
VERSION 5.7 ;
BUSBITCHARS "[]" ;
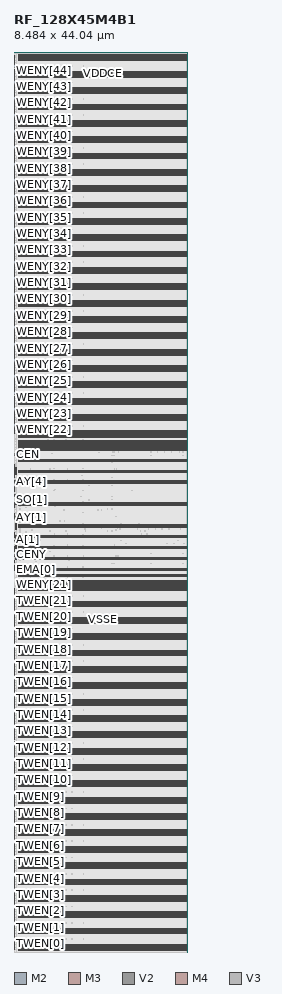
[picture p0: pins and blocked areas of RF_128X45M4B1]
MACRO RF_128X45M4B1
	FOREIGN RF_128X45M4B1 0 0 ;
	SYMMETRY X Y ;
	SIZE 8.484 BY 44.04 ;
	CLASS BLOCK ;
	PIN AY[0]
		USE SIGNAL ;
		DIRECTION OUTPUT ;
		SHAPE ABUTMENT ;
		PORT
			 LAYER M2 ;
			RECT 0.0714 20.819 0.1097 20.8571 ;
			 LAYER M3 ;
			RECT 0.0714 20.819 0.1097 20.9206 ;
			 LAYER V2 ;
			RECT 0.0831 20.8313 0.098 20.844 ;
		END

		ANTENNADIFFAREA 0.00197037 ;
		ANTENNAPARTIALMETALAREA 0.00198 ;
	END AY[0]

	PIN AY[1]
		USE SIGNAL ;
		DIRECTION OUTPUT ;
		SHAPE ABUTMENT ;
		PORT
			 LAYER M2 ;
			RECT 0.0098 21.2762 0.0481 21.3143 ;
			 LAYER M3 ;
			RECT 0.0098 21.2127 0.0481 21.3143 ;
			 LAYER V2 ;
			RECT 0.0215 21.2885 0.0364 21.3012 ;
		END

		ANTENNADIFFAREA 0.00197037 ;
		ANTENNAPARTIALMETALAREA 0.00198 ;
	END AY[1]

	PIN AY[2]
		USE SIGNAL ;
		DIRECTION OUTPUT ;
		SHAPE ABUTMENT ;
		PORT
			 LAYER M2 ;
			RECT 0.0714 21.8857 0.1097 21.9238 ;
			 LAYER M3 ;
			RECT 0.0714 21.8857 0.1097 21.9873 ;
			 LAYER V2 ;
			RECT 0.0831 21.898 0.098 21.9107 ;
		END

		ANTENNADIFFAREA 0.00197037 ;
		ANTENNAPARTIALMETALAREA 0.00198 ;
	END AY[2]

	PIN AY[3]
		USE SIGNAL ;
		DIRECTION OUTPUT ;
		SHAPE ABUTMENT ;
		PORT
			 LAYER M2 ;
			RECT 0.0098 22.3429 0.0481 22.381 ;
			 LAYER M3 ;
			RECT 0.0098 22.2794 0.0481 22.381 ;
			 LAYER V2 ;
			RECT 0.0215 22.3552 0.0364 22.3679 ;
		END

		ANTENNADIFFAREA 0.00197037 ;
		ANTENNAPARTIALMETALAREA 0.00198 ;
	END AY[3]

	PIN AY[4]
		USE SIGNAL ;
		DIRECTION OUTPUT ;
		SHAPE ABUTMENT ;
		PORT
			 LAYER M2 ;
			RECT 0.0714 22.9524 0.1097 22.9905 ;
			 LAYER M3 ;
			RECT 0.0714 22.9524 0.1097 23.054 ;
			 LAYER V2 ;
			RECT 0.0831 22.9647 0.098 22.9774 ;
		END

		ANTENNADIFFAREA 0.00197037 ;
		ANTENNAPARTIALMETALAREA 0.00198 ;
	END AY[4]

	PIN AY[5]
		USE SIGNAL ;
		DIRECTION OUTPUT ;
		SHAPE ABUTMENT ;
		PORT
			 LAYER M2 ;
			RECT 0.0714 23.6127 0.1097 23.6508 ;
			 LAYER M3 ;
			RECT 0.0714 23.6127 0.1097 23.7143 ;
			 LAYER V2 ;
			RECT 0.0831 23.625 0.098 23.6377 ;
		END

		ANTENNADIFFAREA 0.00197037 ;
		ANTENNAPARTIALMETALAREA 0.00198 ;
	END AY[5]

	PIN AY[6]
		USE SIGNAL ;
		DIRECTION OUTPUT ;
		SHAPE ABUTMENT ;
		PORT
			 LAYER M2 ;
			RECT 0.0098 23.4095 0.0481 23.4476 ;
			 LAYER M3 ;
			RECT 0.0098 23.346 0.0481 23.4476 ;
			 LAYER V2 ;
			RECT 0.0215 23.4218 0.0364 23.4345 ;
		END

		ANTENNADIFFAREA 0.00197037 ;
		ANTENNAPARTIALMETALAREA 0.00198 ;
	END AY[6]

	PIN A[0]
		USE SIGNAL ;
		DIRECTION INPUT ;
		SHAPE ABUTMENT ;
		PORT
			 LAYER M2 ;
			RECT 0.0714 20.946 0.1097 20.9841 ;
			 LAYER M3 ;
			RECT 0.0714 20.946 0.1097 21.0476 ;
			 LAYER V2 ;
			RECT 0.0831 20.9583 0.098 20.971 ;
		END

		ANTENNAGATEAREA 0.00028148 ;
		ANTENNADIFFAREA 0.00197037 ;
		ANTENNAPARTIALMETALAREA 0.00198 ;
	END A[0]

	PIN A[1]
		USE SIGNAL ;
		DIRECTION INPUT ;
		SHAPE ABUTMENT ;
		PORT
			 LAYER M2 ;
			RECT 0.0714 20.146 0.1097 20.1841 ;
			 LAYER M3 ;
			RECT 0.0714 20.146 0.1097 20.2476 ;
			 LAYER V2 ;
			RECT 0.0831 20.1583 0.098 20.171 ;
		END

		ANTENNAGATEAREA 0.00028148 ;
		ANTENNADIFFAREA 0.00197037 ;
		ANTENNAPARTIALMETALAREA 0.00198 ;
	END A[1]

	PIN A[2]
		USE SIGNAL ;
		DIRECTION INPUT ;
		SHAPE ABUTMENT ;
		PORT
			 LAYER M2 ;
			RECT 0.0098 21.9492 0.0481 21.9873 ;
			 LAYER M3 ;
			RECT 0.0098 21.8857 0.0481 21.9873 ;
			 LAYER V2 ;
			RECT 0.0215 21.9615 0.0364 21.9742 ;
		END

		ANTENNAGATEAREA 0.00028148 ;
		ANTENNADIFFAREA 0.00197037 ;
		ANTENNAPARTIALMETALAREA 0.00198 ;
	END A[2]

	PIN A[3]
		USE SIGNAL ;
		DIRECTION INPUT ;
		SHAPE ABUTMENT ;
		PORT
			 LAYER M2 ;
			RECT 0.0098 22.7492 0.0481 22.7873 ;
			 LAYER M3 ;
			RECT 0.0098 22.6857 0.0481 22.7873 ;
			 LAYER V2 ;
			RECT 0.0215 22.7615 0.0364 22.7742 ;
		END

		ANTENNAGATEAREA 0.00028148 ;
		ANTENNADIFFAREA 0.00197037 ;
		ANTENNAPARTIALMETALAREA 0.00198 ;
	END A[3]

	PIN A[4]
		USE SIGNAL ;
		DIRECTION INPUT ;
		SHAPE ABUTMENT ;
		PORT
			 LAYER M2 ;
			RECT 0.0098 23.0159 0.0481 23.054 ;
			 LAYER M3 ;
			RECT 0.0098 22.9524 0.0481 23.054 ;
			 LAYER V2 ;
			RECT 0.0215 23.0282 0.0364 23.0409 ;
		END

		ANTENNAGATEAREA 0.00028148 ;
		ANTENNADIFFAREA 0.00197037 ;
		ANTENNAPARTIALMETALAREA 0.00198 ;
	END A[4]

	PIN A[5]
		USE SIGNAL ;
		DIRECTION INPUT ;
		SHAPE ABUTMENT ;
		PORT
			 LAYER M2 ;
			RECT 0.0098 23.5365 0.0481 23.5746 ;
			 LAYER M3 ;
			RECT 0.0098 23.473 0.0481 23.5746 ;
			 LAYER V2 ;
			RECT 0.0215 23.5488 0.0364 23.5615 ;
		END

		ANTENNAGATEAREA 0.00028148 ;
		ANTENNADIFFAREA 0.00197037 ;
		ANTENNAPARTIALMETALAREA 0.00198 ;
	END A[5]

	PIN A[6]
		USE SIGNAL ;
		DIRECTION INPUT ;
		SHAPE ABUTMENT ;
		PORT
			 LAYER M2 ;
			RECT 0.0098 23.6762 0.0481 23.7143 ;
			 LAYER M3 ;
			RECT 0.0098 23.6127 0.0481 23.7143 ;
			 LAYER V2 ;
			RECT 0.0215 23.6885 0.0364 23.7012 ;
		END

		ANTENNAGATEAREA 0.00028148 ;
		ANTENNADIFFAREA 0.00197037 ;
		ANTENNAPARTIALMETALAREA 0.00198 ;
	END A[6]

	PIN CEN
		USE SIGNAL ;
		DIRECTION INPUT ;
		SHAPE ABUTMENT ;
		PORT
			 LAYER M2 ;
			RECT 0.0098 24.3619 0.0481 24.4 ;
			 LAYER M3 ;
			RECT 0.0098 24.2984 0.0481 24.4 ;
			 LAYER V2 ;
			RECT 0.0215 24.3742 0.0364 24.3869 ;
		END

		ANTENNAGATEAREA 0.00028148 ;
		ANTENNADIFFAREA 0.00197037 ;
		ANTENNAPARTIALMETALAREA 0.00198 ;
	END CEN

	PIN CENY
		USE SIGNAL ;
		DIRECTION OUTPUT ;
		SHAPE ABUTMENT ;
		PORT
			 LAYER M2 ;
			RECT 0.0714 19.7524 0.1097 19.7905 ;
			 LAYER M3 ;
			RECT 0.0714 19.7524 0.1097 19.854 ;
			 LAYER V2 ;
			RECT 0.0831 19.7647 0.098 19.7774 ;
		END

		ANTENNADIFFAREA 0.00197037 ;
		ANTENNAPARTIALMETALAREA 0.00198 ;
	END CENY

	PIN CLK
		USE SIGNAL ;
		DIRECTION INPUT ;
		SHAPE ABUTMENT ;
		PORT
			 LAYER M2 ;
			RECT 0.0098 21.4032 0.0481 21.4413 ;
			 LAYER M3 ;
			RECT 0.0098 21.3397 0.0481 21.4413 ;
			 LAYER V2 ;
			RECT 0.0215 21.4155 0.0364 21.4282 ;
		END

		ANTENNAGATEAREA 0.00028148 ;
		ANTENNADIFFAREA 0.00197037 ;
		ANTENNAPARTIALMETALAREA 0.00198 ;
	END CLK

	PIN DFTRAMBYP
		USE SIGNAL ;
		DIRECTION INPUT ;
		SHAPE ABUTMENT ;
		PORT
			 LAYER M2 ;
			RECT 0.0098 19.6127 0.0481 19.7143 ;
			 LAYER M3 ;
			RECT 0.0098 19.6127 0.0481 19.7143 ;
			 LAYER V2 ;
			RECT 0.021 19.6885 0.0359 19.7012 ;
		END

		ANTENNAGATEAREA 0.00028148 ;
		ANTENNADIFFAREA 0.00197037 ;
		ANTENNAPARTIALMETALAREA 0.00198 ;
	END DFTRAMBYP

	PIN D[0]
		USE SIGNAL ;
		DIRECTION INPUT ;
		SHAPE ABUTMENT ;
		PORT
			 LAYER M2 ;
			RECT 0.0098 0.2413 0.0481 0.3429 ;
			 LAYER M3 ;
			RECT 0.0098 0.2413 0.0481 0.3429 ;
			 LAYER V2 ;
			RECT 0.021 0.3171 0.0359 0.3298 ;
		END

		ANTENNAGATEAREA 0.00028148 ;
		ANTENNADIFFAREA 0.00197037 ;
		ANTENNAPARTIALMETALAREA 0.00198 ;
	END D[0]

	PIN D[10]
		USE SIGNAL ;
		DIRECTION INPUT ;
		SHAPE ABUTMENT ;
		PORT
			 LAYER M2 ;
			RECT 0.0098 8.2413 0.0481 8.3429 ;
			 LAYER M3 ;
			RECT 0.0098 8.2413 0.0481 8.3429 ;
			 LAYER V2 ;
			RECT 0.021 8.3171 0.0359 8.3298 ;
		END

		ANTENNAGATEAREA 0.00028148 ;
		ANTENNADIFFAREA 0.00197037 ;
		ANTENNAPARTIALMETALAREA 0.00198 ;
	END D[10]

	PIN D[11]
		USE SIGNAL ;
		DIRECTION INPUT ;
		SHAPE ABUTMENT ;
		PORT
			 LAYER M2 ;
			RECT 0.0098 9.0413 0.0481 9.1429 ;
			 LAYER M3 ;
			RECT 0.0098 9.0413 0.0481 9.1429 ;
			 LAYER V2 ;
			RECT 0.021 9.1171 0.0359 9.1298 ;
		END

		ANTENNAGATEAREA 0.00028148 ;
		ANTENNADIFFAREA 0.00197037 ;
		ANTENNAPARTIALMETALAREA 0.00198 ;
	END D[11]

	PIN D[12]
		USE SIGNAL ;
		DIRECTION INPUT ;
		SHAPE ABUTMENT ;
		PORT
			 LAYER M2 ;
			RECT 0.0098 9.8413 0.0481 9.9429 ;
			 LAYER M3 ;
			RECT 0.0098 9.8413 0.0481 9.9429 ;
			 LAYER V2 ;
			RECT 0.021 9.9171 0.0359 9.9298 ;
		END

		ANTENNAGATEAREA 0.00028148 ;
		ANTENNADIFFAREA 0.00197037 ;
		ANTENNAPARTIALMETALAREA 0.00198 ;
	END D[12]

	PIN D[13]
		USE SIGNAL ;
		DIRECTION INPUT ;
		SHAPE ABUTMENT ;
		PORT
			 LAYER M2 ;
			RECT 0.0098 10.6413 0.0481 10.7429 ;
			 LAYER M3 ;
			RECT 0.0098 10.6413 0.0481 10.7429 ;
			 LAYER V2 ;
			RECT 0.021 10.7171 0.0359 10.7298 ;
		END

		ANTENNAGATEAREA 0.00028148 ;
		ANTENNADIFFAREA 0.00197037 ;
		ANTENNAPARTIALMETALAREA 0.00198 ;
	END D[13]

	PIN D[14]
		USE SIGNAL ;
		DIRECTION INPUT ;
		SHAPE ABUTMENT ;
		PORT
			 LAYER M2 ;
			RECT 0.0098 11.4413 0.0481 11.5429 ;
			 LAYER M3 ;
			RECT 0.0098 11.4413 0.0481 11.5429 ;
			 LAYER V2 ;
			RECT 0.021 11.5171 0.0359 11.5298 ;
		END

		ANTENNAGATEAREA 0.00028148 ;
		ANTENNADIFFAREA 0.00197037 ;
		ANTENNAPARTIALMETALAREA 0.00198 ;
	END D[14]

	PIN D[15]
		USE SIGNAL ;
		DIRECTION INPUT ;
		SHAPE ABUTMENT ;
		PORT
			 LAYER M2 ;
			RECT 0.0098 12.2413 0.0481 12.3429 ;
			 LAYER M3 ;
			RECT 0.0098 12.2413 0.0481 12.3429 ;
			 LAYER V2 ;
			RECT 0.021 12.3171 0.0359 12.3298 ;
		END

		ANTENNAGATEAREA 0.00028148 ;
		ANTENNADIFFAREA 0.00197037 ;
		ANTENNAPARTIALMETALAREA 0.00198 ;
	END D[15]

	PIN D[16]
		USE SIGNAL ;
		DIRECTION INPUT ;
		SHAPE ABUTMENT ;
		PORT
			 LAYER M2 ;
			RECT 0.0098 13.0413 0.0481 13.1429 ;
			 LAYER M3 ;
			RECT 0.0098 13.0413 0.0481 13.1429 ;
			 LAYER V2 ;
			RECT 0.021 13.1171 0.0359 13.1298 ;
		END

		ANTENNAGATEAREA 0.00028148 ;
		ANTENNADIFFAREA 0.00197037 ;
		ANTENNAPARTIALMETALAREA 0.00198 ;
	END D[16]

	PIN D[17]
		USE SIGNAL ;
		DIRECTION INPUT ;
		SHAPE ABUTMENT ;
		PORT
			 LAYER M2 ;
			RECT 0.0098 13.8413 0.0481 13.9429 ;
			 LAYER M3 ;
			RECT 0.0098 13.8413 0.0481 13.9429 ;
			 LAYER V2 ;
			RECT 0.021 13.9171 0.0359 13.9298 ;
		END

		ANTENNAGATEAREA 0.00028148 ;
		ANTENNADIFFAREA 0.00197037 ;
		ANTENNAPARTIALMETALAREA 0.00198 ;
	END D[17]

	PIN D[18]
		USE SIGNAL ;
		DIRECTION INPUT ;
		SHAPE ABUTMENT ;
		PORT
			 LAYER M2 ;
			RECT 0.0098 14.6413 0.0481 14.7429 ;
			 LAYER M3 ;
			RECT 0.0098 14.6413 0.0481 14.7429 ;
			 LAYER V2 ;
			RECT 0.021 14.7171 0.0359 14.7298 ;
		END

		ANTENNAGATEAREA 0.00028148 ;
		ANTENNADIFFAREA 0.00197037 ;
		ANTENNAPARTIALMETALAREA 0.00198 ;
	END D[18]

	PIN D[19]
		USE SIGNAL ;
		DIRECTION INPUT ;
		SHAPE ABUTMENT ;
		PORT
			 LAYER M2 ;
			RECT 0.0098 15.4413 0.0481 15.5429 ;
			 LAYER M3 ;
			RECT 0.0098 15.4413 0.0481 15.5429 ;
			 LAYER V2 ;
			RECT 0.021 15.5171 0.0359 15.5298 ;
		END

		ANTENNAGATEAREA 0.00028148 ;
		ANTENNADIFFAREA 0.00197037 ;
		ANTENNAPARTIALMETALAREA 0.00198 ;
	END D[19]

	PIN D[1]
		USE SIGNAL ;
		DIRECTION INPUT ;
		SHAPE ABUTMENT ;
		PORT
			 LAYER M2 ;
			RECT 0.0098 1.0413 0.0481 1.1429 ;
			 LAYER M3 ;
			RECT 0.0098 1.0413 0.0481 1.1429 ;
			 LAYER V2 ;
			RECT 0.021 1.1171 0.0359 1.1298 ;
		END

		ANTENNAGATEAREA 0.00028148 ;
		ANTENNADIFFAREA 0.00197037 ;
		ANTENNAPARTIALMETALAREA 0.00198 ;
	END D[1]

	PIN D[20]
		USE SIGNAL ;
		DIRECTION INPUT ;
		SHAPE ABUTMENT ;
		PORT
			 LAYER M2 ;
			RECT 0.0098 16.2413 0.0481 16.3429 ;
			 LAYER M3 ;
			RECT 0.0098 16.2413 0.0481 16.3429 ;
			 LAYER V2 ;
			RECT 0.021 16.3171 0.0359 16.3298 ;
		END

		ANTENNAGATEAREA 0.00028148 ;
		ANTENNADIFFAREA 0.00197037 ;
		ANTENNAPARTIALMETALAREA 0.00198 ;
	END D[20]

	PIN D[21]
		USE SIGNAL ;
		DIRECTION INPUT ;
		SHAPE ABUTMENT ;
		PORT
			 LAYER M2 ;
			RECT 0.0098 17.0413 0.0481 17.1429 ;
			 LAYER M3 ;
			RECT 0.0098 17.0413 0.0481 17.1429 ;
			 LAYER V2 ;
			RECT 0.021 17.1171 0.0359 17.1298 ;
		END

		ANTENNAGATEAREA 0.00028148 ;
		ANTENNADIFFAREA 0.00197037 ;
		ANTENNAPARTIALMETALAREA 0.00198 ;
	END D[21]

	PIN D[22]
		USE SIGNAL ;
		DIRECTION INPUT ;
		SHAPE ABUTMENT ;
		PORT
			 LAYER M2 ;
			RECT 0.0098 26.0381 0.0481 26.1397 ;
			 LAYER M3 ;
			RECT 0.0098 26.0381 0.0481 26.1397 ;
			 LAYER V2 ;
			RECT 0.021 26.0512 0.0359 26.0639 ;
		END

		ANTENNAGATEAREA 0.00028148 ;
		ANTENNADIFFAREA 0.00197037 ;
		ANTENNAPARTIALMETALAREA 0.00198 ;
	END D[22]

	PIN D[23]
		USE SIGNAL ;
		DIRECTION INPUT ;
		SHAPE ABUTMENT ;
		PORT
			 LAYER M2 ;
			RECT 0.0098 26.8381 0.0481 26.9397 ;
			 LAYER M3 ;
			RECT 0.0098 26.8381 0.0481 26.9397 ;
			 LAYER V2 ;
			RECT 0.021 26.8512 0.0359 26.8639 ;
		END

		ANTENNAGATEAREA 0.00028148 ;
		ANTENNADIFFAREA 0.00197037 ;
		ANTENNAPARTIALMETALAREA 0.00198 ;
	END D[23]

	PIN D[24]
		USE SIGNAL ;
		DIRECTION INPUT ;
		SHAPE ABUTMENT ;
		PORT
			 LAYER M2 ;
			RECT 0.0098 27.6381 0.0481 27.7397 ;
			 LAYER M3 ;
			RECT 0.0098 27.6381 0.0481 27.7397 ;
			 LAYER V2 ;
			RECT 0.021 27.6512 0.0359 27.6639 ;
		END

		ANTENNAGATEAREA 0.00028148 ;
		ANTENNADIFFAREA 0.00197037 ;
		ANTENNAPARTIALMETALAREA 0.00198 ;
	END D[24]

	PIN D[25]
		USE SIGNAL ;
		DIRECTION INPUT ;
		SHAPE ABUTMENT ;
		PORT
			 LAYER M2 ;
			RECT 0.0098 28.4381 0.0481 28.5397 ;
			 LAYER M3 ;
			RECT 0.0098 28.4381 0.0481 28.5397 ;
			 LAYER V2 ;
			RECT 0.021 28.4512 0.0359 28.4639 ;
		END

		ANTENNAGATEAREA 0.00028148 ;
		ANTENNADIFFAREA 0.00197037 ;
		ANTENNAPARTIALMETALAREA 0.00198 ;
	END D[25]

	PIN D[26]
		USE SIGNAL ;
		DIRECTION INPUT ;
		SHAPE ABUTMENT ;
		PORT
			 LAYER M2 ;
			RECT 0.0098 29.2381 0.0481 29.3397 ;
			 LAYER M3 ;
			RECT 0.0098 29.2381 0.0481 29.3397 ;
			 LAYER V2 ;
			RECT 0.021 29.2512 0.0359 29.2639 ;
		END

		ANTENNAGATEAREA 0.00028148 ;
		ANTENNADIFFAREA 0.00197037 ;
		ANTENNAPARTIALMETALAREA 0.00198 ;
	END D[26]

	PIN D[27]
		USE SIGNAL ;
		DIRECTION INPUT ;
		SHAPE ABUTMENT ;
		PORT
			 LAYER M2 ;
			RECT 0.0098 30.0381 0.0481 30.1397 ;
			 LAYER M3 ;
			RECT 0.0098 30.0381 0.0481 30.1397 ;
			 LAYER V2 ;
			RECT 0.021 30.0512 0.0359 30.0639 ;
		END

		ANTENNAGATEAREA 0.00028148 ;
		ANTENNADIFFAREA 0.00197037 ;
		ANTENNAPARTIALMETALAREA 0.00198 ;
	END D[27]

	PIN D[28]
		USE SIGNAL ;
		DIRECTION INPUT ;
		SHAPE ABUTMENT ;
		PORT
			 LAYER M2 ;
			RECT 0.0098 30.8381 0.0481 30.9397 ;
			 LAYER M3 ;
			RECT 0.0098 30.8381 0.0481 30.9397 ;
			 LAYER V2 ;
			RECT 0.021 30.8512 0.0359 30.8639 ;
		END

		ANTENNAGATEAREA 0.00028148 ;
		ANTENNADIFFAREA 0.00197037 ;
		ANTENNAPARTIALMETALAREA 0.00198 ;
	END D[28]

	PIN D[29]
		USE SIGNAL ;
		DIRECTION INPUT ;
		SHAPE ABUTMENT ;
		PORT
			 LAYER M2 ;
			RECT 0.0098 31.6381 0.0481 31.7397 ;
			 LAYER M3 ;
			RECT 0.0098 31.6381 0.0481 31.7397 ;
			 LAYER V2 ;
			RECT 0.021 31.6512 0.0359 31.6639 ;
		END

		ANTENNAGATEAREA 0.00028148 ;
		ANTENNADIFFAREA 0.00197037 ;
		ANTENNAPARTIALMETALAREA 0.00198 ;
	END D[29]

	PIN D[2]
		USE SIGNAL ;
		DIRECTION INPUT ;
		SHAPE ABUTMENT ;
		PORT
			 LAYER M2 ;
			RECT 0.0098 1.8413 0.0481 1.9429 ;
			 LAYER M3 ;
			RECT 0.0098 1.8413 0.0481 1.9429 ;
			 LAYER V2 ;
			RECT 0.021 1.9171 0.0359 1.9298 ;
		END

		ANTENNAGATEAREA 0.00028148 ;
		ANTENNADIFFAREA 0.00197037 ;
		ANTENNAPARTIALMETALAREA 0.00198 ;
	END D[2]

	PIN D[30]
		USE SIGNAL ;
		DIRECTION INPUT ;
		SHAPE ABUTMENT ;
		PORT
			 LAYER M2 ;
			RECT 0.0098 32.4381 0.0481 32.5397 ;
			 LAYER M3 ;
			RECT 0.0098 32.4381 0.0481 32.5397 ;
			 LAYER V2 ;
			RECT 0.021 32.4512 0.0359 32.4639 ;
		END

		ANTENNAGATEAREA 0.00028148 ;
		ANTENNADIFFAREA 0.00197037 ;
		ANTENNAPARTIALMETALAREA 0.00198 ;
	END D[30]

	PIN D[31]
		USE SIGNAL ;
		DIRECTION INPUT ;
		SHAPE ABUTMENT ;
		PORT
			 LAYER M2 ;
			RECT 0.0098 33.2381 0.0481 33.3397 ;
			 LAYER M3 ;
			RECT 0.0098 33.2381 0.0481 33.3397 ;
			 LAYER V2 ;
			RECT 0.021 33.2512 0.0359 33.2639 ;
		END

		ANTENNAGATEAREA 0.00028148 ;
		ANTENNADIFFAREA 0.00197037 ;
		ANTENNAPARTIALMETALAREA 0.00198 ;
	END D[31]

	PIN D[32]
		USE SIGNAL ;
		DIRECTION INPUT ;
		SHAPE ABUTMENT ;
		PORT
			 LAYER M2 ;
			RECT 0.0098 34.0381 0.0481 34.1397 ;
			 LAYER M3 ;
			RECT 0.0098 34.0381 0.0481 34.1397 ;
			 LAYER V2 ;
			RECT 0.021 34.0512 0.0359 34.0639 ;
		END

		ANTENNAGATEAREA 0.00028148 ;
		ANTENNADIFFAREA 0.00197037 ;
		ANTENNAPARTIALMETALAREA 0.00198 ;
	END D[32]

	PIN D[33]
		USE SIGNAL ;
		DIRECTION INPUT ;
		SHAPE ABUTMENT ;
		PORT
			 LAYER M2 ;
			RECT 0.0098 34.8381 0.0481 34.9397 ;
			 LAYER M3 ;
			RECT 0.0098 34.8381 0.0481 34.9397 ;
			 LAYER V2 ;
			RECT 0.021 34.8512 0.0359 34.8639 ;
		END

		ANTENNAGATEAREA 0.00028148 ;
		ANTENNADIFFAREA 0.00197037 ;
		ANTENNAPARTIALMETALAREA 0.00198 ;
	END D[33]

	PIN D[34]
		USE SIGNAL ;
		DIRECTION INPUT ;
		SHAPE ABUTMENT ;
		PORT
			 LAYER M2 ;
			RECT 0.0098 35.6381 0.0481 35.7397 ;
			 LAYER M3 ;
			RECT 0.0098 35.6381 0.0481 35.7397 ;
			 LAYER V2 ;
			RECT 0.021 35.6512 0.0359 35.6639 ;
		END

		ANTENNAGATEAREA 0.00028148 ;
		ANTENNADIFFAREA 0.00197037 ;
		ANTENNAPARTIALMETALAREA 0.00198 ;
	END D[34]

	PIN D[35]
		USE SIGNAL ;
		DIRECTION INPUT ;
		SHAPE ABUTMENT ;
		PORT
			 LAYER M2 ;
			RECT 0.0098 36.4381 0.0481 36.5397 ;
			 LAYER M3 ;
			RECT 0.0098 36.4381 0.0481 36.5397 ;
			 LAYER V2 ;
			RECT 0.021 36.4512 0.0359 36.4639 ;
		END

		ANTENNAGATEAREA 0.00028148 ;
		ANTENNADIFFAREA 0.00197037 ;
		ANTENNAPARTIALMETALAREA 0.00198 ;
	END D[35]

	PIN D[36]
		USE SIGNAL ;
		DIRECTION INPUT ;
		SHAPE ABUTMENT ;
		PORT
			 LAYER M2 ;
			RECT 0.0098 37.2381 0.0481 37.3397 ;
			 LAYER M3 ;
			RECT 0.0098 37.2381 0.0481 37.3397 ;
			 LAYER V2 ;
			RECT 0.021 37.2512 0.0359 37.2639 ;
		END

		ANTENNAGATEAREA 0.00028148 ;
		ANTENNADIFFAREA 0.00197037 ;
		ANTENNAPARTIALMETALAREA 0.00198 ;
	END D[36]

	PIN D[37]
		USE SIGNAL ;
		DIRECTION INPUT ;
		SHAPE ABUTMENT ;
		PORT
			 LAYER M2 ;
			RECT 0.0098 38.0381 0.0481 38.1397 ;
			 LAYER M3 ;
			RECT 0.0098 38.0381 0.0481 38.1397 ;
			 LAYER V2 ;
			RECT 0.021 38.0512 0.0359 38.0639 ;
		END

		ANTENNAGATEAREA 0.00028148 ;
		ANTENNADIFFAREA 0.00197037 ;
		ANTENNAPARTIALMETALAREA 0.00198 ;
	END D[37]

	PIN D[38]
		USE SIGNAL ;
		DIRECTION INPUT ;
		SHAPE ABUTMENT ;
		PORT
			 LAYER M2 ;
			RECT 0.0098 38.8381 0.0481 38.9397 ;
			 LAYER M3 ;
			RECT 0.0098 38.8381 0.0481 38.9397 ;
			 LAYER V2 ;
			RECT 0.021 38.8512 0.0359 38.8639 ;
		END

		ANTENNAGATEAREA 0.00028148 ;
		ANTENNADIFFAREA 0.00197037 ;
		ANTENNAPARTIALMETALAREA 0.00198 ;
	END D[38]

	PIN D[39]
		USE SIGNAL ;
		DIRECTION INPUT ;
		SHAPE ABUTMENT ;
		PORT
			 LAYER M2 ;
			RECT 0.0098 39.6381 0.0481 39.7397 ;
			 LAYER M3 ;
			RECT 0.0098 39.6381 0.0481 39.7397 ;
			 LAYER V2 ;
			RECT 0.021 39.6512 0.0359 39.6639 ;
		END

		ANTENNAGATEAREA 0.00028148 ;
		ANTENNADIFFAREA 0.00197037 ;
		ANTENNAPARTIALMETALAREA 0.00198 ;
	END D[39]

	PIN D[3]
		USE SIGNAL ;
		DIRECTION INPUT ;
		SHAPE ABUTMENT ;
		PORT
			 LAYER M2 ;
			RECT 0.0098 2.6413 0.0481 2.7429 ;
			 LAYER M3 ;
			RECT 0.0098 2.6413 0.0481 2.7429 ;
			 LAYER V2 ;
			RECT 0.021 2.7171 0.0359 2.7298 ;
		END

		ANTENNAGATEAREA 0.00028148 ;
		ANTENNADIFFAREA 0.00197037 ;
		ANTENNAPARTIALMETALAREA 0.00198 ;
	END D[3]

	PIN D[40]
		USE SIGNAL ;
		DIRECTION INPUT ;
		SHAPE ABUTMENT ;
		PORT
			 LAYER M2 ;
			RECT 0.0098 40.4381 0.0481 40.5397 ;
			 LAYER M3 ;
			RECT 0.0098 40.4381 0.0481 40.5397 ;
			 LAYER V2 ;
			RECT 0.021 40.4512 0.0359 40.4639 ;
		END

		ANTENNAGATEAREA 0.00028148 ;
		ANTENNADIFFAREA 0.00197037 ;
		ANTENNAPARTIALMETALAREA 0.00198 ;
	END D[40]

	PIN D[41]
		USE SIGNAL ;
		DIRECTION INPUT ;
		SHAPE ABUTMENT ;
		PORT
			 LAYER M2 ;
			RECT 0.0098 41.2381 0.0481 41.3397 ;
			 LAYER M3 ;
			RECT 0.0098 41.2381 0.0481 41.3397 ;
			 LAYER V2 ;
			RECT 0.021 41.2512 0.0359 41.2639 ;
		END

		ANTENNAGATEAREA 0.00028148 ;
		ANTENNADIFFAREA 0.00197037 ;
		ANTENNAPARTIALMETALAREA 0.00198 ;
	END D[41]

	PIN D[42]
		USE SIGNAL ;
		DIRECTION INPUT ;
		SHAPE ABUTMENT ;
		PORT
			 LAYER M2 ;
			RECT 0.0098 42.0381 0.0481 42.1397 ;
			 LAYER M3 ;
			RECT 0.0098 42.0381 0.0481 42.1397 ;
			 LAYER V2 ;
			RECT 0.021 42.0512 0.0359 42.0639 ;
		END

		ANTENNAGATEAREA 0.00028148 ;
		ANTENNADIFFAREA 0.00197037 ;
		ANTENNAPARTIALMETALAREA 0.00198 ;
	END D[42]

	PIN D[43]
		USE SIGNAL ;
		DIRECTION INPUT ;
		SHAPE ABUTMENT ;
		PORT
			 LAYER M2 ;
			RECT 0.0098 42.8381 0.0481 42.9397 ;
			 LAYER M3 ;
			RECT 0.0098 42.8381 0.0481 42.9397 ;
			 LAYER V2 ;
			RECT 0.021 42.8512 0.0359 42.8639 ;
		END

		ANTENNAGATEAREA 0.00028148 ;
		ANTENNADIFFAREA 0.00197037 ;
		ANTENNAPARTIALMETALAREA 0.00198 ;
	END D[43]

	PIN D[44]
		USE SIGNAL ;
		DIRECTION INPUT ;
		SHAPE ABUTMENT ;
		PORT
			 LAYER M2 ;
			RECT 0.0098 43.6381 0.0481 43.7397 ;
			 LAYER M3 ;
			RECT 0.0098 43.6381 0.0481 43.7397 ;
			 LAYER V2 ;
			RECT 0.021 43.6512 0.0359 43.6639 ;
		END

		ANTENNAGATEAREA 0.00028148 ;
		ANTENNADIFFAREA 0.00197037 ;
		ANTENNAPARTIALMETALAREA 0.00198 ;
	END D[44]

	PIN D[4]
		USE SIGNAL ;
		DIRECTION INPUT ;
		SHAPE ABUTMENT ;
		PORT
			 LAYER M2 ;
			RECT 0.0098 3.4413 0.0481 3.5429 ;
			 LAYER M3 ;
			RECT 0.0098 3.4413 0.0481 3.5429 ;
			 LAYER V2 ;
			RECT 0.021 3.5171 0.0359 3.5298 ;
		END

		ANTENNAGATEAREA 0.00028148 ;
		ANTENNADIFFAREA 0.00197037 ;
		ANTENNAPARTIALMETALAREA 0.00198 ;
	END D[4]

	PIN D[5]
		USE SIGNAL ;
		DIRECTION INPUT ;
		SHAPE ABUTMENT ;
		PORT
			 LAYER M2 ;
			RECT 0.0098 4.2413 0.0481 4.3429 ;
			 LAYER M3 ;
			RECT 0.0098 4.2413 0.0481 4.3429 ;
			 LAYER V2 ;
			RECT 0.021 4.3171 0.0359 4.3298 ;
		END

		ANTENNAGATEAREA 0.00028148 ;
		ANTENNADIFFAREA 0.00197037 ;
		ANTENNAPARTIALMETALAREA 0.00198 ;
	END D[5]

	PIN D[6]
		USE SIGNAL ;
		DIRECTION INPUT ;
		SHAPE ABUTMENT ;
		PORT
			 LAYER M2 ;
			RECT 0.0098 5.0413 0.0481 5.1429 ;
			 LAYER M3 ;
			RECT 0.0098 5.0413 0.0481 5.1429 ;
			 LAYER V2 ;
			RECT 0.021 5.1171 0.0359 5.1298 ;
		END

		ANTENNAGATEAREA 0.00028148 ;
		ANTENNADIFFAREA 0.00197037 ;
		ANTENNAPARTIALMETALAREA 0.00198 ;
	END D[6]

	PIN D[7]
		USE SIGNAL ;
		DIRECTION INPUT ;
		SHAPE ABUTMENT ;
		PORT
			 LAYER M2 ;
			RECT 0.0098 5.8413 0.0481 5.9429 ;
			 LAYER M3 ;
			RECT 0.0098 5.8413 0.0481 5.9429 ;
			 LAYER V2 ;
			RECT 0.021 5.9171 0.0359 5.9298 ;
		END

		ANTENNAGATEAREA 0.00028148 ;
		ANTENNADIFFAREA 0.00197037 ;
		ANTENNAPARTIALMETALAREA 0.00198 ;
	END D[7]

	PIN D[8]
		USE SIGNAL ;
		DIRECTION INPUT ;
		SHAPE ABUTMENT ;
		PORT
			 LAYER M2 ;
			RECT 0.0098 6.6413 0.0481 6.7429 ;
			 LAYER M3 ;
			RECT 0.0098 6.6413 0.0481 6.7429 ;
			 LAYER V2 ;
			RECT 0.021 6.7171 0.0359 6.7298 ;
		END

		ANTENNAGATEAREA 0.00028148 ;
		ANTENNADIFFAREA 0.00197037 ;
		ANTENNAPARTIALMETALAREA 0.00198 ;
	END D[8]

	PIN D[9]
		USE SIGNAL ;
		DIRECTION INPUT ;
		SHAPE ABUTMENT ;
		PORT
			 LAYER M2 ;
			RECT 0.0098 7.4413 0.0481 7.5429 ;
			 LAYER M3 ;
			RECT 0.0098 7.4413 0.0481 7.5429 ;
			 LAYER V2 ;
			RECT 0.021 7.5171 0.0359 7.5298 ;
		END

		ANTENNAGATEAREA 0.00028148 ;
		ANTENNADIFFAREA 0.00197037 ;
		ANTENNAPARTIALMETALAREA 0.00198 ;
	END D[9]

	PIN EMAS
		USE SIGNAL ;
		DIRECTION INPUT ;
		SHAPE ABUTMENT ;
		PORT
			 LAYER M2 ;
			RECT 0.0714 20.2857 0.1097 20.3238 ;
			 LAYER M3 ;
			RECT 0.0714 20.2857 0.1097 20.3873 ;
			 LAYER V2 ;
			RECT 0.0831 20.298 0.098 20.3107 ;
		END

		ANTENNAGATEAREA 0.00028148 ;
		ANTENNADIFFAREA 0.00197037 ;
		ANTENNAPARTIALMETALAREA 0.00198 ;
	END EMAS

	PIN EMAW[0]
		USE SIGNAL ;
		DIRECTION INPUT ;
		SHAPE ABUTMENT ;
		PORT
			 LAYER M2 ;
			RECT 0.0098 19.0794 0.0481 19.181 ;
			 LAYER M3 ;
			RECT 0.0098 19.0794 0.0481 19.181 ;
			 LAYER V2 ;
			RECT 0.021 19.0925 0.0359 19.1052 ;
		END

		ANTENNAGATEAREA 0.00028148 ;
		ANTENNADIFFAREA 0.00197037 ;
		ANTENNAPARTIALMETALAREA 0.00198 ;
	END EMAW[0]

	PIN EMAW[1]
		USE SIGNAL ;
		DIRECTION INPUT ;
		SHAPE ABUTMENT ;
		PORT
			 LAYER M2 ;
			RECT 0.0714 19.219 0.1097 19.2571 ;
			 LAYER M3 ;
			RECT 0.0714 19.219 0.1097 19.3206 ;
			 LAYER V2 ;
			RECT 0.0831 19.2313 0.098 19.244 ;
		END

		ANTENNAGATEAREA 0.00028148 ;
		ANTENNADIFFAREA 0.00197037 ;
		ANTENNAPARTIALMETALAREA 0.00198 ;
	END EMAW[1]

	PIN EMA[0]
		USE SIGNAL ;
		DIRECTION INPUT ;
		SHAPE ABUTMENT ;
		PORT
			 LAYER M2 ;
			RECT 0.0098 18.6857 0.0481 18.7873 ;
			 LAYER M3 ;
			RECT 0.0098 18.6857 0.0481 18.7873 ;
			 LAYER V2 ;
			RECT 0.021 18.6988 0.0359 18.7115 ;
		END

		ANTENNAGATEAREA 0.00028148 ;
		ANTENNADIFFAREA 0.00197037 ;
		ANTENNAPARTIALMETALAREA 0.00198 ;
	END EMA[0]

	PIN EMA[1]
		USE SIGNAL ;
		DIRECTION INPUT ;
		SHAPE ABUTMENT ;
		PORT
			 LAYER M2 ;
			RECT 0.0098 18.8127 0.0481 18.9143 ;
			 LAYER M3 ;
			RECT 0.0098 18.8127 0.0481 18.9143 ;
			 LAYER V2 ;
			RECT 0.021 18.8885 0.0359 18.9012 ;
		END

		ANTENNAGATEAREA 0.00028148 ;
		ANTENNADIFFAREA 0.00197037 ;
		ANTENNAPARTIALMETALAREA 0.00198 ;
	END EMA[1]

	PIN EMA[2]
		USE SIGNAL ;
		DIRECTION INPUT ;
		SHAPE ABUTMENT ;
		PORT
			 LAYER M2 ;
			RECT 0.0098 20.0825 0.0481 20.1206 ;
			 LAYER M3 ;
			RECT 0.0098 20.019 0.0481 20.1206 ;
			 LAYER V2 ;
			RECT 0.0215 20.0948 0.0364 20.1075 ;
		END

		ANTENNAGATEAREA 0.00028148 ;
		ANTENNADIFFAREA 0.00197037 ;
		ANTENNAPARTIALMETALAREA 0.00198 ;
	END EMA[2]

	PIN GWEN
		USE SIGNAL ;
		DIRECTION INPUT ;
		SHAPE ABUTMENT ;
		PORT
			 LAYER M2 ;
			RECT 0.0098 19.8159 0.0481 19.854 ;
			 LAYER M3 ;
			RECT 0.0098 19.7524 0.0481 19.854 ;
			 LAYER V2 ;
			RECT 0.0215 19.8282 0.0364 19.8409 ;
		END

		ANTENNAGATEAREA 0.00028148 ;
		ANTENNADIFFAREA 0.00197037 ;
		ANTENNAPARTIALMETALAREA 0.00198 ;
	END GWEN

	PIN GWENY
		USE SIGNAL ;
		DIRECTION OUTPUT ;
		SHAPE ABUTMENT ;
		PORT
			 LAYER M2 ;
			RECT 0.0098 20.3492 0.0481 20.3873 ;
			 LAYER M3 ;
			RECT 0.0098 20.2857 0.0481 20.3873 ;
			 LAYER V2 ;
			RECT 0.0215 20.3615 0.0364 20.3742 ;
		END

		ANTENNADIFFAREA 0.00197037 ;
		ANTENNAPARTIALMETALAREA 0.00198 ;
	END GWENY

	PIN Q[0]
		USE SIGNAL ;
		DIRECTION OUTPUT ;
		SHAPE ABUTMENT ;
		PORT
			 LAYER M2 ;
			RECT 0.0098 0.6222 0.0481 0.7238 ;
			 LAYER M3 ;
			RECT 0.0098 0.6222 0.0481 0.7238 ;
			 LAYER V2 ;
			RECT 0.021 0.6353 0.0359 0.648 ;
		END

		ANTENNADIFFAREA 0.00197037 ;
		ANTENNAPARTIALMETALAREA 0.00198 ;
	END Q[0]

	PIN Q[10]
		USE SIGNAL ;
		DIRECTION OUTPUT ;
		SHAPE ABUTMENT ;
		PORT
			 LAYER M2 ;
			RECT 0.0098 8.6222 0.0481 8.7238 ;
			 LAYER M3 ;
			RECT 0.0098 8.6222 0.0481 8.7238 ;
			 LAYER V2 ;
			RECT 0.021 8.6353 0.0359 8.648 ;
		END

		ANTENNADIFFAREA 0.00197037 ;
		ANTENNAPARTIALMETALAREA 0.00198 ;
	END Q[10]

	PIN Q[11]
		USE SIGNAL ;
		DIRECTION OUTPUT ;
		SHAPE ABUTMENT ;
		PORT
			 LAYER M2 ;
			RECT 0.0098 9.4222 0.0481 9.5238 ;
			 LAYER M3 ;
			RECT 0.0098 9.4222 0.0481 9.5238 ;
			 LAYER V2 ;
			RECT 0.021 9.4353 0.0359 9.448 ;
		END

		ANTENNADIFFAREA 0.00197037 ;
		ANTENNAPARTIALMETALAREA 0.00198 ;
	END Q[11]

	PIN Q[12]
		USE SIGNAL ;
		DIRECTION OUTPUT ;
		SHAPE ABUTMENT ;
		PORT
			 LAYER M2 ;
			RECT 0.0098 10.2222 0.0481 10.3238 ;
			 LAYER M3 ;
			RECT 0.0098 10.2222 0.0481 10.3238 ;
			 LAYER V2 ;
			RECT 0.021 10.2353 0.0359 10.248 ;
		END

		ANTENNADIFFAREA 0.00197037 ;
		ANTENNAPARTIALMETALAREA 0.00198 ;
	END Q[12]

	PIN Q[13]
		USE SIGNAL ;
		DIRECTION OUTPUT ;
		SHAPE ABUTMENT ;
		PORT
			 LAYER M2 ;
			RECT 0.0098 11.0222 0.0481 11.1238 ;
			 LAYER M3 ;
			RECT 0.0098 11.0222 0.0481 11.1238 ;
			 LAYER V2 ;
			RECT 0.021 11.0353 0.0359 11.048 ;
		END

		ANTENNADIFFAREA 0.00197037 ;
		ANTENNAPARTIALMETALAREA 0.00198 ;
	END Q[13]

	PIN Q[14]
		USE SIGNAL ;
		DIRECTION OUTPUT ;
		SHAPE ABUTMENT ;
		PORT
			 LAYER M2 ;
			RECT 0.0098 11.8222 0.0481 11.9238 ;
			 LAYER M3 ;
			RECT 0.0098 11.8222 0.0481 11.9238 ;
			 LAYER V2 ;
			RECT 0.021 11.8353 0.0359 11.848 ;
		END

		ANTENNADIFFAREA 0.00197037 ;
		ANTENNAPARTIALMETALAREA 0.00198 ;
	END Q[14]

	PIN Q[15]
		USE SIGNAL ;
		DIRECTION OUTPUT ;
		SHAPE ABUTMENT ;
		PORT
			 LAYER M2 ;
			RECT 0.0098 12.6222 0.0481 12.7238 ;
			 LAYER M3 ;
			RECT 0.0098 12.6222 0.0481 12.7238 ;
			 LAYER V2 ;
			RECT 0.021 12.6353 0.0359 12.648 ;
		END

		ANTENNADIFFAREA 0.00197037 ;
		ANTENNAPARTIALMETALAREA 0.00198 ;
	END Q[15]

	PIN Q[16]
		USE SIGNAL ;
		DIRECTION OUTPUT ;
		SHAPE ABUTMENT ;
		PORT
			 LAYER M2 ;
			RECT 0.0098 13.4222 0.0481 13.5238 ;
			 LAYER M3 ;
			RECT 0.0098 13.4222 0.0481 13.5238 ;
			 LAYER V2 ;
			RECT 0.021 13.4353 0.0359 13.448 ;
		END

		ANTENNADIFFAREA 0.00197037 ;
		ANTENNAPARTIALMETALAREA 0.00198 ;
	END Q[16]

	PIN Q[17]
		USE SIGNAL ;
		DIRECTION OUTPUT ;
		SHAPE ABUTMENT ;
		PORT
			 LAYER M2 ;
			RECT 0.0098 14.2222 0.0481 14.3238 ;
			 LAYER M3 ;
			RECT 0.0098 14.2222 0.0481 14.3238 ;
			 LAYER V2 ;
			RECT 0.021 14.2353 0.0359 14.248 ;
		END

		ANTENNADIFFAREA 0.00197037 ;
		ANTENNAPARTIALMETALAREA 0.00198 ;
	END Q[17]

	PIN Q[18]
		USE SIGNAL ;
		DIRECTION OUTPUT ;
		SHAPE ABUTMENT ;
		PORT
			 LAYER M2 ;
			RECT 0.0098 15.0222 0.0481 15.1238 ;
			 LAYER M3 ;
			RECT 0.0098 15.0222 0.0481 15.1238 ;
			 LAYER V2 ;
			RECT 0.021 15.0353 0.0359 15.048 ;
		END

		ANTENNADIFFAREA 0.00197037 ;
		ANTENNAPARTIALMETALAREA 0.00198 ;
	END Q[18]

	PIN Q[19]
		USE SIGNAL ;
		DIRECTION OUTPUT ;
		SHAPE ABUTMENT ;
		PORT
			 LAYER M2 ;
			RECT 0.0098 15.8222 0.0481 15.9238 ;
			 LAYER M3 ;
			RECT 0.0098 15.8222 0.0481 15.9238 ;
			 LAYER V2 ;
			RECT 0.021 15.8353 0.0359 15.848 ;
		END

		ANTENNADIFFAREA 0.00197037 ;
		ANTENNAPARTIALMETALAREA 0.00198 ;
	END Q[19]

	PIN Q[1]
		USE SIGNAL ;
		DIRECTION OUTPUT ;
		SHAPE ABUTMENT ;
		PORT
			 LAYER M2 ;
			RECT 0.0098 1.4222 0.0481 1.5238 ;
			 LAYER M3 ;
			RECT 0.0098 1.4222 0.0481 1.5238 ;
			 LAYER V2 ;
			RECT 0.021 1.4353 0.0359 1.448 ;
		END

		ANTENNADIFFAREA 0.00197037 ;
		ANTENNAPARTIALMETALAREA 0.00198 ;
	END Q[1]

	PIN Q[20]
		USE SIGNAL ;
		DIRECTION OUTPUT ;
		SHAPE ABUTMENT ;
		PORT
			 LAYER M2 ;
			RECT 0.0098 16.6222 0.0481 16.7238 ;
			 LAYER M3 ;
			RECT 0.0098 16.6222 0.0481 16.7238 ;
			 LAYER V2 ;
			RECT 0.021 16.6353 0.0359 16.648 ;
		END

		ANTENNADIFFAREA 0.00197037 ;
		ANTENNAPARTIALMETALAREA 0.00198 ;
	END Q[20]

	PIN Q[21]
		USE SIGNAL ;
		DIRECTION OUTPUT ;
		SHAPE ABUTMENT ;
		PORT
			 LAYER M2 ;
			RECT 0.0098 17.4222 0.0481 17.5238 ;
			 LAYER M3 ;
			RECT 0.0098 17.4222 0.0481 17.5238 ;
			 LAYER V2 ;
			RECT 0.021 17.4353 0.0359 17.448 ;
		END

		ANTENNADIFFAREA 0.00197037 ;
		ANTENNAPARTIALMETALAREA 0.00198 ;
	END Q[21]

	PIN Q[22]
		USE SIGNAL ;
		DIRECTION OUTPUT ;
		SHAPE ABUTMENT ;
		PORT
			 LAYER M2 ;
			RECT 0.0098 25.6571 0.0481 25.7587 ;
			 LAYER M3 ;
			RECT 0.0098 25.6571 0.0481 25.7587 ;
			 LAYER V2 ;
			RECT 0.021 25.7329 0.0359 25.7456 ;
		END

		ANTENNADIFFAREA 0.00197037 ;
		ANTENNAPARTIALMETALAREA 0.00198 ;
	END Q[22]

	PIN Q[23]
		USE SIGNAL ;
		DIRECTION OUTPUT ;
		SHAPE ABUTMENT ;
		PORT
			 LAYER M2 ;
			RECT 0.0098 26.4571 0.0481 26.5587 ;
			 LAYER M3 ;
			RECT 0.0098 26.4571 0.0481 26.5587 ;
			 LAYER V2 ;
			RECT 0.021 26.5329 0.0359 26.5456 ;
		END

		ANTENNADIFFAREA 0.00197037 ;
		ANTENNAPARTIALMETALAREA 0.00198 ;
	END Q[23]

	PIN Q[24]
		USE SIGNAL ;
		DIRECTION OUTPUT ;
		SHAPE ABUTMENT ;
		PORT
			 LAYER M2 ;
			RECT 0.0098 27.2571 0.0481 27.3587 ;
			 LAYER M3 ;
			RECT 0.0098 27.2571 0.0481 27.3587 ;
			 LAYER V2 ;
			RECT 0.021 27.3329 0.0359 27.3456 ;
		END

		ANTENNADIFFAREA 0.00197037 ;
		ANTENNAPARTIALMETALAREA 0.00198 ;
	END Q[24]

	PIN Q[25]
		USE SIGNAL ;
		DIRECTION OUTPUT ;
		SHAPE ABUTMENT ;
		PORT
			 LAYER M2 ;
			RECT 0.0098 28.0571 0.0481 28.1587 ;
			 LAYER M3 ;
			RECT 0.0098 28.0571 0.0481 28.1587 ;
			 LAYER V2 ;
			RECT 0.021 28.1329 0.0359 28.1456 ;
		END

		ANTENNADIFFAREA 0.00197037 ;
		ANTENNAPARTIALMETALAREA 0.00198 ;
	END Q[25]

	PIN Q[26]
		USE SIGNAL ;
		DIRECTION OUTPUT ;
		SHAPE ABUTMENT ;
		PORT
			 LAYER M2 ;
			RECT 0.0098 28.8571 0.0481 28.9587 ;
			 LAYER M3 ;
			RECT 0.0098 28.8571 0.0481 28.9587 ;
			 LAYER V2 ;
			RECT 0.021 28.9329 0.0359 28.9456 ;
		END

		ANTENNADIFFAREA 0.00197037 ;
		ANTENNAPARTIALMETALAREA 0.00198 ;
	END Q[26]

	PIN Q[27]
		USE SIGNAL ;
		DIRECTION OUTPUT ;
		SHAPE ABUTMENT ;
		PORT
			 LAYER M2 ;
			RECT 0.0098 29.6571 0.0481 29.7587 ;
			 LAYER M3 ;
			RECT 0.0098 29.6571 0.0481 29.7587 ;
			 LAYER V2 ;
			RECT 0.021 29.7329 0.0359 29.7456 ;
		END

		ANTENNADIFFAREA 0.00197037 ;
		ANTENNAPARTIALMETALAREA 0.00198 ;
	END Q[27]

	PIN Q[28]
		USE SIGNAL ;
		DIRECTION OUTPUT ;
		SHAPE ABUTMENT ;
		PORT
			 LAYER M2 ;
			RECT 0.0098 30.4571 0.0481 30.5587 ;
			 LAYER M3 ;
			RECT 0.0098 30.4571 0.0481 30.5587 ;
			 LAYER V2 ;
			RECT 0.021 30.5329 0.0359 30.5456 ;
		END

		ANTENNADIFFAREA 0.00197037 ;
		ANTENNAPARTIALMETALAREA 0.00198 ;
	END Q[28]

	PIN Q[29]
		USE SIGNAL ;
		DIRECTION OUTPUT ;
		SHAPE ABUTMENT ;
		PORT
			 LAYER M2 ;
			RECT 0.0098 31.2571 0.0481 31.3587 ;
			 LAYER M3 ;
			RECT 0.0098 31.2571 0.0481 31.3587 ;
			 LAYER V2 ;
			RECT 0.021 31.3329 0.0359 31.3456 ;
		END

		ANTENNADIFFAREA 0.00197037 ;
		ANTENNAPARTIALMETALAREA 0.00198 ;
	END Q[29]

	PIN Q[2]
		USE SIGNAL ;
		DIRECTION OUTPUT ;
		SHAPE ABUTMENT ;
		PORT
			 LAYER M2 ;
			RECT 0.0098 2.2222 0.0481 2.3238 ;
			 LAYER M3 ;
			RECT 0.0098 2.2222 0.0481 2.3238 ;
			 LAYER V2 ;
			RECT 0.021 2.2353 0.0359 2.248 ;
		END

		ANTENNADIFFAREA 0.00197037 ;
		ANTENNAPARTIALMETALAREA 0.00198 ;
	END Q[2]

	PIN Q[30]
		USE SIGNAL ;
		DIRECTION OUTPUT ;
		SHAPE ABUTMENT ;
		PORT
			 LAYER M2 ;
			RECT 0.0098 32.0571 0.0481 32.1587 ;
			 LAYER M3 ;
			RECT 0.0098 32.0571 0.0481 32.1587 ;
			 LAYER V2 ;
			RECT 0.021 32.1329 0.0359 32.1456 ;
		END

		ANTENNADIFFAREA 0.00197037 ;
		ANTENNAPARTIALMETALAREA 0.00198 ;
	END Q[30]

	PIN Q[31]
		USE SIGNAL ;
		DIRECTION OUTPUT ;
		SHAPE ABUTMENT ;
		PORT
			 LAYER M2 ;
			RECT 0.0098 32.8571 0.0481 32.9587 ;
			 LAYER M3 ;
			RECT 0.0098 32.8571 0.0481 32.9587 ;
			 LAYER V2 ;
			RECT 0.021 32.9329 0.0359 32.9456 ;
		END

		ANTENNADIFFAREA 0.00197037 ;
		ANTENNAPARTIALMETALAREA 0.00198 ;
	END Q[31]

	PIN Q[32]
		USE SIGNAL ;
		DIRECTION OUTPUT ;
		SHAPE ABUTMENT ;
		PORT
			 LAYER M2 ;
			RECT 0.0098 33.6571 0.0481 33.7587 ;
			 LAYER M3 ;
			RECT 0.0098 33.6571 0.0481 33.7587 ;
			 LAYER V2 ;
			RECT 0.021 33.7329 0.0359 33.7456 ;
		END

		ANTENNADIFFAREA 0.00197037 ;
		ANTENNAPARTIALMETALAREA 0.00198 ;
	END Q[32]

	PIN Q[33]
		USE SIGNAL ;
		DIRECTION OUTPUT ;
		SHAPE ABUTMENT ;
		PORT
			 LAYER M2 ;
			RECT 0.0098 34.4571 0.0481 34.5587 ;
			 LAYER M3 ;
			RECT 0.0098 34.4571 0.0481 34.5587 ;
			 LAYER V2 ;
			RECT 0.021 34.5329 0.0359 34.5456 ;
		END

		ANTENNADIFFAREA 0.00197037 ;
		ANTENNAPARTIALMETALAREA 0.00198 ;
	END Q[33]

	PIN Q[34]
		USE SIGNAL ;
		DIRECTION OUTPUT ;
		SHAPE ABUTMENT ;
		PORT
			 LAYER M2 ;
			RECT 0.0098 35.2571 0.0481 35.3587 ;
			 LAYER M3 ;
			RECT 0.0098 35.2571 0.0481 35.3587 ;
			 LAYER V2 ;
			RECT 0.021 35.3329 0.0359 35.3456 ;
		END

		ANTENNADIFFAREA 0.00197037 ;
		ANTENNAPARTIALMETALAREA 0.00198 ;
	END Q[34]

	PIN Q[35]
		USE SIGNAL ;
		DIRECTION OUTPUT ;
		SHAPE ABUTMENT ;
		PORT
			 LAYER M2 ;
			RECT 0.0098 36.0571 0.0481 36.1587 ;
			 LAYER M3 ;
			RECT 0.0098 36.0571 0.0481 36.1587 ;
			 LAYER V2 ;
			RECT 0.021 36.1329 0.0359 36.1456 ;
		END

		ANTENNADIFFAREA 0.00197037 ;
		ANTENNAPARTIALMETALAREA 0.00198 ;
	END Q[35]

	PIN Q[36]
		USE SIGNAL ;
		DIRECTION OUTPUT ;
		SHAPE ABUTMENT ;
		PORT
			 LAYER M2 ;
			RECT 0.0098 36.8571 0.0481 36.9587 ;
			 LAYER M3 ;
			RECT 0.0098 36.8571 0.0481 36.9587 ;
			 LAYER V2 ;
			RECT 0.021 36.9329 0.0359 36.9456 ;
		END

		ANTENNADIFFAREA 0.00197037 ;
		ANTENNAPARTIALMETALAREA 0.00198 ;
	END Q[36]

	PIN Q[37]
		USE SIGNAL ;
		DIRECTION OUTPUT ;
		SHAPE ABUTMENT ;
		PORT
			 LAYER M2 ;
			RECT 0.0098 37.6571 0.0481 37.7587 ;
			 LAYER M3 ;
			RECT 0.0098 37.6571 0.0481 37.7587 ;
			 LAYER V2 ;
			RECT 0.021 37.7329 0.0359 37.7456 ;
		END

		ANTENNADIFFAREA 0.00197037 ;
		ANTENNAPARTIALMETALAREA 0.00198 ;
	END Q[37]

	PIN Q[38]
		USE SIGNAL ;
		DIRECTION OUTPUT ;
		SHAPE ABUTMENT ;
		PORT
			 LAYER M2 ;
			RECT 0.0098 38.4571 0.0481 38.5587 ;
			 LAYER M3 ;
			RECT 0.0098 38.4571 0.0481 38.5587 ;
			 LAYER V2 ;
			RECT 0.021 38.5329 0.0359 38.5456 ;
		END

		ANTENNADIFFAREA 0.00197037 ;
		ANTENNAPARTIALMETALAREA 0.00198 ;
	END Q[38]

	PIN Q[39]
		USE SIGNAL ;
		DIRECTION OUTPUT ;
		SHAPE ABUTMENT ;
		PORT
			 LAYER M2 ;
			RECT 0.0098 39.2571 0.0481 39.3587 ;
			 LAYER M3 ;
			RECT 0.0098 39.2571 0.0481 39.3587 ;
			 LAYER V2 ;
			RECT 0.021 39.3329 0.0359 39.3456 ;
		END

		ANTENNADIFFAREA 0.00197037 ;
		ANTENNAPARTIALMETALAREA 0.00198 ;
	END Q[39]

	PIN Q[3]
		USE SIGNAL ;
		DIRECTION OUTPUT ;
		SHAPE ABUTMENT ;
		PORT
			 LAYER M2 ;
			RECT 0.0098 3.0222 0.0481 3.1238 ;
			 LAYER M3 ;
			RECT 0.0098 3.0222 0.0481 3.1238 ;
			 LAYER V2 ;
			RECT 0.021 3.0353 0.0359 3.048 ;
		END

		ANTENNADIFFAREA 0.00197037 ;
		ANTENNAPARTIALMETALAREA 0.00198 ;
	END Q[3]

	PIN Q[40]
		USE SIGNAL ;
		DIRECTION OUTPUT ;
		SHAPE ABUTMENT ;
		PORT
			 LAYER M2 ;
			RECT 0.0098 40.0571 0.0481 40.1587 ;
			 LAYER M3 ;
			RECT 0.0098 40.0571 0.0481 40.1587 ;
			 LAYER V2 ;
			RECT 0.021 40.1329 0.0359 40.1456 ;
		END

		ANTENNADIFFAREA 0.00197037 ;
		ANTENNAPARTIALMETALAREA 0.00198 ;
	END Q[40]

	PIN Q[41]
		USE SIGNAL ;
		DIRECTION OUTPUT ;
		SHAPE ABUTMENT ;
		PORT
			 LAYER M2 ;
			RECT 0.0098 40.8571 0.0481 40.9587 ;
			 LAYER M3 ;
			RECT 0.0098 40.8571 0.0481 40.9587 ;
			 LAYER V2 ;
			RECT 0.021 40.9329 0.0359 40.9456 ;
		END

		ANTENNADIFFAREA 0.00197037 ;
		ANTENNAPARTIALMETALAREA 0.00198 ;
	END Q[41]

	PIN Q[42]
		USE SIGNAL ;
		DIRECTION OUTPUT ;
		SHAPE ABUTMENT ;
		PORT
			 LAYER M2 ;
			RECT 0.0098 41.6571 0.0481 41.7587 ;
			 LAYER M3 ;
			RECT 0.0098 41.6571 0.0481 41.7587 ;
			 LAYER V2 ;
			RECT 0.021 41.7329 0.0359 41.7456 ;
		END

		ANTENNADIFFAREA 0.00197037 ;
		ANTENNAPARTIALMETALAREA 0.00198 ;
	END Q[42]

	PIN Q[43]
		USE SIGNAL ;
		DIRECTION OUTPUT ;
		SHAPE ABUTMENT ;
		PORT
			 LAYER M2 ;
			RECT 0.0098 42.4571 0.0481 42.5587 ;
			 LAYER M3 ;
			RECT 0.0098 42.4571 0.0481 42.5587 ;
			 LAYER V2 ;
			RECT 0.021 42.5329 0.0359 42.5456 ;
		END

		ANTENNADIFFAREA 0.00197037 ;
		ANTENNAPARTIALMETALAREA 0.00198 ;
	END Q[43]

	PIN Q[44]
		USE SIGNAL ;
		DIRECTION OUTPUT ;
		SHAPE ABUTMENT ;
		PORT
			 LAYER M2 ;
			RECT 0.0098 43.2571 0.0481 43.3587 ;
			 LAYER M3 ;
			RECT 0.0098 43.2571 0.0481 43.3587 ;
			 LAYER V2 ;
			RECT 0.021 43.3329 0.0359 43.3456 ;
		END

		ANTENNADIFFAREA 0.00197037 ;
		ANTENNAPARTIALMETALAREA 0.00198 ;
	END Q[44]

	PIN Q[4]
		USE SIGNAL ;
		DIRECTION OUTPUT ;
		SHAPE ABUTMENT ;
		PORT
			 LAYER M2 ;
			RECT 0.0098 3.8222 0.0481 3.9238 ;
			 LAYER M3 ;
			RECT 0.0098 3.8222 0.0481 3.9238 ;
			 LAYER V2 ;
			RECT 0.021 3.8353 0.0359 3.848 ;
		END

		ANTENNADIFFAREA 0.00197037 ;
		ANTENNAPARTIALMETALAREA 0.00198 ;
	END Q[4]

	PIN Q[5]
		USE SIGNAL ;
		DIRECTION OUTPUT ;
		SHAPE ABUTMENT ;
		PORT
			 LAYER M2 ;
			RECT 0.0098 4.6222 0.0481 4.7238 ;
			 LAYER M3 ;
			RECT 0.0098 4.6222 0.0481 4.7238 ;
			 LAYER V2 ;
			RECT 0.021 4.6353 0.0359 4.648 ;
		END

		ANTENNADIFFAREA 0.00197037 ;
		ANTENNAPARTIALMETALAREA 0.00198 ;
	END Q[5]

	PIN Q[6]
		USE SIGNAL ;
		DIRECTION OUTPUT ;
		SHAPE ABUTMENT ;
		PORT
			 LAYER M2 ;
			RECT 0.0098 5.4222 0.0481 5.5238 ;
			 LAYER M3 ;
			RECT 0.0098 5.4222 0.0481 5.5238 ;
			 LAYER V2 ;
			RECT 0.021 5.4353 0.0359 5.448 ;
		END

		ANTENNADIFFAREA 0.00197037 ;
		ANTENNAPARTIALMETALAREA 0.00198 ;
	END Q[6]

	PIN Q[7]
		USE SIGNAL ;
		DIRECTION OUTPUT ;
		SHAPE ABUTMENT ;
		PORT
			 LAYER M2 ;
			RECT 0.0098 6.2222 0.0481 6.3238 ;
			 LAYER M3 ;
			RECT 0.0098 6.2222 0.0481 6.3238 ;
			 LAYER V2 ;
			RECT 0.021 6.2353 0.0359 6.248 ;
		END

		ANTENNADIFFAREA 0.00197037 ;
		ANTENNAPARTIALMETALAREA 0.00198 ;
	END Q[7]

	PIN Q[8]
		USE SIGNAL ;
		DIRECTION OUTPUT ;
		SHAPE ABUTMENT ;
		PORT
			 LAYER M2 ;
			RECT 0.0098 7.0222 0.0481 7.1238 ;
			 LAYER M3 ;
			RECT 0.0098 7.0222 0.0481 7.1238 ;
			 LAYER V2 ;
			RECT 0.021 7.0353 0.0359 7.048 ;
		END

		ANTENNADIFFAREA 0.00197037 ;
		ANTENNAPARTIALMETALAREA 0.00198 ;
	END Q[8]

	PIN Q[9]
		USE SIGNAL ;
		DIRECTION OUTPUT ;
		SHAPE ABUTMENT ;
		PORT
			 LAYER M2 ;
			RECT 0.0098 7.8222 0.0481 7.9238 ;
			 LAYER M3 ;
			RECT 0.0098 7.8222 0.0481 7.9238 ;
			 LAYER V2 ;
			RECT 0.021 7.8353 0.0359 7.848 ;
		END

		ANTENNADIFFAREA 0.00197037 ;
		ANTENNAPARTIALMETALAREA 0.00198 ;
	END Q[9]

	PIN RET1N
		USE SIGNAL ;
		DIRECTION INPUT ;
		SHAPE ABUTMENT ;
		PORT
			 LAYER M2 ;
			RECT 0.0714 19.8794 0.1097 19.9175 ;
			 LAYER M3 ;
			RECT 0.0714 19.8794 0.1097 19.981 ;
			 LAYER V2 ;
			RECT 0.0831 19.8917 0.098 19.9044 ;
		END

		ANTENNAGATEAREA 0.00028148 ;
		ANTENNADIFFAREA 0.00197037 ;
		ANTENNAPARTIALMETALAREA 0.00198 ;
	END RET1N

	PIN SE
		USE SIGNAL ;
		DIRECTION INPUT ;
		SHAPE ABUTMENT ;
		PORT
			 LAYER M2 ;
			RECT 0.0098 23.219 0.0481 23.3206 ;
			 LAYER M3 ;
			RECT 0.0098 23.219 0.0481 23.3206 ;
			 LAYER V2 ;
			RECT 0.021 23.2321 0.0359 23.2448 ;
		END

		ANTENNAGATEAREA 0.00028148 ;
		ANTENNADIFFAREA 0.00197037 ;
		ANTENNAPARTIALMETALAREA 0.00198 ;
	END SE

	PIN SI[0]
		USE SIGNAL ;
		DIRECTION INPUT ;
		SHAPE ABUTMENT ;
		PORT
			 LAYER M2 ;
			RECT 0.0098 0.1778 0.0481 0.2159 ;
			 LAYER M3 ;
			RECT 0.0098 0.1143 0.0481 0.2159 ;
			 LAYER V2 ;
			RECT 0.0215 0.1901 0.0364 0.2028 ;
		END

		ANTENNAGATEAREA 0.00028148 ;
		ANTENNADIFFAREA 0.00197037 ;
		ANTENNAPARTIALMETALAREA 0.00198 ;
	END SI[0]

	PIN SI[1]
		USE SIGNAL ;
		DIRECTION INPUT ;
		SHAPE ABUTMENT ;
		PORT
			 LAYER M2 ;
			RECT 0.0098 43.7651 0.0481 43.8032 ;
			 LAYER M3 ;
			RECT 0.0098 43.7651 0.0481 43.8667 ;
			 LAYER V2 ;
			RECT 0.0215 43.7782 0.0364 43.7909 ;
		END

		ANTENNAGATEAREA 0.00028148 ;
		ANTENNADIFFAREA 0.00197037 ;
		ANTENNAPARTIALMETALAREA 0.00198 ;
	END SI[1]

	PIN SO[0]
		USE SIGNAL ;
		DIRECTION OUTPUT ;
		SHAPE ABUTMENT ;
		PORT
			 LAYER M2 ;
			RECT 0.0098 23.8286 0.0481 23.8667 ;
			 LAYER M3 ;
			RECT 0.0098 23.7651 0.0481 23.8667 ;
			 LAYER V2 ;
			RECT 0.0215 23.8409 0.0364 23.8536 ;
		END

		ANTENNADIFFAREA 0.00197037 ;
		ANTENNAPARTIALMETALAREA 0.00198 ;
	END SO[0]

	PIN SO[1]
		USE SIGNAL ;
		DIRECTION OUTPUT ;
		SHAPE ABUTMENT ;
		PORT
			 LAYER M2 ;
			RECT 0.0098 21.8222 0.0481 21.8603 ;
			 LAYER M3 ;
			RECT 0.0098 21.7587 0.0481 21.8603 ;
			 LAYER V2 ;
			RECT 0.0215 21.8345 0.0364 21.8472 ;
		END

		ANTENNADIFFAREA 0.00197037 ;
		ANTENNAPARTIALMETALAREA 0.00198 ;
	END SO[1]

	PIN STOV
		USE SIGNAL ;
		DIRECTION INPUT ;
		SHAPE ABUTMENT ;
		PORT
			 LAYER M2 ;
			RECT 0.0098 21.1492 0.0481 21.1873 ;
			 LAYER M3 ;
			RECT 0.0098 21.0857 0.0481 21.1873 ;
			 LAYER V2 ;
			RECT 0.0215 21.1615 0.0364 21.1742 ;
		END

		ANTENNAGATEAREA 0.00028148 ;
		ANTENNADIFFAREA 0.00197037 ;
		ANTENNAPARTIALMETALAREA 0.00198 ;
	END STOV

	PIN TA[0]
		USE SIGNAL ;
		DIRECTION INPUT ;
		SHAPE ABUTMENT ;
		PORT
			 LAYER M2 ;
			RECT 0.0714 21.0857 0.1097 21.1238 ;
			 LAYER M3 ;
			RECT 0.0714 21.0857 0.1097 21.1873 ;
			 LAYER V2 ;
			RECT 0.0831 21.098 0.098 21.1107 ;
		END

		ANTENNAGATEAREA 0.00028148 ;
		ANTENNADIFFAREA 0.00197037 ;
		ANTENNAPARTIALMETALAREA 0.00198 ;
	END TA[0]

	PIN TA[1]
		USE SIGNAL ;
		DIRECTION INPUT ;
		SHAPE ABUTMENT ;
		PORT
			 LAYER M2 ;
			RECT 0.0714 21.2127 0.1097 21.2508 ;
			 LAYER M3 ;
			RECT 0.0714 21.2127 0.1097 21.3143 ;
			 LAYER V2 ;
			RECT 0.0831 21.225 0.098 21.2377 ;
		END

		ANTENNAGATEAREA 0.00028148 ;
		ANTENNADIFFAREA 0.00197037 ;
		ANTENNAPARTIALMETALAREA 0.00198 ;
	END TA[1]

	PIN TA[2]
		USE SIGNAL ;
		DIRECTION INPUT ;
		SHAPE ABUTMENT ;
		PORT
			 LAYER M2 ;
			RECT 0.0714 22.2794 0.1097 22.3175 ;
			 LAYER M3 ;
			RECT 0.0714 22.2794 0.1097 22.381 ;
			 LAYER V2 ;
			RECT 0.0831 22.2917 0.098 22.3044 ;
		END

		ANTENNAGATEAREA 0.00028148 ;
		ANTENNADIFFAREA 0.00197037 ;
		ANTENNAPARTIALMETALAREA 0.00198 ;
	END TA[2]

	PIN TA[3]
		USE SIGNAL ;
		DIRECTION INPUT ;
		SHAPE ABUTMENT ;
		PORT
			 LAYER M2 ;
			RECT 0.0098 22.6095 0.0481 22.6476 ;
			 LAYER M3 ;
			RECT 0.0098 22.546 0.0481 22.6476 ;
			 LAYER V2 ;
			RECT 0.0215 22.6218 0.0364 22.6345 ;
		END

		ANTENNAGATEAREA 0.00028148 ;
		ANTENNADIFFAREA 0.00197037 ;
		ANTENNAPARTIALMETALAREA 0.00198 ;
	END TA[3]

	PIN TA[4]
		USE SIGNAL ;
		DIRECTION INPUT ;
		SHAPE ABUTMENT ;
		PORT
			 LAYER M2 ;
			RECT 0.0098 22.8889 0.0481 22.927 ;
			 LAYER M3 ;
			RECT 0.0098 22.8254 0.0481 22.927 ;
			 LAYER V2 ;
			RECT 0.0215 22.9012 0.0364 22.9139 ;
		END

		ANTENNAGATEAREA 0.00028148 ;
		ANTENNADIFFAREA 0.00197037 ;
		ANTENNAPARTIALMETALAREA 0.00198 ;
	END TA[4]

	PIN TA[5]
		USE SIGNAL ;
		DIRECTION INPUT ;
		SHAPE ABUTMENT ;
		PORT
			 LAYER M2 ;
			RECT 0.0714 23.473 0.1097 23.5111 ;
			 LAYER M3 ;
			RECT 0.0714 23.473 0.1097 23.5746 ;
			 LAYER V2 ;
			RECT 0.0831 23.4853 0.098 23.498 ;
		END

		ANTENNAGATEAREA 0.00028148 ;
		ANTENNADIFFAREA 0.00197037 ;
		ANTENNAPARTIALMETALAREA 0.00198 ;
	END TA[5]

	PIN TA[6]
		USE SIGNAL ;
		DIRECTION INPUT ;
		SHAPE ABUTMENT ;
		PORT
			 LAYER M2 ;
			RECT 0.0714 23.346 0.1097 23.3841 ;
			 LAYER M3 ;
			RECT 0.0714 23.346 0.1097 23.4476 ;
			 LAYER V2 ;
			RECT 0.0831 23.3583 0.098 23.371 ;
		END

		ANTENNAGATEAREA 0.00028148 ;
		ANTENNADIFFAREA 0.00197037 ;
		ANTENNAPARTIALMETALAREA 0.00198 ;
	END TA[6]

	PIN TCEN
		USE SIGNAL ;
		DIRECTION INPUT ;
		SHAPE ABUTMENT ;
		PORT
			 LAYER M2 ;
			RECT 0.0714 20.6921 0.1097 20.7302 ;
			 LAYER M3 ;
			RECT 0.0714 20.6921 0.1097 20.7937 ;
			 LAYER V2 ;
			RECT 0.0831 20.7044 0.098 20.7171 ;
		END

		ANTENNAGATEAREA 0.00028148 ;
		ANTENNADIFFAREA 0.00197037 ;
		ANTENNAPARTIALMETALAREA 0.00198 ;
	END TCEN

	PIN TD[0]
		USE SIGNAL ;
		DIRECTION INPUT ;
		SHAPE ABUTMENT ;
		PORT
			 LAYER M2 ;
			RECT 0.0098 0.4952 0.0481 0.5968 ;
			 LAYER M3 ;
			RECT 0.0098 0.4952 0.0481 0.5968 ;
			 LAYER V2 ;
			RECT 0.021 0.571 0.0359 0.5837 ;
		END

		ANTENNAGATEAREA 0.00028148 ;
		ANTENNADIFFAREA 0.00197037 ;
		ANTENNAPARTIALMETALAREA 0.00198 ;
	END TD[0]

	PIN TD[10]
		USE SIGNAL ;
		DIRECTION INPUT ;
		SHAPE ABUTMENT ;
		PORT
			 LAYER M2 ;
			RECT 0.0098 8.4952 0.0481 8.5968 ;
			 LAYER M3 ;
			RECT 0.0098 8.4952 0.0481 8.5968 ;
			 LAYER V2 ;
			RECT 0.021 8.571 0.0359 8.5837 ;
		END

		ANTENNAGATEAREA 0.00028148 ;
		ANTENNADIFFAREA 0.00197037 ;
		ANTENNAPARTIALMETALAREA 0.00198 ;
	END TD[10]

	PIN TD[11]
		USE SIGNAL ;
		DIRECTION INPUT ;
		SHAPE ABUTMENT ;
		PORT
			 LAYER M2 ;
			RECT 0.0098 9.2952 0.0481 9.3968 ;
			 LAYER M3 ;
			RECT 0.0098 9.2952 0.0481 9.3968 ;
			 LAYER V2 ;
			RECT 0.021 9.371 0.0359 9.3837 ;
		END

		ANTENNAGATEAREA 0.00028148 ;
		ANTENNADIFFAREA 0.00197037 ;
		ANTENNAPARTIALMETALAREA 0.00198 ;
	END TD[11]

	PIN TD[12]
		USE SIGNAL ;
		DIRECTION INPUT ;
		SHAPE ABUTMENT ;
		PORT
			 LAYER M2 ;
			RECT 0.0098 10.0952 0.0481 10.1968 ;
			 LAYER M3 ;
			RECT 0.0098 10.0952 0.0481 10.1968 ;
			 LAYER V2 ;
			RECT 0.021 10.171 0.0359 10.1837 ;
		END

		ANTENNAGATEAREA 0.00028148 ;
		ANTENNADIFFAREA 0.00197037 ;
		ANTENNAPARTIALMETALAREA 0.00198 ;
	END TD[12]

	PIN TD[13]
		USE SIGNAL ;
		DIRECTION INPUT ;
		SHAPE ABUTMENT ;
		PORT
			 LAYER M2 ;
			RECT 0.0098 10.8952 0.0481 10.9968 ;
			 LAYER M3 ;
			RECT 0.0098 10.8952 0.0481 10.9968 ;
			 LAYER V2 ;
			RECT 0.021 10.971 0.0359 10.9837 ;
		END

		ANTENNAGATEAREA 0.00028148 ;
		ANTENNADIFFAREA 0.00197037 ;
		ANTENNAPARTIALMETALAREA 0.00198 ;
	END TD[13]

	PIN TD[14]
		USE SIGNAL ;
		DIRECTION INPUT ;
		SHAPE ABUTMENT ;
		PORT
			 LAYER M2 ;
			RECT 0.0098 11.6952 0.0481 11.7968 ;
			 LAYER M3 ;
			RECT 0.0098 11.6952 0.0481 11.7968 ;
			 LAYER V2 ;
			RECT 0.021 11.771 0.0359 11.7837 ;
		END

		ANTENNAGATEAREA 0.00028148 ;
		ANTENNADIFFAREA 0.00197037 ;
		ANTENNAPARTIALMETALAREA 0.00198 ;
	END TD[14]

	PIN TD[15]
		USE SIGNAL ;
		DIRECTION INPUT ;
		SHAPE ABUTMENT ;
		PORT
			 LAYER M2 ;
			RECT 0.0098 12.4952 0.0481 12.5968 ;
			 LAYER M3 ;
			RECT 0.0098 12.4952 0.0481 12.5968 ;
			 LAYER V2 ;
			RECT 0.021 12.571 0.0359 12.5837 ;
		END

		ANTENNAGATEAREA 0.00028148 ;
		ANTENNADIFFAREA 0.00197037 ;
		ANTENNAPARTIALMETALAREA 0.00198 ;
	END TD[15]

	PIN TD[16]
		USE SIGNAL ;
		DIRECTION INPUT ;
		SHAPE ABUTMENT ;
		PORT
			 LAYER M2 ;
			RECT 0.0098 13.2952 0.0481 13.3968 ;
			 LAYER M3 ;
			RECT 0.0098 13.2952 0.0481 13.3968 ;
			 LAYER V2 ;
			RECT 0.021 13.371 0.0359 13.3837 ;
		END

		ANTENNAGATEAREA 0.00028148 ;
		ANTENNADIFFAREA 0.00197037 ;
		ANTENNAPARTIALMETALAREA 0.00198 ;
	END TD[16]

	PIN TD[17]
		USE SIGNAL ;
		DIRECTION INPUT ;
		SHAPE ABUTMENT ;
		PORT
			 LAYER M2 ;
			RECT 0.0098 14.0952 0.0481 14.1968 ;
			 LAYER M3 ;
			RECT 0.0098 14.0952 0.0481 14.1968 ;
			 LAYER V2 ;
			RECT 0.021 14.171 0.0359 14.1837 ;
		END

		ANTENNAGATEAREA 0.00028148 ;
		ANTENNADIFFAREA 0.00197037 ;
		ANTENNAPARTIALMETALAREA 0.00198 ;
	END TD[17]

	PIN TD[18]
		USE SIGNAL ;
		DIRECTION INPUT ;
		SHAPE ABUTMENT ;
		PORT
			 LAYER M2 ;
			RECT 0.0098 14.8952 0.0481 14.9968 ;
			 LAYER M3 ;
			RECT 0.0098 14.8952 0.0481 14.9968 ;
			 LAYER V2 ;
			RECT 0.021 14.971 0.0359 14.9837 ;
		END

		ANTENNAGATEAREA 0.00028148 ;
		ANTENNADIFFAREA 0.00197037 ;
		ANTENNAPARTIALMETALAREA 0.00198 ;
	END TD[18]

	PIN TD[19]
		USE SIGNAL ;
		DIRECTION INPUT ;
		SHAPE ABUTMENT ;
		PORT
			 LAYER M2 ;
			RECT 0.0098 15.6952 0.0481 15.7968 ;
			 LAYER M3 ;
			RECT 0.0098 15.6952 0.0481 15.7968 ;
			 LAYER V2 ;
			RECT 0.021 15.771 0.0359 15.7837 ;
		END

		ANTENNAGATEAREA 0.00028148 ;
		ANTENNADIFFAREA 0.00197037 ;
		ANTENNAPARTIALMETALAREA 0.00198 ;
	END TD[19]

	PIN TD[1]
		USE SIGNAL ;
		DIRECTION INPUT ;
		SHAPE ABUTMENT ;
		PORT
			 LAYER M2 ;
			RECT 0.0098 1.2952 0.0481 1.3968 ;
			 LAYER M3 ;
			RECT 0.0098 1.2952 0.0481 1.3968 ;
			 LAYER V2 ;
			RECT 0.021 1.371 0.0359 1.3837 ;
		END

		ANTENNAGATEAREA 0.00028148 ;
		ANTENNADIFFAREA 0.00197037 ;
		ANTENNAPARTIALMETALAREA 0.00198 ;
	END TD[1]

	PIN TD[20]
		USE SIGNAL ;
		DIRECTION INPUT ;
		SHAPE ABUTMENT ;
		PORT
			 LAYER M2 ;
			RECT 0.0098 16.4952 0.0481 16.5968 ;
			 LAYER M3 ;
			RECT 0.0098 16.4952 0.0481 16.5968 ;
			 LAYER V2 ;
			RECT 0.021 16.571 0.0359 16.5837 ;
		END

		ANTENNAGATEAREA 0.00028148 ;
		ANTENNADIFFAREA 0.00197037 ;
		ANTENNAPARTIALMETALAREA 0.00198 ;
	END TD[20]

	PIN TD[21]
		USE SIGNAL ;
		DIRECTION INPUT ;
		SHAPE ABUTMENT ;
		PORT
			 LAYER M2 ;
			RECT 0.0098 17.2952 0.0481 17.3968 ;
			 LAYER M3 ;
			RECT 0.0098 17.2952 0.0481 17.3968 ;
			 LAYER V2 ;
			RECT 0.021 17.371 0.0359 17.3837 ;
		END

		ANTENNAGATEAREA 0.00028148 ;
		ANTENNADIFFAREA 0.00197037 ;
		ANTENNAPARTIALMETALAREA 0.00198 ;
	END TD[21]

	PIN TD[22]
		USE SIGNAL ;
		DIRECTION INPUT ;
		SHAPE ABUTMENT ;
		PORT
			 LAYER M2 ;
			RECT 0.0098 25.7841 0.0481 25.8857 ;
			 LAYER M3 ;
			RECT 0.0098 25.7841 0.0481 25.8857 ;
			 LAYER V2 ;
			RECT 0.021 25.7972 0.0359 25.8099 ;
		END

		ANTENNAGATEAREA 0.00028148 ;
		ANTENNADIFFAREA 0.00197037 ;
		ANTENNAPARTIALMETALAREA 0.00198 ;
	END TD[22]

	PIN TD[23]
		USE SIGNAL ;
		DIRECTION INPUT ;
		SHAPE ABUTMENT ;
		PORT
			 LAYER M2 ;
			RECT 0.0098 26.5841 0.0481 26.6857 ;
			 LAYER M3 ;
			RECT 0.0098 26.5841 0.0481 26.6857 ;
			 LAYER V2 ;
			RECT 0.021 26.5972 0.0359 26.6099 ;
		END

		ANTENNAGATEAREA 0.00028148 ;
		ANTENNADIFFAREA 0.00197037 ;
		ANTENNAPARTIALMETALAREA 0.00198 ;
	END TD[23]

	PIN TD[24]
		USE SIGNAL ;
		DIRECTION INPUT ;
		SHAPE ABUTMENT ;
		PORT
			 LAYER M2 ;
			RECT 0.0098 27.3841 0.0481 27.4857 ;
			 LAYER M3 ;
			RECT 0.0098 27.3841 0.0481 27.4857 ;
			 LAYER V2 ;
			RECT 0.021 27.3972 0.0359 27.4099 ;
		END

		ANTENNAGATEAREA 0.00028148 ;
		ANTENNADIFFAREA 0.00197037 ;
		ANTENNAPARTIALMETALAREA 0.00198 ;
	END TD[24]

	PIN TD[25]
		USE SIGNAL ;
		DIRECTION INPUT ;
		SHAPE ABUTMENT ;
		PORT
			 LAYER M2 ;
			RECT 0.0098 28.1841 0.0481 28.2857 ;
			 LAYER M3 ;
			RECT 0.0098 28.1841 0.0481 28.2857 ;
			 LAYER V2 ;
			RECT 0.021 28.1972 0.0359 28.2099 ;
		END

		ANTENNAGATEAREA 0.00028148 ;
		ANTENNADIFFAREA 0.00197037 ;
		ANTENNAPARTIALMETALAREA 0.00198 ;
	END TD[25]

	PIN TD[26]
		USE SIGNAL ;
		DIRECTION INPUT ;
		SHAPE ABUTMENT ;
		PORT
			 LAYER M2 ;
			RECT 0.0098 28.9841 0.0481 29.0857 ;
			 LAYER M3 ;
			RECT 0.0098 28.9841 0.0481 29.0857 ;
			 LAYER V2 ;
			RECT 0.021 28.9972 0.0359 29.0099 ;
		END

		ANTENNAGATEAREA 0.00028148 ;
		ANTENNADIFFAREA 0.00197037 ;
		ANTENNAPARTIALMETALAREA 0.00198 ;
	END TD[26]

	PIN TD[27]
		USE SIGNAL ;
		DIRECTION INPUT ;
		SHAPE ABUTMENT ;
		PORT
			 LAYER M2 ;
			RECT 0.0098 29.7841 0.0481 29.8857 ;
			 LAYER M3 ;
			RECT 0.0098 29.7841 0.0481 29.8857 ;
			 LAYER V2 ;
			RECT 0.021 29.7972 0.0359 29.8099 ;
		END

		ANTENNAGATEAREA 0.00028148 ;
		ANTENNADIFFAREA 0.00197037 ;
		ANTENNAPARTIALMETALAREA 0.00198 ;
	END TD[27]

	PIN TD[28]
		USE SIGNAL ;
		DIRECTION INPUT ;
		SHAPE ABUTMENT ;
		PORT
			 LAYER M2 ;
			RECT 0.0098 30.5841 0.0481 30.6857 ;
			 LAYER M3 ;
			RECT 0.0098 30.5841 0.0481 30.6857 ;
			 LAYER V2 ;
			RECT 0.021 30.5972 0.0359 30.6099 ;
		END

		ANTENNAGATEAREA 0.00028148 ;
		ANTENNADIFFAREA 0.00197037 ;
		ANTENNAPARTIALMETALAREA 0.00198 ;
	END TD[28]

	PIN TD[29]
		USE SIGNAL ;
		DIRECTION INPUT ;
		SHAPE ABUTMENT ;
		PORT
			 LAYER M2 ;
			RECT 0.0098 31.3841 0.0481 31.4857 ;
			 LAYER M3 ;
			RECT 0.0098 31.3841 0.0481 31.4857 ;
			 LAYER V2 ;
			RECT 0.021 31.3972 0.0359 31.4099 ;
		END

		ANTENNAGATEAREA 0.00028148 ;
		ANTENNADIFFAREA 0.00197037 ;
		ANTENNAPARTIALMETALAREA 0.00198 ;
	END TD[29]

	PIN TD[2]
		USE SIGNAL ;
		DIRECTION INPUT ;
		SHAPE ABUTMENT ;
		PORT
			 LAYER M2 ;
			RECT 0.0098 2.0952 0.0481 2.1968 ;
			 LAYER M3 ;
			RECT 0.0098 2.0952 0.0481 2.1968 ;
			 LAYER V2 ;
			RECT 0.021 2.171 0.0359 2.1837 ;
		END

		ANTENNAGATEAREA 0.00028148 ;
		ANTENNADIFFAREA 0.00197037 ;
		ANTENNAPARTIALMETALAREA 0.00198 ;
	END TD[2]

	PIN TD[30]
		USE SIGNAL ;
		DIRECTION INPUT ;
		SHAPE ABUTMENT ;
		PORT
			 LAYER M2 ;
			RECT 0.0098 32.1841 0.0481 32.2857 ;
			 LAYER M3 ;
			RECT 0.0098 32.1841 0.0481 32.2857 ;
			 LAYER V2 ;
			RECT 0.021 32.1972 0.0359 32.2099 ;
		END

		ANTENNAGATEAREA 0.00028148 ;
		ANTENNADIFFAREA 0.00197037 ;
		ANTENNAPARTIALMETALAREA 0.00198 ;
	END TD[30]

	PIN TD[31]
		USE SIGNAL ;
		DIRECTION INPUT ;
		SHAPE ABUTMENT ;
		PORT
			 LAYER M2 ;
			RECT 0.0098 32.9841 0.0481 33.0857 ;
			 LAYER M3 ;
			RECT 0.0098 32.9841 0.0481 33.0857 ;
			 LAYER V2 ;
			RECT 0.021 32.9972 0.0359 33.0099 ;
		END

		ANTENNAGATEAREA 0.00028148 ;
		ANTENNADIFFAREA 0.00197037 ;
		ANTENNAPARTIALMETALAREA 0.00198 ;
	END TD[31]

	PIN TD[32]
		USE SIGNAL ;
		DIRECTION INPUT ;
		SHAPE ABUTMENT ;
		PORT
			 LAYER M2 ;
			RECT 0.0098 33.7841 0.0481 33.8857 ;
			 LAYER M3 ;
			RECT 0.0098 33.7841 0.0481 33.8857 ;
			 LAYER V2 ;
			RECT 0.021 33.7972 0.0359 33.8099 ;
		END

		ANTENNAGATEAREA 0.00028148 ;
		ANTENNADIFFAREA 0.00197037 ;
		ANTENNAPARTIALMETALAREA 0.00198 ;
	END TD[32]

	PIN TD[33]
		USE SIGNAL ;
		DIRECTION INPUT ;
		SHAPE ABUTMENT ;
		PORT
			 LAYER M2 ;
			RECT 0.0098 34.5841 0.0481 34.6857 ;
			 LAYER M3 ;
			RECT 0.0098 34.5841 0.0481 34.6857 ;
			 LAYER V2 ;
			RECT 0.021 34.5972 0.0359 34.6099 ;
		END

		ANTENNAGATEAREA 0.00028148 ;
		ANTENNADIFFAREA 0.00197037 ;
		ANTENNAPARTIALMETALAREA 0.00198 ;
	END TD[33]

	PIN TD[34]
		USE SIGNAL ;
		DIRECTION INPUT ;
		SHAPE ABUTMENT ;
		PORT
			 LAYER M2 ;
			RECT 0.0098 35.3841 0.0481 35.4857 ;
			 LAYER M3 ;
			RECT 0.0098 35.3841 0.0481 35.4857 ;
			 LAYER V2 ;
			RECT 0.021 35.3972 0.0359 35.4099 ;
		END

		ANTENNAGATEAREA 0.00028148 ;
		ANTENNADIFFAREA 0.00197037 ;
		ANTENNAPARTIALMETALAREA 0.00198 ;
	END TD[34]

	PIN TD[35]
		USE SIGNAL ;
		DIRECTION INPUT ;
		SHAPE ABUTMENT ;
		PORT
			 LAYER M2 ;
			RECT 0.0098 36.1841 0.0481 36.2857 ;
			 LAYER M3 ;
			RECT 0.0098 36.1841 0.0481 36.2857 ;
			 LAYER V2 ;
			RECT 0.021 36.1972 0.0359 36.2099 ;
		END

		ANTENNAGATEAREA 0.00028148 ;
		ANTENNADIFFAREA 0.00197037 ;
		ANTENNAPARTIALMETALAREA 0.00198 ;
	END TD[35]

	PIN TD[36]
		USE SIGNAL ;
		DIRECTION INPUT ;
		SHAPE ABUTMENT ;
		PORT
			 LAYER M2 ;
			RECT 0.0098 36.9841 0.0481 37.0857 ;
			 LAYER M3 ;
			RECT 0.0098 36.9841 0.0481 37.0857 ;
			 LAYER V2 ;
			RECT 0.021 36.9972 0.0359 37.0099 ;
		END

		ANTENNAGATEAREA 0.00028148 ;
		ANTENNADIFFAREA 0.00197037 ;
		ANTENNAPARTIALMETALAREA 0.00198 ;
	END TD[36]

	PIN TD[37]
		USE SIGNAL ;
		DIRECTION INPUT ;
		SHAPE ABUTMENT ;
		PORT
			 LAYER M2 ;
			RECT 0.0098 37.7841 0.0481 37.8857 ;
			 LAYER M3 ;
			RECT 0.0098 37.7841 0.0481 37.8857 ;
			 LAYER V2 ;
			RECT 0.021 37.7972 0.0359 37.8099 ;
		END

		ANTENNAGATEAREA 0.00028148 ;
		ANTENNADIFFAREA 0.00197037 ;
		ANTENNAPARTIALMETALAREA 0.00198 ;
	END TD[37]

	PIN TD[38]
		USE SIGNAL ;
		DIRECTION INPUT ;
		SHAPE ABUTMENT ;
		PORT
			 LAYER M2 ;
			RECT 0.0098 38.5841 0.0481 38.6857 ;
			 LAYER M3 ;
			RECT 0.0098 38.5841 0.0481 38.6857 ;
			 LAYER V2 ;
			RECT 0.021 38.5972 0.0359 38.6099 ;
		END

		ANTENNAGATEAREA 0.00028148 ;
		ANTENNADIFFAREA 0.00197037 ;
		ANTENNAPARTIALMETALAREA 0.00198 ;
	END TD[38]

	PIN TD[39]
		USE SIGNAL ;
		DIRECTION INPUT ;
		SHAPE ABUTMENT ;
		PORT
			 LAYER M2 ;
			RECT 0.0098 39.3841 0.0481 39.4857 ;
			 LAYER M3 ;
			RECT 0.0098 39.3841 0.0481 39.4857 ;
			 LAYER V2 ;
			RECT 0.021 39.3972 0.0359 39.4099 ;
		END

		ANTENNAGATEAREA 0.00028148 ;
		ANTENNADIFFAREA 0.00197037 ;
		ANTENNAPARTIALMETALAREA 0.00198 ;
	END TD[39]

	PIN TD[3]
		USE SIGNAL ;
		DIRECTION INPUT ;
		SHAPE ABUTMENT ;
		PORT
			 LAYER M2 ;
			RECT 0.0098 2.8952 0.0481 2.9968 ;
			 LAYER M3 ;
			RECT 0.0098 2.8952 0.0481 2.9968 ;
			 LAYER V2 ;
			RECT 0.021 2.971 0.0359 2.9837 ;
		END

		ANTENNAGATEAREA 0.00028148 ;
		ANTENNADIFFAREA 0.00197037 ;
		ANTENNAPARTIALMETALAREA 0.00198 ;
	END TD[3]

	PIN TD[40]
		USE SIGNAL ;
		DIRECTION INPUT ;
		SHAPE ABUTMENT ;
		PORT
			 LAYER M2 ;
			RECT 0.0098 40.1841 0.0481 40.2857 ;
			 LAYER M3 ;
			RECT 0.0098 40.1841 0.0481 40.2857 ;
			 LAYER V2 ;
			RECT 0.021 40.1972 0.0359 40.2099 ;
		END

		ANTENNAGATEAREA 0.00028148 ;
		ANTENNADIFFAREA 0.00197037 ;
		ANTENNAPARTIALMETALAREA 0.00198 ;
	END TD[40]

	PIN TD[41]
		USE SIGNAL ;
		DIRECTION INPUT ;
		SHAPE ABUTMENT ;
		PORT
			 LAYER M2 ;
			RECT 0.0098 40.9841 0.0481 41.0857 ;
			 LAYER M3 ;
			RECT 0.0098 40.9841 0.0481 41.0857 ;
			 LAYER V2 ;
			RECT 0.021 40.9972 0.0359 41.0099 ;
		END

		ANTENNAGATEAREA 0.00028148 ;
		ANTENNADIFFAREA 0.00197037 ;
		ANTENNAPARTIALMETALAREA 0.00198 ;
	END TD[41]

	PIN TD[42]
		USE SIGNAL ;
		DIRECTION INPUT ;
		SHAPE ABUTMENT ;
		PORT
			 LAYER M2 ;
			RECT 0.0098 41.7841 0.0481 41.8857 ;
			 LAYER M3 ;
			RECT 0.0098 41.7841 0.0481 41.8857 ;
			 LAYER V2 ;
			RECT 0.021 41.7972 0.0359 41.8099 ;
		END

		ANTENNAGATEAREA 0.00028148 ;
		ANTENNADIFFAREA 0.00197037 ;
		ANTENNAPARTIALMETALAREA 0.00198 ;
	END TD[42]

	PIN TD[43]
		USE SIGNAL ;
		DIRECTION INPUT ;
		SHAPE ABUTMENT ;
		PORT
			 LAYER M2 ;
			RECT 0.0098 42.5841 0.0481 42.6857 ;
			 LAYER M3 ;
			RECT 0.0098 42.5841 0.0481 42.6857 ;
			 LAYER V2 ;
			RECT 0.021 42.5972 0.0359 42.6099 ;
		END

		ANTENNAGATEAREA 0.00028148 ;
		ANTENNADIFFAREA 0.00197037 ;
		ANTENNAPARTIALMETALAREA 0.00198 ;
	END TD[43]

	PIN TD[44]
		USE SIGNAL ;
		DIRECTION INPUT ;
		SHAPE ABUTMENT ;
		PORT
			 LAYER M2 ;
			RECT 0.0098 43.3841 0.0481 43.4857 ;
			 LAYER M3 ;
			RECT 0.0098 43.3841 0.0481 43.4857 ;
			 LAYER V2 ;
			RECT 0.021 43.3972 0.0359 43.4099 ;
		END

		ANTENNAGATEAREA 0.00028148 ;
		ANTENNADIFFAREA 0.00197037 ;
		ANTENNAPARTIALMETALAREA 0.00198 ;
	END TD[44]

	PIN TD[4]
		USE SIGNAL ;
		DIRECTION INPUT ;
		SHAPE ABUTMENT ;
		PORT
			 LAYER M2 ;
			RECT 0.0098 3.6952 0.0481 3.7968 ;
			 LAYER M3 ;
			RECT 0.0098 3.6952 0.0481 3.7968 ;
			 LAYER V2 ;
			RECT 0.021 3.771 0.0359 3.7837 ;
		END

		ANTENNAGATEAREA 0.00028148 ;
		ANTENNADIFFAREA 0.00197037 ;
		ANTENNAPARTIALMETALAREA 0.00198 ;
	END TD[4]

	PIN TD[5]
		USE SIGNAL ;
		DIRECTION INPUT ;
		SHAPE ABUTMENT ;
		PORT
			 LAYER M2 ;
			RECT 0.0098 4.4952 0.0481 4.5968 ;
			 LAYER M3 ;
			RECT 0.0098 4.4952 0.0481 4.5968 ;
			 LAYER V2 ;
			RECT 0.021 4.571 0.0359 4.5837 ;
		END

		ANTENNAGATEAREA 0.00028148 ;
		ANTENNADIFFAREA 0.00197037 ;
		ANTENNAPARTIALMETALAREA 0.00198 ;
	END TD[5]

	PIN TD[6]
		USE SIGNAL ;
		DIRECTION INPUT ;
		SHAPE ABUTMENT ;
		PORT
			 LAYER M2 ;
			RECT 0.0098 5.2952 0.0481 5.3968 ;
			 LAYER M3 ;
			RECT 0.0098 5.2952 0.0481 5.3968 ;
			 LAYER V2 ;
			RECT 0.021 5.371 0.0359 5.3837 ;
		END

		ANTENNAGATEAREA 0.00028148 ;
		ANTENNADIFFAREA 0.00197037 ;
		ANTENNAPARTIALMETALAREA 0.00198 ;
	END TD[6]

	PIN TD[7]
		USE SIGNAL ;
		DIRECTION INPUT ;
		SHAPE ABUTMENT ;
		PORT
			 LAYER M2 ;
			RECT 0.0098 6.0952 0.0481 6.1968 ;
			 LAYER M3 ;
			RECT 0.0098 6.0952 0.0481 6.1968 ;
			 LAYER V2 ;
			RECT 0.021 6.171 0.0359 6.1837 ;
		END

		ANTENNAGATEAREA 0.00028148 ;
		ANTENNADIFFAREA 0.00197037 ;
		ANTENNAPARTIALMETALAREA 0.00198 ;
	END TD[7]

	PIN TD[8]
		USE SIGNAL ;
		DIRECTION INPUT ;
		SHAPE ABUTMENT ;
		PORT
			 LAYER M2 ;
			RECT 0.0098 6.8952 0.0481 6.9968 ;
			 LAYER M3 ;
			RECT 0.0098 6.8952 0.0481 6.9968 ;
			 LAYER V2 ;
			RECT 0.021 6.971 0.0359 6.9837 ;
		END

		ANTENNAGATEAREA 0.00028148 ;
		ANTENNADIFFAREA 0.00197037 ;
		ANTENNAPARTIALMETALAREA 0.00198 ;
	END TD[8]

	PIN TD[9]
		USE SIGNAL ;
		DIRECTION INPUT ;
		SHAPE ABUTMENT ;
		PORT
			 LAYER M2 ;
			RECT 0.0098 7.6952 0.0481 7.7968 ;
			 LAYER M3 ;
			RECT 0.0098 7.6952 0.0481 7.7968 ;
			 LAYER V2 ;
			RECT 0.021 7.771 0.0359 7.7837 ;
		END

		ANTENNAGATEAREA 0.00028148 ;
		ANTENNADIFFAREA 0.00197037 ;
		ANTENNAPARTIALMETALAREA 0.00198 ;
	END TD[9]

	PIN TEN
		USE SIGNAL ;
		DIRECTION INPUT ;
		SHAPE ABUTMENT ;
		PORT
			 LAYER M2 ;
			RECT 0.0098 19.4095 0.0481 19.4476 ;
			 LAYER M3 ;
			RECT 0.0098 19.346 0.0481 19.4476 ;
			 LAYER V2 ;
			RECT 0.0215 19.4218 0.0364 19.4345 ;
		END

		ANTENNAGATEAREA 0.00028148 ;
		ANTENNADIFFAREA 0.00197037 ;
		ANTENNAPARTIALMETALAREA 0.00198 ;
	END TEN

	PIN TGWEN
		USE SIGNAL ;
		DIRECTION INPUT ;
		SHAPE ABUTMENT ;
		PORT
			 LAYER M2 ;
			RECT 0.0098 20.4762 0.0481 20.5143 ;
			 LAYER M3 ;
			RECT 0.0098 20.4127 0.0481 20.5143 ;
			 LAYER V2 ;
			RECT 0.0215 20.4885 0.0364 20.5012 ;
		END

		ANTENNAGATEAREA 0.00028148 ;
		ANTENNADIFFAREA 0.00197037 ;
		ANTENNAPARTIALMETALAREA 0.00198 ;
	END TGWEN

	PIN TWEN[0]
		USE SIGNAL ;
		DIRECTION INPUT ;
		SHAPE ABUTMENT ;
		PORT
			 LAYER M2 ;
			RECT 0.0098 0.3683 0.0481 0.4698 ;
			 LAYER M3 ;
			RECT 0.0098 0.3683 0.0481 0.4698 ;
			 LAYER V2 ;
			RECT 0.021 0.444 0.0359 0.4567 ;
		END

		ANTENNAGATEAREA 0.00028148 ;
		ANTENNADIFFAREA 0.00197037 ;
		ANTENNAPARTIALMETALAREA 0.00198 ;
	END TWEN[0]

	PIN TWEN[10]
		USE SIGNAL ;
		DIRECTION INPUT ;
		SHAPE ABUTMENT ;
		PORT
			 LAYER M2 ;
			RECT 0.0098 8.3683 0.0481 8.4698 ;
			 LAYER M3 ;
			RECT 0.0098 8.3683 0.0481 8.4698 ;
			 LAYER V2 ;
			RECT 0.021 8.444 0.0359 8.4567 ;
		END

		ANTENNAGATEAREA 0.00028148 ;
		ANTENNADIFFAREA 0.00197037 ;
		ANTENNAPARTIALMETALAREA 0.00198 ;
	END TWEN[10]

	PIN TWEN[11]
		USE SIGNAL ;
		DIRECTION INPUT ;
		SHAPE ABUTMENT ;
		PORT
			 LAYER M2 ;
			RECT 0.0098 9.1683 0.0481 9.2698 ;
			 LAYER M3 ;
			RECT 0.0098 9.1683 0.0481 9.2698 ;
			 LAYER V2 ;
			RECT 0.021 9.244 0.0359 9.2567 ;
		END

		ANTENNAGATEAREA 0.00028148 ;
		ANTENNADIFFAREA 0.00197037 ;
		ANTENNAPARTIALMETALAREA 0.00198 ;
	END TWEN[11]

	PIN TWEN[12]
		USE SIGNAL ;
		DIRECTION INPUT ;
		SHAPE ABUTMENT ;
		PORT
			 LAYER M2 ;
			RECT 0.0098 9.9683 0.0481 10.0698 ;
			 LAYER M3 ;
			RECT 0.0098 9.9683 0.0481 10.0698 ;
			 LAYER V2 ;
			RECT 0.021 10.044 0.0359 10.0567 ;
		END

		ANTENNAGATEAREA 0.00028148 ;
		ANTENNADIFFAREA 0.00197037 ;
		ANTENNAPARTIALMETALAREA 0.00198 ;
	END TWEN[12]

	PIN TWEN[13]
		USE SIGNAL ;
		DIRECTION INPUT ;
		SHAPE ABUTMENT ;
		PORT
			 LAYER M2 ;
			RECT 0.0098 10.7683 0.0481 10.8698 ;
			 LAYER M3 ;
			RECT 0.0098 10.7683 0.0481 10.8698 ;
			 LAYER V2 ;
			RECT 0.021 10.844 0.0359 10.8567 ;
		END

		ANTENNAGATEAREA 0.00028148 ;
		ANTENNADIFFAREA 0.00197037 ;
		ANTENNAPARTIALMETALAREA 0.00198 ;
	END TWEN[13]

	PIN TWEN[14]
		USE SIGNAL ;
		DIRECTION INPUT ;
		SHAPE ABUTMENT ;
		PORT
			 LAYER M2 ;
			RECT 0.0098 11.5683 0.0481 11.6698 ;
			 LAYER M3 ;
			RECT 0.0098 11.5683 0.0481 11.6698 ;
			 LAYER V2 ;
			RECT 0.021 11.644 0.0359 11.6567 ;
		END

		ANTENNAGATEAREA 0.00028148 ;
		ANTENNADIFFAREA 0.00197037 ;
		ANTENNAPARTIALMETALAREA 0.00198 ;
	END TWEN[14]

	PIN TWEN[15]
		USE SIGNAL ;
		DIRECTION INPUT ;
		SHAPE ABUTMENT ;
		PORT
			 LAYER M2 ;
			RECT 0.0098 12.3683 0.0481 12.4698 ;
			 LAYER M3 ;
			RECT 0.0098 12.3683 0.0481 12.4698 ;
			 LAYER V2 ;
			RECT 0.021 12.444 0.0359 12.4567 ;
		END

		ANTENNAGATEAREA 0.00028148 ;
		ANTENNADIFFAREA 0.00197037 ;
		ANTENNAPARTIALMETALAREA 0.00198 ;
	END TWEN[15]

	PIN TWEN[16]
		USE SIGNAL ;
		DIRECTION INPUT ;
		SHAPE ABUTMENT ;
		PORT
			 LAYER M2 ;
			RECT 0.0098 13.1683 0.0481 13.2698 ;
			 LAYER M3 ;
			RECT 0.0098 13.1683 0.0481 13.2698 ;
			 LAYER V2 ;
			RECT 0.021 13.244 0.0359 13.2567 ;
		END

		ANTENNAGATEAREA 0.00028148 ;
		ANTENNADIFFAREA 0.00197037 ;
		ANTENNAPARTIALMETALAREA 0.00198 ;
	END TWEN[16]

	PIN TWEN[17]
		USE SIGNAL ;
		DIRECTION INPUT ;
		SHAPE ABUTMENT ;
		PORT
			 LAYER M2 ;
			RECT 0.0098 13.9683 0.0481 14.0698 ;
			 LAYER M3 ;
			RECT 0.0098 13.9683 0.0481 14.0698 ;
			 LAYER V2 ;
			RECT 0.021 14.044 0.0359 14.0567 ;
		END

		ANTENNAGATEAREA 0.00028148 ;
		ANTENNADIFFAREA 0.00197037 ;
		ANTENNAPARTIALMETALAREA 0.00198 ;
	END TWEN[17]

	PIN TWEN[18]
		USE SIGNAL ;
		DIRECTION INPUT ;
		SHAPE ABUTMENT ;
		PORT
			 LAYER M2 ;
			RECT 0.0098 14.7683 0.0481 14.8698 ;
			 LAYER M3 ;
			RECT 0.0098 14.7683 0.0481 14.8698 ;
			 LAYER V2 ;
			RECT 0.021 14.844 0.0359 14.8567 ;
		END

		ANTENNAGATEAREA 0.00028148 ;
		ANTENNADIFFAREA 0.00197037 ;
		ANTENNAPARTIALMETALAREA 0.00198 ;
	END TWEN[18]

	PIN TWEN[19]
		USE SIGNAL ;
		DIRECTION INPUT ;
		SHAPE ABUTMENT ;
		PORT
			 LAYER M2 ;
			RECT 0.0098 15.5683 0.0481 15.6698 ;
			 LAYER M3 ;
			RECT 0.0098 15.5683 0.0481 15.6698 ;
			 LAYER V2 ;
			RECT 0.021 15.644 0.0359 15.6567 ;
		END

		ANTENNAGATEAREA 0.00028148 ;
		ANTENNADIFFAREA 0.00197037 ;
		ANTENNAPARTIALMETALAREA 0.00198 ;
	END TWEN[19]

	PIN TWEN[1]
		USE SIGNAL ;
		DIRECTION INPUT ;
		SHAPE ABUTMENT ;
		PORT
			 LAYER M2 ;
			RECT 0.0098 1.1683 0.0481 1.2698 ;
			 LAYER M3 ;
			RECT 0.0098 1.1683 0.0481 1.2698 ;
			 LAYER V2 ;
			RECT 0.021 1.244 0.0359 1.2567 ;
		END

		ANTENNAGATEAREA 0.00028148 ;
		ANTENNADIFFAREA 0.00197037 ;
		ANTENNAPARTIALMETALAREA 0.00198 ;
	END TWEN[1]

	PIN TWEN[20]
		USE SIGNAL ;
		DIRECTION INPUT ;
		SHAPE ABUTMENT ;
		PORT
			 LAYER M2 ;
			RECT 0.0098 16.3683 0.0481 16.4698 ;
			 LAYER M3 ;
			RECT 0.0098 16.3683 0.0481 16.4698 ;
			 LAYER V2 ;
			RECT 0.021 16.444 0.0359 16.4567 ;
		END

		ANTENNAGATEAREA 0.00028148 ;
		ANTENNADIFFAREA 0.00197037 ;
		ANTENNAPARTIALMETALAREA 0.00198 ;
	END TWEN[20]

	PIN TWEN[21]
		USE SIGNAL ;
		DIRECTION INPUT ;
		SHAPE ABUTMENT ;
		PORT
			 LAYER M2 ;
			RECT 0.0098 17.1683 0.0481 17.2698 ;
			 LAYER M3 ;
			RECT 0.0098 17.1683 0.0481 17.2698 ;
			 LAYER V2 ;
			RECT 0.021 17.244 0.0359 17.2567 ;
		END

		ANTENNAGATEAREA 0.00028148 ;
		ANTENNADIFFAREA 0.00197037 ;
		ANTENNAPARTIALMETALAREA 0.00198 ;
	END TWEN[21]

	PIN TWEN[22]
		USE SIGNAL ;
		DIRECTION INPUT ;
		SHAPE ABUTMENT ;
		PORT
			 LAYER M2 ;
			RECT 0.0098 25.9111 0.0481 26.0127 ;
			 LAYER M3 ;
			RECT 0.0098 25.9111 0.0481 26.0127 ;
			 LAYER V2 ;
			RECT 0.021 25.9242 0.0359 25.9369 ;
		END

		ANTENNAGATEAREA 0.00028148 ;
		ANTENNADIFFAREA 0.00197037 ;
		ANTENNAPARTIALMETALAREA 0.00198 ;
	END TWEN[22]

	PIN TWEN[23]
		USE SIGNAL ;
		DIRECTION INPUT ;
		SHAPE ABUTMENT ;
		PORT
			 LAYER M2 ;
			RECT 0.0098 26.7111 0.0481 26.8127 ;
			 LAYER M3 ;
			RECT 0.0098 26.7111 0.0481 26.8127 ;
			 LAYER V2 ;
			RECT 0.021 26.7242 0.0359 26.7369 ;
		END

		ANTENNAGATEAREA 0.00028148 ;
		ANTENNADIFFAREA 0.00197037 ;
		ANTENNAPARTIALMETALAREA 0.00198 ;
	END TWEN[23]

	PIN TWEN[24]
		USE SIGNAL ;
		DIRECTION INPUT ;
		SHAPE ABUTMENT ;
		PORT
			 LAYER M2 ;
			RECT 0.0098 27.5111 0.0481 27.6127 ;
			 LAYER M3 ;
			RECT 0.0098 27.5111 0.0481 27.6127 ;
			 LAYER V2 ;
			RECT 0.021 27.5242 0.0359 27.5369 ;
		END

		ANTENNAGATEAREA 0.00028148 ;
		ANTENNADIFFAREA 0.00197037 ;
		ANTENNAPARTIALMETALAREA 0.00198 ;
	END TWEN[24]

	PIN TWEN[25]
		USE SIGNAL ;
		DIRECTION INPUT ;
		SHAPE ABUTMENT ;
		PORT
			 LAYER M2 ;
			RECT 0.0098 28.3111 0.0481 28.4127 ;
			 LAYER M3 ;
			RECT 0.0098 28.3111 0.0481 28.4127 ;
			 LAYER V2 ;
			RECT 0.021 28.3242 0.0359 28.3369 ;
		END

		ANTENNAGATEAREA 0.00028148 ;
		ANTENNADIFFAREA 0.00197037 ;
		ANTENNAPARTIALMETALAREA 0.00198 ;
	END TWEN[25]

	PIN TWEN[26]
		USE SIGNAL ;
		DIRECTION INPUT ;
		SHAPE ABUTMENT ;
		PORT
			 LAYER M2 ;
			RECT 0.0098 29.1111 0.0481 29.2127 ;
			 LAYER M3 ;
			RECT 0.0098 29.1111 0.0481 29.2127 ;
			 LAYER V2 ;
			RECT 0.021 29.1242 0.0359 29.1369 ;
		END

		ANTENNAGATEAREA 0.00028148 ;
		ANTENNADIFFAREA 0.00197037 ;
		ANTENNAPARTIALMETALAREA 0.00198 ;
	END TWEN[26]

	PIN TWEN[27]
		USE SIGNAL ;
		DIRECTION INPUT ;
		SHAPE ABUTMENT ;
		PORT
			 LAYER M2 ;
			RECT 0.0098 29.9111 0.0481 30.0127 ;
			 LAYER M3 ;
			RECT 0.0098 29.9111 0.0481 30.0127 ;
			 LAYER V2 ;
			RECT 0.021 29.9242 0.0359 29.9369 ;
		END

		ANTENNAGATEAREA 0.00028148 ;
		ANTENNADIFFAREA 0.00197037 ;
		ANTENNAPARTIALMETALAREA 0.00198 ;
	END TWEN[27]

	PIN TWEN[28]
		USE SIGNAL ;
		DIRECTION INPUT ;
		SHAPE ABUTMENT ;
		PORT
			 LAYER M2 ;
			RECT 0.0098 30.7111 0.0481 30.8127 ;
			 LAYER M3 ;
			RECT 0.0098 30.7111 0.0481 30.8127 ;
			 LAYER V2 ;
			RECT 0.021 30.7242 0.0359 30.7369 ;
		END

		ANTENNAGATEAREA 0.00028148 ;
		ANTENNADIFFAREA 0.00197037 ;
		ANTENNAPARTIALMETALAREA 0.00198 ;
	END TWEN[28]

	PIN TWEN[29]
		USE SIGNAL ;
		DIRECTION INPUT ;
		SHAPE ABUTMENT ;
		PORT
			 LAYER M2 ;
			RECT 0.0098 31.5111 0.0481 31.6127 ;
			 LAYER M3 ;
			RECT 0.0098 31.5111 0.0481 31.6127 ;
			 LAYER V2 ;
			RECT 0.021 31.5242 0.0359 31.5369 ;
		END

		ANTENNAGATEAREA 0.00028148 ;
		ANTENNADIFFAREA 0.00197037 ;
		ANTENNAPARTIALMETALAREA 0.00198 ;
	END TWEN[29]

	PIN TWEN[2]
		USE SIGNAL ;
		DIRECTION INPUT ;
		SHAPE ABUTMENT ;
		PORT
			 LAYER M2 ;
			RECT 0.0098 1.9683 0.0481 2.0698 ;
			 LAYER M3 ;
			RECT 0.0098 1.9683 0.0481 2.0698 ;
			 LAYER V2 ;
			RECT 0.021 2.044 0.0359 2.0567 ;
		END

		ANTENNAGATEAREA 0.00028148 ;
		ANTENNADIFFAREA 0.00197037 ;
		ANTENNAPARTIALMETALAREA 0.00198 ;
	END TWEN[2]

	PIN TWEN[30]
		USE SIGNAL ;
		DIRECTION INPUT ;
		SHAPE ABUTMENT ;
		PORT
			 LAYER M2 ;
			RECT 0.0098 32.3111 0.0481 32.4127 ;
			 LAYER M3 ;
			RECT 0.0098 32.3111 0.0481 32.4127 ;
			 LAYER V2 ;
			RECT 0.021 32.3242 0.0359 32.3369 ;
		END

		ANTENNAGATEAREA 0.00028148 ;
		ANTENNADIFFAREA 0.00197037 ;
		ANTENNAPARTIALMETALAREA 0.00198 ;
	END TWEN[30]

	PIN TWEN[31]
		USE SIGNAL ;
		DIRECTION INPUT ;
		SHAPE ABUTMENT ;
		PORT
			 LAYER M2 ;
			RECT 0.0098 33.1111 0.0481 33.2127 ;
			 LAYER M3 ;
			RECT 0.0098 33.1111 0.0481 33.2127 ;
			 LAYER V2 ;
			RECT 0.021 33.1242 0.0359 33.1369 ;
		END

		ANTENNAGATEAREA 0.00028148 ;
		ANTENNADIFFAREA 0.00197037 ;
		ANTENNAPARTIALMETALAREA 0.00198 ;
	END TWEN[31]

	PIN TWEN[32]
		USE SIGNAL ;
		DIRECTION INPUT ;
		SHAPE ABUTMENT ;
		PORT
			 LAYER M2 ;
			RECT 0.0098 33.9111 0.0481 34.0127 ;
			 LAYER M3 ;
			RECT 0.0098 33.9111 0.0481 34.0127 ;
			 LAYER V2 ;
			RECT 0.021 33.9242 0.0359 33.9369 ;
		END

		ANTENNAGATEAREA 0.00028148 ;
		ANTENNADIFFAREA 0.00197037 ;
		ANTENNAPARTIALMETALAREA 0.00198 ;
	END TWEN[32]

	PIN TWEN[33]
		USE SIGNAL ;
		DIRECTION INPUT ;
		SHAPE ABUTMENT ;
		PORT
			 LAYER M2 ;
			RECT 0.0098 34.7111 0.0481 34.8127 ;
			 LAYER M3 ;
			RECT 0.0098 34.7111 0.0481 34.8127 ;
			 LAYER V2 ;
			RECT 0.021 34.7242 0.0359 34.7369 ;
		END

		ANTENNAGATEAREA 0.00028148 ;
		ANTENNADIFFAREA 0.00197037 ;
		ANTENNAPARTIALMETALAREA 0.00198 ;
	END TWEN[33]

	PIN TWEN[34]
		USE SIGNAL ;
		DIRECTION INPUT ;
		SHAPE ABUTMENT ;
		PORT
			 LAYER M2 ;
			RECT 0.0098 35.5111 0.0481 35.6127 ;
			 LAYER M3 ;
			RECT 0.0098 35.5111 0.0481 35.6127 ;
			 LAYER V2 ;
			RECT 0.021 35.5242 0.0359 35.5369 ;
		END

		ANTENNAGATEAREA 0.00028148 ;
		ANTENNADIFFAREA 0.00197037 ;
		ANTENNAPARTIALMETALAREA 0.00198 ;
	END TWEN[34]

	PIN TWEN[35]
		USE SIGNAL ;
		DIRECTION INPUT ;
		SHAPE ABUTMENT ;
		PORT
			 LAYER M2 ;
			RECT 0.0098 36.3111 0.0481 36.4127 ;
			 LAYER M3 ;
			RECT 0.0098 36.3111 0.0481 36.4127 ;
			 LAYER V2 ;
			RECT 0.021 36.3242 0.0359 36.3369 ;
		END

		ANTENNAGATEAREA 0.00028148 ;
		ANTENNADIFFAREA 0.00197037 ;
		ANTENNAPARTIALMETALAREA 0.00198 ;
	END TWEN[35]

	PIN TWEN[36]
		USE SIGNAL ;
		DIRECTION INPUT ;
		SHAPE ABUTMENT ;
		PORT
			 LAYER M2 ;
			RECT 0.0098 37.1111 0.0481 37.2127 ;
			 LAYER M3 ;
			RECT 0.0098 37.1111 0.0481 37.2127 ;
			 LAYER V2 ;
			RECT 0.021 37.1242 0.0359 37.1369 ;
		END

		ANTENNAGATEAREA 0.00028148 ;
		ANTENNADIFFAREA 0.00197037 ;
		ANTENNAPARTIALMETALAREA 0.00198 ;
	END TWEN[36]

	PIN TWEN[37]
		USE SIGNAL ;
		DIRECTION INPUT ;
		SHAPE ABUTMENT ;
		PORT
			 LAYER M2 ;
			RECT 0.0098 37.9111 0.0481 38.0127 ;
			 LAYER M3 ;
			RECT 0.0098 37.9111 0.0481 38.0127 ;
			 LAYER V2 ;
			RECT 0.021 37.9242 0.0359 37.9369 ;
		END

		ANTENNAGATEAREA 0.00028148 ;
		ANTENNADIFFAREA 0.00197037 ;
		ANTENNAPARTIALMETALAREA 0.00198 ;
	END TWEN[37]

	PIN TWEN[38]
		USE SIGNAL ;
		DIRECTION INPUT ;
		SHAPE ABUTMENT ;
		PORT
			 LAYER M2 ;
			RECT 0.0098 38.7111 0.0481 38.8127 ;
			 LAYER M3 ;
			RECT 0.0098 38.7111 0.0481 38.8127 ;
			 LAYER V2 ;
			RECT 0.021 38.7242 0.0359 38.7369 ;
		END

		ANTENNAGATEAREA 0.00028148 ;
		ANTENNADIFFAREA 0.00197037 ;
		ANTENNAPARTIALMETALAREA 0.00198 ;
	END TWEN[38]

	PIN TWEN[39]
		USE SIGNAL ;
		DIRECTION INPUT ;
		SHAPE ABUTMENT ;
		PORT
			 LAYER M2 ;
			RECT 0.0098 39.5111 0.0481 39.6127 ;
			 LAYER M3 ;
			RECT 0.0098 39.5111 0.0481 39.6127 ;
			 LAYER V2 ;
			RECT 0.021 39.5242 0.0359 39.5369 ;
		END

		ANTENNAGATEAREA 0.00028148 ;
		ANTENNADIFFAREA 0.00197037 ;
		ANTENNAPARTIALMETALAREA 0.00198 ;
	END TWEN[39]

	PIN TWEN[3]
		USE SIGNAL ;
		DIRECTION INPUT ;
		SHAPE ABUTMENT ;
		PORT
			 LAYER M2 ;
			RECT 0.0098 2.7683 0.0481 2.8698 ;
			 LAYER M3 ;
			RECT 0.0098 2.7683 0.0481 2.8698 ;
			 LAYER V2 ;
			RECT 0.021 2.844 0.0359 2.8567 ;
		END

		ANTENNAGATEAREA 0.00028148 ;
		ANTENNADIFFAREA 0.00197037 ;
		ANTENNAPARTIALMETALAREA 0.00198 ;
	END TWEN[3]

	PIN TWEN[40]
		USE SIGNAL ;
		DIRECTION INPUT ;
		SHAPE ABUTMENT ;
		PORT
			 LAYER M2 ;
			RECT 0.0098 40.3111 0.0481 40.4127 ;
			 LAYER M3 ;
			RECT 0.0098 40.3111 0.0481 40.4127 ;
			 LAYER V2 ;
			RECT 0.021 40.3242 0.0359 40.3369 ;
		END

		ANTENNAGATEAREA 0.00028148 ;
		ANTENNADIFFAREA 0.00197037 ;
		ANTENNAPARTIALMETALAREA 0.00198 ;
	END TWEN[40]

	PIN TWEN[41]
		USE SIGNAL ;
		DIRECTION INPUT ;
		SHAPE ABUTMENT ;
		PORT
			 LAYER M2 ;
			RECT 0.0098 41.1111 0.0481 41.2127 ;
			 LAYER M3 ;
			RECT 0.0098 41.1111 0.0481 41.2127 ;
			 LAYER V2 ;
			RECT 0.021 41.1242 0.0359 41.1369 ;
		END

		ANTENNAGATEAREA 0.00028148 ;
		ANTENNADIFFAREA 0.00197037 ;
		ANTENNAPARTIALMETALAREA 0.00198 ;
	END TWEN[41]

	PIN TWEN[42]
		USE SIGNAL ;
		DIRECTION INPUT ;
		SHAPE ABUTMENT ;
		PORT
			 LAYER M2 ;
			RECT 0.0098 41.9111 0.0481 42.0127 ;
			 LAYER M3 ;
			RECT 0.0098 41.9111 0.0481 42.0127 ;
			 LAYER V2 ;
			RECT 0.021 41.9242 0.0359 41.9369 ;
		END

		ANTENNAGATEAREA 0.00028148 ;
		ANTENNADIFFAREA 0.00197037 ;
		ANTENNAPARTIALMETALAREA 0.00198 ;
	END TWEN[42]

	PIN TWEN[43]
		USE SIGNAL ;
		DIRECTION INPUT ;
		SHAPE ABUTMENT ;
		PORT
			 LAYER M2 ;
			RECT 0.0098 42.7111 0.0481 42.8127 ;
			 LAYER M3 ;
			RECT 0.0098 42.7111 0.0481 42.8127 ;
			 LAYER V2 ;
			RECT 0.021 42.7242 0.0359 42.7369 ;
		END

		ANTENNAGATEAREA 0.00028148 ;
		ANTENNADIFFAREA 0.00197037 ;
		ANTENNAPARTIALMETALAREA 0.00198 ;
	END TWEN[43]

	PIN TWEN[44]
		USE SIGNAL ;
		DIRECTION INPUT ;
		SHAPE ABUTMENT ;
		PORT
			 LAYER M2 ;
			RECT 0.0098 43.5111 0.0481 43.6127 ;
			 LAYER M3 ;
			RECT 0.0098 43.5111 0.0481 43.6127 ;
			 LAYER V2 ;
			RECT 0.021 43.5242 0.0359 43.5369 ;
		END

		ANTENNAGATEAREA 0.00028148 ;
		ANTENNADIFFAREA 0.00197037 ;
		ANTENNAPARTIALMETALAREA 0.00198 ;
	END TWEN[44]

	PIN TWEN[4]
		USE SIGNAL ;
		DIRECTION INPUT ;
		SHAPE ABUTMENT ;
		PORT
			 LAYER M2 ;
			RECT 0.0098 3.5683 0.0481 3.6698 ;
			 LAYER M3 ;
			RECT 0.0098 3.5683 0.0481 3.6698 ;
			 LAYER V2 ;
			RECT 0.021 3.644 0.0359 3.6567 ;
		END

		ANTENNAGATEAREA 0.00028148 ;
		ANTENNADIFFAREA 0.00197037 ;
		ANTENNAPARTIALMETALAREA 0.00198 ;
	END TWEN[4]

	PIN TWEN[5]
		USE SIGNAL ;
		DIRECTION INPUT ;
		SHAPE ABUTMENT ;
		PORT
			 LAYER M2 ;
			RECT 0.0098 4.3683 0.0481 4.4698 ;
			 LAYER M3 ;
			RECT 0.0098 4.3683 0.0481 4.4698 ;
			 LAYER V2 ;
			RECT 0.021 4.444 0.0359 4.4567 ;
		END

		ANTENNAGATEAREA 0.00028148 ;
		ANTENNADIFFAREA 0.00197037 ;
		ANTENNAPARTIALMETALAREA 0.00198 ;
	END TWEN[5]

	PIN TWEN[6]
		USE SIGNAL ;
		DIRECTION INPUT ;
		SHAPE ABUTMENT ;
		PORT
			 LAYER M2 ;
			RECT 0.0098 5.1683 0.0481 5.2698 ;
			 LAYER M3 ;
			RECT 0.0098 5.1683 0.0481 5.2698 ;
			 LAYER V2 ;
			RECT 0.021 5.244 0.0359 5.2567 ;
		END

		ANTENNAGATEAREA 0.00028148 ;
		ANTENNADIFFAREA 0.00197037 ;
		ANTENNAPARTIALMETALAREA 0.00198 ;
	END TWEN[6]

	PIN TWEN[7]
		USE SIGNAL ;
		DIRECTION INPUT ;
		SHAPE ABUTMENT ;
		PORT
			 LAYER M2 ;
			RECT 0.0098 5.9683 0.0481 6.0698 ;
			 LAYER M3 ;
			RECT 0.0098 5.9683 0.0481 6.0698 ;
			 LAYER V2 ;
			RECT 0.021 6.044 0.0359 6.0567 ;
		END

		ANTENNAGATEAREA 0.00028148 ;
		ANTENNADIFFAREA 0.00197037 ;
		ANTENNAPARTIALMETALAREA 0.00198 ;
	END TWEN[7]

	PIN TWEN[8]
		USE SIGNAL ;
		DIRECTION INPUT ;
		SHAPE ABUTMENT ;
		PORT
			 LAYER M2 ;
			RECT 0.0098 6.7683 0.0481 6.8698 ;
			 LAYER M3 ;
			RECT 0.0098 6.7683 0.0481 6.8698 ;
			 LAYER V2 ;
			RECT 0.021 6.844 0.0359 6.8567 ;
		END

		ANTENNAGATEAREA 0.00028148 ;
		ANTENNADIFFAREA 0.00197037 ;
		ANTENNAPARTIALMETALAREA 0.00198 ;
	END TWEN[8]

	PIN TWEN[9]
		USE SIGNAL ;
		DIRECTION INPUT ;
		SHAPE ABUTMENT ;
		PORT
			 LAYER M2 ;
			RECT 0.0098 7.5683 0.0481 7.6698 ;
			 LAYER M3 ;
			RECT 0.0098 7.5683 0.0481 7.6698 ;
			 LAYER V2 ;
			RECT 0.021 7.644 0.0359 7.6567 ;
		END

		ANTENNAGATEAREA 0.00028148 ;
		ANTENNADIFFAREA 0.00197037 ;
		ANTENNAPARTIALMETALAREA 0.00198 ;
	END TWEN[9]

	PIN VDDCE
		USE POWER ;
		DIRECTION INOUT ;
		PORT
			 LAYER M4 ;
			RECT 0.2105 42.9683 8.463 43.0159 ;
			 LAYER V3 ;
			RECT 4.9686 42.9762 4.9835 43.0079 ;
			RECT 8.0785 42.9762 8.0934 43.0079 ;
			RECT 8.3706 42.9762 8.3855 43.0079 ;
		END

		PORT
			 LAYER M4 ;
			RECT 0.2105 27.7683 8.463 27.8159 ;
			 LAYER V3 ;
			RECT 4.9686 27.7762 4.9835 27.8079 ;
			RECT 8.0785 27.7762 8.0934 27.8079 ;
			RECT 8.3706 27.7762 8.3855 27.8079 ;
		END

		PORT
			 LAYER M4 ;
			RECT 0.2105 26.9683 8.463 27.0159 ;
			 LAYER V3 ;
			RECT 4.9686 26.9762 4.9835 27.0079 ;
			RECT 8.0785 26.9762 8.0934 27.0079 ;
			RECT 8.3706 26.9762 8.3855 27.0079 ;
		END

		PORT
			 LAYER M4 ;
			RECT 0.2105 26.1683 8.463 26.2159 ;
			 LAYER V3 ;
			RECT 4.9686 26.1762 4.9835 26.2079 ;
			RECT 8.0785 26.1762 8.0934 26.2079 ;
			RECT 8.3706 26.1762 8.3855 26.2079 ;
		END

		PORT
			 LAYER M4 ;
			RECT 0.2105 25.3683 8.463 25.4159 ;
			 LAYER V3 ;
			RECT 4.9686 25.3762 4.9835 25.4079 ;
			RECT 8.0785 25.3762 8.0934 25.4079 ;
			RECT 8.3706 25.3762 8.3855 25.4079 ;
		END

		PORT
			 LAYER M4 ;
			RECT 0.2105 42.1683 8.463 42.2159 ;
			 LAYER V3 ;
			RECT 4.9686 42.1762 4.9835 42.2079 ;
			RECT 8.0785 42.1762 8.0934 42.2079 ;
			RECT 8.3706 42.1762 8.3855 42.2079 ;
		END

		PORT
			 LAYER M4 ;
			RECT 0.2105 17.7651 8.463 17.8127 ;
			 LAYER V3 ;
			RECT 4.9686 17.773 4.9835 17.8048 ;
			RECT 8.0785 17.773 8.0934 17.8048 ;
			RECT 8.3706 17.773 8.3855 17.8048 ;
		END

		PORT
			 LAYER M4 ;
			RECT 0.2105 16.9651 8.463 17.0127 ;
			 LAYER V3 ;
			RECT 4.9686 16.973 4.9835 17.0048 ;
			RECT 8.0785 16.973 8.0934 17.0048 ;
			RECT 8.3706 16.973 8.3855 17.0048 ;
		END

		PORT
			 LAYER M4 ;
			RECT 0.2105 16.1651 8.463 16.2127 ;
			 LAYER V3 ;
			RECT 4.9686 16.173 4.9835 16.2048 ;
			RECT 8.0785 16.173 8.0934 16.2048 ;
			RECT 8.3706 16.173 8.3855 16.2048 ;
		END

		PORT
			 LAYER M4 ;
			RECT 0.2105 15.3651 8.463 15.4127 ;
			 LAYER V3 ;
			RECT 4.9686 15.373 4.9835 15.4048 ;
			RECT 8.0785 15.373 8.0934 15.4048 ;
			RECT 8.3706 15.373 8.3855 15.4048 ;
		END

		PORT
			 LAYER M4 ;
			RECT 0.2105 41.3683 8.463 41.4159 ;
			 LAYER V3 ;
			RECT 4.9686 41.3762 4.9835 41.4079 ;
			RECT 8.0785 41.3762 8.0934 41.4079 ;
			RECT 8.3706 41.3762 8.3855 41.4079 ;
		END

		PORT
			 LAYER M4 ;
			RECT 0.2105 14.5651 8.463 14.6127 ;
			 LAYER V3 ;
			RECT 4.9686 14.573 4.9835 14.6048 ;
			RECT 8.0785 14.573 8.0934 14.6048 ;
			RECT 8.3706 14.573 8.3855 14.6048 ;
		END

		PORT
			 LAYER M4 ;
			RECT 0.2105 13.7651 8.463 13.8127 ;
			 LAYER V3 ;
			RECT 4.9686 13.773 4.9835 13.8048 ;
			RECT 8.0785 13.773 8.0934 13.8048 ;
			RECT 8.3706 13.773 8.3855 13.8048 ;
		END

		PORT
			 LAYER M4 ;
			RECT 0.2105 12.9651 8.463 13.0127 ;
			 LAYER V3 ;
			RECT 4.9686 12.973 4.9835 13.0048 ;
			RECT 8.0785 12.973 8.0934 13.0048 ;
			RECT 8.3706 12.973 8.3855 13.0048 ;
		END

		PORT
			 LAYER M4 ;
			RECT 0.2105 12.1651 8.463 12.2127 ;
			 LAYER V3 ;
			RECT 4.9686 12.173 4.9835 12.2048 ;
			RECT 8.0785 12.173 8.0934 12.2048 ;
			RECT 8.3706 12.173 8.3855 12.2048 ;
		END

		PORT
			 LAYER M4 ;
			RECT 0.2105 11.3651 8.463 11.4127 ;
			 LAYER V3 ;
			RECT 4.9686 11.373 4.9835 11.4048 ;
			RECT 8.0785 11.373 8.0934 11.4048 ;
			RECT 8.3706 11.373 8.3855 11.4048 ;
		END

		PORT
			 LAYER M4 ;
			RECT 0.2105 10.5651 8.463 10.6127 ;
			 LAYER V3 ;
			RECT 4.9686 10.573 4.9835 10.6048 ;
			RECT 8.0785 10.573 8.0934 10.6048 ;
			RECT 8.3706 10.573 8.3855 10.6048 ;
		END

		PORT
			 LAYER M4 ;
			RECT 0.2105 9.7651 8.463 9.8127 ;
			 LAYER V3 ;
			RECT 4.9686 9.773 4.9835 9.8048 ;
			RECT 8.0785 9.773 8.0934 9.8048 ;
			RECT 8.3706 9.773 8.3855 9.8048 ;
		END

		PORT
			 LAYER M4 ;
			RECT 0.2105 8.9651 8.463 9.0127 ;
			 LAYER V3 ;
			RECT 4.9686 8.973 4.9835 9.0048 ;
			RECT 8.0785 8.973 8.0934 9.0048 ;
			RECT 8.3706 8.973 8.3855 9.0048 ;
		END

		PORT
			 LAYER M4 ;
			RECT 0.2105 8.1651 8.463 8.2127 ;
			 LAYER V3 ;
			RECT 4.9686 8.173 4.9835 8.2048 ;
			RECT 8.0785 8.173 8.0934 8.2048 ;
			RECT 8.3706 8.173 8.3855 8.2048 ;
		END

		PORT
			 LAYER M4 ;
			RECT 0.2105 7.3651 8.463 7.4127 ;
			 LAYER V3 ;
			RECT 4.9686 7.373 4.9835 7.4048 ;
			RECT 8.0785 7.373 8.0934 7.4048 ;
			RECT 8.3706 7.373 8.3855 7.4048 ;
		END

		PORT
			 LAYER M4 ;
			RECT 0.2105 40.5683 8.463 40.6159 ;
			 LAYER V3 ;
			RECT 4.9686 40.5762 4.9835 40.6079 ;
			RECT 8.0785 40.5762 8.0934 40.6079 ;
			RECT 8.3706 40.5762 8.3855 40.6079 ;
		END

		PORT
			 LAYER M4 ;
			RECT 0.2105 6.5651 8.463 6.6127 ;
			 LAYER V3 ;
			RECT 4.9686 6.573 4.9835 6.6048 ;
			RECT 8.0785 6.573 8.0934 6.6048 ;
			RECT 8.3706 6.573 8.3855 6.6048 ;
		END

		PORT
			 LAYER M4 ;
			RECT 0.2105 5.7651 8.463 5.8127 ;
			 LAYER V3 ;
			RECT 4.9686 5.773 4.9835 5.8048 ;
			RECT 8.0785 5.773 8.0934 5.8048 ;
			RECT 8.3706 5.773 8.3855 5.8048 ;
		END

		PORT
			 LAYER M4 ;
			RECT 0.2105 4.9651 8.463 5.0127 ;
			 LAYER V3 ;
			RECT 4.9686 4.973 4.9835 5.0048 ;
			RECT 8.0785 4.973 8.0934 5.0048 ;
			RECT 8.3706 4.973 8.3855 5.0048 ;
		END

		PORT
			 LAYER M4 ;
			RECT 0.2105 4.1651 8.463 4.2127 ;
			 LAYER V3 ;
			RECT 4.9686 4.173 4.9835 4.2048 ;
			RECT 8.0785 4.173 8.0934 4.2048 ;
			RECT 8.3706 4.173 8.3855 4.2048 ;
		END

		PORT
			 LAYER M4 ;
			RECT 0.2105 3.3651 8.463 3.4127 ;
			 LAYER V3 ;
			RECT 4.9686 3.373 4.9835 3.4048 ;
			RECT 8.0785 3.373 8.0934 3.4048 ;
			RECT 8.3706 3.373 8.3855 3.4048 ;
		END

		PORT
			 LAYER M4 ;
			RECT 0.2105 2.5651 8.463 2.6127 ;
			 LAYER V3 ;
			RECT 4.9686 2.573 4.9835 2.6048 ;
			RECT 8.0785 2.573 8.0934 2.6048 ;
			RECT 8.3706 2.573 8.3855 2.6048 ;
		END

		PORT
			 LAYER M4 ;
			RECT 0.2105 1.7651 8.463 1.8127 ;
			 LAYER V3 ;
			RECT 4.9686 1.773 4.9835 1.8048 ;
			RECT 8.0785 1.773 8.0934 1.8048 ;
			RECT 8.3706 1.773 8.3855 1.8048 ;
		END

		PORT
			 LAYER M4 ;
			RECT 0.2105 0.9651 8.463 1.0127 ;
			 LAYER V3 ;
			RECT 4.9686 0.973 4.9835 1.0048 ;
			RECT 8.0785 0.973 8.0934 1.0048 ;
			RECT 8.3706 0.973 8.3855 1.0048 ;
		END

		PORT
			 LAYER M4 ;
			RECT 0.2105 39.7683 8.463 39.8159 ;
			 LAYER V3 ;
			RECT 4.9686 39.7762 4.9835 39.8079 ;
			RECT 8.0785 39.7762 8.0934 39.8079 ;
			RECT 8.3706 39.7762 8.3855 39.8079 ;
		END

		PORT
			 LAYER M4 ;
			RECT 0.2105 38.9683 8.463 39.0159 ;
			 LAYER V3 ;
			RECT 4.9686 38.9762 4.9835 39.0079 ;
			RECT 8.0785 38.9762 8.0934 39.0079 ;
			RECT 8.3706 38.9762 8.3855 39.0079 ;
		END

		PORT
			 LAYER M4 ;
			RECT 0.2105 38.1683 8.463 38.2159 ;
			 LAYER V3 ;
			RECT 4.9686 38.1762 4.9835 38.2079 ;
			RECT 8.0785 38.1762 8.0934 38.2079 ;
			RECT 8.3706 38.1762 8.3855 38.2079 ;
		END

		PORT
			 LAYER M4 ;
			RECT 0.2105 37.3683 8.463 37.4159 ;
			 LAYER V3 ;
			RECT 4.9686 37.3762 4.9835 37.4079 ;
			RECT 8.0785 37.3762 8.0934 37.4079 ;
			RECT 8.3706 37.3762 8.3855 37.4079 ;
		END

		PORT
			 LAYER M4 ;
			RECT 0.2105 36.5683 8.463 36.6159 ;
			 LAYER V3 ;
			RECT 4.9686 36.5762 4.9835 36.6079 ;
			RECT 8.0785 36.5762 8.0934 36.6079 ;
			RECT 8.3706 36.5762 8.3855 36.6079 ;
		END

		PORT
			 LAYER M4 ;
			RECT 0.2105 35.7683 8.463 35.8159 ;
			 LAYER V3 ;
			RECT 4.9686 35.7762 4.9835 35.8079 ;
			RECT 8.0785 35.7762 8.0934 35.8079 ;
			RECT 8.3706 35.7762 8.3855 35.8079 ;
		END

		PORT
			 LAYER M4 ;
			RECT 0.2105 34.9683 8.463 35.0159 ;
			 LAYER V3 ;
			RECT 4.9686 34.9762 4.9835 35.0079 ;
			RECT 8.0785 34.9762 8.0934 35.0079 ;
			RECT 8.3706 34.9762 8.3855 35.0079 ;
		END

		PORT
			 LAYER M4 ;
			RECT 0.2105 34.1683 8.463 34.2159 ;
			 LAYER V3 ;
			RECT 4.9686 34.1762 4.9835 34.2079 ;
			RECT 8.0785 34.1762 8.0934 34.2079 ;
			RECT 8.3706 34.1762 8.3855 34.2079 ;
		END

		PORT
			 LAYER M4 ;
			RECT 0.2105 33.3683 8.463 33.4159 ;
			 LAYER V3 ;
			RECT 4.9686 33.3762 4.9835 33.4079 ;
			RECT 8.0785 33.3762 8.0934 33.4079 ;
			RECT 8.3706 33.3762 8.3855 33.4079 ;
		END

		PORT
			 LAYER M4 ;
			RECT 0.2105 32.5683 8.463 32.6159 ;
			 LAYER V3 ;
			RECT 4.9686 32.5762 4.9835 32.6079 ;
			RECT 8.0785 32.5762 8.0934 32.6079 ;
			RECT 8.3706 32.5762 8.3855 32.6079 ;
		END

		PORT
			 LAYER M4 ;
			RECT 0.2105 31.7683 8.463 31.8159 ;
			 LAYER V3 ;
			RECT 4.9686 31.7762 4.9835 31.8079 ;
			RECT 8.0785 31.7762 8.0934 31.8079 ;
			RECT 8.3706 31.7762 8.3855 31.8079 ;
		END

		PORT
			 LAYER M4 ;
			RECT 0.2105 30.9683 8.463 31.0159 ;
			 LAYER V3 ;
			RECT 4.9686 30.9762 4.9835 31.0079 ;
			RECT 8.0785 30.9762 8.0934 31.0079 ;
			RECT 8.3706 30.9762 8.3855 31.0079 ;
		END

		PORT
			 LAYER M4 ;
			RECT 0.2105 30.1683 8.463 30.2159 ;
			 LAYER V3 ;
			RECT 4.9686 30.1762 4.9835 30.2079 ;
			RECT 8.0785 30.1762 8.0934 30.2079 ;
			RECT 8.3706 30.1762 8.3855 30.2079 ;
		END

		PORT
			 LAYER M4 ;
			RECT 0.2105 29.3683 8.463 29.4159 ;
			 LAYER V3 ;
			RECT 4.9686 29.3762 4.9835 29.4079 ;
			RECT 8.0785 29.3762 8.0934 29.4079 ;
			RECT 8.3706 29.3762 8.3855 29.4079 ;
		END

		PORT
			 LAYER M4 ;
			RECT 0.2105 28.5683 8.463 28.6159 ;
			 LAYER V3 ;
			RECT 4.9686 28.5762 4.9835 28.6079 ;
			RECT 8.0785 28.5762 8.0934 28.6079 ;
			RECT 8.3706 28.5762 8.3855 28.6079 ;
		END

		PORT
			 LAYER M4 ;
			RECT 0.2105 18.3635 8.463 18.4111 ;
			 LAYER V3 ;
			RECT 1.8867 18.3714 1.9017 18.4032 ;
			RECT 4.5659 18.3714 4.5808 18.4032 ;
			RECT 4.7861 18.381 4.8235 18.3937 ;
			RECT 4.893 18.381 4.9303 18.3937 ;
			RECT 8.0901 18.3714 8.1051 18.4032 ;
			RECT 8.2661 18.3714 8.281 18.4032 ;
			RECT 8.3594 18.381 8.3967 18.3937 ;
		END

		PORT
			 LAYER M4 ;
			RECT 0.2105 18.6587 8.463 18.7063 ;
			 LAYER V3 ;
			RECT 4.5659 18.6667 4.5808 18.6984 ;
			RECT 4.7861 18.6762 4.8235 18.6889 ;
			RECT 4.893 18.6762 4.9303 18.6889 ;
			RECT 8.0901 18.6667 8.1051 18.6984 ;
			RECT 8.2661 18.6667 8.281 18.6984 ;
			RECT 8.3594 18.6762 8.3967 18.6889 ;
		END

		PORT
			 LAYER M4 ;
			RECT 0.2105 24.6841 8.463 24.7317 ;
			 LAYER V3 ;
			RECT 4.5659 24.6921 4.5808 24.7238 ;
			RECT 4.8067 24.6921 4.8216 24.7238 ;
			RECT 4.893 24.6921 4.9079 24.7238 ;
			RECT 5.1072 24.6921 5.1221 24.7238 ;
			RECT 8.0901 24.6921 8.1051 24.7238 ;
			RECT 8.2661 24.6921 8.281 24.7238 ;
			RECT 8.3594 24.7016 8.3967 24.7143 ;
		END

		PORT
			 LAYER M4 ;
			RECT 0.2105 24.9794 8.463 25.027 ;
			 LAYER V3 ;
			RECT 1.7486 24.9873 1.7635 25.019 ;
			RECT 4.5659 24.9873 4.5808 25.019 ;
			RECT 4.8067 24.9873 4.8216 25.019 ;
			RECT 4.893 24.9873 4.9079 25.019 ;
			RECT 8.0901 24.9873 8.1051 25.019 ;
			RECT 8.2661 24.9873 8.281 25.019 ;
			RECT 8.3594 24.9968 8.3967 25.0095 ;
		END

		PORT
			 LAYER M4 ;
			RECT 0.2105 17.9079 8.463 17.9397 ;
			 LAYER V3 ;
			RECT 5.0279 17.9175 5.0428 17.9302 ;
			RECT 8.0192 17.9175 8.0341 17.9302 ;
		END

		PORT
			 LAYER M4 ;
			RECT 0.2105 25.2413 8.463 25.273 ;
			 LAYER V3 ;
			RECT 5.0279 25.2508 5.0428 25.2635 ;
			RECT 8.0192 25.2508 8.0341 25.2635 ;
		END

		PORT
			 LAYER M4 ;
			RECT 0.2105 43.7683 8.463 43.8 ;
			 LAYER V3 ;
			RECT 5.0279 43.7778 5.0428 43.7905 ;
			RECT 8.0192 43.7778 8.0341 43.7905 ;
		END

		PORT
			 LAYER M4 ;
			RECT 0.2105 0.181 8.463 0.2127 ;
			 LAYER V3 ;
			RECT 5.0279 0.1905 5.0428 0.2032 ;
			RECT 8.0192 0.1905 8.0341 0.2032 ;
		END

	END VDDCE

	PIN VDDPE
		USE POWER ;
		DIRECTION INOUT ;
		PORT
			 LAYER M4 ;
			RECT 0.2105 43.6095 8.463 43.6571 ;
			 LAYER V3 ;
			RECT 1.3622 43.627 1.3995 43.6397 ;
			RECT 1.4957 43.6175 1.5106 43.6492 ;
			RECT 1.8489 43.6175 1.8639 43.6492 ;
			RECT 2.2153 43.6175 2.2302 43.6492 ;
			RECT 2.2876 43.6175 2.3025 43.6492 ;
			RECT 2.5881 43.6175 2.6031 43.6492 ;
			RECT 2.7547 43.6175 2.7697 43.6492 ;
			RECT 3.2037 43.6175 3.2186 43.6492 ;
			RECT 3.9933 43.6175 4.0082 43.6492 ;
			RECT 4.3853 43.6175 4.4002 43.6492 ;
		END

		PORT
			 LAYER M4 ;
			RECT 0.2105 27.6095 8.463 27.6571 ;
			 LAYER V3 ;
			RECT 1.3622 27.627 1.3995 27.6397 ;
			RECT 1.4957 27.6175 1.5106 27.6492 ;
			RECT 1.8489 27.6175 1.8639 27.6492 ;
			RECT 2.2153 27.6175 2.2302 27.6492 ;
			RECT 2.2876 27.6175 2.3025 27.6492 ;
			RECT 2.5881 27.6175 2.6031 27.6492 ;
			RECT 2.7547 27.6175 2.7697 27.6492 ;
			RECT 3.2037 27.6175 3.2186 27.6492 ;
			RECT 3.9933 27.6175 4.0082 27.6492 ;
			RECT 4.3853 27.6175 4.4002 27.6492 ;
		END

		PORT
			 LAYER M4 ;
			RECT 0.2105 26.8095 8.463 26.8571 ;
			 LAYER V3 ;
			RECT 1.3622 26.827 1.3995 26.8397 ;
			RECT 1.4957 26.8175 1.5106 26.8492 ;
			RECT 1.8489 26.8175 1.8639 26.8492 ;
			RECT 2.2153 26.8175 2.2302 26.8492 ;
			RECT 2.2876 26.8175 2.3025 26.8492 ;
			RECT 2.5881 26.8175 2.6031 26.8492 ;
			RECT 2.7547 26.8175 2.7697 26.8492 ;
			RECT 3.2037 26.8175 3.2186 26.8492 ;
			RECT 3.9933 26.8175 4.0082 26.8492 ;
			RECT 4.3853 26.8175 4.4002 26.8492 ;
		END

		PORT
			 LAYER M4 ;
			RECT 0.2105 26.0095 8.463 26.0571 ;
			 LAYER V3 ;
			RECT 1.3622 26.027 1.3995 26.0397 ;
			RECT 1.4957 26.0175 1.5106 26.0492 ;
			RECT 1.8489 26.0175 1.8639 26.0492 ;
			RECT 2.2153 26.0175 2.2302 26.0492 ;
			RECT 2.2876 26.0175 2.3025 26.0492 ;
			RECT 2.5881 26.0175 2.6031 26.0492 ;
			RECT 2.7547 26.0175 2.7697 26.0492 ;
			RECT 3.2037 26.0175 3.2186 26.0492 ;
			RECT 3.9933 26.0175 4.0082 26.0492 ;
			RECT 4.3853 26.0175 4.4002 26.0492 ;
		END

		PORT
			 LAYER M4 ;
			RECT 0.2105 42.0095 8.463 42.0571 ;
			 LAYER V3 ;
			RECT 1.3622 42.027 1.3995 42.0397 ;
			RECT 1.4957 42.0175 1.5106 42.0492 ;
			RECT 1.8489 42.0175 1.8639 42.0492 ;
			RECT 2.2153 42.0175 2.2302 42.0492 ;
			RECT 2.2876 42.0175 2.3025 42.0492 ;
			RECT 2.5881 42.0175 2.6031 42.0492 ;
			RECT 2.7547 42.0175 2.7697 42.0492 ;
			RECT 3.2037 42.0175 3.2186 42.0492 ;
			RECT 3.9933 42.0175 4.0082 42.0492 ;
			RECT 4.3853 42.0175 4.4002 42.0492 ;
		END

		PORT
			 LAYER M4 ;
			RECT 0.2105 17.1238 8.463 17.1714 ;
			 LAYER V3 ;
			RECT 1.3622 17.1413 1.3995 17.154 ;
			RECT 1.4957 17.1317 1.5106 17.1635 ;
			RECT 1.8489 17.1317 1.8639 17.1635 ;
			RECT 2.2153 17.1317 2.2302 17.1635 ;
			RECT 2.2876 17.1317 2.3025 17.1635 ;
			RECT 2.5881 17.1317 2.6031 17.1635 ;
			RECT 2.7547 17.1317 2.7697 17.1635 ;
			RECT 3.2037 17.1317 3.2186 17.1635 ;
			RECT 3.9933 17.1317 4.0082 17.1635 ;
			RECT 4.3853 17.1317 4.4002 17.1635 ;
		END

		PORT
			 LAYER M4 ;
			RECT 0.2105 16.3238 8.463 16.3714 ;
			 LAYER V3 ;
			RECT 1.3622 16.3413 1.3995 16.354 ;
			RECT 1.4957 16.3317 1.5106 16.3635 ;
			RECT 1.8489 16.3317 1.8639 16.3635 ;
			RECT 2.2153 16.3317 2.2302 16.3635 ;
			RECT 2.2876 16.3317 2.3025 16.3635 ;
			RECT 2.5881 16.3317 2.6031 16.3635 ;
			RECT 2.7547 16.3317 2.7697 16.3635 ;
			RECT 3.2037 16.3317 3.2186 16.3635 ;
			RECT 3.9933 16.3317 4.0082 16.3635 ;
			RECT 4.3853 16.3317 4.4002 16.3635 ;
		END

		PORT
			 LAYER M4 ;
			RECT 0.2105 15.5238 8.463 15.5714 ;
			 LAYER V3 ;
			RECT 1.3622 15.5413 1.3995 15.554 ;
			RECT 1.4957 15.5317 1.5106 15.5635 ;
			RECT 1.8489 15.5317 1.8639 15.5635 ;
			RECT 2.2153 15.5317 2.2302 15.5635 ;
			RECT 2.2876 15.5317 2.3025 15.5635 ;
			RECT 2.5881 15.5317 2.6031 15.5635 ;
			RECT 2.7547 15.5317 2.7697 15.5635 ;
			RECT 3.2037 15.5317 3.2186 15.5635 ;
			RECT 3.9933 15.5317 4.0082 15.5635 ;
			RECT 4.3853 15.5317 4.4002 15.5635 ;
		END

		PORT
			 LAYER M4 ;
			RECT 0.2105 14.7238 8.463 14.7714 ;
			 LAYER V3 ;
			RECT 1.3622 14.7413 1.3995 14.754 ;
			RECT 1.4957 14.7317 1.5106 14.7635 ;
			RECT 1.8489 14.7317 1.8639 14.7635 ;
			RECT 2.2153 14.7317 2.2302 14.7635 ;
			RECT 2.2876 14.7317 2.3025 14.7635 ;
			RECT 2.5881 14.7317 2.6031 14.7635 ;
			RECT 2.7547 14.7317 2.7697 14.7635 ;
			RECT 3.2037 14.7317 3.2186 14.7635 ;
			RECT 3.9933 14.7317 4.0082 14.7635 ;
			RECT 4.3853 14.7317 4.4002 14.7635 ;
		END

		PORT
			 LAYER M4 ;
			RECT 0.2105 13.9238 8.463 13.9714 ;
			 LAYER V3 ;
			RECT 1.3622 13.9413 1.3995 13.954 ;
			RECT 1.4957 13.9317 1.5106 13.9635 ;
			RECT 1.8489 13.9317 1.8639 13.9635 ;
			RECT 2.2153 13.9317 2.2302 13.9635 ;
			RECT 2.2876 13.9317 2.3025 13.9635 ;
			RECT 2.5881 13.9317 2.6031 13.9635 ;
			RECT 2.7547 13.9317 2.7697 13.9635 ;
			RECT 3.2037 13.9317 3.2186 13.9635 ;
			RECT 3.9933 13.9317 4.0082 13.9635 ;
			RECT 4.3853 13.9317 4.4002 13.9635 ;
		END

		PORT
			 LAYER M4 ;
			RECT 0.2105 13.1238 8.463 13.1714 ;
			 LAYER V3 ;
			RECT 1.3622 13.1413 1.3995 13.154 ;
			RECT 1.4957 13.1317 1.5106 13.1635 ;
			RECT 1.8489 13.1317 1.8639 13.1635 ;
			RECT 2.2153 13.1317 2.2302 13.1635 ;
			RECT 2.2876 13.1317 2.3025 13.1635 ;
			RECT 2.5881 13.1317 2.6031 13.1635 ;
			RECT 2.7547 13.1317 2.7697 13.1635 ;
			RECT 3.2037 13.1317 3.2186 13.1635 ;
			RECT 3.9933 13.1317 4.0082 13.1635 ;
			RECT 4.3853 13.1317 4.4002 13.1635 ;
		END

		PORT
			 LAYER M4 ;
			RECT 0.2105 12.3238 8.463 12.3714 ;
			 LAYER V3 ;
			RECT 1.3622 12.3413 1.3995 12.354 ;
			RECT 1.4957 12.3317 1.5106 12.3635 ;
			RECT 1.8489 12.3317 1.8639 12.3635 ;
			RECT 2.2153 12.3317 2.2302 12.3635 ;
			RECT 2.2876 12.3317 2.3025 12.3635 ;
			RECT 2.5881 12.3317 2.6031 12.3635 ;
			RECT 2.7547 12.3317 2.7697 12.3635 ;
			RECT 3.2037 12.3317 3.2186 12.3635 ;
			RECT 3.9933 12.3317 4.0082 12.3635 ;
			RECT 4.3853 12.3317 4.4002 12.3635 ;
		END

		PORT
			 LAYER M4 ;
			RECT 0.2105 41.2095 8.463 41.2571 ;
			 LAYER V3 ;
			RECT 1.3622 41.227 1.3995 41.2397 ;
			RECT 1.4957 41.2175 1.5106 41.2492 ;
			RECT 1.8489 41.2175 1.8639 41.2492 ;
			RECT 2.2153 41.2175 2.2302 41.2492 ;
			RECT 2.2876 41.2175 2.3025 41.2492 ;
			RECT 2.5881 41.2175 2.6031 41.2492 ;
			RECT 2.7547 41.2175 2.7697 41.2492 ;
			RECT 3.2037 41.2175 3.2186 41.2492 ;
			RECT 3.9933 41.2175 4.0082 41.2492 ;
			RECT 4.3853 41.2175 4.4002 41.2492 ;
		END

		PORT
			 LAYER M4 ;
			RECT 0.2105 11.5238 8.463 11.5714 ;
			 LAYER V3 ;
			RECT 1.3622 11.5413 1.3995 11.554 ;
			RECT 1.4957 11.5317 1.5106 11.5635 ;
			RECT 1.8489 11.5317 1.8639 11.5635 ;
			RECT 2.2153 11.5317 2.2302 11.5635 ;
			RECT 2.2876 11.5317 2.3025 11.5635 ;
			RECT 2.5881 11.5317 2.6031 11.5635 ;
			RECT 2.7547 11.5317 2.7697 11.5635 ;
			RECT 3.2037 11.5317 3.2186 11.5635 ;
			RECT 3.9933 11.5317 4.0082 11.5635 ;
			RECT 4.3853 11.5317 4.4002 11.5635 ;
		END

		PORT
			 LAYER M4 ;
			RECT 0.2105 10.7238 8.463 10.7714 ;
			 LAYER V3 ;
			RECT 1.3622 10.7413 1.3995 10.754 ;
			RECT 1.4957 10.7317 1.5106 10.7635 ;
			RECT 1.8489 10.7317 1.8639 10.7635 ;
			RECT 2.2153 10.7317 2.2302 10.7635 ;
			RECT 2.2876 10.7317 2.3025 10.7635 ;
			RECT 2.5881 10.7317 2.6031 10.7635 ;
			RECT 2.7547 10.7317 2.7697 10.7635 ;
			RECT 3.2037 10.7317 3.2186 10.7635 ;
			RECT 3.9933 10.7317 4.0082 10.7635 ;
			RECT 4.3853 10.7317 4.4002 10.7635 ;
		END

		PORT
			 LAYER M4 ;
			RECT 0.2105 9.9238 8.463 9.9714 ;
			 LAYER V3 ;
			RECT 1.3622 9.9413 1.3995 9.954 ;
			RECT 1.4957 9.9317 1.5106 9.9635 ;
			RECT 1.8489 9.9317 1.8639 9.9635 ;
			RECT 2.2153 9.9317 2.2302 9.9635 ;
			RECT 2.2876 9.9317 2.3025 9.9635 ;
			RECT 2.5881 9.9317 2.6031 9.9635 ;
			RECT 2.7547 9.9317 2.7697 9.9635 ;
			RECT 3.2037 9.9317 3.2186 9.9635 ;
			RECT 3.9933 9.9317 4.0082 9.9635 ;
			RECT 4.3853 9.9317 4.4002 9.9635 ;
		END

		PORT
			 LAYER M4 ;
			RECT 0.2105 9.1238 8.463 9.1714 ;
			 LAYER V3 ;
			RECT 1.3622 9.1413 1.3995 9.154 ;
			RECT 1.4957 9.1317 1.5106 9.1635 ;
			RECT 1.8489 9.1317 1.8639 9.1635 ;
			RECT 2.2153 9.1317 2.2302 9.1635 ;
			RECT 2.2876 9.1317 2.3025 9.1635 ;
			RECT 2.5881 9.1317 2.6031 9.1635 ;
			RECT 2.7547 9.1317 2.7697 9.1635 ;
			RECT 3.2037 9.1317 3.2186 9.1635 ;
			RECT 3.9933 9.1317 4.0082 9.1635 ;
			RECT 4.3853 9.1317 4.4002 9.1635 ;
		END

		PORT
			 LAYER M4 ;
			RECT 0.2105 8.3238 8.463 8.3714 ;
			 LAYER V3 ;
			RECT 1.3622 8.3413 1.3995 8.354 ;
			RECT 1.4957 8.3317 1.5106 8.3635 ;
			RECT 1.8489 8.3317 1.8639 8.3635 ;
			RECT 2.2153 8.3317 2.2302 8.3635 ;
			RECT 2.2876 8.3317 2.3025 8.3635 ;
			RECT 2.5881 8.3317 2.6031 8.3635 ;
			RECT 2.7547 8.3317 2.7697 8.3635 ;
			RECT 3.2037 8.3317 3.2186 8.3635 ;
			RECT 3.9933 8.3317 4.0082 8.3635 ;
			RECT 4.3853 8.3317 4.4002 8.3635 ;
		END

		PORT
			 LAYER M4 ;
			RECT 0.2105 7.5238 8.463 7.5714 ;
			 LAYER V3 ;
			RECT 1.3622 7.5413 1.3995 7.554 ;
			RECT 1.4957 7.5317 1.5106 7.5635 ;
			RECT 1.8489 7.5317 1.8639 7.5635 ;
			RECT 2.2153 7.5317 2.2302 7.5635 ;
			RECT 2.2876 7.5317 2.3025 7.5635 ;
			RECT 2.5881 7.5317 2.6031 7.5635 ;
			RECT 2.7547 7.5317 2.7697 7.5635 ;
			RECT 3.2037 7.5317 3.2186 7.5635 ;
			RECT 3.9933 7.5317 4.0082 7.5635 ;
			RECT 4.3853 7.5317 4.4002 7.5635 ;
		END

		PORT
			 LAYER M4 ;
			RECT 0.2105 6.7238 8.463 6.7714 ;
			 LAYER V3 ;
			RECT 1.3622 6.7413 1.3995 6.754 ;
			RECT 1.4957 6.7317 1.5106 6.7635 ;
			RECT 1.8489 6.7317 1.8639 6.7635 ;
			RECT 2.2153 6.7317 2.2302 6.7635 ;
			RECT 2.2876 6.7317 2.3025 6.7635 ;
			RECT 2.5881 6.7317 2.6031 6.7635 ;
			RECT 2.7547 6.7317 2.7697 6.7635 ;
			RECT 3.2037 6.7317 3.2186 6.7635 ;
			RECT 3.9933 6.7317 4.0082 6.7635 ;
			RECT 4.3853 6.7317 4.4002 6.7635 ;
		END

		PORT
			 LAYER M4 ;
			RECT 0.2105 5.9238 8.463 5.9714 ;
			 LAYER V3 ;
			RECT 1.3622 5.9413 1.3995 5.954 ;
			RECT 1.4957 5.9317 1.5106 5.9635 ;
			RECT 1.8489 5.9317 1.8639 5.9635 ;
			RECT 2.2153 5.9317 2.2302 5.9635 ;
			RECT 2.2876 5.9317 2.3025 5.9635 ;
			RECT 2.5881 5.9317 2.6031 5.9635 ;
			RECT 2.7547 5.9317 2.7697 5.9635 ;
			RECT 3.2037 5.9317 3.2186 5.9635 ;
			RECT 3.9933 5.9317 4.0082 5.9635 ;
			RECT 4.3853 5.9317 4.4002 5.9635 ;
		END

		PORT
			 LAYER M4 ;
			RECT 0.2105 5.1238 8.463 5.1714 ;
			 LAYER V3 ;
			RECT 1.3622 5.1413 1.3995 5.154 ;
			RECT 1.4957 5.1317 1.5106 5.1635 ;
			RECT 1.8489 5.1317 1.8639 5.1635 ;
			RECT 2.2153 5.1317 2.2302 5.1635 ;
			RECT 2.2876 5.1317 2.3025 5.1635 ;
			RECT 2.5881 5.1317 2.6031 5.1635 ;
			RECT 2.7547 5.1317 2.7697 5.1635 ;
			RECT 3.2037 5.1317 3.2186 5.1635 ;
			RECT 3.9933 5.1317 4.0082 5.1635 ;
			RECT 4.3853 5.1317 4.4002 5.1635 ;
		END

		PORT
			 LAYER M4 ;
			RECT 0.2105 4.3238 8.463 4.3714 ;
			 LAYER V3 ;
			RECT 1.3622 4.3413 1.3995 4.354 ;
			RECT 1.4957 4.3317 1.5106 4.3635 ;
			RECT 1.8489 4.3317 1.8639 4.3635 ;
			RECT 2.2153 4.3317 2.2302 4.3635 ;
			RECT 2.2876 4.3317 2.3025 4.3635 ;
			RECT 2.5881 4.3317 2.6031 4.3635 ;
			RECT 2.7547 4.3317 2.7697 4.3635 ;
			RECT 3.2037 4.3317 3.2186 4.3635 ;
			RECT 3.9933 4.3317 4.0082 4.3635 ;
			RECT 4.3853 4.3317 4.4002 4.3635 ;
		END

		PORT
			 LAYER M4 ;
			RECT 0.2105 40.4095 8.463 40.4571 ;
			 LAYER V3 ;
			RECT 1.3622 40.427 1.3995 40.4397 ;
			RECT 1.4957 40.4175 1.5106 40.4492 ;
			RECT 1.8489 40.4175 1.8639 40.4492 ;
			RECT 2.2153 40.4175 2.2302 40.4492 ;
			RECT 2.2876 40.4175 2.3025 40.4492 ;
			RECT 2.5881 40.4175 2.6031 40.4492 ;
			RECT 2.7547 40.4175 2.7697 40.4492 ;
			RECT 3.2037 40.4175 3.2186 40.4492 ;
			RECT 3.9933 40.4175 4.0082 40.4492 ;
			RECT 4.3853 40.4175 4.4002 40.4492 ;
		END

		PORT
			 LAYER M4 ;
			RECT 0.2105 3.5238 8.463 3.5714 ;
			 LAYER V3 ;
			RECT 1.3622 3.5413 1.3995 3.554 ;
			RECT 1.4957 3.5317 1.5106 3.5635 ;
			RECT 1.8489 3.5317 1.8639 3.5635 ;
			RECT 2.2153 3.5317 2.2302 3.5635 ;
			RECT 2.2876 3.5317 2.3025 3.5635 ;
			RECT 2.5881 3.5317 2.6031 3.5635 ;
			RECT 2.7547 3.5317 2.7697 3.5635 ;
			RECT 3.2037 3.5317 3.2186 3.5635 ;
			RECT 3.9933 3.5317 4.0082 3.5635 ;
			RECT 4.3853 3.5317 4.4002 3.5635 ;
		END

		PORT
			 LAYER M4 ;
			RECT 0.2105 2.7238 8.463 2.7714 ;
			 LAYER V3 ;
			RECT 1.3622 2.7413 1.3995 2.754 ;
			RECT 1.4957 2.7317 1.5106 2.7635 ;
			RECT 1.8489 2.7317 1.8639 2.7635 ;
			RECT 2.2153 2.7317 2.2302 2.7635 ;
			RECT 2.2876 2.7317 2.3025 2.7635 ;
			RECT 2.5881 2.7317 2.6031 2.7635 ;
			RECT 2.7547 2.7317 2.7697 2.7635 ;
			RECT 3.2037 2.7317 3.2186 2.7635 ;
			RECT 3.9933 2.7317 4.0082 2.7635 ;
			RECT 4.3853 2.7317 4.4002 2.7635 ;
		END

		PORT
			 LAYER M4 ;
			RECT 0.2105 1.9238 8.463 1.9714 ;
			 LAYER V3 ;
			RECT 1.3622 1.9413 1.3995 1.954 ;
			RECT 1.4957 1.9317 1.5106 1.9635 ;
			RECT 1.8489 1.9317 1.8639 1.9635 ;
			RECT 2.2153 1.9317 2.2302 1.9635 ;
			RECT 2.2876 1.9317 2.3025 1.9635 ;
			RECT 2.5881 1.9317 2.6031 1.9635 ;
			RECT 2.7547 1.9317 2.7697 1.9635 ;
			RECT 3.2037 1.9317 3.2186 1.9635 ;
			RECT 3.9933 1.9317 4.0082 1.9635 ;
			RECT 4.3853 1.9317 4.4002 1.9635 ;
		END

		PORT
			 LAYER M4 ;
			RECT 0.2105 1.1238 8.463 1.1714 ;
			 LAYER V3 ;
			RECT 1.3622 1.1413 1.3995 1.154 ;
			RECT 1.4957 1.1317 1.5106 1.1635 ;
			RECT 1.8489 1.1317 1.8639 1.1635 ;
			RECT 2.2153 1.1317 2.2302 1.1635 ;
			RECT 2.2876 1.1317 2.3025 1.1635 ;
			RECT 2.5881 1.1317 2.6031 1.1635 ;
			RECT 2.7547 1.1317 2.7697 1.1635 ;
			RECT 3.2037 1.1317 3.2186 1.1635 ;
			RECT 3.9933 1.1317 4.0082 1.1635 ;
			RECT 4.3853 1.1317 4.4002 1.1635 ;
		END

		PORT
			 LAYER M4 ;
			RECT 0.2105 0.3238 8.463 0.3714 ;
			 LAYER V3 ;
			RECT 1.3622 0.3413 1.3995 0.354 ;
			RECT 1.4957 0.3317 1.5106 0.3635 ;
			RECT 1.8489 0.3317 1.8639 0.3635 ;
			RECT 2.2153 0.3317 2.2302 0.3635 ;
			RECT 2.2876 0.3317 2.3025 0.3635 ;
			RECT 2.5881 0.3317 2.6031 0.3635 ;
			RECT 2.7547 0.3317 2.7697 0.3635 ;
			RECT 3.2037 0.3317 3.2186 0.3635 ;
			RECT 3.9933 0.3317 4.0082 0.3635 ;
			RECT 4.3853 0.3317 4.4002 0.3635 ;
		END

		PORT
			 LAYER M4 ;
			RECT 0.2105 39.6095 8.463 39.6571 ;
			 LAYER V3 ;
			RECT 1.3622 39.627 1.3995 39.6397 ;
			RECT 1.4957 39.6175 1.5106 39.6492 ;
			RECT 1.8489 39.6175 1.8639 39.6492 ;
			RECT 2.2153 39.6175 2.2302 39.6492 ;
			RECT 2.2876 39.6175 2.3025 39.6492 ;
			RECT 2.5881 39.6175 2.6031 39.6492 ;
			RECT 2.7547 39.6175 2.7697 39.6492 ;
			RECT 3.2037 39.6175 3.2186 39.6492 ;
			RECT 3.9933 39.6175 4.0082 39.6492 ;
			RECT 4.3853 39.6175 4.4002 39.6492 ;
		END

		PORT
			 LAYER M4 ;
			RECT 0.2105 38.8095 8.463 38.8571 ;
			 LAYER V3 ;
			RECT 1.3622 38.827 1.3995 38.8397 ;
			RECT 1.4957 38.8175 1.5106 38.8492 ;
			RECT 1.8489 38.8175 1.8639 38.8492 ;
			RECT 2.2153 38.8175 2.2302 38.8492 ;
			RECT 2.2876 38.8175 2.3025 38.8492 ;
			RECT 2.5881 38.8175 2.6031 38.8492 ;
			RECT 2.7547 38.8175 2.7697 38.8492 ;
			RECT 3.2037 38.8175 3.2186 38.8492 ;
			RECT 3.9933 38.8175 4.0082 38.8492 ;
			RECT 4.3853 38.8175 4.4002 38.8492 ;
		END

		PORT
			 LAYER M4 ;
			RECT 0.2105 38.0095 8.463 38.0571 ;
			 LAYER V3 ;
			RECT 1.3622 38.027 1.3995 38.0397 ;
			RECT 1.4957 38.0175 1.5106 38.0492 ;
			RECT 1.8489 38.0175 1.8639 38.0492 ;
			RECT 2.2153 38.0175 2.2302 38.0492 ;
			RECT 2.2876 38.0175 2.3025 38.0492 ;
			RECT 2.5881 38.0175 2.6031 38.0492 ;
			RECT 2.7547 38.0175 2.7697 38.0492 ;
			RECT 3.2037 38.0175 3.2186 38.0492 ;
			RECT 3.9933 38.0175 4.0082 38.0492 ;
			RECT 4.3853 38.0175 4.4002 38.0492 ;
		END

		PORT
			 LAYER M4 ;
			RECT 0.2105 37.2095 8.463 37.2571 ;
			 LAYER V3 ;
			RECT 1.3622 37.227 1.3995 37.2397 ;
			RECT 1.4957 37.2175 1.5106 37.2492 ;
			RECT 1.8489 37.2175 1.8639 37.2492 ;
			RECT 2.2153 37.2175 2.2302 37.2492 ;
			RECT 2.2876 37.2175 2.3025 37.2492 ;
			RECT 2.5881 37.2175 2.6031 37.2492 ;
			RECT 2.7547 37.2175 2.7697 37.2492 ;
			RECT 3.2037 37.2175 3.2186 37.2492 ;
			RECT 3.9933 37.2175 4.0082 37.2492 ;
			RECT 4.3853 37.2175 4.4002 37.2492 ;
		END

		PORT
			 LAYER M4 ;
			RECT 0.2105 36.4095 8.463 36.4571 ;
			 LAYER V3 ;
			RECT 1.3622 36.427 1.3995 36.4397 ;
			RECT 1.4957 36.4175 1.5106 36.4492 ;
			RECT 1.8489 36.4175 1.8639 36.4492 ;
			RECT 2.2153 36.4175 2.2302 36.4492 ;
			RECT 2.2876 36.4175 2.3025 36.4492 ;
			RECT 2.5881 36.4175 2.6031 36.4492 ;
			RECT 2.7547 36.4175 2.7697 36.4492 ;
			RECT 3.2037 36.4175 3.2186 36.4492 ;
			RECT 3.9933 36.4175 4.0082 36.4492 ;
			RECT 4.3853 36.4175 4.4002 36.4492 ;
		END

		PORT
			 LAYER M4 ;
			RECT 0.2105 35.6095 8.463 35.6571 ;
			 LAYER V3 ;
			RECT 1.3622 35.627 1.3995 35.6397 ;
			RECT 1.4957 35.6175 1.5106 35.6492 ;
			RECT 1.8489 35.6175 1.8639 35.6492 ;
			RECT 2.2153 35.6175 2.2302 35.6492 ;
			RECT 2.2876 35.6175 2.3025 35.6492 ;
			RECT 2.5881 35.6175 2.6031 35.6492 ;
			RECT 2.7547 35.6175 2.7697 35.6492 ;
			RECT 3.2037 35.6175 3.2186 35.6492 ;
			RECT 3.9933 35.6175 4.0082 35.6492 ;
			RECT 4.3853 35.6175 4.4002 35.6492 ;
		END

		PORT
			 LAYER M4 ;
			RECT 0.2105 34.8095 8.463 34.8571 ;
			 LAYER V3 ;
			RECT 1.3622 34.827 1.3995 34.8397 ;
			RECT 1.4957 34.8175 1.5106 34.8492 ;
			RECT 1.8489 34.8175 1.8639 34.8492 ;
			RECT 2.2153 34.8175 2.2302 34.8492 ;
			RECT 2.2876 34.8175 2.3025 34.8492 ;
			RECT 2.5881 34.8175 2.6031 34.8492 ;
			RECT 2.7547 34.8175 2.7697 34.8492 ;
			RECT 3.2037 34.8175 3.2186 34.8492 ;
			RECT 3.9933 34.8175 4.0082 34.8492 ;
			RECT 4.3853 34.8175 4.4002 34.8492 ;
		END

		PORT
			 LAYER M4 ;
			RECT 0.2105 34.0095 8.463 34.0571 ;
			 LAYER V3 ;
			RECT 1.3622 34.027 1.3995 34.0397 ;
			RECT 1.4957 34.0175 1.5106 34.0492 ;
			RECT 1.8489 34.0175 1.8639 34.0492 ;
			RECT 2.2153 34.0175 2.2302 34.0492 ;
			RECT 2.2876 34.0175 2.3025 34.0492 ;
			RECT 2.5881 34.0175 2.6031 34.0492 ;
			RECT 2.7547 34.0175 2.7697 34.0492 ;
			RECT 3.2037 34.0175 3.2186 34.0492 ;
			RECT 3.9933 34.0175 4.0082 34.0492 ;
			RECT 4.3853 34.0175 4.4002 34.0492 ;
		END

		PORT
			 LAYER M4 ;
			RECT 0.2105 33.2095 8.463 33.2571 ;
			 LAYER V3 ;
			RECT 1.3622 33.227 1.3995 33.2397 ;
			RECT 1.4957 33.2175 1.5106 33.2492 ;
			RECT 1.8489 33.2175 1.8639 33.2492 ;
			RECT 2.2153 33.2175 2.2302 33.2492 ;
			RECT 2.2876 33.2175 2.3025 33.2492 ;
			RECT 2.5881 33.2175 2.6031 33.2492 ;
			RECT 2.7547 33.2175 2.7697 33.2492 ;
			RECT 3.2037 33.2175 3.2186 33.2492 ;
			RECT 3.9933 33.2175 4.0082 33.2492 ;
			RECT 4.3853 33.2175 4.4002 33.2492 ;
		END

		PORT
			 LAYER M4 ;
			RECT 0.2105 32.4095 8.463 32.4571 ;
			 LAYER V3 ;
			RECT 1.3622 32.427 1.3995 32.4397 ;
			RECT 1.4957 32.4175 1.5106 32.4492 ;
			RECT 1.8489 32.4175 1.8639 32.4492 ;
			RECT 2.2153 32.4175 2.2302 32.4492 ;
			RECT 2.2876 32.4175 2.3025 32.4492 ;
			RECT 2.5881 32.4175 2.6031 32.4492 ;
			RECT 2.7547 32.4175 2.7697 32.4492 ;
			RECT 3.2037 32.4175 3.2186 32.4492 ;
			RECT 3.9933 32.4175 4.0082 32.4492 ;
			RECT 4.3853 32.4175 4.4002 32.4492 ;
		END

		PORT
			 LAYER M4 ;
			RECT 0.2105 31.6095 8.463 31.6571 ;
			 LAYER V3 ;
			RECT 1.3622 31.627 1.3995 31.6397 ;
			RECT 1.4957 31.6175 1.5106 31.6492 ;
			RECT 1.8489 31.6175 1.8639 31.6492 ;
			RECT 2.2153 31.6175 2.2302 31.6492 ;
			RECT 2.2876 31.6175 2.3025 31.6492 ;
			RECT 2.5881 31.6175 2.6031 31.6492 ;
			RECT 2.7547 31.6175 2.7697 31.6492 ;
			RECT 3.2037 31.6175 3.2186 31.6492 ;
			RECT 3.9933 31.6175 4.0082 31.6492 ;
			RECT 4.3853 31.6175 4.4002 31.6492 ;
		END

		PORT
			 LAYER M4 ;
			RECT 0.2105 30.8095 8.463 30.8571 ;
			 LAYER V3 ;
			RECT 1.3622 30.827 1.3995 30.8397 ;
			RECT 1.4957 30.8175 1.5106 30.8492 ;
			RECT 1.8489 30.8175 1.8639 30.8492 ;
			RECT 2.2153 30.8175 2.2302 30.8492 ;
			RECT 2.2876 30.8175 2.3025 30.8492 ;
			RECT 2.5881 30.8175 2.6031 30.8492 ;
			RECT 2.7547 30.8175 2.7697 30.8492 ;
			RECT 3.2037 30.8175 3.2186 30.8492 ;
			RECT 3.9933 30.8175 4.0082 30.8492 ;
			RECT 4.3853 30.8175 4.4002 30.8492 ;
		END

		PORT
			 LAYER M4 ;
			RECT 0.2105 30.0095 8.463 30.0571 ;
			 LAYER V3 ;
			RECT 1.3622 30.027 1.3995 30.0397 ;
			RECT 1.4957 30.0175 1.5106 30.0492 ;
			RECT 1.8489 30.0175 1.8639 30.0492 ;
			RECT 2.2153 30.0175 2.2302 30.0492 ;
			RECT 2.2876 30.0175 2.3025 30.0492 ;
			RECT 2.5881 30.0175 2.6031 30.0492 ;
			RECT 2.7547 30.0175 2.7697 30.0492 ;
			RECT 3.2037 30.0175 3.2186 30.0492 ;
			RECT 3.9933 30.0175 4.0082 30.0492 ;
			RECT 4.3853 30.0175 4.4002 30.0492 ;
		END

		PORT
			 LAYER M4 ;
			RECT 0.2105 42.8095 8.463 42.8571 ;
			 LAYER V3 ;
			RECT 1.3622 42.827 1.3995 42.8397 ;
			RECT 1.4957 42.8175 1.5106 42.8492 ;
			RECT 1.8489 42.8175 1.8639 42.8492 ;
			RECT 2.2153 42.8175 2.2302 42.8492 ;
			RECT 2.2876 42.8175 2.3025 42.8492 ;
			RECT 2.5881 42.8175 2.6031 42.8492 ;
			RECT 2.7547 42.8175 2.7697 42.8492 ;
			RECT 3.2037 42.8175 3.2186 42.8492 ;
			RECT 3.9933 42.8175 4.0082 42.8492 ;
			RECT 4.3853 42.8175 4.4002 42.8492 ;
		END

		PORT
			 LAYER M4 ;
			RECT 0.2105 29.2095 8.463 29.2571 ;
			 LAYER V3 ;
			RECT 1.3622 29.227 1.3995 29.2397 ;
			RECT 1.4957 29.2175 1.5106 29.2492 ;
			RECT 1.8489 29.2175 1.8639 29.2492 ;
			RECT 2.2153 29.2175 2.2302 29.2492 ;
			RECT 2.2876 29.2175 2.3025 29.2492 ;
			RECT 2.5881 29.2175 2.6031 29.2492 ;
			RECT 2.7547 29.2175 2.7697 29.2492 ;
			RECT 3.2037 29.2175 3.2186 29.2492 ;
			RECT 3.9933 29.2175 4.0082 29.2492 ;
			RECT 4.3853 29.2175 4.4002 29.2492 ;
		END

		PORT
			 LAYER M4 ;
			RECT 0.2105 28.4095 8.463 28.4571 ;
			 LAYER V3 ;
			RECT 1.3622 28.427 1.3995 28.4397 ;
			RECT 1.4957 28.4175 1.5106 28.4492 ;
			RECT 1.8489 28.4175 1.8639 28.4492 ;
			RECT 2.2153 28.4175 2.2302 28.4492 ;
			RECT 2.2876 28.4175 2.3025 28.4492 ;
			RECT 2.5881 28.4175 2.6031 28.4492 ;
			RECT 2.7547 28.4175 2.7697 28.4492 ;
			RECT 3.2037 28.4175 3.2186 28.4492 ;
			RECT 3.9933 28.4175 4.0082 28.4492 ;
			RECT 4.3853 28.4175 4.4002 28.4492 ;
		END

		PORT
			 LAYER M4 ;
			RECT 0.2105 43.0476 8.463 43.0952 ;
			 LAYER V3 ;
			RECT 1.3622 43.0651 1.3995 43.0778 ;
			RECT 1.6907 43.0556 1.7057 43.0873 ;
			RECT 2.1765 43.0556 2.1915 43.0873 ;
			RECT 2.2876 43.0556 2.3025 43.0873 ;
			RECT 2.5881 43.0556 2.6031 43.0873 ;
			RECT 3.1943 43.0556 3.2093 43.0873 ;
			RECT 3.9933 43.0556 4.0082 43.0873 ;
			RECT 4.3853 43.0556 4.4002 43.0873 ;
		END

		PORT
			 LAYER M4 ;
			RECT 0.2105 27.8476 8.463 27.8952 ;
			 LAYER V3 ;
			RECT 1.3622 27.8651 1.3995 27.8778 ;
			RECT 1.6907 27.8556 1.7057 27.8873 ;
			RECT 2.1765 27.8556 2.1915 27.8873 ;
			RECT 2.2876 27.8556 2.3025 27.8873 ;
			RECT 2.5881 27.8556 2.6031 27.8873 ;
			RECT 3.1943 27.8556 3.2093 27.8873 ;
			RECT 3.9933 27.8556 4.0082 27.8873 ;
			RECT 4.3853 27.8556 4.4002 27.8873 ;
		END

		PORT
			 LAYER M4 ;
			RECT 0.2105 27.0476 8.463 27.0952 ;
			 LAYER V3 ;
			RECT 1.3622 27.0651 1.3995 27.0778 ;
			RECT 1.6907 27.0556 1.7057 27.0873 ;
			RECT 2.1765 27.0556 2.1915 27.0873 ;
			RECT 2.2876 27.0556 2.3025 27.0873 ;
			RECT 2.5881 27.0556 2.6031 27.0873 ;
			RECT 3.1943 27.0556 3.2093 27.0873 ;
			RECT 3.9933 27.0556 4.0082 27.0873 ;
			RECT 4.3853 27.0556 4.4002 27.0873 ;
		END

		PORT
			 LAYER M4 ;
			RECT 0.2105 42.2476 8.463 42.2952 ;
			 LAYER V3 ;
			RECT 1.3622 42.2651 1.3995 42.2778 ;
			RECT 1.6907 42.2556 1.7057 42.2873 ;
			RECT 2.1765 42.2556 2.1915 42.2873 ;
			RECT 2.2876 42.2556 2.3025 42.2873 ;
			RECT 2.5881 42.2556 2.6031 42.2873 ;
			RECT 3.1943 42.2556 3.2093 42.2873 ;
			RECT 3.9933 42.2556 4.0082 42.2873 ;
			RECT 4.3853 42.2556 4.4002 42.2873 ;
		END

		PORT
			 LAYER M4 ;
			RECT 0.2105 26.2476 8.463 26.2952 ;
			 LAYER V3 ;
			RECT 1.3622 26.2651 1.3995 26.2778 ;
			RECT 1.6907 26.2556 1.7057 26.2873 ;
			RECT 2.1765 26.2556 2.1915 26.2873 ;
			RECT 2.2876 26.2556 2.3025 26.2873 ;
			RECT 2.5881 26.2556 2.6031 26.2873 ;
			RECT 3.1943 26.2556 3.2093 26.2873 ;
			RECT 3.9933 26.2556 4.0082 26.2873 ;
			RECT 4.3853 26.2556 4.4002 26.2873 ;
		END

		PORT
			 LAYER M4 ;
			RECT 0.2105 25.4476 8.463 25.4952 ;
			 LAYER V3 ;
			RECT 1.3622 25.4651 1.3995 25.4778 ;
			RECT 1.6907 25.4556 1.7057 25.4873 ;
			RECT 2.1765 25.4556 2.1915 25.4873 ;
			RECT 2.2876 25.4556 2.3025 25.4873 ;
			RECT 2.5881 25.4556 2.6031 25.4873 ;
			RECT 3.1943 25.4556 3.2093 25.4873 ;
			RECT 3.9933 25.4556 4.0082 25.4873 ;
			RECT 4.3853 25.4556 4.4002 25.4873 ;
		END

		PORT
			 LAYER M4 ;
			RECT 0.2105 17.6857 8.463 17.7333 ;
			 LAYER V3 ;
			RECT 1.3622 17.7032 1.3995 17.7159 ;
			RECT 1.6907 17.6937 1.7057 17.7254 ;
			RECT 2.1765 17.6937 2.1915 17.7254 ;
			RECT 2.2876 17.6937 2.3025 17.7254 ;
			RECT 2.5881 17.6937 2.6031 17.7254 ;
			RECT 3.1943 17.6937 3.2093 17.7254 ;
			RECT 3.9933 17.6937 4.0082 17.7254 ;
			RECT 4.3853 17.6937 4.4002 17.7254 ;
		END

		PORT
			 LAYER M4 ;
			RECT 0.2105 16.8857 8.463 16.9333 ;
			 LAYER V3 ;
			RECT 1.3622 16.9032 1.3995 16.9159 ;
			RECT 1.6907 16.8937 1.7057 16.9254 ;
			RECT 2.1765 16.8937 2.1915 16.9254 ;
			RECT 2.2876 16.8937 2.3025 16.9254 ;
			RECT 2.5881 16.8937 2.6031 16.9254 ;
			RECT 3.1943 16.8937 3.2093 16.9254 ;
			RECT 3.9933 16.8937 4.0082 16.9254 ;
			RECT 4.3853 16.8937 4.4002 16.9254 ;
		END

		PORT
			 LAYER M4 ;
			RECT 0.2105 41.4476 8.463 41.4952 ;
			 LAYER V3 ;
			RECT 1.3622 41.4651 1.3995 41.4778 ;
			RECT 1.6907 41.4556 1.7057 41.4873 ;
			RECT 2.1765 41.4556 2.1915 41.4873 ;
			RECT 2.2876 41.4556 2.3025 41.4873 ;
			RECT 2.5881 41.4556 2.6031 41.4873 ;
			RECT 3.1943 41.4556 3.2093 41.4873 ;
			RECT 3.9933 41.4556 4.0082 41.4873 ;
			RECT 4.3853 41.4556 4.4002 41.4873 ;
		END

		PORT
			 LAYER M4 ;
			RECT 0.2105 16.0857 8.463 16.1333 ;
			 LAYER V3 ;
			RECT 1.3622 16.1032 1.3995 16.1159 ;
			RECT 1.6907 16.0937 1.7057 16.1254 ;
			RECT 2.1765 16.0937 2.1915 16.1254 ;
			RECT 2.2876 16.0937 2.3025 16.1254 ;
			RECT 2.5881 16.0937 2.6031 16.1254 ;
			RECT 3.1943 16.0937 3.2093 16.1254 ;
			RECT 3.9933 16.0937 4.0082 16.1254 ;
			RECT 4.3853 16.0937 4.4002 16.1254 ;
		END

		PORT
			 LAYER M4 ;
			RECT 0.2105 15.2857 8.463 15.3333 ;
			 LAYER V3 ;
			RECT 1.3622 15.3032 1.3995 15.3159 ;
			RECT 1.6907 15.2937 1.7057 15.3254 ;
			RECT 2.1765 15.2937 2.1915 15.3254 ;
			RECT 2.2876 15.2937 2.3025 15.3254 ;
			RECT 2.5881 15.2937 2.6031 15.3254 ;
			RECT 3.1943 15.2937 3.2093 15.3254 ;
			RECT 3.9933 15.2937 4.0082 15.3254 ;
			RECT 4.3853 15.2937 4.4002 15.3254 ;
		END

		PORT
			 LAYER M4 ;
			RECT 0.2105 14.4857 8.463 14.5333 ;
			 LAYER V3 ;
			RECT 1.3622 14.5032 1.3995 14.5159 ;
			RECT 1.6907 14.4937 1.7057 14.5254 ;
			RECT 2.1765 14.4937 2.1915 14.5254 ;
			RECT 2.2876 14.4937 2.3025 14.5254 ;
			RECT 2.5881 14.4937 2.6031 14.5254 ;
			RECT 3.1943 14.4937 3.2093 14.5254 ;
			RECT 3.9933 14.4937 4.0082 14.5254 ;
			RECT 4.3853 14.4937 4.4002 14.5254 ;
		END

		PORT
			 LAYER M4 ;
			RECT 0.2105 13.6857 8.463 13.7333 ;
			 LAYER V3 ;
			RECT 1.3622 13.7032 1.3995 13.7159 ;
			RECT 1.6907 13.6937 1.7057 13.7254 ;
			RECT 2.1765 13.6937 2.1915 13.7254 ;
			RECT 2.2876 13.6937 2.3025 13.7254 ;
			RECT 2.5881 13.6937 2.6031 13.7254 ;
			RECT 3.1943 13.6937 3.2093 13.7254 ;
			RECT 3.9933 13.6937 4.0082 13.7254 ;
			RECT 4.3853 13.6937 4.4002 13.7254 ;
		END

		PORT
			 LAYER M4 ;
			RECT 0.2105 12.8857 8.463 12.9333 ;
			 LAYER V3 ;
			RECT 1.3622 12.9032 1.3995 12.9159 ;
			RECT 1.6907 12.8937 1.7057 12.9254 ;
			RECT 2.1765 12.8937 2.1915 12.9254 ;
			RECT 2.2876 12.8937 2.3025 12.9254 ;
			RECT 2.5881 12.8937 2.6031 12.9254 ;
			RECT 3.1943 12.8937 3.2093 12.9254 ;
			RECT 3.9933 12.8937 4.0082 12.9254 ;
			RECT 4.3853 12.8937 4.4002 12.9254 ;
		END

		PORT
			 LAYER M4 ;
			RECT 0.2105 12.0857 8.463 12.1333 ;
			 LAYER V3 ;
			RECT 1.3622 12.1032 1.3995 12.1159 ;
			RECT 1.6907 12.0937 1.7057 12.1254 ;
			RECT 2.1765 12.0937 2.1915 12.1254 ;
			RECT 2.2876 12.0937 2.3025 12.1254 ;
			RECT 2.5881 12.0937 2.6031 12.1254 ;
			RECT 3.1943 12.0937 3.2093 12.1254 ;
			RECT 3.9933 12.0937 4.0082 12.1254 ;
			RECT 4.3853 12.0937 4.4002 12.1254 ;
		END

		PORT
			 LAYER M4 ;
			RECT 0.2105 11.2857 8.463 11.3333 ;
			 LAYER V3 ;
			RECT 1.3622 11.3032 1.3995 11.3159 ;
			RECT 1.6907 11.2937 1.7057 11.3254 ;
			RECT 2.1765 11.2937 2.1915 11.3254 ;
			RECT 2.2876 11.2937 2.3025 11.3254 ;
			RECT 2.5881 11.2937 2.6031 11.3254 ;
			RECT 3.1943 11.2937 3.2093 11.3254 ;
			RECT 3.9933 11.2937 4.0082 11.3254 ;
			RECT 4.3853 11.2937 4.4002 11.3254 ;
		END

		PORT
			 LAYER M4 ;
			RECT 0.2105 10.4857 8.463 10.5333 ;
			 LAYER V3 ;
			RECT 1.3622 10.5032 1.3995 10.5159 ;
			RECT 1.6907 10.4937 1.7057 10.5254 ;
			RECT 2.1765 10.4937 2.1915 10.5254 ;
			RECT 2.2876 10.4937 2.3025 10.5254 ;
			RECT 2.5881 10.4937 2.6031 10.5254 ;
			RECT 3.1943 10.4937 3.2093 10.5254 ;
			RECT 3.9933 10.4937 4.0082 10.5254 ;
			RECT 4.3853 10.4937 4.4002 10.5254 ;
		END

		PORT
			 LAYER M4 ;
			RECT 0.2105 9.6857 8.463 9.7333 ;
			 LAYER V3 ;
			RECT 1.3622 9.7032 1.3995 9.7159 ;
			RECT 1.6907 9.6937 1.7057 9.7254 ;
			RECT 2.1765 9.6937 2.1915 9.7254 ;
			RECT 2.2876 9.6937 2.3025 9.7254 ;
			RECT 2.5881 9.6937 2.6031 9.7254 ;
			RECT 3.1943 9.6937 3.2093 9.7254 ;
			RECT 3.9933 9.6937 4.0082 9.7254 ;
			RECT 4.3853 9.6937 4.4002 9.7254 ;
		END

		PORT
			 LAYER M4 ;
			RECT 0.2105 8.8857 8.463 8.9333 ;
			 LAYER V3 ;
			RECT 1.3622 8.9032 1.3995 8.9159 ;
			RECT 1.6907 8.8937 1.7057 8.9254 ;
			RECT 2.1765 8.8937 2.1915 8.9254 ;
			RECT 2.2876 8.8937 2.3025 8.9254 ;
			RECT 2.5881 8.8937 2.6031 8.9254 ;
			RECT 3.1943 8.8937 3.2093 8.9254 ;
			RECT 3.9933 8.8937 4.0082 8.9254 ;
			RECT 4.3853 8.8937 4.4002 8.9254 ;
		END

		PORT
			 LAYER M4 ;
			RECT 0.2105 40.6476 8.463 40.6952 ;
			 LAYER V3 ;
			RECT 1.3622 40.6651 1.3995 40.6778 ;
			RECT 1.6907 40.6556 1.7057 40.6873 ;
			RECT 2.1765 40.6556 2.1915 40.6873 ;
			RECT 2.2876 40.6556 2.3025 40.6873 ;
			RECT 2.5881 40.6556 2.6031 40.6873 ;
			RECT 3.1943 40.6556 3.2093 40.6873 ;
			RECT 3.9933 40.6556 4.0082 40.6873 ;
			RECT 4.3853 40.6556 4.4002 40.6873 ;
		END

		PORT
			 LAYER M4 ;
			RECT 0.2105 8.0857 8.463 8.1333 ;
			 LAYER V3 ;
			RECT 1.3622 8.1032 1.3995 8.1159 ;
			RECT 1.6907 8.0937 1.7057 8.1254 ;
			RECT 2.1765 8.0937 2.1915 8.1254 ;
			RECT 2.2876 8.0937 2.3025 8.1254 ;
			RECT 2.5881 8.0937 2.6031 8.1254 ;
			RECT 3.1943 8.0937 3.2093 8.1254 ;
			RECT 3.9933 8.0937 4.0082 8.1254 ;
			RECT 4.3853 8.0937 4.4002 8.1254 ;
		END

		PORT
			 LAYER M4 ;
			RECT 0.2105 7.2857 8.463 7.3333 ;
			 LAYER V3 ;
			RECT 1.3622 7.3032 1.3995 7.3159 ;
			RECT 1.6907 7.2937 1.7057 7.3254 ;
			RECT 2.1765 7.2937 2.1915 7.3254 ;
			RECT 2.2876 7.2937 2.3025 7.3254 ;
			RECT 2.5881 7.2937 2.6031 7.3254 ;
			RECT 3.1943 7.2937 3.2093 7.3254 ;
			RECT 3.9933 7.2937 4.0082 7.3254 ;
			RECT 4.3853 7.2937 4.4002 7.3254 ;
		END

		PORT
			 LAYER M4 ;
			RECT 0.2105 6.4857 8.463 6.5333 ;
			 LAYER V3 ;
			RECT 1.3622 6.5032 1.3995 6.5159 ;
			RECT 1.6907 6.4937 1.7057 6.5254 ;
			RECT 2.1765 6.4937 2.1915 6.5254 ;
			RECT 2.2876 6.4937 2.3025 6.5254 ;
			RECT 2.5881 6.4937 2.6031 6.5254 ;
			RECT 3.1943 6.4937 3.2093 6.5254 ;
			RECT 3.9933 6.4937 4.0082 6.5254 ;
			RECT 4.3853 6.4937 4.4002 6.5254 ;
		END

		PORT
			 LAYER M4 ;
			RECT 0.2105 5.6857 8.463 5.7333 ;
			 LAYER V3 ;
			RECT 1.3622 5.7032 1.3995 5.7159 ;
			RECT 1.6907 5.6937 1.7057 5.7254 ;
			RECT 2.1765 5.6937 2.1915 5.7254 ;
			RECT 2.2876 5.6937 2.3025 5.7254 ;
			RECT 2.5881 5.6937 2.6031 5.7254 ;
			RECT 3.1943 5.6937 3.2093 5.7254 ;
			RECT 3.9933 5.6937 4.0082 5.7254 ;
			RECT 4.3853 5.6937 4.4002 5.7254 ;
		END

		PORT
			 LAYER M4 ;
			RECT 0.2105 4.8857 8.463 4.9333 ;
			 LAYER V3 ;
			RECT 1.3622 4.9032 1.3995 4.9159 ;
			RECT 1.6907 4.8937 1.7057 4.9254 ;
			RECT 2.1765 4.8937 2.1915 4.9254 ;
			RECT 2.2876 4.8937 2.3025 4.9254 ;
			RECT 2.5881 4.8937 2.6031 4.9254 ;
			RECT 3.1943 4.8937 3.2093 4.9254 ;
			RECT 3.9933 4.8937 4.0082 4.9254 ;
			RECT 4.3853 4.8937 4.4002 4.9254 ;
		END

		PORT
			 LAYER M4 ;
			RECT 0.2105 4.0857 8.463 4.1333 ;
			 LAYER V3 ;
			RECT 1.3622 4.1032 1.3995 4.1159 ;
			RECT 1.6907 4.0937 1.7057 4.1254 ;
			RECT 2.1765 4.0937 2.1915 4.1254 ;
			RECT 2.2876 4.0937 2.3025 4.1254 ;
			RECT 2.5881 4.0937 2.6031 4.1254 ;
			RECT 3.1943 4.0937 3.2093 4.1254 ;
			RECT 3.9933 4.0937 4.0082 4.1254 ;
			RECT 4.3853 4.0937 4.4002 4.1254 ;
		END

		PORT
			 LAYER M4 ;
			RECT 0.2105 3.2857 8.463 3.3333 ;
			 LAYER V3 ;
			RECT 1.3622 3.3032 1.3995 3.3159 ;
			RECT 1.6907 3.2937 1.7057 3.3254 ;
			RECT 2.1765 3.2937 2.1915 3.3254 ;
			RECT 2.2876 3.2937 2.3025 3.3254 ;
			RECT 2.5881 3.2937 2.6031 3.3254 ;
			RECT 3.1943 3.2937 3.2093 3.3254 ;
			RECT 3.9933 3.2937 4.0082 3.3254 ;
			RECT 4.3853 3.2937 4.4002 3.3254 ;
		END

		PORT
			 LAYER M4 ;
			RECT 0.2105 2.4857 8.463 2.5333 ;
			 LAYER V3 ;
			RECT 1.3622 2.5032 1.3995 2.5159 ;
			RECT 1.6907 2.4937 1.7057 2.5254 ;
			RECT 2.1765 2.4937 2.1915 2.5254 ;
			RECT 2.2876 2.4937 2.3025 2.5254 ;
			RECT 2.5881 2.4937 2.6031 2.5254 ;
			RECT 3.1943 2.4937 3.2093 2.5254 ;
			RECT 3.9933 2.4937 4.0082 2.5254 ;
			RECT 4.3853 2.4937 4.4002 2.5254 ;
		END

		PORT
			 LAYER M4 ;
			RECT 0.2105 1.6857 8.463 1.7333 ;
			 LAYER V3 ;
			RECT 1.3622 1.7032 1.3995 1.7159 ;
			RECT 1.6907 1.6937 1.7057 1.7254 ;
			RECT 2.1765 1.6937 2.1915 1.7254 ;
			RECT 2.2876 1.6937 2.3025 1.7254 ;
			RECT 2.5881 1.6937 2.6031 1.7254 ;
			RECT 3.1943 1.6937 3.2093 1.7254 ;
			RECT 3.9933 1.6937 4.0082 1.7254 ;
			RECT 4.3853 1.6937 4.4002 1.7254 ;
		END

		PORT
			 LAYER M4 ;
			RECT 0.2105 0.8857 8.463 0.9333 ;
			 LAYER V3 ;
			RECT 1.3622 0.9032 1.3995 0.9159 ;
			RECT 1.6907 0.8937 1.7057 0.9254 ;
			RECT 2.1765 0.8937 2.1915 0.9254 ;
			RECT 2.2876 0.8937 2.3025 0.9254 ;
			RECT 2.5881 0.8937 2.6031 0.9254 ;
			RECT 3.1943 0.8937 3.2093 0.9254 ;
			RECT 3.9933 0.8937 4.0082 0.9254 ;
			RECT 4.3853 0.8937 4.4002 0.9254 ;
		END

		PORT
			 LAYER M4 ;
			RECT 0.2105 39.8476 8.463 39.8952 ;
			 LAYER V3 ;
			RECT 1.3622 39.8651 1.3995 39.8778 ;
			RECT 1.6907 39.8556 1.7057 39.8873 ;
			RECT 2.1765 39.8556 2.1915 39.8873 ;
			RECT 2.2876 39.8556 2.3025 39.8873 ;
			RECT 2.5881 39.8556 2.6031 39.8873 ;
			RECT 3.1943 39.8556 3.2093 39.8873 ;
			RECT 3.9933 39.8556 4.0082 39.8873 ;
			RECT 4.3853 39.8556 4.4002 39.8873 ;
		END

		PORT
			 LAYER M4 ;
			RECT 0.2105 39.0476 8.463 39.0952 ;
			 LAYER V3 ;
			RECT 1.3622 39.0651 1.3995 39.0778 ;
			RECT 1.6907 39.0556 1.7057 39.0873 ;
			RECT 2.1765 39.0556 2.1915 39.0873 ;
			RECT 2.2876 39.0556 2.3025 39.0873 ;
			RECT 2.5881 39.0556 2.6031 39.0873 ;
			RECT 3.1943 39.0556 3.2093 39.0873 ;
			RECT 3.9933 39.0556 4.0082 39.0873 ;
			RECT 4.3853 39.0556 4.4002 39.0873 ;
		END

		PORT
			 LAYER M4 ;
			RECT 0.2105 38.2476 8.463 38.2952 ;
			 LAYER V3 ;
			RECT 1.3622 38.2651 1.3995 38.2778 ;
			RECT 1.6907 38.2556 1.7057 38.2873 ;
			RECT 2.1765 38.2556 2.1915 38.2873 ;
			RECT 2.2876 38.2556 2.3025 38.2873 ;
			RECT 2.5881 38.2556 2.6031 38.2873 ;
			RECT 3.1943 38.2556 3.2093 38.2873 ;
			RECT 3.9933 38.2556 4.0082 38.2873 ;
			RECT 4.3853 38.2556 4.4002 38.2873 ;
		END

		PORT
			 LAYER M4 ;
			RECT 0.2105 37.4476 8.463 37.4952 ;
			 LAYER V3 ;
			RECT 1.3622 37.4651 1.3995 37.4778 ;
			RECT 1.6907 37.4556 1.7057 37.4873 ;
			RECT 2.1765 37.4556 2.1915 37.4873 ;
			RECT 2.2876 37.4556 2.3025 37.4873 ;
			RECT 2.5881 37.4556 2.6031 37.4873 ;
			RECT 3.1943 37.4556 3.2093 37.4873 ;
			RECT 3.9933 37.4556 4.0082 37.4873 ;
			RECT 4.3853 37.4556 4.4002 37.4873 ;
		END

		PORT
			 LAYER M4 ;
			RECT 0.2105 36.6476 8.463 36.6952 ;
			 LAYER V3 ;
			RECT 1.3622 36.6651 1.3995 36.6778 ;
			RECT 1.6907 36.6556 1.7057 36.6873 ;
			RECT 2.1765 36.6556 2.1915 36.6873 ;
			RECT 2.2876 36.6556 2.3025 36.6873 ;
			RECT 2.5881 36.6556 2.6031 36.6873 ;
			RECT 3.1943 36.6556 3.2093 36.6873 ;
			RECT 3.9933 36.6556 4.0082 36.6873 ;
			RECT 4.3853 36.6556 4.4002 36.6873 ;
		END

		PORT
			 LAYER M4 ;
			RECT 0.2105 35.8476 8.463 35.8952 ;
			 LAYER V3 ;
			RECT 1.3622 35.8651 1.3995 35.8778 ;
			RECT 1.6907 35.8556 1.7057 35.8873 ;
			RECT 2.1765 35.8556 2.1915 35.8873 ;
			RECT 2.2876 35.8556 2.3025 35.8873 ;
			RECT 2.5881 35.8556 2.6031 35.8873 ;
			RECT 3.1943 35.8556 3.2093 35.8873 ;
			RECT 3.9933 35.8556 4.0082 35.8873 ;
			RECT 4.3853 35.8556 4.4002 35.8873 ;
		END

		PORT
			 LAYER M4 ;
			RECT 0.2105 35.0476 8.463 35.0952 ;
			 LAYER V3 ;
			RECT 1.3622 35.0651 1.3995 35.0778 ;
			RECT 1.6907 35.0556 1.7057 35.0873 ;
			RECT 2.1765 35.0556 2.1915 35.0873 ;
			RECT 2.2876 35.0556 2.3025 35.0873 ;
			RECT 2.5881 35.0556 2.6031 35.0873 ;
			RECT 3.1943 35.0556 3.2093 35.0873 ;
			RECT 3.9933 35.0556 4.0082 35.0873 ;
			RECT 4.3853 35.0556 4.4002 35.0873 ;
		END

		PORT
			 LAYER M4 ;
			RECT 0.2105 34.2476 8.463 34.2952 ;
			 LAYER V3 ;
			RECT 1.3622 34.2651 1.3995 34.2778 ;
			RECT 1.6907 34.2556 1.7057 34.2873 ;
			RECT 2.1765 34.2556 2.1915 34.2873 ;
			RECT 2.2876 34.2556 2.3025 34.2873 ;
			RECT 2.5881 34.2556 2.6031 34.2873 ;
			RECT 3.1943 34.2556 3.2093 34.2873 ;
			RECT 3.9933 34.2556 4.0082 34.2873 ;
			RECT 4.3853 34.2556 4.4002 34.2873 ;
		END

		PORT
			 LAYER M4 ;
			RECT 0.2105 33.4476 8.463 33.4952 ;
			 LAYER V3 ;
			RECT 1.3622 33.4651 1.3995 33.4778 ;
			RECT 1.6907 33.4556 1.7057 33.4873 ;
			RECT 2.1765 33.4556 2.1915 33.4873 ;
			RECT 2.2876 33.4556 2.3025 33.4873 ;
			RECT 2.5881 33.4556 2.6031 33.4873 ;
			RECT 3.1943 33.4556 3.2093 33.4873 ;
			RECT 3.9933 33.4556 4.0082 33.4873 ;
			RECT 4.3853 33.4556 4.4002 33.4873 ;
		END

		PORT
			 LAYER M4 ;
			RECT 0.2105 32.6476 8.463 32.6952 ;
			 LAYER V3 ;
			RECT 1.3622 32.6651 1.3995 32.6778 ;
			RECT 1.6907 32.6556 1.7057 32.6873 ;
			RECT 2.1765 32.6556 2.1915 32.6873 ;
			RECT 2.2876 32.6556 2.3025 32.6873 ;
			RECT 2.5881 32.6556 2.6031 32.6873 ;
			RECT 3.1943 32.6556 3.2093 32.6873 ;
			RECT 3.9933 32.6556 4.0082 32.6873 ;
			RECT 4.3853 32.6556 4.4002 32.6873 ;
		END

		PORT
			 LAYER M4 ;
			RECT 0.2105 31.8476 8.463 31.8952 ;
			 LAYER V3 ;
			RECT 1.3622 31.8651 1.3995 31.8778 ;
			RECT 1.6907 31.8556 1.7057 31.8873 ;
			RECT 2.1765 31.8556 2.1915 31.8873 ;
			RECT 2.2876 31.8556 2.3025 31.8873 ;
			RECT 2.5881 31.8556 2.6031 31.8873 ;
			RECT 3.1943 31.8556 3.2093 31.8873 ;
			RECT 3.9933 31.8556 4.0082 31.8873 ;
			RECT 4.3853 31.8556 4.4002 31.8873 ;
		END

		PORT
			 LAYER M4 ;
			RECT 0.2105 31.0476 8.463 31.0952 ;
			 LAYER V3 ;
			RECT 1.3622 31.0651 1.3995 31.0778 ;
			RECT 1.6907 31.0556 1.7057 31.0873 ;
			RECT 2.1765 31.0556 2.1915 31.0873 ;
			RECT 2.2876 31.0556 2.3025 31.0873 ;
			RECT 2.5881 31.0556 2.6031 31.0873 ;
			RECT 3.1943 31.0556 3.2093 31.0873 ;
			RECT 3.9933 31.0556 4.0082 31.0873 ;
			RECT 4.3853 31.0556 4.4002 31.0873 ;
		END

		PORT
			 LAYER M4 ;
			RECT 0.2105 30.2476 8.463 30.2952 ;
			 LAYER V3 ;
			RECT 1.3622 30.2651 1.3995 30.2778 ;
			RECT 1.6907 30.2556 1.7057 30.2873 ;
			RECT 2.1765 30.2556 2.1915 30.2873 ;
			RECT 2.2876 30.2556 2.3025 30.2873 ;
			RECT 2.5881 30.2556 2.6031 30.2873 ;
			RECT 3.1943 30.2556 3.2093 30.2873 ;
			RECT 3.9933 30.2556 4.0082 30.2873 ;
			RECT 4.3853 30.2556 4.4002 30.2873 ;
		END

		PORT
			 LAYER M4 ;
			RECT 0.2105 29.4476 8.463 29.4952 ;
			 LAYER V3 ;
			RECT 1.3622 29.4651 1.3995 29.4778 ;
			RECT 1.6907 29.4556 1.7057 29.4873 ;
			RECT 2.1765 29.4556 2.1915 29.4873 ;
			RECT 2.2876 29.4556 2.3025 29.4873 ;
			RECT 2.5881 29.4556 2.6031 29.4873 ;
			RECT 3.1943 29.4556 3.2093 29.4873 ;
			RECT 3.9933 29.4556 4.0082 29.4873 ;
			RECT 4.3853 29.4556 4.4002 29.4873 ;
		END

		PORT
			 LAYER M4 ;
			RECT 0.2105 28.6476 8.463 28.6952 ;
			 LAYER V3 ;
			RECT 1.3622 28.6651 1.3995 28.6778 ;
			RECT 1.6907 28.6556 1.7057 28.6873 ;
			RECT 2.1765 28.6556 2.1915 28.6873 ;
			RECT 2.2876 28.6556 2.3025 28.6873 ;
			RECT 2.5881 28.6556 2.6031 28.6873 ;
			RECT 3.1943 28.6556 3.2093 28.6873 ;
			RECT 3.9933 28.6556 4.0082 28.6873 ;
			RECT 4.3853 28.6556 4.4002 28.6873 ;
		END

		PORT
			 LAYER M4 ;
			RECT 0.2105 18.1143 8.463 18.1619 ;
			 LAYER V3 ;
			RECT 1.3739 18.1222 1.3888 18.154 ;
			RECT 2.2876 18.1222 2.3025 18.154 ;
			RECT 4.3857 18.1317 4.4231 18.1444 ;
		END

		PORT
			 LAYER M4 ;
			RECT 0.2105 18.7381 8.463 18.7857 ;
			 LAYER V3 ;
			RECT 1.3809 18.746 1.3958 18.7778 ;
			RECT 2.2876 18.746 2.3025 18.7778 ;
			RECT 3.1873 18.746 3.2023 18.7778 ;
			RECT 3.9811 18.746 3.9961 18.7778 ;
			RECT 4.3857 18.7556 4.4231 18.7683 ;
		END

		PORT
			 LAYER M4 ;
			RECT 0.2105 19.2714 8.463 19.319 ;
			 LAYER V3 ;
			RECT 2.2876 19.2794 2.3025 19.3111 ;
			RECT 3.1873 19.2794 3.2023 19.3111 ;
			RECT 4.3857 19.2889 4.4231 19.3016 ;
		END

		PORT
			 LAYER M4 ;
			RECT 0.2105 19.8048 8.463 19.8524 ;
			 LAYER V3 ;
			RECT 2.2876 19.8127 2.3025 19.8444 ;
			RECT 3.0483 19.8222 3.0856 19.8349 ;
			RECT 3.1873 19.8127 3.2023 19.8444 ;
			RECT 4.3857 19.8222 4.4231 19.8349 ;
		END

		PORT
			 LAYER M4 ;
			RECT 0.2105 20.3381 8.463 20.3857 ;
			 LAYER V3 ;
			RECT 2.2876 20.346 2.3025 20.3778 ;
			RECT 3.0595 20.346 3.0744 20.3778 ;
			RECT 3.1873 20.346 3.2023 20.3778 ;
			RECT 4.3857 20.3556 4.4231 20.3683 ;
			RECT 5.5589 20.346 5.5739 20.3778 ;
			RECT 5.7722 20.346 5.7871 20.3778 ;
			RECT 8.3706 20.346 8.3855 20.3778 ;
		END

		PORT
			 LAYER M4 ;
			RECT 0.2105 20.8714 8.463 20.919 ;
			 LAYER V3 ;
			RECT 2.2876 20.8794 2.3025 20.9111 ;
			RECT 3.0595 20.8794 3.0744 20.9111 ;
			RECT 3.1873 20.8794 3.2023 20.9111 ;
			RECT 4.3857 20.8889 4.4231 20.9016 ;
			RECT 5.6014 20.8794 5.6163 20.9111 ;
			RECT 6.7737 20.8794 6.7886 20.9111 ;
			RECT 7.1097 20.8794 7.1246 20.9111 ;
			RECT 7.4457 20.8794 7.4606 20.9111 ;
			RECT 7.7817 20.8794 7.7966 20.9111 ;
			RECT 8.3706 20.8794 8.3855 20.9111 ;
		END

		PORT
			 LAYER M4 ;
			RECT 0.2105 21.9381 8.463 21.9857 ;
			 LAYER V3 ;
			RECT 1.3809 21.946 1.3958 21.9778 ;
			RECT 2.2876 21.946 2.3025 21.9778 ;
			RECT 3.0595 21.946 3.0744 21.9778 ;
			RECT 3.1873 21.946 3.2023 21.9778 ;
			RECT 3.7245 21.9556 3.7394 21.9683 ;
			RECT 4.3857 21.9556 4.4231 21.9683 ;
			RECT 5.6005 21.946 5.6154 21.9778 ;
			RECT 5.8515 21.946 5.8665 21.9778 ;
			RECT 6.2594 21.946 6.2743 21.9778 ;
			RECT 6.7737 21.946 6.7886 21.9778 ;
			RECT 7.1097 21.946 7.1246 21.9778 ;
			RECT 7.4457 21.946 7.4606 21.9778 ;
			RECT 7.7817 21.946 7.7966 21.9778 ;
			RECT 8.3706 21.946 8.3855 21.9778 ;
		END

		PORT
			 LAYER M4 ;
			RECT 0.2105 23.0048 8.463 23.0524 ;
			 LAYER V3 ;
			RECT 1.3809 23.0127 1.3958 23.0444 ;
			RECT 2.0025 23.0127 2.0174 23.0444 ;
			RECT 2.1742 23.0222 2.1891 23.0349 ;
			RECT 2.2876 23.0127 2.3025 23.0444 ;
			RECT 2.4402 23.0127 2.4551 23.0444 ;
			RECT 3.0595 23.0127 3.0744 23.0444 ;
			RECT 3.1976 23.0127 3.2125 23.0444 ;
			RECT 4.3857 23.0222 4.4231 23.0349 ;
		END

		PORT
			 LAYER M4 ;
			RECT 0.2105 23.5381 8.463 23.5857 ;
			 LAYER V3 ;
			RECT 1.3809 23.546 1.3958 23.5778 ;
			RECT 2.0025 23.546 2.0174 23.5778 ;
			RECT 2.1742 23.5556 2.1891 23.5683 ;
			RECT 2.2876 23.546 2.3025 23.5778 ;
			RECT 2.4402 23.546 2.4551 23.5778 ;
			RECT 3.1873 23.546 3.2023 23.5778 ;
			RECT 4.3857 23.5556 4.4231 23.5683 ;
		END

		PORT
			 LAYER M4 ;
			RECT 0.2105 24.0714 8.463 24.119 ;
			 LAYER V3 ;
			RECT 1.3809 24.0794 1.3958 24.1111 ;
			RECT 2.1742 24.0889 2.1891 24.1016 ;
			RECT 2.2876 24.0794 2.3025 24.1111 ;
			RECT 3.1869 24.0794 3.2018 24.1111 ;
			RECT 4.3857 24.0889 4.4231 24.1016 ;
		END

		PORT
			 LAYER M4 ;
			RECT 0.2105 24.6048 8.463 24.6524 ;
			 LAYER V3 ;
			RECT 1.3809 24.6127 1.3958 24.6444 ;
			RECT 1.6655 24.6127 1.6805 24.6444 ;
			RECT 2.17 24.6127 2.1849 24.6444 ;
			RECT 2.2876 24.6127 2.3025 24.6444 ;
			RECT 2.5615 24.6127 2.5765 24.6444 ;
			RECT 3.1869 24.6127 3.2018 24.6444 ;
			RECT 4.3857 24.6222 4.4231 24.6349 ;
			RECT 4.7409 24.6127 4.7558 24.6444 ;
		END

		PORT
			 LAYER M4 ;
			RECT 0.2105 24.7635 8.463 24.8111 ;
			 LAYER V3 ;
			RECT 1.3809 24.7714 1.3958 24.8032 ;
			RECT 1.6655 24.7714 1.6805 24.8032 ;
			RECT 2.17 24.7714 2.1849 24.8032 ;
			RECT 2.2876 24.7714 2.3025 24.8032 ;
			RECT 2.5615 24.7714 2.5765 24.8032 ;
			RECT 3.1873 24.7714 3.2023 24.8032 ;
			RECT 3.5481 24.7714 3.563 24.8032 ;
			RECT 3.9793 24.7714 3.9942 24.8032 ;
			RECT 4.3857 24.781 4.4231 24.7937 ;
			RECT 4.7409 24.7714 4.7558 24.8032 ;
		END

		PORT
			 LAYER M4 ;
			RECT 0.2105 17.9714 8.463 18.0032 ;
			 LAYER V3 ;
			RECT 0.3953 17.981 0.4102 17.9937 ;
			RECT 4.4511 17.981 4.4884 17.9937 ;
		END

		PORT
			 LAYER M4 ;
			RECT 0.2105 25.1778 8.463 25.2095 ;
			 LAYER V3 ;
			RECT 0.3953 25.1873 0.4102 25.2 ;
			RECT 4.4511 25.1873 4.4884 25.2 ;
		END

		PORT
			 LAYER M4 ;
			RECT 0.2105 43.8952 8.463 43.927 ;
			 LAYER V3 ;
			RECT 0.3953 43.9048 0.4102 43.9175 ;
			RECT 4.4511 43.9048 4.4884 43.9175 ;
		END

		PORT
			 LAYER M4 ;
			RECT 0.2105 0.054 8.463 0.0857 ;
			 LAYER V3 ;
			RECT 0.3953 0.0635 0.4102 0.0762 ;
			RECT 4.4511 0.0635 4.4884 0.0762 ;
		END

	END VDDPE

	PIN VSSE
		USE GROUND ;
		DIRECTION INOUT ;
		PORT
			 LAYER M4 ;
			RECT 0.2105 17.8444 8.463 17.8762 ;
			 LAYER V3 ;
			RECT 0.3626 17.854 0.3775 17.8667 ;
			RECT 3.2825 17.854 3.2975 17.8667 ;
			RECT 5.1189 17.854 5.1338 17.8667 ;
			RECT 7.9282 17.854 7.9431 17.8667 ;
		END

		PORT
			 LAYER M4 ;
			RECT 0.2105 25.3048 8.463 25.3365 ;
			 LAYER V3 ;
			RECT 0.3626 25.3143 0.3775 25.327 ;
			RECT 3.2825 25.3143 3.2975 25.327 ;
			RECT 5.1189 25.3143 5.1338 25.327 ;
			RECT 7.9282 25.3143 7.9431 25.327 ;
		END

		PORT
			 LAYER M4 ;
			RECT 0.2105 43.8317 8.463 43.8635 ;
			 LAYER V3 ;
			RECT 0.3626 43.8413 0.3775 43.854 ;
			RECT 3.2825 43.8413 3.2975 43.854 ;
			RECT 5.1189 43.8413 5.1338 43.854 ;
			RECT 7.9282 43.8413 7.9431 43.854 ;
		END

		PORT
			 LAYER M4 ;
			RECT 0.2105 0.1175 8.463 0.1492 ;
			 LAYER V3 ;
			RECT 0.3626 0.127 0.3775 0.1397 ;
			RECT 3.2825 0.127 3.2975 0.1397 ;
			RECT 5.1189 0.127 5.1338 0.1397 ;
			RECT 7.9282 0.127 7.9431 0.1397 ;
		END

		PORT
			 LAYER M4 ;
			RECT 0.2105 18.0349 8.463 18.0825 ;
			 LAYER V3 ;
			RECT 0.4387 18.0429 0.4536 18.0746 ;
			RECT 2.3968 18.0429 2.4117 18.0746 ;
			RECT 2.6805 18.0429 2.6955 18.0746 ;
			RECT 4.6293 18.0429 4.6443 18.0746 ;
			RECT 4.921 18.0429 4.9359 18.0746 ;
			RECT 5.1795 18.0429 5.1945 18.0746 ;
			RECT 5.2635 18.0429 5.2785 18.0746 ;
			RECT 5.3475 18.0429 5.3625 18.0746 ;
			RECT 5.4315 18.0429 5.4465 18.0746 ;
			RECT 5.5155 18.0429 5.5305 18.0746 ;
			RECT 5.5995 18.0429 5.6145 18.0746 ;
			RECT 5.6835 18.0429 5.6985 18.0746 ;
			RECT 5.7675 18.0429 5.7825 18.0746 ;
			RECT 5.8515 18.0429 5.8665 18.0746 ;
			RECT 5.9355 18.0429 5.9505 18.0746 ;
			RECT 6.0195 18.0429 6.0345 18.0746 ;
			RECT 6.1035 18.0429 6.1185 18.0746 ;
			RECT 6.1875 18.0429 6.2025 18.0746 ;
			RECT 6.2715 18.0429 6.2865 18.0746 ;
			RECT 6.3555 18.0429 6.3705 18.0746 ;
			RECT 6.4395 18.0429 6.4545 18.0746 ;
			RECT 6.5235 18.0429 6.5385 18.0746 ;
			RECT 6.6075 18.0429 6.6225 18.0746 ;
			RECT 6.6915 18.0429 6.7065 18.0746 ;
			RECT 6.7755 18.0429 6.7905 18.0746 ;
			RECT 6.8595 18.0429 6.8745 18.0746 ;
			RECT 6.9435 18.0429 6.9585 18.0746 ;
			RECT 7.0275 18.0429 7.0425 18.0746 ;
			RECT 7.1115 18.0429 7.1265 18.0746 ;
			RECT 7.1955 18.0429 7.2105 18.0746 ;
			RECT 7.2795 18.0429 7.2945 18.0746 ;
			RECT 7.3635 18.0429 7.3785 18.0746 ;
			RECT 7.4475 18.0429 7.4625 18.0746 ;
			RECT 7.5315 18.0429 7.5465 18.0746 ;
			RECT 7.6155 18.0429 7.6305 18.0746 ;
			RECT 7.6995 18.0429 7.7145 18.0746 ;
			RECT 7.7835 18.0429 7.7985 18.0746 ;
			RECT 7.8675 18.0429 7.8825 18.0746 ;
			RECT 8.1261 18.0429 8.141 18.0746 ;
		END

		PORT
			 LAYER M4 ;
			RECT 0.2105 18.4429 8.463 18.4905 ;
			 LAYER V3 ;
			RECT 0.4387 18.4508 0.4536 18.4825 ;
			RECT 2.3968 18.4508 2.4117 18.4825 ;
			RECT 2.4533 18.4508 2.4682 18.4825 ;
			RECT 2.5615 18.4508 2.5765 18.4825 ;
			RECT 2.6768 18.4508 2.6917 18.4825 ;
			RECT 3.2704 18.4508 3.2853 18.4825 ;
			RECT 4.6293 18.4508 4.6443 18.4825 ;
			RECT 5.18 18.4508 5.1949 18.4825 ;
			RECT 5.2635 18.4508 5.2785 18.4825 ;
			RECT 5.3475 18.4508 5.3625 18.4825 ;
			RECT 5.4315 18.4508 5.4465 18.4825 ;
			RECT 5.5155 18.4508 5.5305 18.4825 ;
			RECT 5.6 18.4508 5.6149 18.4825 ;
			RECT 5.6835 18.4508 5.6985 18.4825 ;
			RECT 5.7675 18.4508 5.7825 18.4825 ;
			RECT 5.8515 18.4508 5.8665 18.4825 ;
			RECT 5.9355 18.4508 5.9505 18.4825 ;
			RECT 6.0195 18.4508 6.0345 18.4825 ;
			RECT 6.1035 18.4508 6.1185 18.4825 ;
			RECT 6.1875 18.4508 6.2025 18.4825 ;
			RECT 6.2715 18.4508 6.2865 18.4825 ;
			RECT 6.3555 18.4508 6.3705 18.4825 ;
			RECT 6.4395 18.4508 6.4545 18.4825 ;
			RECT 6.5235 18.4508 6.5385 18.4825 ;
			RECT 6.6075 18.4508 6.6225 18.4825 ;
			RECT 6.6915 18.4508 6.7065 18.4825 ;
			RECT 6.7755 18.4508 6.7905 18.4825 ;
			RECT 6.8595 18.4508 6.8745 18.4825 ;
			RECT 6.9435 18.4508 6.9585 18.4825 ;
			RECT 7.0275 18.4508 7.0425 18.4825 ;
			RECT 7.1115 18.4508 7.1265 18.4825 ;
			RECT 7.1955 18.4508 7.2105 18.4825 ;
			RECT 7.2795 18.4508 7.2945 18.4825 ;
			RECT 7.3635 18.4508 7.3785 18.4825 ;
			RECT 7.4475 18.4508 7.4625 18.4825 ;
			RECT 7.5315 18.4508 7.5465 18.4825 ;
			RECT 7.6155 18.4508 7.6305 18.4825 ;
			RECT 7.6995 18.4508 7.7145 18.4825 ;
			RECT 7.7835 18.4508 7.7985 18.4825 ;
			RECT 7.8675 18.4508 7.8825 18.4825 ;
			RECT 7.9282 18.4508 7.9431 18.4825 ;
		END

		PORT
			 LAYER M4 ;
			RECT 0.2105 19.1921 8.463 19.2397 ;
			 LAYER V3 ;
			RECT 0.4387 19.2 0.4536 19.2317 ;
			RECT 1.3034 19.2 1.3183 19.2317 ;
			RECT 2.3968 19.2 2.4117 19.2317 ;
			RECT 2.5685 19.2 2.5835 19.2317 ;
			RECT 2.8411 19.2 2.856 19.2317 ;
			RECT 3.2704 19.2 3.2853 19.2317 ;
			RECT 3.6209 19.2 3.6358 19.2317 ;
			RECT 4.6293 19.2 4.6443 19.2317 ;
			RECT 5.306 19.2 5.3209 19.2317 ;
			RECT 5.5155 19.2 5.5305 19.2317 ;
			RECT 5.6835 19.2 5.6985 19.2317 ;
			RECT 6.1875 19.2 6.2025 19.2317 ;
			RECT 6.3555 19.2 6.3705 19.2317 ;
			RECT 6.65 19.2 6.6649 19.2317 ;
			RECT 6.7331 19.2 6.748 19.2317 ;
			RECT 6.986 19.2 7.0009 19.2317 ;
			RECT 7.0691 19.2 7.084 19.2317 ;
			RECT 7.322 19.2 7.3369 19.2317 ;
			RECT 7.4051 19.2 7.42 19.2317 ;
			RECT 7.658 19.2 7.6729 19.2317 ;
			RECT 7.7411 19.2 7.756 19.2317 ;
			RECT 7.917 19.2095 7.9543 19.2222 ;
		END

		PORT
			 LAYER M4 ;
			RECT 0.2105 19.7254 8.463 19.773 ;
			 LAYER V3 ;
			RECT 0.4387 19.7333 0.4536 19.7651 ;
			RECT 2.3968 19.7333 2.4117 19.7651 ;
			RECT 2.8411 19.7333 2.856 19.7651 ;
			RECT 4.6181 19.7429 4.6555 19.7556 ;
			RECT 4.9765 19.7333 4.9915 19.7651 ;
			RECT 5.0745 19.7333 5.0895 19.7651 ;
			RECT 5.5155 19.7333 5.5305 19.7651 ;
			RECT 5.6835 19.7333 5.6985 19.7651 ;
			RECT 5.81 19.7333 5.8249 19.7651 ;
			RECT 6.3555 19.7333 6.3705 19.7651 ;
			RECT 6.65 19.7333 6.6649 19.7651 ;
			RECT 6.7331 19.7333 6.748 19.7651 ;
			RECT 6.986 19.7333 7.0009 19.7651 ;
			RECT 7.0691 19.7333 7.084 19.7651 ;
			RECT 7.322 19.7333 7.3369 19.7651 ;
			RECT 7.4051 19.7333 7.42 19.7651 ;
			RECT 7.658 19.7333 7.6729 19.7651 ;
			RECT 7.7411 19.7333 7.756 19.7651 ;
			RECT 7.917 19.7429 7.9543 19.7556 ;
		END

		PORT
			 LAYER M4 ;
			RECT 0.2105 20.2587 8.463 20.3063 ;
			 LAYER V3 ;
			RECT 0.4387 20.2667 0.4536 20.2984 ;
			RECT 2.3968 20.2667 2.4117 20.2984 ;
			RECT 2.8411 20.2667 2.856 20.2984 ;
			RECT 4.6181 20.2762 4.6555 20.2889 ;
			RECT 5.5155 20.2667 5.5305 20.2984 ;
			RECT 6.2207 20.2667 6.2356 20.2984 ;
			RECT 6.65 20.2667 6.6649 20.2984 ;
			RECT 6.986 20.2667 7.0009 20.2984 ;
			RECT 7.322 20.2667 7.3369 20.2984 ;
			RECT 7.658 20.2667 7.6729 20.2984 ;
			RECT 7.917 20.2762 7.9543 20.2889 ;
		END

		PORT
			 LAYER M4 ;
			RECT 0.2105 20.7921 8.463 20.8397 ;
			 LAYER V3 ;
			RECT 0.4387 20.8 0.4536 20.8317 ;
			RECT 2.3968 20.8 2.4117 20.8317 ;
			RECT 2.8411 20.8 2.856 20.8317 ;
			RECT 4.6181 20.8095 4.6555 20.8222 ;
			RECT 5.5155 20.8 5.5305 20.8317 ;
			RECT 6.6495 20.8 6.6645 20.8317 ;
			RECT 6.9855 20.8 7.0005 20.8317 ;
			RECT 7.3215 20.8 7.3365 20.8317 ;
			RECT 7.6575 20.8 7.6725 20.8317 ;
			RECT 7.9287 20.8 7.9436 20.8317 ;
		END

		PORT
			 LAYER M4 ;
			RECT 0.2105 21.8587 8.463 21.9063 ;
			 LAYER V3 ;
			RECT 0.4387 21.8667 0.4536 21.8984 ;
			RECT 1.4355 21.8762 1.4504 21.8889 ;
			RECT 2.3968 21.8667 2.4117 21.8984 ;
			RECT 2.8411 21.8667 2.856 21.8984 ;
			RECT 4.6181 21.8762 4.6555 21.8889 ;
			RECT 5.9365 21.8667 5.9514 21.8984 ;
			RECT 6.6495 21.8667 6.6645 21.8984 ;
			RECT 6.9855 21.8667 7.0005 21.8984 ;
			RECT 7.3215 21.8667 7.3365 21.8984 ;
			RECT 7.6575 21.8667 7.6725 21.8984 ;
			RECT 7.917 21.8762 7.9543 21.8889 ;
		END

		PORT
			 LAYER M4 ;
			RECT 0.2105 22.9254 8.463 22.973 ;
			 LAYER V3 ;
			RECT 0.4387 22.9333 0.4536 22.9651 ;
			RECT 2.3968 22.9333 2.4117 22.9651 ;
			RECT 2.8411 22.9333 2.856 22.9651 ;
			RECT 4.6181 22.9429 4.6555 22.9556 ;
			RECT 5.5155 22.9333 5.5305 22.9651 ;
			RECT 5.8515 22.9333 5.8665 22.9651 ;
			RECT 5.9365 22.9333 5.9514 22.9651 ;
			RECT 6.1875 22.9333 6.2025 22.9651 ;
			RECT 6.5669 22.9333 6.5819 22.9651 ;
			RECT 6.65 22.9333 6.6649 22.9651 ;
			RECT 6.9029 22.9333 6.9179 22.9651 ;
			RECT 6.986 22.9333 7.0009 22.9651 ;
			RECT 7.2389 22.9333 7.2539 22.9651 ;
			RECT 7.322 22.9333 7.3369 22.9651 ;
			RECT 7.5749 22.9333 7.5899 22.9651 ;
			RECT 7.658 22.9333 7.6729 22.9651 ;
			RECT 7.917 22.9429 7.9543 22.9556 ;
		END

		PORT
			 LAYER M4 ;
			RECT 0.2105 23.4587 8.463 23.5063 ;
			 LAYER V3 ;
			RECT 0.4387 23.4667 0.4536 23.4984 ;
			RECT 2.3968 23.4667 2.4117 23.4984 ;
			RECT 2.8411 23.4667 2.856 23.4984 ;
			RECT 4.6181 23.4762 4.6555 23.4889 ;
			RECT 4.9112 23.4667 4.9261 23.4984 ;
			RECT 5.0092 23.4667 5.0241 23.4984 ;
			RECT 5.5155 23.4667 5.5305 23.4984 ;
			RECT 5.6835 23.4667 5.6985 23.4984 ;
			RECT 5.8515 23.4667 5.8665 23.4984 ;
			RECT 6.1875 23.4667 6.2025 23.4984 ;
			RECT 6.3555 23.4667 6.3705 23.4984 ;
			RECT 6.65 23.4667 6.6649 23.4984 ;
			RECT 6.7331 23.4667 6.748 23.4984 ;
			RECT 6.986 23.4667 7.0009 23.4984 ;
			RECT 7.0691 23.4667 7.084 23.4984 ;
			RECT 7.322 23.4667 7.3369 23.4984 ;
			RECT 7.4051 23.4667 7.42 23.4984 ;
			RECT 7.658 23.4667 7.6729 23.4984 ;
			RECT 7.7411 23.4667 7.756 23.4984 ;
			RECT 7.917 23.4766 7.9543 23.4893 ;
		END

		PORT
			 LAYER M4 ;
			RECT 0.2105 23.9921 8.463 24.0397 ;
			 LAYER V3 ;
			RECT 0.4387 24 0.4536 24.0317 ;
			RECT 2.3968 24 2.4117 24.0317 ;
			RECT 2.8411 24 2.856 24.0317 ;
			RECT 3.6209 24 3.6358 24.0317 ;
			RECT 4.6293 24 4.6443 24.0317 ;
			RECT 5.5155 24 5.5305 24.0317 ;
			RECT 5.6835 24 5.6985 24.0317 ;
			RECT 5.8515 24 5.8665 24.0317 ;
			RECT 6.1875 24 6.2025 24.0317 ;
			RECT 6.3555 24 6.3705 24.0317 ;
			RECT 6.65 24 6.6649 24.0317 ;
			RECT 6.7331 24 6.748 24.0317 ;
			RECT 6.986 24 7.0009 24.0317 ;
			RECT 7.0691 24 7.084 24.0317 ;
			RECT 7.322 24 7.3369 24.0317 ;
			RECT 7.4051 24 7.42 24.0317 ;
			RECT 7.658 24 7.6729 24.0317 ;
			RECT 7.7411 24 7.756 24.0317 ;
			RECT 7.917 24.0095 7.9543 24.0222 ;
		END

		PORT
			 LAYER M4 ;
			RECT 0.2105 24.5254 8.463 24.573 ;
			 LAYER V3 ;
			RECT 0.4387 24.5333 0.4536 24.5651 ;
			RECT 1.3034 24.5333 1.3183 24.5651 ;
			RECT 2.3968 24.5333 2.4117 24.5651 ;
			RECT 2.8411 24.5333 2.856 24.5651 ;
			RECT 4.6293 24.5333 4.6443 24.5651 ;
			RECT 5.5155 24.5333 5.5305 24.5651 ;
			RECT 5.6835 24.5333 5.6985 24.5651 ;
			RECT 5.8515 24.5333 5.8665 24.5651 ;
			RECT 6.3555 24.5333 6.3705 24.5651 ;
			RECT 7.9282 24.5333 7.9431 24.5651 ;
		END

		PORT
			 LAYER M4 ;
			RECT 0.2105 24.9 8.463 24.9476 ;
			 LAYER V3 ;
			RECT 0.4387 24.9079 0.4536 24.9397 ;
			RECT 2.3968 24.9079 2.4117 24.9397 ;
			RECT 4.6335 24.9079 4.6485 24.9397 ;
			RECT 5.18 24.9079 5.1949 24.9397 ;
			RECT 5.2635 24.9079 5.2785 24.9397 ;
			RECT 5.3475 24.9079 5.3625 24.9397 ;
			RECT 5.4315 24.9079 5.4465 24.9397 ;
			RECT 5.5155 24.9079 5.5305 24.9397 ;
			RECT 5.6 24.9079 5.6149 24.9397 ;
			RECT 5.6835 24.9079 5.6985 24.9397 ;
			RECT 5.7675 24.9079 5.7825 24.9397 ;
			RECT 5.8515 24.9079 5.8665 24.9397 ;
			RECT 5.9355 24.9079 5.9505 24.9397 ;
			RECT 6.0195 24.9079 6.0345 24.9397 ;
			RECT 6.1035 24.9079 6.1185 24.9397 ;
			RECT 6.1875 24.9079 6.2025 24.9397 ;
			RECT 6.2715 24.9079 6.2865 24.9397 ;
			RECT 6.3555 24.9079 6.3705 24.9397 ;
			RECT 6.4395 24.9079 6.4545 24.9397 ;
			RECT 6.5235 24.9079 6.5385 24.9397 ;
			RECT 6.6075 24.9079 6.6225 24.9397 ;
			RECT 6.6915 24.9079 6.7065 24.9397 ;
			RECT 6.7755 24.9079 6.7905 24.9397 ;
			RECT 6.8595 24.9079 6.8745 24.9397 ;
			RECT 6.9435 24.9079 6.9585 24.9397 ;
			RECT 7.0275 24.9079 7.0425 24.9397 ;
			RECT 7.1115 24.9079 7.1265 24.9397 ;
			RECT 7.1955 24.9079 7.2105 24.9397 ;
			RECT 7.2795 24.9079 7.2945 24.9397 ;
			RECT 7.3635 24.9079 7.3785 24.9397 ;
			RECT 7.4475 24.9079 7.4625 24.9397 ;
			RECT 7.5315 24.9079 7.5465 24.9397 ;
			RECT 7.6155 24.9079 7.6305 24.9397 ;
			RECT 7.6995 24.9079 7.7145 24.9397 ;
			RECT 7.7835 24.9079 7.7985 24.9397 ;
			RECT 7.8675 24.9079 7.8825 24.9397 ;
			RECT 7.9282 24.9079 7.9431 24.9397 ;
		END

		PORT
			 LAYER M4 ;
			RECT 0.2105 43.6889 8.463 43.7365 ;
			 LAYER V3 ;
			RECT 2.3968 43.6968 2.4117 43.7286 ;
			RECT 4.6256 43.6968 4.6405 43.7286 ;
			RECT 4.921 43.6968 4.9359 43.7286 ;
			RECT 5.1795 43.6968 5.1945 43.7286 ;
			RECT 5.2635 43.6968 5.2785 43.7286 ;
			RECT 5.3475 43.6968 5.3625 43.7286 ;
			RECT 5.4315 43.6968 5.4465 43.7286 ;
			RECT 5.5155 43.6968 5.5305 43.7286 ;
			RECT 5.5995 43.6968 5.6145 43.7286 ;
			RECT 5.6835 43.6968 5.6985 43.7286 ;
			RECT 5.7675 43.6968 5.7825 43.7286 ;
			RECT 5.8515 43.6968 5.8665 43.7286 ;
			RECT 5.9355 43.6968 5.9505 43.7286 ;
			RECT 6.0195 43.6968 6.0345 43.7286 ;
			RECT 6.1035 43.6968 6.1185 43.7286 ;
			RECT 6.1875 43.6968 6.2025 43.7286 ;
			RECT 6.2715 43.6968 6.2865 43.7286 ;
			RECT 6.3555 43.6968 6.3705 43.7286 ;
			RECT 6.4395 43.6968 6.4545 43.7286 ;
			RECT 6.5235 43.6968 6.5385 43.7286 ;
			RECT 6.6075 43.6968 6.6225 43.7286 ;
			RECT 6.6915 43.6968 6.7065 43.7286 ;
			RECT 6.7755 43.6968 6.7905 43.7286 ;
			RECT 6.8595 43.6968 6.8745 43.7286 ;
			RECT 6.9435 43.6968 6.9585 43.7286 ;
			RECT 7.0275 43.6968 7.0425 43.7286 ;
			RECT 7.1115 43.6968 7.1265 43.7286 ;
			RECT 7.1955 43.6968 7.2105 43.7286 ;
			RECT 7.2795 43.6968 7.2945 43.7286 ;
			RECT 7.3635 43.6968 7.3785 43.7286 ;
			RECT 7.4475 43.6968 7.4625 43.7286 ;
			RECT 7.5315 43.6968 7.5465 43.7286 ;
			RECT 7.6155 43.6968 7.6305 43.7286 ;
			RECT 7.6995 43.6968 7.7145 43.7286 ;
			RECT 7.7835 43.6968 7.7985 43.7286 ;
			RECT 7.8675 43.6968 7.8825 43.7286 ;
			RECT 8.1261 43.6968 8.141 43.7286 ;
		END

		PORT
			 LAYER M4 ;
			RECT 0.2105 27.6889 8.463 27.7365 ;
			 LAYER V3 ;
			RECT 2.3968 27.6968 2.4117 27.7286 ;
			RECT 4.6256 27.6968 4.6405 27.7286 ;
			RECT 4.921 27.6968 4.9359 27.7286 ;
			RECT 5.1795 27.6968 5.1945 27.7286 ;
			RECT 5.2635 27.6968 5.2785 27.7286 ;
			RECT 5.3475 27.6968 5.3625 27.7286 ;
			RECT 5.4315 27.6968 5.4465 27.7286 ;
			RECT 5.5155 27.6968 5.5305 27.7286 ;
			RECT 5.5995 27.6968 5.6145 27.7286 ;
			RECT 5.6835 27.6968 5.6985 27.7286 ;
			RECT 5.7675 27.6968 5.7825 27.7286 ;
			RECT 5.8515 27.6968 5.8665 27.7286 ;
			RECT 5.9355 27.6968 5.9505 27.7286 ;
			RECT 6.0195 27.6968 6.0345 27.7286 ;
			RECT 6.1035 27.6968 6.1185 27.7286 ;
			RECT 6.1875 27.6968 6.2025 27.7286 ;
			RECT 6.2715 27.6968 6.2865 27.7286 ;
			RECT 6.3555 27.6968 6.3705 27.7286 ;
			RECT 6.4395 27.6968 6.4545 27.7286 ;
			RECT 6.5235 27.6968 6.5385 27.7286 ;
			RECT 6.6075 27.6968 6.6225 27.7286 ;
			RECT 6.6915 27.6968 6.7065 27.7286 ;
			RECT 6.7755 27.6968 6.7905 27.7286 ;
			RECT 6.8595 27.6968 6.8745 27.7286 ;
			RECT 6.9435 27.6968 6.9585 27.7286 ;
			RECT 7.0275 27.6968 7.0425 27.7286 ;
			RECT 7.1115 27.6968 7.1265 27.7286 ;
			RECT 7.1955 27.6968 7.2105 27.7286 ;
			RECT 7.2795 27.6968 7.2945 27.7286 ;
			RECT 7.3635 27.6968 7.3785 27.7286 ;
			RECT 7.4475 27.6968 7.4625 27.7286 ;
			RECT 7.5315 27.6968 7.5465 27.7286 ;
			RECT 7.6155 27.6968 7.6305 27.7286 ;
			RECT 7.6995 27.6968 7.7145 27.7286 ;
			RECT 7.7835 27.6968 7.7985 27.7286 ;
			RECT 7.8675 27.6968 7.8825 27.7286 ;
			RECT 8.1261 27.6968 8.141 27.7286 ;
		END

		PORT
			 LAYER M4 ;
			RECT 0.2105 26.8889 8.463 26.9365 ;
			 LAYER V3 ;
			RECT 2.3968 26.8968 2.4117 26.9286 ;
			RECT 4.6256 26.8968 4.6405 26.9286 ;
			RECT 4.921 26.8968 4.9359 26.9286 ;
			RECT 5.1795 26.8968 5.1945 26.9286 ;
			RECT 5.2635 26.8968 5.2785 26.9286 ;
			RECT 5.3475 26.8968 5.3625 26.9286 ;
			RECT 5.4315 26.8968 5.4465 26.9286 ;
			RECT 5.5155 26.8968 5.5305 26.9286 ;
			RECT 5.5995 26.8968 5.6145 26.9286 ;
			RECT 5.6835 26.8968 5.6985 26.9286 ;
			RECT 5.7675 26.8968 5.7825 26.9286 ;
			RECT 5.8515 26.8968 5.8665 26.9286 ;
			RECT 5.9355 26.8968 5.9505 26.9286 ;
			RECT 6.0195 26.8968 6.0345 26.9286 ;
			RECT 6.1035 26.8968 6.1185 26.9286 ;
			RECT 6.1875 26.8968 6.2025 26.9286 ;
			RECT 6.2715 26.8968 6.2865 26.9286 ;
			RECT 6.3555 26.8968 6.3705 26.9286 ;
			RECT 6.4395 26.8968 6.4545 26.9286 ;
			RECT 6.5235 26.8968 6.5385 26.9286 ;
			RECT 6.6075 26.8968 6.6225 26.9286 ;
			RECT 6.6915 26.8968 6.7065 26.9286 ;
			RECT 6.7755 26.8968 6.7905 26.9286 ;
			RECT 6.8595 26.8968 6.8745 26.9286 ;
			RECT 6.9435 26.8968 6.9585 26.9286 ;
			RECT 7.0275 26.8968 7.0425 26.9286 ;
			RECT 7.1115 26.8968 7.1265 26.9286 ;
			RECT 7.1955 26.8968 7.2105 26.9286 ;
			RECT 7.2795 26.8968 7.2945 26.9286 ;
			RECT 7.3635 26.8968 7.3785 26.9286 ;
			RECT 7.4475 26.8968 7.4625 26.9286 ;
			RECT 7.5315 26.8968 7.5465 26.9286 ;
			RECT 7.6155 26.8968 7.6305 26.9286 ;
			RECT 7.6995 26.8968 7.7145 26.9286 ;
			RECT 7.7835 26.8968 7.7985 26.9286 ;
			RECT 7.8675 26.8968 7.8825 26.9286 ;
			RECT 8.1261 26.8968 8.141 26.9286 ;
		END

		PORT
			 LAYER M4 ;
			RECT 0.2105 26.0889 8.463 26.1365 ;
			 LAYER V3 ;
			RECT 2.3968 26.0968 2.4117 26.1286 ;
			RECT 4.6256 26.0968 4.6405 26.1286 ;
			RECT 4.921 26.0968 4.9359 26.1286 ;
			RECT 5.1795 26.0968 5.1945 26.1286 ;
			RECT 5.2635 26.0968 5.2785 26.1286 ;
			RECT 5.3475 26.0968 5.3625 26.1286 ;
			RECT 5.4315 26.0968 5.4465 26.1286 ;
			RECT 5.5155 26.0968 5.5305 26.1286 ;
			RECT 5.5995 26.0968 5.6145 26.1286 ;
			RECT 5.6835 26.0968 5.6985 26.1286 ;
			RECT 5.7675 26.0968 5.7825 26.1286 ;
			RECT 5.8515 26.0968 5.8665 26.1286 ;
			RECT 5.9355 26.0968 5.9505 26.1286 ;
			RECT 6.0195 26.0968 6.0345 26.1286 ;
			RECT 6.1035 26.0968 6.1185 26.1286 ;
			RECT 6.1875 26.0968 6.2025 26.1286 ;
			RECT 6.2715 26.0968 6.2865 26.1286 ;
			RECT 6.3555 26.0968 6.3705 26.1286 ;
			RECT 6.4395 26.0968 6.4545 26.1286 ;
			RECT 6.5235 26.0968 6.5385 26.1286 ;
			RECT 6.6075 26.0968 6.6225 26.1286 ;
			RECT 6.6915 26.0968 6.7065 26.1286 ;
			RECT 6.7755 26.0968 6.7905 26.1286 ;
			RECT 6.8595 26.0968 6.8745 26.1286 ;
			RECT 6.9435 26.0968 6.9585 26.1286 ;
			RECT 7.0275 26.0968 7.0425 26.1286 ;
			RECT 7.1115 26.0968 7.1265 26.1286 ;
			RECT 7.1955 26.0968 7.2105 26.1286 ;
			RECT 7.2795 26.0968 7.2945 26.1286 ;
			RECT 7.3635 26.0968 7.3785 26.1286 ;
			RECT 7.4475 26.0968 7.4625 26.1286 ;
			RECT 7.5315 26.0968 7.5465 26.1286 ;
			RECT 7.6155 26.0968 7.6305 26.1286 ;
			RECT 7.6995 26.0968 7.7145 26.1286 ;
			RECT 7.7835 26.0968 7.7985 26.1286 ;
			RECT 7.8675 26.0968 7.8825 26.1286 ;
			RECT 8.1261 26.0968 8.141 26.1286 ;
		END

		PORT
			 LAYER M4 ;
			RECT 0.2105 42.0889 8.463 42.1365 ;
			 LAYER V3 ;
			RECT 2.3968 42.0968 2.4117 42.1286 ;
			RECT 4.6256 42.0968 4.6405 42.1286 ;
			RECT 4.921 42.0968 4.9359 42.1286 ;
			RECT 5.1795 42.0968 5.1945 42.1286 ;
			RECT 5.2635 42.0968 5.2785 42.1286 ;
			RECT 5.3475 42.0968 5.3625 42.1286 ;
			RECT 5.4315 42.0968 5.4465 42.1286 ;
			RECT 5.5155 42.0968 5.5305 42.1286 ;
			RECT 5.5995 42.0968 5.6145 42.1286 ;
			RECT 5.6835 42.0968 5.6985 42.1286 ;
			RECT 5.7675 42.0968 5.7825 42.1286 ;
			RECT 5.8515 42.0968 5.8665 42.1286 ;
			RECT 5.9355 42.0968 5.9505 42.1286 ;
			RECT 6.0195 42.0968 6.0345 42.1286 ;
			RECT 6.1035 42.0968 6.1185 42.1286 ;
			RECT 6.1875 42.0968 6.2025 42.1286 ;
			RECT 6.2715 42.0968 6.2865 42.1286 ;
			RECT 6.3555 42.0968 6.3705 42.1286 ;
			RECT 6.4395 42.0968 6.4545 42.1286 ;
			RECT 6.5235 42.0968 6.5385 42.1286 ;
			RECT 6.6075 42.0968 6.6225 42.1286 ;
			RECT 6.6915 42.0968 6.7065 42.1286 ;
			RECT 6.7755 42.0968 6.7905 42.1286 ;
			RECT 6.8595 42.0968 6.8745 42.1286 ;
			RECT 6.9435 42.0968 6.9585 42.1286 ;
			RECT 7.0275 42.0968 7.0425 42.1286 ;
			RECT 7.1115 42.0968 7.1265 42.1286 ;
			RECT 7.1955 42.0968 7.2105 42.1286 ;
			RECT 7.2795 42.0968 7.2945 42.1286 ;
			RECT 7.3635 42.0968 7.3785 42.1286 ;
			RECT 7.4475 42.0968 7.4625 42.1286 ;
			RECT 7.5315 42.0968 7.5465 42.1286 ;
			RECT 7.6155 42.0968 7.6305 42.1286 ;
			RECT 7.6995 42.0968 7.7145 42.1286 ;
			RECT 7.7835 42.0968 7.7985 42.1286 ;
			RECT 7.8675 42.0968 7.8825 42.1286 ;
			RECT 8.1261 42.0968 8.141 42.1286 ;
		END

		PORT
			 LAYER M4 ;
			RECT 0.2105 17.0444 8.463 17.0921 ;
			 LAYER V3 ;
			RECT 2.3968 17.0524 2.4117 17.0841 ;
			RECT 4.6256 17.0524 4.6405 17.0841 ;
			RECT 4.921 17.0524 4.9359 17.0841 ;
			RECT 5.1795 17.0524 5.1945 17.0841 ;
			RECT 5.2635 17.0524 5.2785 17.0841 ;
			RECT 5.3475 17.0524 5.3625 17.0841 ;
			RECT 5.4315 17.0524 5.4465 17.0841 ;
			RECT 5.5155 17.0524 5.5305 17.0841 ;
			RECT 5.5995 17.0524 5.6145 17.0841 ;
			RECT 5.6835 17.0524 5.6985 17.0841 ;
			RECT 5.7675 17.0524 5.7825 17.0841 ;
			RECT 5.8515 17.0524 5.8665 17.0841 ;
			RECT 5.9355 17.0524 5.9505 17.0841 ;
			RECT 6.0195 17.0524 6.0345 17.0841 ;
			RECT 6.1035 17.0524 6.1185 17.0841 ;
			RECT 6.1875 17.0524 6.2025 17.0841 ;
			RECT 6.2715 17.0524 6.2865 17.0841 ;
			RECT 6.3555 17.0524 6.3705 17.0841 ;
			RECT 6.4395 17.0524 6.4545 17.0841 ;
			RECT 6.5235 17.0524 6.5385 17.0841 ;
			RECT 6.6075 17.0524 6.6225 17.0841 ;
			RECT 6.6915 17.0524 6.7065 17.0841 ;
			RECT 6.7755 17.0524 6.7905 17.0841 ;
			RECT 6.8595 17.0524 6.8745 17.0841 ;
			RECT 6.9435 17.0524 6.9585 17.0841 ;
			RECT 7.0275 17.0524 7.0425 17.0841 ;
			RECT 7.1115 17.0524 7.1265 17.0841 ;
			RECT 7.1955 17.0524 7.2105 17.0841 ;
			RECT 7.2795 17.0524 7.2945 17.0841 ;
			RECT 7.3635 17.0524 7.3785 17.0841 ;
			RECT 7.4475 17.0524 7.4625 17.0841 ;
			RECT 7.5315 17.0524 7.5465 17.0841 ;
			RECT 7.6155 17.0524 7.6305 17.0841 ;
			RECT 7.6995 17.0524 7.7145 17.0841 ;
			RECT 7.7835 17.0524 7.7985 17.0841 ;
			RECT 7.8675 17.0524 7.8825 17.0841 ;
			RECT 8.1261 17.0524 8.141 17.0841 ;
		END

		PORT
			 LAYER M4 ;
			RECT 0.2105 16.2444 8.463 16.2921 ;
			 LAYER V3 ;
			RECT 2.3968 16.2524 2.4117 16.2841 ;
			RECT 4.6256 16.2524 4.6405 16.2841 ;
			RECT 4.921 16.2524 4.9359 16.2841 ;
			RECT 5.1795 16.2524 5.1945 16.2841 ;
			RECT 5.2635 16.2524 5.2785 16.2841 ;
			RECT 5.3475 16.2524 5.3625 16.2841 ;
			RECT 5.4315 16.2524 5.4465 16.2841 ;
			RECT 5.5155 16.2524 5.5305 16.2841 ;
			RECT 5.5995 16.2524 5.6145 16.2841 ;
			RECT 5.6835 16.2524 5.6985 16.2841 ;
			RECT 5.7675 16.2524 5.7825 16.2841 ;
			RECT 5.8515 16.2524 5.8665 16.2841 ;
			RECT 5.9355 16.2524 5.9505 16.2841 ;
			RECT 6.0195 16.2524 6.0345 16.2841 ;
			RECT 6.1035 16.2524 6.1185 16.2841 ;
			RECT 6.1875 16.2524 6.2025 16.2841 ;
			RECT 6.2715 16.2524 6.2865 16.2841 ;
			RECT 6.3555 16.2524 6.3705 16.2841 ;
			RECT 6.4395 16.2524 6.4545 16.2841 ;
			RECT 6.5235 16.2524 6.5385 16.2841 ;
			RECT 6.6075 16.2524 6.6225 16.2841 ;
			RECT 6.6915 16.2524 6.7065 16.2841 ;
			RECT 6.7755 16.2524 6.7905 16.2841 ;
			RECT 6.8595 16.2524 6.8745 16.2841 ;
			RECT 6.9435 16.2524 6.9585 16.2841 ;
			RECT 7.0275 16.2524 7.0425 16.2841 ;
			RECT 7.1115 16.2524 7.1265 16.2841 ;
			RECT 7.1955 16.2524 7.2105 16.2841 ;
			RECT 7.2795 16.2524 7.2945 16.2841 ;
			RECT 7.3635 16.2524 7.3785 16.2841 ;
			RECT 7.4475 16.2524 7.4625 16.2841 ;
			RECT 7.5315 16.2524 7.5465 16.2841 ;
			RECT 7.6155 16.2524 7.6305 16.2841 ;
			RECT 7.6995 16.2524 7.7145 16.2841 ;
			RECT 7.7835 16.2524 7.7985 16.2841 ;
			RECT 7.8675 16.2524 7.8825 16.2841 ;
			RECT 8.1261 16.2524 8.141 16.2841 ;
		END

		PORT
			 LAYER M4 ;
			RECT 0.2105 15.4444 8.463 15.4921 ;
			 LAYER V3 ;
			RECT 2.3968 15.4524 2.4117 15.4841 ;
			RECT 4.6256 15.4524 4.6405 15.4841 ;
			RECT 4.921 15.4524 4.9359 15.4841 ;
			RECT 5.1795 15.4524 5.1945 15.4841 ;
			RECT 5.2635 15.4524 5.2785 15.4841 ;
			RECT 5.3475 15.4524 5.3625 15.4841 ;
			RECT 5.4315 15.4524 5.4465 15.4841 ;
			RECT 5.5155 15.4524 5.5305 15.4841 ;
			RECT 5.5995 15.4524 5.6145 15.4841 ;
			RECT 5.6835 15.4524 5.6985 15.4841 ;
			RECT 5.7675 15.4524 5.7825 15.4841 ;
			RECT 5.8515 15.4524 5.8665 15.4841 ;
			RECT 5.9355 15.4524 5.9505 15.4841 ;
			RECT 6.0195 15.4524 6.0345 15.4841 ;
			RECT 6.1035 15.4524 6.1185 15.4841 ;
			RECT 6.1875 15.4524 6.2025 15.4841 ;
			RECT 6.2715 15.4524 6.2865 15.4841 ;
			RECT 6.3555 15.4524 6.3705 15.4841 ;
			RECT 6.4395 15.4524 6.4545 15.4841 ;
			RECT 6.5235 15.4524 6.5385 15.4841 ;
			RECT 6.6075 15.4524 6.6225 15.4841 ;
			RECT 6.6915 15.4524 6.7065 15.4841 ;
			RECT 6.7755 15.4524 6.7905 15.4841 ;
			RECT 6.8595 15.4524 6.8745 15.4841 ;
			RECT 6.9435 15.4524 6.9585 15.4841 ;
			RECT 7.0275 15.4524 7.0425 15.4841 ;
			RECT 7.1115 15.4524 7.1265 15.4841 ;
			RECT 7.1955 15.4524 7.2105 15.4841 ;
			RECT 7.2795 15.4524 7.2945 15.4841 ;
			RECT 7.3635 15.4524 7.3785 15.4841 ;
			RECT 7.4475 15.4524 7.4625 15.4841 ;
			RECT 7.5315 15.4524 7.5465 15.4841 ;
			RECT 7.6155 15.4524 7.6305 15.4841 ;
			RECT 7.6995 15.4524 7.7145 15.4841 ;
			RECT 7.7835 15.4524 7.7985 15.4841 ;
			RECT 7.8675 15.4524 7.8825 15.4841 ;
			RECT 8.1261 15.4524 8.141 15.4841 ;
		END

		PORT
			 LAYER M4 ;
			RECT 0.2105 14.6444 8.463 14.6921 ;
			 LAYER V3 ;
			RECT 2.3968 14.6524 2.4117 14.6841 ;
			RECT 4.6256 14.6524 4.6405 14.6841 ;
			RECT 4.921 14.6524 4.9359 14.6841 ;
			RECT 5.1795 14.6524 5.1945 14.6841 ;
			RECT 5.2635 14.6524 5.2785 14.6841 ;
			RECT 5.3475 14.6524 5.3625 14.6841 ;
			RECT 5.4315 14.6524 5.4465 14.6841 ;
			RECT 5.5155 14.6524 5.5305 14.6841 ;
			RECT 5.5995 14.6524 5.6145 14.6841 ;
			RECT 5.6835 14.6524 5.6985 14.6841 ;
			RECT 5.7675 14.6524 5.7825 14.6841 ;
			RECT 5.8515 14.6524 5.8665 14.6841 ;
			RECT 5.9355 14.6524 5.9505 14.6841 ;
			RECT 6.0195 14.6524 6.0345 14.6841 ;
			RECT 6.1035 14.6524 6.1185 14.6841 ;
			RECT 6.1875 14.6524 6.2025 14.6841 ;
			RECT 6.2715 14.6524 6.2865 14.6841 ;
			RECT 6.3555 14.6524 6.3705 14.6841 ;
			RECT 6.4395 14.6524 6.4545 14.6841 ;
			RECT 6.5235 14.6524 6.5385 14.6841 ;
			RECT 6.6075 14.6524 6.6225 14.6841 ;
			RECT 6.6915 14.6524 6.7065 14.6841 ;
			RECT 6.7755 14.6524 6.7905 14.6841 ;
			RECT 6.8595 14.6524 6.8745 14.6841 ;
			RECT 6.9435 14.6524 6.9585 14.6841 ;
			RECT 7.0275 14.6524 7.0425 14.6841 ;
			RECT 7.1115 14.6524 7.1265 14.6841 ;
			RECT 7.1955 14.6524 7.2105 14.6841 ;
			RECT 7.2795 14.6524 7.2945 14.6841 ;
			RECT 7.3635 14.6524 7.3785 14.6841 ;
			RECT 7.4475 14.6524 7.4625 14.6841 ;
			RECT 7.5315 14.6524 7.5465 14.6841 ;
			RECT 7.6155 14.6524 7.6305 14.6841 ;
			RECT 7.6995 14.6524 7.7145 14.6841 ;
			RECT 7.7835 14.6524 7.7985 14.6841 ;
			RECT 7.8675 14.6524 7.8825 14.6841 ;
			RECT 8.1261 14.6524 8.141 14.6841 ;
		END

		PORT
			 LAYER M4 ;
			RECT 0.2105 13.8444 8.463 13.8921 ;
			 LAYER V3 ;
			RECT 2.3968 13.8524 2.4117 13.8841 ;
			RECT 4.6256 13.8524 4.6405 13.8841 ;
			RECT 4.921 13.8524 4.9359 13.8841 ;
			RECT 5.1795 13.8524 5.1945 13.8841 ;
			RECT 5.2635 13.8524 5.2785 13.8841 ;
			RECT 5.3475 13.8524 5.3625 13.8841 ;
			RECT 5.4315 13.8524 5.4465 13.8841 ;
			RECT 5.5155 13.8524 5.5305 13.8841 ;
			RECT 5.5995 13.8524 5.6145 13.8841 ;
			RECT 5.6835 13.8524 5.6985 13.8841 ;
			RECT 5.7675 13.8524 5.7825 13.8841 ;
			RECT 5.8515 13.8524 5.8665 13.8841 ;
			RECT 5.9355 13.8524 5.9505 13.8841 ;
			RECT 6.0195 13.8524 6.0345 13.8841 ;
			RECT 6.1035 13.8524 6.1185 13.8841 ;
			RECT 6.1875 13.8524 6.2025 13.8841 ;
			RECT 6.2715 13.8524 6.2865 13.8841 ;
			RECT 6.3555 13.8524 6.3705 13.8841 ;
			RECT 6.4395 13.8524 6.4545 13.8841 ;
			RECT 6.5235 13.8524 6.5385 13.8841 ;
			RECT 6.6075 13.8524 6.6225 13.8841 ;
			RECT 6.6915 13.8524 6.7065 13.8841 ;
			RECT 6.7755 13.8524 6.7905 13.8841 ;
			RECT 6.8595 13.8524 6.8745 13.8841 ;
			RECT 6.9435 13.8524 6.9585 13.8841 ;
			RECT 7.0275 13.8524 7.0425 13.8841 ;
			RECT 7.1115 13.8524 7.1265 13.8841 ;
			RECT 7.1955 13.8524 7.2105 13.8841 ;
			RECT 7.2795 13.8524 7.2945 13.8841 ;
			RECT 7.3635 13.8524 7.3785 13.8841 ;
			RECT 7.4475 13.8524 7.4625 13.8841 ;
			RECT 7.5315 13.8524 7.5465 13.8841 ;
			RECT 7.6155 13.8524 7.6305 13.8841 ;
			RECT 7.6995 13.8524 7.7145 13.8841 ;
			RECT 7.7835 13.8524 7.7985 13.8841 ;
			RECT 7.8675 13.8524 7.8825 13.8841 ;
			RECT 8.1261 13.8524 8.141 13.8841 ;
		END

		PORT
			 LAYER M4 ;
			RECT 0.2105 41.2889 8.463 41.3365 ;
			 LAYER V3 ;
			RECT 2.3968 41.2968 2.4117 41.3286 ;
			RECT 4.6256 41.2968 4.6405 41.3286 ;
			RECT 4.921 41.2968 4.9359 41.3286 ;
			RECT 5.1795 41.2968 5.1945 41.3286 ;
			RECT 5.2635 41.2968 5.2785 41.3286 ;
			RECT 5.3475 41.2968 5.3625 41.3286 ;
			RECT 5.4315 41.2968 5.4465 41.3286 ;
			RECT 5.5155 41.2968 5.5305 41.3286 ;
			RECT 5.5995 41.2968 5.6145 41.3286 ;
			RECT 5.6835 41.2968 5.6985 41.3286 ;
			RECT 5.7675 41.2968 5.7825 41.3286 ;
			RECT 5.8515 41.2968 5.8665 41.3286 ;
			RECT 5.9355 41.2968 5.9505 41.3286 ;
			RECT 6.0195 41.2968 6.0345 41.3286 ;
			RECT 6.1035 41.2968 6.1185 41.3286 ;
			RECT 6.1875 41.2968 6.2025 41.3286 ;
			RECT 6.2715 41.2968 6.2865 41.3286 ;
			RECT 6.3555 41.2968 6.3705 41.3286 ;
			RECT 6.4395 41.2968 6.4545 41.3286 ;
			RECT 6.5235 41.2968 6.5385 41.3286 ;
			RECT 6.6075 41.2968 6.6225 41.3286 ;
			RECT 6.6915 41.2968 6.7065 41.3286 ;
			RECT 6.7755 41.2968 6.7905 41.3286 ;
			RECT 6.8595 41.2968 6.8745 41.3286 ;
			RECT 6.9435 41.2968 6.9585 41.3286 ;
			RECT 7.0275 41.2968 7.0425 41.3286 ;
			RECT 7.1115 41.2968 7.1265 41.3286 ;
			RECT 7.1955 41.2968 7.2105 41.3286 ;
			RECT 7.2795 41.2968 7.2945 41.3286 ;
			RECT 7.3635 41.2968 7.3785 41.3286 ;
			RECT 7.4475 41.2968 7.4625 41.3286 ;
			RECT 7.5315 41.2968 7.5465 41.3286 ;
			RECT 7.6155 41.2968 7.6305 41.3286 ;
			RECT 7.6995 41.2968 7.7145 41.3286 ;
			RECT 7.7835 41.2968 7.7985 41.3286 ;
			RECT 7.8675 41.2968 7.8825 41.3286 ;
			RECT 8.1261 41.2968 8.141 41.3286 ;
		END

		PORT
			 LAYER M4 ;
			RECT 0.2105 13.0444 8.463 13.0921 ;
			 LAYER V3 ;
			RECT 2.3968 13.0524 2.4117 13.0841 ;
			RECT 4.6256 13.0524 4.6405 13.0841 ;
			RECT 4.921 13.0524 4.9359 13.0841 ;
			RECT 5.1795 13.0524 5.1945 13.0841 ;
			RECT 5.2635 13.0524 5.2785 13.0841 ;
			RECT 5.3475 13.0524 5.3625 13.0841 ;
			RECT 5.4315 13.0524 5.4465 13.0841 ;
			RECT 5.5155 13.0524 5.5305 13.0841 ;
			RECT 5.5995 13.0524 5.6145 13.0841 ;
			RECT 5.6835 13.0524 5.6985 13.0841 ;
			RECT 5.7675 13.0524 5.7825 13.0841 ;
			RECT 5.8515 13.0524 5.8665 13.0841 ;
			RECT 5.9355 13.0524 5.9505 13.0841 ;
			RECT 6.0195 13.0524 6.0345 13.0841 ;
			RECT 6.1035 13.0524 6.1185 13.0841 ;
			RECT 6.1875 13.0524 6.2025 13.0841 ;
			RECT 6.2715 13.0524 6.2865 13.0841 ;
			RECT 6.3555 13.0524 6.3705 13.0841 ;
			RECT 6.4395 13.0524 6.4545 13.0841 ;
			RECT 6.5235 13.0524 6.5385 13.0841 ;
			RECT 6.6075 13.0524 6.6225 13.0841 ;
			RECT 6.6915 13.0524 6.7065 13.0841 ;
			RECT 6.7755 13.0524 6.7905 13.0841 ;
			RECT 6.8595 13.0524 6.8745 13.0841 ;
			RECT 6.9435 13.0524 6.9585 13.0841 ;
			RECT 7.0275 13.0524 7.0425 13.0841 ;
			RECT 7.1115 13.0524 7.1265 13.0841 ;
			RECT 7.1955 13.0524 7.2105 13.0841 ;
			RECT 7.2795 13.0524 7.2945 13.0841 ;
			RECT 7.3635 13.0524 7.3785 13.0841 ;
			RECT 7.4475 13.0524 7.4625 13.0841 ;
			RECT 7.5315 13.0524 7.5465 13.0841 ;
			RECT 7.6155 13.0524 7.6305 13.0841 ;
			RECT 7.6995 13.0524 7.7145 13.0841 ;
			RECT 7.7835 13.0524 7.7985 13.0841 ;
			RECT 7.8675 13.0524 7.8825 13.0841 ;
			RECT 8.1261 13.0524 8.141 13.0841 ;
		END

		PORT
			 LAYER M4 ;
			RECT 0.2105 12.2444 8.463 12.2921 ;
			 LAYER V3 ;
			RECT 2.3968 12.2524 2.4117 12.2841 ;
			RECT 4.6256 12.2524 4.6405 12.2841 ;
			RECT 4.921 12.2524 4.9359 12.2841 ;
			RECT 5.1795 12.2524 5.1945 12.2841 ;
			RECT 5.2635 12.2524 5.2785 12.2841 ;
			RECT 5.3475 12.2524 5.3625 12.2841 ;
			RECT 5.4315 12.2524 5.4465 12.2841 ;
			RECT 5.5155 12.2524 5.5305 12.2841 ;
			RECT 5.5995 12.2524 5.6145 12.2841 ;
			RECT 5.6835 12.2524 5.6985 12.2841 ;
			RECT 5.7675 12.2524 5.7825 12.2841 ;
			RECT 5.8515 12.2524 5.8665 12.2841 ;
			RECT 5.9355 12.2524 5.9505 12.2841 ;
			RECT 6.0195 12.2524 6.0345 12.2841 ;
			RECT 6.1035 12.2524 6.1185 12.2841 ;
			RECT 6.1875 12.2524 6.2025 12.2841 ;
			RECT 6.2715 12.2524 6.2865 12.2841 ;
			RECT 6.3555 12.2524 6.3705 12.2841 ;
			RECT 6.4395 12.2524 6.4545 12.2841 ;
			RECT 6.5235 12.2524 6.5385 12.2841 ;
			RECT 6.6075 12.2524 6.6225 12.2841 ;
			RECT 6.6915 12.2524 6.7065 12.2841 ;
			RECT 6.7755 12.2524 6.7905 12.2841 ;
			RECT 6.8595 12.2524 6.8745 12.2841 ;
			RECT 6.9435 12.2524 6.9585 12.2841 ;
			RECT 7.0275 12.2524 7.0425 12.2841 ;
			RECT 7.1115 12.2524 7.1265 12.2841 ;
			RECT 7.1955 12.2524 7.2105 12.2841 ;
			RECT 7.2795 12.2524 7.2945 12.2841 ;
			RECT 7.3635 12.2524 7.3785 12.2841 ;
			RECT 7.4475 12.2524 7.4625 12.2841 ;
			RECT 7.5315 12.2524 7.5465 12.2841 ;
			RECT 7.6155 12.2524 7.6305 12.2841 ;
			RECT 7.6995 12.2524 7.7145 12.2841 ;
			RECT 7.7835 12.2524 7.7985 12.2841 ;
			RECT 7.8675 12.2524 7.8825 12.2841 ;
			RECT 8.1261 12.2524 8.141 12.2841 ;
		END

		PORT
			 LAYER M4 ;
			RECT 0.2105 11.4444 8.463 11.4921 ;
			 LAYER V3 ;
			RECT 2.3968 11.4524 2.4117 11.4841 ;
			RECT 4.6256 11.4524 4.6405 11.4841 ;
			RECT 4.921 11.4524 4.9359 11.4841 ;
			RECT 5.1795 11.4524 5.1945 11.4841 ;
			RECT 5.2635 11.4524 5.2785 11.4841 ;
			RECT 5.3475 11.4524 5.3625 11.4841 ;
			RECT 5.4315 11.4524 5.4465 11.4841 ;
			RECT 5.5155 11.4524 5.5305 11.4841 ;
			RECT 5.5995 11.4524 5.6145 11.4841 ;
			RECT 5.6835 11.4524 5.6985 11.4841 ;
			RECT 5.7675 11.4524 5.7825 11.4841 ;
			RECT 5.8515 11.4524 5.8665 11.4841 ;
			RECT 5.9355 11.4524 5.9505 11.4841 ;
			RECT 6.0195 11.4524 6.0345 11.4841 ;
			RECT 6.1035 11.4524 6.1185 11.4841 ;
			RECT 6.1875 11.4524 6.2025 11.4841 ;
			RECT 6.2715 11.4524 6.2865 11.4841 ;
			RECT 6.3555 11.4524 6.3705 11.4841 ;
			RECT 6.4395 11.4524 6.4545 11.4841 ;
			RECT 6.5235 11.4524 6.5385 11.4841 ;
			RECT 6.6075 11.4524 6.6225 11.4841 ;
			RECT 6.6915 11.4524 6.7065 11.4841 ;
			RECT 6.7755 11.4524 6.7905 11.4841 ;
			RECT 6.8595 11.4524 6.8745 11.4841 ;
			RECT 6.9435 11.4524 6.9585 11.4841 ;
			RECT 7.0275 11.4524 7.0425 11.4841 ;
			RECT 7.1115 11.4524 7.1265 11.4841 ;
			RECT 7.1955 11.4524 7.2105 11.4841 ;
			RECT 7.2795 11.4524 7.2945 11.4841 ;
			RECT 7.3635 11.4524 7.3785 11.4841 ;
			RECT 7.4475 11.4524 7.4625 11.4841 ;
			RECT 7.5315 11.4524 7.5465 11.4841 ;
			RECT 7.6155 11.4524 7.6305 11.4841 ;
			RECT 7.6995 11.4524 7.7145 11.4841 ;
			RECT 7.7835 11.4524 7.7985 11.4841 ;
			RECT 7.8675 11.4524 7.8825 11.4841 ;
			RECT 8.1261 11.4524 8.141 11.4841 ;
		END

		PORT
			 LAYER M4 ;
			RECT 0.2105 10.6444 8.463 10.6921 ;
			 LAYER V3 ;
			RECT 2.3968 10.6524 2.4117 10.6841 ;
			RECT 4.6256 10.6524 4.6405 10.6841 ;
			RECT 4.921 10.6524 4.9359 10.6841 ;
			RECT 5.1795 10.6524 5.1945 10.6841 ;
			RECT 5.2635 10.6524 5.2785 10.6841 ;
			RECT 5.3475 10.6524 5.3625 10.6841 ;
			RECT 5.4315 10.6524 5.4465 10.6841 ;
			RECT 5.5155 10.6524 5.5305 10.6841 ;
			RECT 5.5995 10.6524 5.6145 10.6841 ;
			RECT 5.6835 10.6524 5.6985 10.6841 ;
			RECT 5.7675 10.6524 5.7825 10.6841 ;
			RECT 5.8515 10.6524 5.8665 10.6841 ;
			RECT 5.9355 10.6524 5.9505 10.6841 ;
			RECT 6.0195 10.6524 6.0345 10.6841 ;
			RECT 6.1035 10.6524 6.1185 10.6841 ;
			RECT 6.1875 10.6524 6.2025 10.6841 ;
			RECT 6.2715 10.6524 6.2865 10.6841 ;
			RECT 6.3555 10.6524 6.3705 10.6841 ;
			RECT 6.4395 10.6524 6.4545 10.6841 ;
			RECT 6.5235 10.6524 6.5385 10.6841 ;
			RECT 6.6075 10.6524 6.6225 10.6841 ;
			RECT 6.6915 10.6524 6.7065 10.6841 ;
			RECT 6.7755 10.6524 6.7905 10.6841 ;
			RECT 6.8595 10.6524 6.8745 10.6841 ;
			RECT 6.9435 10.6524 6.9585 10.6841 ;
			RECT 7.0275 10.6524 7.0425 10.6841 ;
			RECT 7.1115 10.6524 7.1265 10.6841 ;
			RECT 7.1955 10.6524 7.2105 10.6841 ;
			RECT 7.2795 10.6524 7.2945 10.6841 ;
			RECT 7.3635 10.6524 7.3785 10.6841 ;
			RECT 7.4475 10.6524 7.4625 10.6841 ;
			RECT 7.5315 10.6524 7.5465 10.6841 ;
			RECT 7.6155 10.6524 7.6305 10.6841 ;
			RECT 7.6995 10.6524 7.7145 10.6841 ;
			RECT 7.7835 10.6524 7.7985 10.6841 ;
			RECT 7.8675 10.6524 7.8825 10.6841 ;
			RECT 8.1261 10.6524 8.141 10.6841 ;
		END

		PORT
			 LAYER M4 ;
			RECT 0.2105 9.8444 8.463 9.8921 ;
			 LAYER V3 ;
			RECT 2.3968 9.8524 2.4117 9.8841 ;
			RECT 4.6256 9.8524 4.6405 9.8841 ;
			RECT 4.921 9.8524 4.9359 9.8841 ;
			RECT 5.1795 9.8524 5.1945 9.8841 ;
			RECT 5.2635 9.8524 5.2785 9.8841 ;
			RECT 5.3475 9.8524 5.3625 9.8841 ;
			RECT 5.4315 9.8524 5.4465 9.8841 ;
			RECT 5.5155 9.8524 5.5305 9.8841 ;
			RECT 5.5995 9.8524 5.6145 9.8841 ;
			RECT 5.6835 9.8524 5.6985 9.8841 ;
			RECT 5.7675 9.8524 5.7825 9.8841 ;
			RECT 5.8515 9.8524 5.8665 9.8841 ;
			RECT 5.9355 9.8524 5.9505 9.8841 ;
			RECT 6.0195 9.8524 6.0345 9.8841 ;
			RECT 6.1035 9.8524 6.1185 9.8841 ;
			RECT 6.1875 9.8524 6.2025 9.8841 ;
			RECT 6.2715 9.8524 6.2865 9.8841 ;
			RECT 6.3555 9.8524 6.3705 9.8841 ;
			RECT 6.4395 9.8524 6.4545 9.8841 ;
			RECT 6.5235 9.8524 6.5385 9.8841 ;
			RECT 6.6075 9.8524 6.6225 9.8841 ;
			RECT 6.6915 9.8524 6.7065 9.8841 ;
			RECT 6.7755 9.8524 6.7905 9.8841 ;
			RECT 6.8595 9.8524 6.8745 9.8841 ;
			RECT 6.9435 9.8524 6.9585 9.8841 ;
			RECT 7.0275 9.8524 7.0425 9.8841 ;
			RECT 7.1115 9.8524 7.1265 9.8841 ;
			RECT 7.1955 9.8524 7.2105 9.8841 ;
			RECT 7.2795 9.8524 7.2945 9.8841 ;
			RECT 7.3635 9.8524 7.3785 9.8841 ;
			RECT 7.4475 9.8524 7.4625 9.8841 ;
			RECT 7.5315 9.8524 7.5465 9.8841 ;
			RECT 7.6155 9.8524 7.6305 9.8841 ;
			RECT 7.6995 9.8524 7.7145 9.8841 ;
			RECT 7.7835 9.8524 7.7985 9.8841 ;
			RECT 7.8675 9.8524 7.8825 9.8841 ;
			RECT 8.1261 9.8524 8.141 9.8841 ;
		END

		PORT
			 LAYER M4 ;
			RECT 0.2105 9.0444 8.463 9.0921 ;
			 LAYER V3 ;
			RECT 2.3968 9.0524 2.4117 9.0841 ;
			RECT 4.6256 9.0524 4.6405 9.0841 ;
			RECT 4.921 9.0524 4.9359 9.0841 ;
			RECT 5.1795 9.0524 5.1945 9.0841 ;
			RECT 5.2635 9.0524 5.2785 9.0841 ;
			RECT 5.3475 9.0524 5.3625 9.0841 ;
			RECT 5.4315 9.0524 5.4465 9.0841 ;
			RECT 5.5155 9.0524 5.5305 9.0841 ;
			RECT 5.5995 9.0524 5.6145 9.0841 ;
			RECT 5.6835 9.0524 5.6985 9.0841 ;
			RECT 5.7675 9.0524 5.7825 9.0841 ;
			RECT 5.8515 9.0524 5.8665 9.0841 ;
			RECT 5.9355 9.0524 5.9505 9.0841 ;
			RECT 6.0195 9.0524 6.0345 9.0841 ;
			RECT 6.1035 9.0524 6.1185 9.0841 ;
			RECT 6.1875 9.0524 6.2025 9.0841 ;
			RECT 6.2715 9.0524 6.2865 9.0841 ;
			RECT 6.3555 9.0524 6.3705 9.0841 ;
			RECT 6.4395 9.0524 6.4545 9.0841 ;
			RECT 6.5235 9.0524 6.5385 9.0841 ;
			RECT 6.6075 9.0524 6.6225 9.0841 ;
			RECT 6.6915 9.0524 6.7065 9.0841 ;
			RECT 6.7755 9.0524 6.7905 9.0841 ;
			RECT 6.8595 9.0524 6.8745 9.0841 ;
			RECT 6.9435 9.0524 6.9585 9.0841 ;
			RECT 7.0275 9.0524 7.0425 9.0841 ;
			RECT 7.1115 9.0524 7.1265 9.0841 ;
			RECT 7.1955 9.0524 7.2105 9.0841 ;
			RECT 7.2795 9.0524 7.2945 9.0841 ;
			RECT 7.3635 9.0524 7.3785 9.0841 ;
			RECT 7.4475 9.0524 7.4625 9.0841 ;
			RECT 7.5315 9.0524 7.5465 9.0841 ;
			RECT 7.6155 9.0524 7.6305 9.0841 ;
			RECT 7.6995 9.0524 7.7145 9.0841 ;
			RECT 7.7835 9.0524 7.7985 9.0841 ;
			RECT 7.8675 9.0524 7.8825 9.0841 ;
			RECT 8.1261 9.0524 8.141 9.0841 ;
		END

		PORT
			 LAYER M4 ;
			RECT 0.2105 8.2444 8.463 8.2921 ;
			 LAYER V3 ;
			RECT 2.3968 8.2524 2.4117 8.2841 ;
			RECT 4.6256 8.2524 4.6405 8.2841 ;
			RECT 4.921 8.2524 4.9359 8.2841 ;
			RECT 5.1795 8.2524 5.1945 8.2841 ;
			RECT 5.2635 8.2524 5.2785 8.2841 ;
			RECT 5.3475 8.2524 5.3625 8.2841 ;
			RECT 5.4315 8.2524 5.4465 8.2841 ;
			RECT 5.5155 8.2524 5.5305 8.2841 ;
			RECT 5.5995 8.2524 5.6145 8.2841 ;
			RECT 5.6835 8.2524 5.6985 8.2841 ;
			RECT 5.7675 8.2524 5.7825 8.2841 ;
			RECT 5.8515 8.2524 5.8665 8.2841 ;
			RECT 5.9355 8.2524 5.9505 8.2841 ;
			RECT 6.0195 8.2524 6.0345 8.2841 ;
			RECT 6.1035 8.2524 6.1185 8.2841 ;
			RECT 6.1875 8.2524 6.2025 8.2841 ;
			RECT 6.2715 8.2524 6.2865 8.2841 ;
			RECT 6.3555 8.2524 6.3705 8.2841 ;
			RECT 6.4395 8.2524 6.4545 8.2841 ;
			RECT 6.5235 8.2524 6.5385 8.2841 ;
			RECT 6.6075 8.2524 6.6225 8.2841 ;
			RECT 6.6915 8.2524 6.7065 8.2841 ;
			RECT 6.7755 8.2524 6.7905 8.2841 ;
			RECT 6.8595 8.2524 6.8745 8.2841 ;
			RECT 6.9435 8.2524 6.9585 8.2841 ;
			RECT 7.0275 8.2524 7.0425 8.2841 ;
			RECT 7.1115 8.2524 7.1265 8.2841 ;
			RECT 7.1955 8.2524 7.2105 8.2841 ;
			RECT 7.2795 8.2524 7.2945 8.2841 ;
			RECT 7.3635 8.2524 7.3785 8.2841 ;
			RECT 7.4475 8.2524 7.4625 8.2841 ;
			RECT 7.5315 8.2524 7.5465 8.2841 ;
			RECT 7.6155 8.2524 7.6305 8.2841 ;
			RECT 7.6995 8.2524 7.7145 8.2841 ;
			RECT 7.7835 8.2524 7.7985 8.2841 ;
			RECT 7.8675 8.2524 7.8825 8.2841 ;
			RECT 8.1261 8.2524 8.141 8.2841 ;
		END

		PORT
			 LAYER M4 ;
			RECT 0.2105 7.4444 8.463 7.4921 ;
			 LAYER V3 ;
			RECT 2.3968 7.4524 2.4117 7.4841 ;
			RECT 4.6256 7.4524 4.6405 7.4841 ;
			RECT 4.921 7.4524 4.9359 7.4841 ;
			RECT 5.1795 7.4524 5.1945 7.4841 ;
			RECT 5.2635 7.4524 5.2785 7.4841 ;
			RECT 5.3475 7.4524 5.3625 7.4841 ;
			RECT 5.4315 7.4524 5.4465 7.4841 ;
			RECT 5.5155 7.4524 5.5305 7.4841 ;
			RECT 5.5995 7.4524 5.6145 7.4841 ;
			RECT 5.6835 7.4524 5.6985 7.4841 ;
			RECT 5.7675 7.4524 5.7825 7.4841 ;
			RECT 5.8515 7.4524 5.8665 7.4841 ;
			RECT 5.9355 7.4524 5.9505 7.4841 ;
			RECT 6.0195 7.4524 6.0345 7.4841 ;
			RECT 6.1035 7.4524 6.1185 7.4841 ;
			RECT 6.1875 7.4524 6.2025 7.4841 ;
			RECT 6.2715 7.4524 6.2865 7.4841 ;
			RECT 6.3555 7.4524 6.3705 7.4841 ;
			RECT 6.4395 7.4524 6.4545 7.4841 ;
			RECT 6.5235 7.4524 6.5385 7.4841 ;
			RECT 6.6075 7.4524 6.6225 7.4841 ;
			RECT 6.6915 7.4524 6.7065 7.4841 ;
			RECT 6.7755 7.4524 6.7905 7.4841 ;
			RECT 6.8595 7.4524 6.8745 7.4841 ;
			RECT 6.9435 7.4524 6.9585 7.4841 ;
			RECT 7.0275 7.4524 7.0425 7.4841 ;
			RECT 7.1115 7.4524 7.1265 7.4841 ;
			RECT 7.1955 7.4524 7.2105 7.4841 ;
			RECT 7.2795 7.4524 7.2945 7.4841 ;
			RECT 7.3635 7.4524 7.3785 7.4841 ;
			RECT 7.4475 7.4524 7.4625 7.4841 ;
			RECT 7.5315 7.4524 7.5465 7.4841 ;
			RECT 7.6155 7.4524 7.6305 7.4841 ;
			RECT 7.6995 7.4524 7.7145 7.4841 ;
			RECT 7.7835 7.4524 7.7985 7.4841 ;
			RECT 7.8675 7.4524 7.8825 7.4841 ;
			RECT 8.1261 7.4524 8.141 7.4841 ;
		END

		PORT
			 LAYER M4 ;
			RECT 0.2105 6.6444 8.463 6.6921 ;
			 LAYER V3 ;
			RECT 2.3968 6.6524 2.4117 6.6841 ;
			RECT 4.6256 6.6524 4.6405 6.6841 ;
			RECT 4.921 6.6524 4.9359 6.6841 ;
			RECT 5.1795 6.6524 5.1945 6.6841 ;
			RECT 5.2635 6.6524 5.2785 6.6841 ;
			RECT 5.3475 6.6524 5.3625 6.6841 ;
			RECT 5.4315 6.6524 5.4465 6.6841 ;
			RECT 5.5155 6.6524 5.5305 6.6841 ;
			RECT 5.5995 6.6524 5.6145 6.6841 ;
			RECT 5.6835 6.6524 5.6985 6.6841 ;
			RECT 5.7675 6.6524 5.7825 6.6841 ;
			RECT 5.8515 6.6524 5.8665 6.6841 ;
			RECT 5.9355 6.6524 5.9505 6.6841 ;
			RECT 6.0195 6.6524 6.0345 6.6841 ;
			RECT 6.1035 6.6524 6.1185 6.6841 ;
			RECT 6.1875 6.6524 6.2025 6.6841 ;
			RECT 6.2715 6.6524 6.2865 6.6841 ;
			RECT 6.3555 6.6524 6.3705 6.6841 ;
			RECT 6.4395 6.6524 6.4545 6.6841 ;
			RECT 6.5235 6.6524 6.5385 6.6841 ;
			RECT 6.6075 6.6524 6.6225 6.6841 ;
			RECT 6.6915 6.6524 6.7065 6.6841 ;
			RECT 6.7755 6.6524 6.7905 6.6841 ;
			RECT 6.8595 6.6524 6.8745 6.6841 ;
			RECT 6.9435 6.6524 6.9585 6.6841 ;
			RECT 7.0275 6.6524 7.0425 6.6841 ;
			RECT 7.1115 6.6524 7.1265 6.6841 ;
			RECT 7.1955 6.6524 7.2105 6.6841 ;
			RECT 7.2795 6.6524 7.2945 6.6841 ;
			RECT 7.3635 6.6524 7.3785 6.6841 ;
			RECT 7.4475 6.6524 7.4625 6.6841 ;
			RECT 7.5315 6.6524 7.5465 6.6841 ;
			RECT 7.6155 6.6524 7.6305 6.6841 ;
			RECT 7.6995 6.6524 7.7145 6.6841 ;
			RECT 7.7835 6.6524 7.7985 6.6841 ;
			RECT 7.8675 6.6524 7.8825 6.6841 ;
			RECT 8.1261 6.6524 8.141 6.6841 ;
		END

		PORT
			 LAYER M4 ;
			RECT 0.2105 5.8444 8.463 5.8921 ;
			 LAYER V3 ;
			RECT 2.3968 5.8524 2.4117 5.8841 ;
			RECT 4.6256 5.8524 4.6405 5.8841 ;
			RECT 4.921 5.8524 4.9359 5.8841 ;
			RECT 5.1795 5.8524 5.1945 5.8841 ;
			RECT 5.2635 5.8524 5.2785 5.8841 ;
			RECT 5.3475 5.8524 5.3625 5.8841 ;
			RECT 5.4315 5.8524 5.4465 5.8841 ;
			RECT 5.5155 5.8524 5.5305 5.8841 ;
			RECT 5.5995 5.8524 5.6145 5.8841 ;
			RECT 5.6835 5.8524 5.6985 5.8841 ;
			RECT 5.7675 5.8524 5.7825 5.8841 ;
			RECT 5.8515 5.8524 5.8665 5.8841 ;
			RECT 5.9355 5.8524 5.9505 5.8841 ;
			RECT 6.0195 5.8524 6.0345 5.8841 ;
			RECT 6.1035 5.8524 6.1185 5.8841 ;
			RECT 6.1875 5.8524 6.2025 5.8841 ;
			RECT 6.2715 5.8524 6.2865 5.8841 ;
			RECT 6.3555 5.8524 6.3705 5.8841 ;
			RECT 6.4395 5.8524 6.4545 5.8841 ;
			RECT 6.5235 5.8524 6.5385 5.8841 ;
			RECT 6.6075 5.8524 6.6225 5.8841 ;
			RECT 6.6915 5.8524 6.7065 5.8841 ;
			RECT 6.7755 5.8524 6.7905 5.8841 ;
			RECT 6.8595 5.8524 6.8745 5.8841 ;
			RECT 6.9435 5.8524 6.9585 5.8841 ;
			RECT 7.0275 5.8524 7.0425 5.8841 ;
			RECT 7.1115 5.8524 7.1265 5.8841 ;
			RECT 7.1955 5.8524 7.2105 5.8841 ;
			RECT 7.2795 5.8524 7.2945 5.8841 ;
			RECT 7.3635 5.8524 7.3785 5.8841 ;
			RECT 7.4475 5.8524 7.4625 5.8841 ;
			RECT 7.5315 5.8524 7.5465 5.8841 ;
			RECT 7.6155 5.8524 7.6305 5.8841 ;
			RECT 7.6995 5.8524 7.7145 5.8841 ;
			RECT 7.7835 5.8524 7.7985 5.8841 ;
			RECT 7.8675 5.8524 7.8825 5.8841 ;
			RECT 8.1261 5.8524 8.141 5.8841 ;
		END

		PORT
			 LAYER M4 ;
			RECT 0.2105 40.4889 8.463 40.5365 ;
			 LAYER V3 ;
			RECT 2.3968 40.4968 2.4117 40.5286 ;
			RECT 4.6256 40.4968 4.6405 40.5286 ;
			RECT 4.921 40.4968 4.9359 40.5286 ;
			RECT 5.1795 40.4968 5.1945 40.5286 ;
			RECT 5.2635 40.4968 5.2785 40.5286 ;
			RECT 5.3475 40.4968 5.3625 40.5286 ;
			RECT 5.4315 40.4968 5.4465 40.5286 ;
			RECT 5.5155 40.4968 5.5305 40.5286 ;
			RECT 5.5995 40.4968 5.6145 40.5286 ;
			RECT 5.6835 40.4968 5.6985 40.5286 ;
			RECT 5.7675 40.4968 5.7825 40.5286 ;
			RECT 5.8515 40.4968 5.8665 40.5286 ;
			RECT 5.9355 40.4968 5.9505 40.5286 ;
			RECT 6.0195 40.4968 6.0345 40.5286 ;
			RECT 6.1035 40.4968 6.1185 40.5286 ;
			RECT 6.1875 40.4968 6.2025 40.5286 ;
			RECT 6.2715 40.4968 6.2865 40.5286 ;
			RECT 6.3555 40.4968 6.3705 40.5286 ;
			RECT 6.4395 40.4968 6.4545 40.5286 ;
			RECT 6.5235 40.4968 6.5385 40.5286 ;
			RECT 6.6075 40.4968 6.6225 40.5286 ;
			RECT 6.6915 40.4968 6.7065 40.5286 ;
			RECT 6.7755 40.4968 6.7905 40.5286 ;
			RECT 6.8595 40.4968 6.8745 40.5286 ;
			RECT 6.9435 40.4968 6.9585 40.5286 ;
			RECT 7.0275 40.4968 7.0425 40.5286 ;
			RECT 7.1115 40.4968 7.1265 40.5286 ;
			RECT 7.1955 40.4968 7.2105 40.5286 ;
			RECT 7.2795 40.4968 7.2945 40.5286 ;
			RECT 7.3635 40.4968 7.3785 40.5286 ;
			RECT 7.4475 40.4968 7.4625 40.5286 ;
			RECT 7.5315 40.4968 7.5465 40.5286 ;
			RECT 7.6155 40.4968 7.6305 40.5286 ;
			RECT 7.6995 40.4968 7.7145 40.5286 ;
			RECT 7.7835 40.4968 7.7985 40.5286 ;
			RECT 7.8675 40.4968 7.8825 40.5286 ;
			RECT 8.1261 40.4968 8.141 40.5286 ;
		END

		PORT
			 LAYER M4 ;
			RECT 0.2105 5.0444 8.463 5.0921 ;
			 LAYER V3 ;
			RECT 2.3968 5.0524 2.4117 5.0841 ;
			RECT 4.6256 5.0524 4.6405 5.0841 ;
			RECT 4.921 5.0524 4.9359 5.0841 ;
			RECT 5.1795 5.0524 5.1945 5.0841 ;
			RECT 5.2635 5.0524 5.2785 5.0841 ;
			RECT 5.3475 5.0524 5.3625 5.0841 ;
			RECT 5.4315 5.0524 5.4465 5.0841 ;
			RECT 5.5155 5.0524 5.5305 5.0841 ;
			RECT 5.5995 5.0524 5.6145 5.0841 ;
			RECT 5.6835 5.0524 5.6985 5.0841 ;
			RECT 5.7675 5.0524 5.7825 5.0841 ;
			RECT 5.8515 5.0524 5.8665 5.0841 ;
			RECT 5.9355 5.0524 5.9505 5.0841 ;
			RECT 6.0195 5.0524 6.0345 5.0841 ;
			RECT 6.1035 5.0524 6.1185 5.0841 ;
			RECT 6.1875 5.0524 6.2025 5.0841 ;
			RECT 6.2715 5.0524 6.2865 5.0841 ;
			RECT 6.3555 5.0524 6.3705 5.0841 ;
			RECT 6.4395 5.0524 6.4545 5.0841 ;
			RECT 6.5235 5.0524 6.5385 5.0841 ;
			RECT 6.6075 5.0524 6.6225 5.0841 ;
			RECT 6.6915 5.0524 6.7065 5.0841 ;
			RECT 6.7755 5.0524 6.7905 5.0841 ;
			RECT 6.8595 5.0524 6.8745 5.0841 ;
			RECT 6.9435 5.0524 6.9585 5.0841 ;
			RECT 7.0275 5.0524 7.0425 5.0841 ;
			RECT 7.1115 5.0524 7.1265 5.0841 ;
			RECT 7.1955 5.0524 7.2105 5.0841 ;
			RECT 7.2795 5.0524 7.2945 5.0841 ;
			RECT 7.3635 5.0524 7.3785 5.0841 ;
			RECT 7.4475 5.0524 7.4625 5.0841 ;
			RECT 7.5315 5.0524 7.5465 5.0841 ;
			RECT 7.6155 5.0524 7.6305 5.0841 ;
			RECT 7.6995 5.0524 7.7145 5.0841 ;
			RECT 7.7835 5.0524 7.7985 5.0841 ;
			RECT 7.8675 5.0524 7.8825 5.0841 ;
			RECT 8.1261 5.0524 8.141 5.0841 ;
		END

		PORT
			 LAYER M4 ;
			RECT 0.2105 4.2444 8.463 4.2921 ;
			 LAYER V3 ;
			RECT 2.3968 4.2524 2.4117 4.2841 ;
			RECT 4.6256 4.2524 4.6405 4.2841 ;
			RECT 4.921 4.2524 4.9359 4.2841 ;
			RECT 5.1795 4.2524 5.1945 4.2841 ;
			RECT 5.2635 4.2524 5.2785 4.2841 ;
			RECT 5.3475 4.2524 5.3625 4.2841 ;
			RECT 5.4315 4.2524 5.4465 4.2841 ;
			RECT 5.5155 4.2524 5.5305 4.2841 ;
			RECT 5.5995 4.2524 5.6145 4.2841 ;
			RECT 5.6835 4.2524 5.6985 4.2841 ;
			RECT 5.7675 4.2524 5.7825 4.2841 ;
			RECT 5.8515 4.2524 5.8665 4.2841 ;
			RECT 5.9355 4.2524 5.9505 4.2841 ;
			RECT 6.0195 4.2524 6.0345 4.2841 ;
			RECT 6.1035 4.2524 6.1185 4.2841 ;
			RECT 6.1875 4.2524 6.2025 4.2841 ;
			RECT 6.2715 4.2524 6.2865 4.2841 ;
			RECT 6.3555 4.2524 6.3705 4.2841 ;
			RECT 6.4395 4.2524 6.4545 4.2841 ;
			RECT 6.5235 4.2524 6.5385 4.2841 ;
			RECT 6.6075 4.2524 6.6225 4.2841 ;
			RECT 6.6915 4.2524 6.7065 4.2841 ;
			RECT 6.7755 4.2524 6.7905 4.2841 ;
			RECT 6.8595 4.2524 6.8745 4.2841 ;
			RECT 6.9435 4.2524 6.9585 4.2841 ;
			RECT 7.0275 4.2524 7.0425 4.2841 ;
			RECT 7.1115 4.2524 7.1265 4.2841 ;
			RECT 7.1955 4.2524 7.2105 4.2841 ;
			RECT 7.2795 4.2524 7.2945 4.2841 ;
			RECT 7.3635 4.2524 7.3785 4.2841 ;
			RECT 7.4475 4.2524 7.4625 4.2841 ;
			RECT 7.5315 4.2524 7.5465 4.2841 ;
			RECT 7.6155 4.2524 7.6305 4.2841 ;
			RECT 7.6995 4.2524 7.7145 4.2841 ;
			RECT 7.7835 4.2524 7.7985 4.2841 ;
			RECT 7.8675 4.2524 7.8825 4.2841 ;
			RECT 8.1261 4.2524 8.141 4.2841 ;
		END

		PORT
			 LAYER M4 ;
			RECT 0.2105 3.4444 8.463 3.4921 ;
			 LAYER V3 ;
			RECT 2.3968 3.4524 2.4117 3.4841 ;
			RECT 4.6256 3.4524 4.6405 3.4841 ;
			RECT 4.921 3.4524 4.9359 3.4841 ;
			RECT 5.1795 3.4524 5.1945 3.4841 ;
			RECT 5.2635 3.4524 5.2785 3.4841 ;
			RECT 5.3475 3.4524 5.3625 3.4841 ;
			RECT 5.4315 3.4524 5.4465 3.4841 ;
			RECT 5.5155 3.4524 5.5305 3.4841 ;
			RECT 5.5995 3.4524 5.6145 3.4841 ;
			RECT 5.6835 3.4524 5.6985 3.4841 ;
			RECT 5.7675 3.4524 5.7825 3.4841 ;
			RECT 5.8515 3.4524 5.8665 3.4841 ;
			RECT 5.9355 3.4524 5.9505 3.4841 ;
			RECT 6.0195 3.4524 6.0345 3.4841 ;
			RECT 6.1035 3.4524 6.1185 3.4841 ;
			RECT 6.1875 3.4524 6.2025 3.4841 ;
			RECT 6.2715 3.4524 6.2865 3.4841 ;
			RECT 6.3555 3.4524 6.3705 3.4841 ;
			RECT 6.4395 3.4524 6.4545 3.4841 ;
			RECT 6.5235 3.4524 6.5385 3.4841 ;
			RECT 6.6075 3.4524 6.6225 3.4841 ;
			RECT 6.6915 3.4524 6.7065 3.4841 ;
			RECT 6.7755 3.4524 6.7905 3.4841 ;
			RECT 6.8595 3.4524 6.8745 3.4841 ;
			RECT 6.9435 3.4524 6.9585 3.4841 ;
			RECT 7.0275 3.4524 7.0425 3.4841 ;
			RECT 7.1115 3.4524 7.1265 3.4841 ;
			RECT 7.1955 3.4524 7.2105 3.4841 ;
			RECT 7.2795 3.4524 7.2945 3.4841 ;
			RECT 7.3635 3.4524 7.3785 3.4841 ;
			RECT 7.4475 3.4524 7.4625 3.4841 ;
			RECT 7.5315 3.4524 7.5465 3.4841 ;
			RECT 7.6155 3.4524 7.6305 3.4841 ;
			RECT 7.6995 3.4524 7.7145 3.4841 ;
			RECT 7.7835 3.4524 7.7985 3.4841 ;
			RECT 7.8675 3.4524 7.8825 3.4841 ;
			RECT 8.1261 3.4524 8.141 3.4841 ;
		END

		PORT
			 LAYER M4 ;
			RECT 0.2105 2.6444 8.463 2.6921 ;
			 LAYER V3 ;
			RECT 2.3968 2.6524 2.4117 2.6841 ;
			RECT 4.6256 2.6524 4.6405 2.6841 ;
			RECT 4.921 2.6524 4.9359 2.6841 ;
			RECT 5.1795 2.6524 5.1945 2.6841 ;
			RECT 5.2635 2.6524 5.2785 2.6841 ;
			RECT 5.3475 2.6524 5.3625 2.6841 ;
			RECT 5.4315 2.6524 5.4465 2.6841 ;
			RECT 5.5155 2.6524 5.5305 2.6841 ;
			RECT 5.5995 2.6524 5.6145 2.6841 ;
			RECT 5.6835 2.6524 5.6985 2.6841 ;
			RECT 5.7675 2.6524 5.7825 2.6841 ;
			RECT 5.8515 2.6524 5.8665 2.6841 ;
			RECT 5.9355 2.6524 5.9505 2.6841 ;
			RECT 6.0195 2.6524 6.0345 2.6841 ;
			RECT 6.1035 2.6524 6.1185 2.6841 ;
			RECT 6.1875 2.6524 6.2025 2.6841 ;
			RECT 6.2715 2.6524 6.2865 2.6841 ;
			RECT 6.3555 2.6524 6.3705 2.6841 ;
			RECT 6.4395 2.6524 6.4545 2.6841 ;
			RECT 6.5235 2.6524 6.5385 2.6841 ;
			RECT 6.6075 2.6524 6.6225 2.6841 ;
			RECT 6.6915 2.6524 6.7065 2.6841 ;
			RECT 6.7755 2.6524 6.7905 2.6841 ;
			RECT 6.8595 2.6524 6.8745 2.6841 ;
			RECT 6.9435 2.6524 6.9585 2.6841 ;
			RECT 7.0275 2.6524 7.0425 2.6841 ;
			RECT 7.1115 2.6524 7.1265 2.6841 ;
			RECT 7.1955 2.6524 7.2105 2.6841 ;
			RECT 7.2795 2.6524 7.2945 2.6841 ;
			RECT 7.3635 2.6524 7.3785 2.6841 ;
			RECT 7.4475 2.6524 7.4625 2.6841 ;
			RECT 7.5315 2.6524 7.5465 2.6841 ;
			RECT 7.6155 2.6524 7.6305 2.6841 ;
			RECT 7.6995 2.6524 7.7145 2.6841 ;
			RECT 7.7835 2.6524 7.7985 2.6841 ;
			RECT 7.8675 2.6524 7.8825 2.6841 ;
			RECT 8.1261 2.6524 8.141 2.6841 ;
		END

		PORT
			 LAYER M4 ;
			RECT 0.2105 1.8444 8.463 1.8921 ;
			 LAYER V3 ;
			RECT 2.3968 1.8524 2.4117 1.8841 ;
			RECT 4.6256 1.8524 4.6405 1.8841 ;
			RECT 4.921 1.8524 4.9359 1.8841 ;
			RECT 5.1795 1.8524 5.1945 1.8841 ;
			RECT 5.2635 1.8524 5.2785 1.8841 ;
			RECT 5.3475 1.8524 5.3625 1.8841 ;
			RECT 5.4315 1.8524 5.4465 1.8841 ;
			RECT 5.5155 1.8524 5.5305 1.8841 ;
			RECT 5.5995 1.8524 5.6145 1.8841 ;
			RECT 5.6835 1.8524 5.6985 1.8841 ;
			RECT 5.7675 1.8524 5.7825 1.8841 ;
			RECT 5.8515 1.8524 5.8665 1.8841 ;
			RECT 5.9355 1.8524 5.9505 1.8841 ;
			RECT 6.0195 1.8524 6.0345 1.8841 ;
			RECT 6.1035 1.8524 6.1185 1.8841 ;
			RECT 6.1875 1.8524 6.2025 1.8841 ;
			RECT 6.2715 1.8524 6.2865 1.8841 ;
			RECT 6.3555 1.8524 6.3705 1.8841 ;
			RECT 6.4395 1.8524 6.4545 1.8841 ;
			RECT 6.5235 1.8524 6.5385 1.8841 ;
			RECT 6.6075 1.8524 6.6225 1.8841 ;
			RECT 6.6915 1.8524 6.7065 1.8841 ;
			RECT 6.7755 1.8524 6.7905 1.8841 ;
			RECT 6.8595 1.8524 6.8745 1.8841 ;
			RECT 6.9435 1.8524 6.9585 1.8841 ;
			RECT 7.0275 1.8524 7.0425 1.8841 ;
			RECT 7.1115 1.8524 7.1265 1.8841 ;
			RECT 7.1955 1.8524 7.2105 1.8841 ;
			RECT 7.2795 1.8524 7.2945 1.8841 ;
			RECT 7.3635 1.8524 7.3785 1.8841 ;
			RECT 7.4475 1.8524 7.4625 1.8841 ;
			RECT 7.5315 1.8524 7.5465 1.8841 ;
			RECT 7.6155 1.8524 7.6305 1.8841 ;
			RECT 7.6995 1.8524 7.7145 1.8841 ;
			RECT 7.7835 1.8524 7.7985 1.8841 ;
			RECT 7.8675 1.8524 7.8825 1.8841 ;
			RECT 8.1261 1.8524 8.141 1.8841 ;
		END

		PORT
			 LAYER M4 ;
			RECT 0.2105 1.0444 8.463 1.0921 ;
			 LAYER V3 ;
			RECT 2.3968 1.0524 2.4117 1.0841 ;
			RECT 4.6256 1.0524 4.6405 1.0841 ;
			RECT 4.921 1.0524 4.9359 1.0841 ;
			RECT 5.1795 1.0524 5.1945 1.0841 ;
			RECT 5.2635 1.0524 5.2785 1.0841 ;
			RECT 5.3475 1.0524 5.3625 1.0841 ;
			RECT 5.4315 1.0524 5.4465 1.0841 ;
			RECT 5.5155 1.0524 5.5305 1.0841 ;
			RECT 5.5995 1.0524 5.6145 1.0841 ;
			RECT 5.6835 1.0524 5.6985 1.0841 ;
			RECT 5.7675 1.0524 5.7825 1.0841 ;
			RECT 5.8515 1.0524 5.8665 1.0841 ;
			RECT 5.9355 1.0524 5.9505 1.0841 ;
			RECT 6.0195 1.0524 6.0345 1.0841 ;
			RECT 6.1035 1.0524 6.1185 1.0841 ;
			RECT 6.1875 1.0524 6.2025 1.0841 ;
			RECT 6.2715 1.0524 6.2865 1.0841 ;
			RECT 6.3555 1.0524 6.3705 1.0841 ;
			RECT 6.4395 1.0524 6.4545 1.0841 ;
			RECT 6.5235 1.0524 6.5385 1.0841 ;
			RECT 6.6075 1.0524 6.6225 1.0841 ;
			RECT 6.6915 1.0524 6.7065 1.0841 ;
			RECT 6.7755 1.0524 6.7905 1.0841 ;
			RECT 6.8595 1.0524 6.8745 1.0841 ;
			RECT 6.9435 1.0524 6.9585 1.0841 ;
			RECT 7.0275 1.0524 7.0425 1.0841 ;
			RECT 7.1115 1.0524 7.1265 1.0841 ;
			RECT 7.1955 1.0524 7.2105 1.0841 ;
			RECT 7.2795 1.0524 7.2945 1.0841 ;
			RECT 7.3635 1.0524 7.3785 1.0841 ;
			RECT 7.4475 1.0524 7.4625 1.0841 ;
			RECT 7.5315 1.0524 7.5465 1.0841 ;
			RECT 7.6155 1.0524 7.6305 1.0841 ;
			RECT 7.6995 1.0524 7.7145 1.0841 ;
			RECT 7.7835 1.0524 7.7985 1.0841 ;
			RECT 7.8675 1.0524 7.8825 1.0841 ;
			RECT 8.1261 1.0524 8.141 1.0841 ;
		END

		PORT
			 LAYER M4 ;
			RECT 0.2105 0.2444 8.463 0.2921 ;
			 LAYER V3 ;
			RECT 2.3968 0.2524 2.4117 0.2841 ;
			RECT 4.6256 0.2524 4.6405 0.2841 ;
			RECT 4.921 0.2524 4.9359 0.2841 ;
			RECT 5.1795 0.2524 5.1945 0.2841 ;
			RECT 5.2635 0.2524 5.2785 0.2841 ;
			RECT 5.3475 0.2524 5.3625 0.2841 ;
			RECT 5.4315 0.2524 5.4465 0.2841 ;
			RECT 5.5155 0.2524 5.5305 0.2841 ;
			RECT 5.5995 0.2524 5.6145 0.2841 ;
			RECT 5.6835 0.2524 5.6985 0.2841 ;
			RECT 5.7675 0.2524 5.7825 0.2841 ;
			RECT 5.8515 0.2524 5.8665 0.2841 ;
			RECT 5.9355 0.2524 5.9505 0.2841 ;
			RECT 6.0195 0.2524 6.0345 0.2841 ;
			RECT 6.1035 0.2524 6.1185 0.2841 ;
			RECT 6.1875 0.2524 6.2025 0.2841 ;
			RECT 6.2715 0.2524 6.2865 0.2841 ;
			RECT 6.3555 0.2524 6.3705 0.2841 ;
			RECT 6.4395 0.2524 6.4545 0.2841 ;
			RECT 6.5235 0.2524 6.5385 0.2841 ;
			RECT 6.6075 0.2524 6.6225 0.2841 ;
			RECT 6.6915 0.2524 6.7065 0.2841 ;
			RECT 6.7755 0.2524 6.7905 0.2841 ;
			RECT 6.8595 0.2524 6.8745 0.2841 ;
			RECT 6.9435 0.2524 6.9585 0.2841 ;
			RECT 7.0275 0.2524 7.0425 0.2841 ;
			RECT 7.1115 0.2524 7.1265 0.2841 ;
			RECT 7.1955 0.2524 7.2105 0.2841 ;
			RECT 7.2795 0.2524 7.2945 0.2841 ;
			RECT 7.3635 0.2524 7.3785 0.2841 ;
			RECT 7.4475 0.2524 7.4625 0.2841 ;
			RECT 7.5315 0.2524 7.5465 0.2841 ;
			RECT 7.6155 0.2524 7.6305 0.2841 ;
			RECT 7.6995 0.2524 7.7145 0.2841 ;
			RECT 7.7835 0.2524 7.7985 0.2841 ;
			RECT 7.8675 0.2524 7.8825 0.2841 ;
			RECT 8.1261 0.2524 8.141 0.2841 ;
		END

		PORT
			 LAYER M4 ;
			RECT 0.2105 39.6889 8.463 39.7365 ;
			 LAYER V3 ;
			RECT 2.3968 39.6968 2.4117 39.7286 ;
			RECT 4.6256 39.6968 4.6405 39.7286 ;
			RECT 4.921 39.6968 4.9359 39.7286 ;
			RECT 5.1795 39.6968 5.1945 39.7286 ;
			RECT 5.2635 39.6968 5.2785 39.7286 ;
			RECT 5.3475 39.6968 5.3625 39.7286 ;
			RECT 5.4315 39.6968 5.4465 39.7286 ;
			RECT 5.5155 39.6968 5.5305 39.7286 ;
			RECT 5.5995 39.6968 5.6145 39.7286 ;
			RECT 5.6835 39.6968 5.6985 39.7286 ;
			RECT 5.7675 39.6968 5.7825 39.7286 ;
			RECT 5.8515 39.6968 5.8665 39.7286 ;
			RECT 5.9355 39.6968 5.9505 39.7286 ;
			RECT 6.0195 39.6968 6.0345 39.7286 ;
			RECT 6.1035 39.6968 6.1185 39.7286 ;
			RECT 6.1875 39.6968 6.2025 39.7286 ;
			RECT 6.2715 39.6968 6.2865 39.7286 ;
			RECT 6.3555 39.6968 6.3705 39.7286 ;
			RECT 6.4395 39.6968 6.4545 39.7286 ;
			RECT 6.5235 39.6968 6.5385 39.7286 ;
			RECT 6.6075 39.6968 6.6225 39.7286 ;
			RECT 6.6915 39.6968 6.7065 39.7286 ;
			RECT 6.7755 39.6968 6.7905 39.7286 ;
			RECT 6.8595 39.6968 6.8745 39.7286 ;
			RECT 6.9435 39.6968 6.9585 39.7286 ;
			RECT 7.0275 39.6968 7.0425 39.7286 ;
			RECT 7.1115 39.6968 7.1265 39.7286 ;
			RECT 7.1955 39.6968 7.2105 39.7286 ;
			RECT 7.2795 39.6968 7.2945 39.7286 ;
			RECT 7.3635 39.6968 7.3785 39.7286 ;
			RECT 7.4475 39.6968 7.4625 39.7286 ;
			RECT 7.5315 39.6968 7.5465 39.7286 ;
			RECT 7.6155 39.6968 7.6305 39.7286 ;
			RECT 7.6995 39.6968 7.7145 39.7286 ;
			RECT 7.7835 39.6968 7.7985 39.7286 ;
			RECT 7.8675 39.6968 7.8825 39.7286 ;
			RECT 8.1261 39.6968 8.141 39.7286 ;
		END

		PORT
			 LAYER M4 ;
			RECT 0.2105 38.8889 8.463 38.9365 ;
			 LAYER V3 ;
			RECT 2.3968 38.8968 2.4117 38.9286 ;
			RECT 4.6256 38.8968 4.6405 38.9286 ;
			RECT 4.921 38.8968 4.9359 38.9286 ;
			RECT 5.1795 38.8968 5.1945 38.9286 ;
			RECT 5.2635 38.8968 5.2785 38.9286 ;
			RECT 5.3475 38.8968 5.3625 38.9286 ;
			RECT 5.4315 38.8968 5.4465 38.9286 ;
			RECT 5.5155 38.8968 5.5305 38.9286 ;
			RECT 5.5995 38.8968 5.6145 38.9286 ;
			RECT 5.6835 38.8968 5.6985 38.9286 ;
			RECT 5.7675 38.8968 5.7825 38.9286 ;
			RECT 5.8515 38.8968 5.8665 38.9286 ;
			RECT 5.9355 38.8968 5.9505 38.9286 ;
			RECT 6.0195 38.8968 6.0345 38.9286 ;
			RECT 6.1035 38.8968 6.1185 38.9286 ;
			RECT 6.1875 38.8968 6.2025 38.9286 ;
			RECT 6.2715 38.8968 6.2865 38.9286 ;
			RECT 6.3555 38.8968 6.3705 38.9286 ;
			RECT 6.4395 38.8968 6.4545 38.9286 ;
			RECT 6.5235 38.8968 6.5385 38.9286 ;
			RECT 6.6075 38.8968 6.6225 38.9286 ;
			RECT 6.6915 38.8968 6.7065 38.9286 ;
			RECT 6.7755 38.8968 6.7905 38.9286 ;
			RECT 6.8595 38.8968 6.8745 38.9286 ;
			RECT 6.9435 38.8968 6.9585 38.9286 ;
			RECT 7.0275 38.8968 7.0425 38.9286 ;
			RECT 7.1115 38.8968 7.1265 38.9286 ;
			RECT 7.1955 38.8968 7.2105 38.9286 ;
			RECT 7.2795 38.8968 7.2945 38.9286 ;
			RECT 7.3635 38.8968 7.3785 38.9286 ;
			RECT 7.4475 38.8968 7.4625 38.9286 ;
			RECT 7.5315 38.8968 7.5465 38.9286 ;
			RECT 7.6155 38.8968 7.6305 38.9286 ;
			RECT 7.6995 38.8968 7.7145 38.9286 ;
			RECT 7.7835 38.8968 7.7985 38.9286 ;
			RECT 7.8675 38.8968 7.8825 38.9286 ;
			RECT 8.1261 38.8968 8.141 38.9286 ;
		END

		PORT
			 LAYER M4 ;
			RECT 0.2105 38.0889 8.463 38.1365 ;
			 LAYER V3 ;
			RECT 2.3968 38.0968 2.4117 38.1286 ;
			RECT 4.6256 38.0968 4.6405 38.1286 ;
			RECT 4.921 38.0968 4.9359 38.1286 ;
			RECT 5.1795 38.0968 5.1945 38.1286 ;
			RECT 5.2635 38.0968 5.2785 38.1286 ;
			RECT 5.3475 38.0968 5.3625 38.1286 ;
			RECT 5.4315 38.0968 5.4465 38.1286 ;
			RECT 5.5155 38.0968 5.5305 38.1286 ;
			RECT 5.5995 38.0968 5.6145 38.1286 ;
			RECT 5.6835 38.0968 5.6985 38.1286 ;
			RECT 5.7675 38.0968 5.7825 38.1286 ;
			RECT 5.8515 38.0968 5.8665 38.1286 ;
			RECT 5.9355 38.0968 5.9505 38.1286 ;
			RECT 6.0195 38.0968 6.0345 38.1286 ;
			RECT 6.1035 38.0968 6.1185 38.1286 ;
			RECT 6.1875 38.0968 6.2025 38.1286 ;
			RECT 6.2715 38.0968 6.2865 38.1286 ;
			RECT 6.3555 38.0968 6.3705 38.1286 ;
			RECT 6.4395 38.0968 6.4545 38.1286 ;
			RECT 6.5235 38.0968 6.5385 38.1286 ;
			RECT 6.6075 38.0968 6.6225 38.1286 ;
			RECT 6.6915 38.0968 6.7065 38.1286 ;
			RECT 6.7755 38.0968 6.7905 38.1286 ;
			RECT 6.8595 38.0968 6.8745 38.1286 ;
			RECT 6.9435 38.0968 6.9585 38.1286 ;
			RECT 7.0275 38.0968 7.0425 38.1286 ;
			RECT 7.1115 38.0968 7.1265 38.1286 ;
			RECT 7.1955 38.0968 7.2105 38.1286 ;
			RECT 7.2795 38.0968 7.2945 38.1286 ;
			RECT 7.3635 38.0968 7.3785 38.1286 ;
			RECT 7.4475 38.0968 7.4625 38.1286 ;
			RECT 7.5315 38.0968 7.5465 38.1286 ;
			RECT 7.6155 38.0968 7.6305 38.1286 ;
			RECT 7.6995 38.0968 7.7145 38.1286 ;
			RECT 7.7835 38.0968 7.7985 38.1286 ;
			RECT 7.8675 38.0968 7.8825 38.1286 ;
			RECT 8.1261 38.0968 8.141 38.1286 ;
		END

		PORT
			 LAYER M4 ;
			RECT 0.2105 37.2889 8.463 37.3365 ;
			 LAYER V3 ;
			RECT 2.3968 37.2968 2.4117 37.3286 ;
			RECT 4.6256 37.2968 4.6405 37.3286 ;
			RECT 4.921 37.2968 4.9359 37.3286 ;
			RECT 5.1795 37.2968 5.1945 37.3286 ;
			RECT 5.2635 37.2968 5.2785 37.3286 ;
			RECT 5.3475 37.2968 5.3625 37.3286 ;
			RECT 5.4315 37.2968 5.4465 37.3286 ;
			RECT 5.5155 37.2968 5.5305 37.3286 ;
			RECT 5.5995 37.2968 5.6145 37.3286 ;
			RECT 5.6835 37.2968 5.6985 37.3286 ;
			RECT 5.7675 37.2968 5.7825 37.3286 ;
			RECT 5.8515 37.2968 5.8665 37.3286 ;
			RECT 5.9355 37.2968 5.9505 37.3286 ;
			RECT 6.0195 37.2968 6.0345 37.3286 ;
			RECT 6.1035 37.2968 6.1185 37.3286 ;
			RECT 6.1875 37.2968 6.2025 37.3286 ;
			RECT 6.2715 37.2968 6.2865 37.3286 ;
			RECT 6.3555 37.2968 6.3705 37.3286 ;
			RECT 6.4395 37.2968 6.4545 37.3286 ;
			RECT 6.5235 37.2968 6.5385 37.3286 ;
			RECT 6.6075 37.2968 6.6225 37.3286 ;
			RECT 6.6915 37.2968 6.7065 37.3286 ;
			RECT 6.7755 37.2968 6.7905 37.3286 ;
			RECT 6.8595 37.2968 6.8745 37.3286 ;
			RECT 6.9435 37.2968 6.9585 37.3286 ;
			RECT 7.0275 37.2968 7.0425 37.3286 ;
			RECT 7.1115 37.2968 7.1265 37.3286 ;
			RECT 7.1955 37.2968 7.2105 37.3286 ;
			RECT 7.2795 37.2968 7.2945 37.3286 ;
			RECT 7.3635 37.2968 7.3785 37.3286 ;
			RECT 7.4475 37.2968 7.4625 37.3286 ;
			RECT 7.5315 37.2968 7.5465 37.3286 ;
			RECT 7.6155 37.2968 7.6305 37.3286 ;
			RECT 7.6995 37.2968 7.7145 37.3286 ;
			RECT 7.7835 37.2968 7.7985 37.3286 ;
			RECT 7.8675 37.2968 7.8825 37.3286 ;
			RECT 8.1261 37.2968 8.141 37.3286 ;
		END

		PORT
			 LAYER M4 ;
			RECT 0.2105 36.4889 8.463 36.5365 ;
			 LAYER V3 ;
			RECT 2.3968 36.4968 2.4117 36.5286 ;
			RECT 4.6256 36.4968 4.6405 36.5286 ;
			RECT 4.921 36.4968 4.9359 36.5286 ;
			RECT 5.1795 36.4968 5.1945 36.5286 ;
			RECT 5.2635 36.4968 5.2785 36.5286 ;
			RECT 5.3475 36.4968 5.3625 36.5286 ;
			RECT 5.4315 36.4968 5.4465 36.5286 ;
			RECT 5.5155 36.4968 5.5305 36.5286 ;
			RECT 5.5995 36.4968 5.6145 36.5286 ;
			RECT 5.6835 36.4968 5.6985 36.5286 ;
			RECT 5.7675 36.4968 5.7825 36.5286 ;
			RECT 5.8515 36.4968 5.8665 36.5286 ;
			RECT 5.9355 36.4968 5.9505 36.5286 ;
			RECT 6.0195 36.4968 6.0345 36.5286 ;
			RECT 6.1035 36.4968 6.1185 36.5286 ;
			RECT 6.1875 36.4968 6.2025 36.5286 ;
			RECT 6.2715 36.4968 6.2865 36.5286 ;
			RECT 6.3555 36.4968 6.3705 36.5286 ;
			RECT 6.4395 36.4968 6.4545 36.5286 ;
			RECT 6.5235 36.4968 6.5385 36.5286 ;
			RECT 6.6075 36.4968 6.6225 36.5286 ;
			RECT 6.6915 36.4968 6.7065 36.5286 ;
			RECT 6.7755 36.4968 6.7905 36.5286 ;
			RECT 6.8595 36.4968 6.8745 36.5286 ;
			RECT 6.9435 36.4968 6.9585 36.5286 ;
			RECT 7.0275 36.4968 7.0425 36.5286 ;
			RECT 7.1115 36.4968 7.1265 36.5286 ;
			RECT 7.1955 36.4968 7.2105 36.5286 ;
			RECT 7.2795 36.4968 7.2945 36.5286 ;
			RECT 7.3635 36.4968 7.3785 36.5286 ;
			RECT 7.4475 36.4968 7.4625 36.5286 ;
			RECT 7.5315 36.4968 7.5465 36.5286 ;
			RECT 7.6155 36.4968 7.6305 36.5286 ;
			RECT 7.6995 36.4968 7.7145 36.5286 ;
			RECT 7.7835 36.4968 7.7985 36.5286 ;
			RECT 7.8675 36.4968 7.8825 36.5286 ;
			RECT 8.1261 36.4968 8.141 36.5286 ;
		END

		PORT
			 LAYER M4 ;
			RECT 0.2105 35.6889 8.463 35.7365 ;
			 LAYER V3 ;
			RECT 2.3968 35.6968 2.4117 35.7286 ;
			RECT 4.6256 35.6968 4.6405 35.7286 ;
			RECT 4.921 35.6968 4.9359 35.7286 ;
			RECT 5.1795 35.6968 5.1945 35.7286 ;
			RECT 5.2635 35.6968 5.2785 35.7286 ;
			RECT 5.3475 35.6968 5.3625 35.7286 ;
			RECT 5.4315 35.6968 5.4465 35.7286 ;
			RECT 5.5155 35.6968 5.5305 35.7286 ;
			RECT 5.5995 35.6968 5.6145 35.7286 ;
			RECT 5.6835 35.6968 5.6985 35.7286 ;
			RECT 5.7675 35.6968 5.7825 35.7286 ;
			RECT 5.8515 35.6968 5.8665 35.7286 ;
			RECT 5.9355 35.6968 5.9505 35.7286 ;
			RECT 6.0195 35.6968 6.0345 35.7286 ;
			RECT 6.1035 35.6968 6.1185 35.7286 ;
			RECT 6.1875 35.6968 6.2025 35.7286 ;
			RECT 6.2715 35.6968 6.2865 35.7286 ;
			RECT 6.3555 35.6968 6.3705 35.7286 ;
			RECT 6.4395 35.6968 6.4545 35.7286 ;
			RECT 6.5235 35.6968 6.5385 35.7286 ;
			RECT 6.6075 35.6968 6.6225 35.7286 ;
			RECT 6.6915 35.6968 6.7065 35.7286 ;
			RECT 6.7755 35.6968 6.7905 35.7286 ;
			RECT 6.8595 35.6968 6.8745 35.7286 ;
			RECT 6.9435 35.6968 6.9585 35.7286 ;
			RECT 7.0275 35.6968 7.0425 35.7286 ;
			RECT 7.1115 35.6968 7.1265 35.7286 ;
			RECT 7.1955 35.6968 7.2105 35.7286 ;
			RECT 7.2795 35.6968 7.2945 35.7286 ;
			RECT 7.3635 35.6968 7.3785 35.7286 ;
			RECT 7.4475 35.6968 7.4625 35.7286 ;
			RECT 7.5315 35.6968 7.5465 35.7286 ;
			RECT 7.6155 35.6968 7.6305 35.7286 ;
			RECT 7.6995 35.6968 7.7145 35.7286 ;
			RECT 7.7835 35.6968 7.7985 35.7286 ;
			RECT 7.8675 35.6968 7.8825 35.7286 ;
			RECT 8.1261 35.6968 8.141 35.7286 ;
		END

		PORT
			 LAYER M4 ;
			RECT 0.2105 34.8889 8.463 34.9365 ;
			 LAYER V3 ;
			RECT 2.3968 34.8968 2.4117 34.9286 ;
			RECT 4.6256 34.8968 4.6405 34.9286 ;
			RECT 4.921 34.8968 4.9359 34.9286 ;
			RECT 5.1795 34.8968 5.1945 34.9286 ;
			RECT 5.2635 34.8968 5.2785 34.9286 ;
			RECT 5.3475 34.8968 5.3625 34.9286 ;
			RECT 5.4315 34.8968 5.4465 34.9286 ;
			RECT 5.5155 34.8968 5.5305 34.9286 ;
			RECT 5.5995 34.8968 5.6145 34.9286 ;
			RECT 5.6835 34.8968 5.6985 34.9286 ;
			RECT 5.7675 34.8968 5.7825 34.9286 ;
			RECT 5.8515 34.8968 5.8665 34.9286 ;
			RECT 5.9355 34.8968 5.9505 34.9286 ;
			RECT 6.0195 34.8968 6.0345 34.9286 ;
			RECT 6.1035 34.8968 6.1185 34.9286 ;
			RECT 6.1875 34.8968 6.2025 34.9286 ;
			RECT 6.2715 34.8968 6.2865 34.9286 ;
			RECT 6.3555 34.8968 6.3705 34.9286 ;
			RECT 6.4395 34.8968 6.4545 34.9286 ;
			RECT 6.5235 34.8968 6.5385 34.9286 ;
			RECT 6.6075 34.8968 6.6225 34.9286 ;
			RECT 6.6915 34.8968 6.7065 34.9286 ;
			RECT 6.7755 34.8968 6.7905 34.9286 ;
			RECT 6.8595 34.8968 6.8745 34.9286 ;
			RECT 6.9435 34.8968 6.9585 34.9286 ;
			RECT 7.0275 34.8968 7.0425 34.9286 ;
			RECT 7.1115 34.8968 7.1265 34.9286 ;
			RECT 7.1955 34.8968 7.2105 34.9286 ;
			RECT 7.2795 34.8968 7.2945 34.9286 ;
			RECT 7.3635 34.8968 7.3785 34.9286 ;
			RECT 7.4475 34.8968 7.4625 34.9286 ;
			RECT 7.5315 34.8968 7.5465 34.9286 ;
			RECT 7.6155 34.8968 7.6305 34.9286 ;
			RECT 7.6995 34.8968 7.7145 34.9286 ;
			RECT 7.7835 34.8968 7.7985 34.9286 ;
			RECT 7.8675 34.8968 7.8825 34.9286 ;
			RECT 8.1261 34.8968 8.141 34.9286 ;
		END

		PORT
			 LAYER M4 ;
			RECT 0.2105 34.0889 8.463 34.1365 ;
			 LAYER V3 ;
			RECT 2.3968 34.0968 2.4117 34.1286 ;
			RECT 4.6256 34.0968 4.6405 34.1286 ;
			RECT 4.921 34.0968 4.9359 34.1286 ;
			RECT 5.1795 34.0968 5.1945 34.1286 ;
			RECT 5.2635 34.0968 5.2785 34.1286 ;
			RECT 5.3475 34.0968 5.3625 34.1286 ;
			RECT 5.4315 34.0968 5.4465 34.1286 ;
			RECT 5.5155 34.0968 5.5305 34.1286 ;
			RECT 5.5995 34.0968 5.6145 34.1286 ;
			RECT 5.6835 34.0968 5.6985 34.1286 ;
			RECT 5.7675 34.0968 5.7825 34.1286 ;
			RECT 5.8515 34.0968 5.8665 34.1286 ;
			RECT 5.9355 34.0968 5.9505 34.1286 ;
			RECT 6.0195 34.0968 6.0345 34.1286 ;
			RECT 6.1035 34.0968 6.1185 34.1286 ;
			RECT 6.1875 34.0968 6.2025 34.1286 ;
			RECT 6.2715 34.0968 6.2865 34.1286 ;
			RECT 6.3555 34.0968 6.3705 34.1286 ;
			RECT 6.4395 34.0968 6.4545 34.1286 ;
			RECT 6.5235 34.0968 6.5385 34.1286 ;
			RECT 6.6075 34.0968 6.6225 34.1286 ;
			RECT 6.6915 34.0968 6.7065 34.1286 ;
			RECT 6.7755 34.0968 6.7905 34.1286 ;
			RECT 6.8595 34.0968 6.8745 34.1286 ;
			RECT 6.9435 34.0968 6.9585 34.1286 ;
			RECT 7.0275 34.0968 7.0425 34.1286 ;
			RECT 7.1115 34.0968 7.1265 34.1286 ;
			RECT 7.1955 34.0968 7.2105 34.1286 ;
			RECT 7.2795 34.0968 7.2945 34.1286 ;
			RECT 7.3635 34.0968 7.3785 34.1286 ;
			RECT 7.4475 34.0968 7.4625 34.1286 ;
			RECT 7.5315 34.0968 7.5465 34.1286 ;
			RECT 7.6155 34.0968 7.6305 34.1286 ;
			RECT 7.6995 34.0968 7.7145 34.1286 ;
			RECT 7.7835 34.0968 7.7985 34.1286 ;
			RECT 7.8675 34.0968 7.8825 34.1286 ;
			RECT 8.1261 34.0968 8.141 34.1286 ;
		END

		PORT
			 LAYER M4 ;
			RECT 0.2105 33.2889 8.463 33.3365 ;
			 LAYER V3 ;
			RECT 2.3968 33.2968 2.4117 33.3286 ;
			RECT 4.6256 33.2968 4.6405 33.3286 ;
			RECT 4.921 33.2968 4.9359 33.3286 ;
			RECT 5.1795 33.2968 5.1945 33.3286 ;
			RECT 5.2635 33.2968 5.2785 33.3286 ;
			RECT 5.3475 33.2968 5.3625 33.3286 ;
			RECT 5.4315 33.2968 5.4465 33.3286 ;
			RECT 5.5155 33.2968 5.5305 33.3286 ;
			RECT 5.5995 33.2968 5.6145 33.3286 ;
			RECT 5.6835 33.2968 5.6985 33.3286 ;
			RECT 5.7675 33.2968 5.7825 33.3286 ;
			RECT 5.8515 33.2968 5.8665 33.3286 ;
			RECT 5.9355 33.2968 5.9505 33.3286 ;
			RECT 6.0195 33.2968 6.0345 33.3286 ;
			RECT 6.1035 33.2968 6.1185 33.3286 ;
			RECT 6.1875 33.2968 6.2025 33.3286 ;
			RECT 6.2715 33.2968 6.2865 33.3286 ;
			RECT 6.3555 33.2968 6.3705 33.3286 ;
			RECT 6.4395 33.2968 6.4545 33.3286 ;
			RECT 6.5235 33.2968 6.5385 33.3286 ;
			RECT 6.6075 33.2968 6.6225 33.3286 ;
			RECT 6.6915 33.2968 6.7065 33.3286 ;
			RECT 6.7755 33.2968 6.7905 33.3286 ;
			RECT 6.8595 33.2968 6.8745 33.3286 ;
			RECT 6.9435 33.2968 6.9585 33.3286 ;
			RECT 7.0275 33.2968 7.0425 33.3286 ;
			RECT 7.1115 33.2968 7.1265 33.3286 ;
			RECT 7.1955 33.2968 7.2105 33.3286 ;
			RECT 7.2795 33.2968 7.2945 33.3286 ;
			RECT 7.3635 33.2968 7.3785 33.3286 ;
			RECT 7.4475 33.2968 7.4625 33.3286 ;
			RECT 7.5315 33.2968 7.5465 33.3286 ;
			RECT 7.6155 33.2968 7.6305 33.3286 ;
			RECT 7.6995 33.2968 7.7145 33.3286 ;
			RECT 7.7835 33.2968 7.7985 33.3286 ;
			RECT 7.8675 33.2968 7.8825 33.3286 ;
			RECT 8.1261 33.2968 8.141 33.3286 ;
		END

		PORT
			 LAYER M4 ;
			RECT 0.2105 32.4889 8.463 32.5365 ;
			 LAYER V3 ;
			RECT 2.3968 32.4968 2.4117 32.5286 ;
			RECT 4.6256 32.4968 4.6405 32.5286 ;
			RECT 4.921 32.4968 4.9359 32.5286 ;
			RECT 5.1795 32.4968 5.1945 32.5286 ;
			RECT 5.2635 32.4968 5.2785 32.5286 ;
			RECT 5.3475 32.4968 5.3625 32.5286 ;
			RECT 5.4315 32.4968 5.4465 32.5286 ;
			RECT 5.5155 32.4968 5.5305 32.5286 ;
			RECT 5.5995 32.4968 5.6145 32.5286 ;
			RECT 5.6835 32.4968 5.6985 32.5286 ;
			RECT 5.7675 32.4968 5.7825 32.5286 ;
			RECT 5.8515 32.4968 5.8665 32.5286 ;
			RECT 5.9355 32.4968 5.9505 32.5286 ;
			RECT 6.0195 32.4968 6.0345 32.5286 ;
			RECT 6.1035 32.4968 6.1185 32.5286 ;
			RECT 6.1875 32.4968 6.2025 32.5286 ;
			RECT 6.2715 32.4968 6.2865 32.5286 ;
			RECT 6.3555 32.4968 6.3705 32.5286 ;
			RECT 6.4395 32.4968 6.4545 32.5286 ;
			RECT 6.5235 32.4968 6.5385 32.5286 ;
			RECT 6.6075 32.4968 6.6225 32.5286 ;
			RECT 6.6915 32.4968 6.7065 32.5286 ;
			RECT 6.7755 32.4968 6.7905 32.5286 ;
			RECT 6.8595 32.4968 6.8745 32.5286 ;
			RECT 6.9435 32.4968 6.9585 32.5286 ;
			RECT 7.0275 32.4968 7.0425 32.5286 ;
			RECT 7.1115 32.4968 7.1265 32.5286 ;
			RECT 7.1955 32.4968 7.2105 32.5286 ;
			RECT 7.2795 32.4968 7.2945 32.5286 ;
			RECT 7.3635 32.4968 7.3785 32.5286 ;
			RECT 7.4475 32.4968 7.4625 32.5286 ;
			RECT 7.5315 32.4968 7.5465 32.5286 ;
			RECT 7.6155 32.4968 7.6305 32.5286 ;
			RECT 7.6995 32.4968 7.7145 32.5286 ;
			RECT 7.7835 32.4968 7.7985 32.5286 ;
			RECT 7.8675 32.4968 7.8825 32.5286 ;
			RECT 8.1261 32.4968 8.141 32.5286 ;
		END

		PORT
			 LAYER M4 ;
			RECT 0.2105 31.6889 8.463 31.7365 ;
			 LAYER V3 ;
			RECT 2.3968 31.6968 2.4117 31.7286 ;
			RECT 4.6256 31.6968 4.6405 31.7286 ;
			RECT 4.921 31.6968 4.9359 31.7286 ;
			RECT 5.1795 31.6968 5.1945 31.7286 ;
			RECT 5.2635 31.6968 5.2785 31.7286 ;
			RECT 5.3475 31.6968 5.3625 31.7286 ;
			RECT 5.4315 31.6968 5.4465 31.7286 ;
			RECT 5.5155 31.6968 5.5305 31.7286 ;
			RECT 5.5995 31.6968 5.6145 31.7286 ;
			RECT 5.6835 31.6968 5.6985 31.7286 ;
			RECT 5.7675 31.6968 5.7825 31.7286 ;
			RECT 5.8515 31.6968 5.8665 31.7286 ;
			RECT 5.9355 31.6968 5.9505 31.7286 ;
			RECT 6.0195 31.6968 6.0345 31.7286 ;
			RECT 6.1035 31.6968 6.1185 31.7286 ;
			RECT 6.1875 31.6968 6.2025 31.7286 ;
			RECT 6.2715 31.6968 6.2865 31.7286 ;
			RECT 6.3555 31.6968 6.3705 31.7286 ;
			RECT 6.4395 31.6968 6.4545 31.7286 ;
			RECT 6.5235 31.6968 6.5385 31.7286 ;
			RECT 6.6075 31.6968 6.6225 31.7286 ;
			RECT 6.6915 31.6968 6.7065 31.7286 ;
			RECT 6.7755 31.6968 6.7905 31.7286 ;
			RECT 6.8595 31.6968 6.8745 31.7286 ;
			RECT 6.9435 31.6968 6.9585 31.7286 ;
			RECT 7.0275 31.6968 7.0425 31.7286 ;
			RECT 7.1115 31.6968 7.1265 31.7286 ;
			RECT 7.1955 31.6968 7.2105 31.7286 ;
			RECT 7.2795 31.6968 7.2945 31.7286 ;
			RECT 7.3635 31.6968 7.3785 31.7286 ;
			RECT 7.4475 31.6968 7.4625 31.7286 ;
			RECT 7.5315 31.6968 7.5465 31.7286 ;
			RECT 7.6155 31.6968 7.6305 31.7286 ;
			RECT 7.6995 31.6968 7.7145 31.7286 ;
			RECT 7.7835 31.6968 7.7985 31.7286 ;
			RECT 7.8675 31.6968 7.8825 31.7286 ;
			RECT 8.1261 31.6968 8.141 31.7286 ;
		END

		PORT
			 LAYER M4 ;
			RECT 0.2105 42.8889 8.463 42.9365 ;
			 LAYER V3 ;
			RECT 2.3968 42.8968 2.4117 42.9286 ;
			RECT 4.6256 42.8968 4.6405 42.9286 ;
			RECT 4.921 42.8968 4.9359 42.9286 ;
			RECT 5.1795 42.8968 5.1945 42.9286 ;
			RECT 5.2635 42.8968 5.2785 42.9286 ;
			RECT 5.3475 42.8968 5.3625 42.9286 ;
			RECT 5.4315 42.8968 5.4465 42.9286 ;
			RECT 5.5155 42.8968 5.5305 42.9286 ;
			RECT 5.5995 42.8968 5.6145 42.9286 ;
			RECT 5.6835 42.8968 5.6985 42.9286 ;
			RECT 5.7675 42.8968 5.7825 42.9286 ;
			RECT 5.8515 42.8968 5.8665 42.9286 ;
			RECT 5.9355 42.8968 5.9505 42.9286 ;
			RECT 6.0195 42.8968 6.0345 42.9286 ;
			RECT 6.1035 42.8968 6.1185 42.9286 ;
			RECT 6.1875 42.8968 6.2025 42.9286 ;
			RECT 6.2715 42.8968 6.2865 42.9286 ;
			RECT 6.3555 42.8968 6.3705 42.9286 ;
			RECT 6.4395 42.8968 6.4545 42.9286 ;
			RECT 6.5235 42.8968 6.5385 42.9286 ;
			RECT 6.6075 42.8968 6.6225 42.9286 ;
			RECT 6.6915 42.8968 6.7065 42.9286 ;
			RECT 6.7755 42.8968 6.7905 42.9286 ;
			RECT 6.8595 42.8968 6.8745 42.9286 ;
			RECT 6.9435 42.8968 6.9585 42.9286 ;
			RECT 7.0275 42.8968 7.0425 42.9286 ;
			RECT 7.1115 42.8968 7.1265 42.9286 ;
			RECT 7.1955 42.8968 7.2105 42.9286 ;
			RECT 7.2795 42.8968 7.2945 42.9286 ;
			RECT 7.3635 42.8968 7.3785 42.9286 ;
			RECT 7.4475 42.8968 7.4625 42.9286 ;
			RECT 7.5315 42.8968 7.5465 42.9286 ;
			RECT 7.6155 42.8968 7.6305 42.9286 ;
			RECT 7.6995 42.8968 7.7145 42.9286 ;
			RECT 7.7835 42.8968 7.7985 42.9286 ;
			RECT 7.8675 42.8968 7.8825 42.9286 ;
			RECT 8.1261 42.8968 8.141 42.9286 ;
		END

		PORT
			 LAYER M4 ;
			RECT 0.2105 30.8889 8.463 30.9365 ;
			 LAYER V3 ;
			RECT 2.3968 30.8968 2.4117 30.9286 ;
			RECT 4.6256 30.8968 4.6405 30.9286 ;
			RECT 4.921 30.8968 4.9359 30.9286 ;
			RECT 5.1795 30.8968 5.1945 30.9286 ;
			RECT 5.2635 30.8968 5.2785 30.9286 ;
			RECT 5.3475 30.8968 5.3625 30.9286 ;
			RECT 5.4315 30.8968 5.4465 30.9286 ;
			RECT 5.5155 30.8968 5.5305 30.9286 ;
			RECT 5.5995 30.8968 5.6145 30.9286 ;
			RECT 5.6835 30.8968 5.6985 30.9286 ;
			RECT 5.7675 30.8968 5.7825 30.9286 ;
			RECT 5.8515 30.8968 5.8665 30.9286 ;
			RECT 5.9355 30.8968 5.9505 30.9286 ;
			RECT 6.0195 30.8968 6.0345 30.9286 ;
			RECT 6.1035 30.8968 6.1185 30.9286 ;
			RECT 6.1875 30.8968 6.2025 30.9286 ;
			RECT 6.2715 30.8968 6.2865 30.9286 ;
			RECT 6.3555 30.8968 6.3705 30.9286 ;
			RECT 6.4395 30.8968 6.4545 30.9286 ;
			RECT 6.5235 30.8968 6.5385 30.9286 ;
			RECT 6.6075 30.8968 6.6225 30.9286 ;
			RECT 6.6915 30.8968 6.7065 30.9286 ;
			RECT 6.7755 30.8968 6.7905 30.9286 ;
			RECT 6.8595 30.8968 6.8745 30.9286 ;
			RECT 6.9435 30.8968 6.9585 30.9286 ;
			RECT 7.0275 30.8968 7.0425 30.9286 ;
			RECT 7.1115 30.8968 7.1265 30.9286 ;
			RECT 7.1955 30.8968 7.2105 30.9286 ;
			RECT 7.2795 30.8968 7.2945 30.9286 ;
			RECT 7.3635 30.8968 7.3785 30.9286 ;
			RECT 7.4475 30.8968 7.4625 30.9286 ;
			RECT 7.5315 30.8968 7.5465 30.9286 ;
			RECT 7.6155 30.8968 7.6305 30.9286 ;
			RECT 7.6995 30.8968 7.7145 30.9286 ;
			RECT 7.7835 30.8968 7.7985 30.9286 ;
			RECT 7.8675 30.8968 7.8825 30.9286 ;
			RECT 8.1261 30.8968 8.141 30.9286 ;
		END

		PORT
			 LAYER M4 ;
			RECT 0.2105 30.0889 8.463 30.1365 ;
			 LAYER V3 ;
			RECT 2.3968 30.0968 2.4117 30.1286 ;
			RECT 4.6256 30.0968 4.6405 30.1286 ;
			RECT 4.921 30.0968 4.9359 30.1286 ;
			RECT 5.1795 30.0968 5.1945 30.1286 ;
			RECT 5.2635 30.0968 5.2785 30.1286 ;
			RECT 5.3475 30.0968 5.3625 30.1286 ;
			RECT 5.4315 30.0968 5.4465 30.1286 ;
			RECT 5.5155 30.0968 5.5305 30.1286 ;
			RECT 5.5995 30.0968 5.6145 30.1286 ;
			RECT 5.6835 30.0968 5.6985 30.1286 ;
			RECT 5.7675 30.0968 5.7825 30.1286 ;
			RECT 5.8515 30.0968 5.8665 30.1286 ;
			RECT 5.9355 30.0968 5.9505 30.1286 ;
			RECT 6.0195 30.0968 6.0345 30.1286 ;
			RECT 6.1035 30.0968 6.1185 30.1286 ;
			RECT 6.1875 30.0968 6.2025 30.1286 ;
			RECT 6.2715 30.0968 6.2865 30.1286 ;
			RECT 6.3555 30.0968 6.3705 30.1286 ;
			RECT 6.4395 30.0968 6.4545 30.1286 ;
			RECT 6.5235 30.0968 6.5385 30.1286 ;
			RECT 6.6075 30.0968 6.6225 30.1286 ;
			RECT 6.6915 30.0968 6.7065 30.1286 ;
			RECT 6.7755 30.0968 6.7905 30.1286 ;
			RECT 6.8595 30.0968 6.8745 30.1286 ;
			RECT 6.9435 30.0968 6.9585 30.1286 ;
			RECT 7.0275 30.0968 7.0425 30.1286 ;
			RECT 7.1115 30.0968 7.1265 30.1286 ;
			RECT 7.1955 30.0968 7.2105 30.1286 ;
			RECT 7.2795 30.0968 7.2945 30.1286 ;
			RECT 7.3635 30.0968 7.3785 30.1286 ;
			RECT 7.4475 30.0968 7.4625 30.1286 ;
			RECT 7.5315 30.0968 7.5465 30.1286 ;
			RECT 7.6155 30.0968 7.6305 30.1286 ;
			RECT 7.6995 30.0968 7.7145 30.1286 ;
			RECT 7.7835 30.0968 7.7985 30.1286 ;
			RECT 7.8675 30.0968 7.8825 30.1286 ;
			RECT 8.1261 30.0968 8.141 30.1286 ;
		END

		PORT
			 LAYER M4 ;
			RECT 0.2105 29.2889 8.463 29.3365 ;
			 LAYER V3 ;
			RECT 2.3968 29.2968 2.4117 29.3286 ;
			RECT 4.6256 29.2968 4.6405 29.3286 ;
			RECT 4.921 29.2968 4.9359 29.3286 ;
			RECT 5.1795 29.2968 5.1945 29.3286 ;
			RECT 5.2635 29.2968 5.2785 29.3286 ;
			RECT 5.3475 29.2968 5.3625 29.3286 ;
			RECT 5.4315 29.2968 5.4465 29.3286 ;
			RECT 5.5155 29.2968 5.5305 29.3286 ;
			RECT 5.5995 29.2968 5.6145 29.3286 ;
			RECT 5.6835 29.2968 5.6985 29.3286 ;
			RECT 5.7675 29.2968 5.7825 29.3286 ;
			RECT 5.8515 29.2968 5.8665 29.3286 ;
			RECT 5.9355 29.2968 5.9505 29.3286 ;
			RECT 6.0195 29.2968 6.0345 29.3286 ;
			RECT 6.1035 29.2968 6.1185 29.3286 ;
			RECT 6.1875 29.2968 6.2025 29.3286 ;
			RECT 6.2715 29.2968 6.2865 29.3286 ;
			RECT 6.3555 29.2968 6.3705 29.3286 ;
			RECT 6.4395 29.2968 6.4545 29.3286 ;
			RECT 6.5235 29.2968 6.5385 29.3286 ;
			RECT 6.6075 29.2968 6.6225 29.3286 ;
			RECT 6.6915 29.2968 6.7065 29.3286 ;
			RECT 6.7755 29.2968 6.7905 29.3286 ;
			RECT 6.8595 29.2968 6.8745 29.3286 ;
			RECT 6.9435 29.2968 6.9585 29.3286 ;
			RECT 7.0275 29.2968 7.0425 29.3286 ;
			RECT 7.1115 29.2968 7.1265 29.3286 ;
			RECT 7.1955 29.2968 7.2105 29.3286 ;
			RECT 7.2795 29.2968 7.2945 29.3286 ;
			RECT 7.3635 29.2968 7.3785 29.3286 ;
			RECT 7.4475 29.2968 7.4625 29.3286 ;
			RECT 7.5315 29.2968 7.5465 29.3286 ;
			RECT 7.6155 29.2968 7.6305 29.3286 ;
			RECT 7.6995 29.2968 7.7145 29.3286 ;
			RECT 7.7835 29.2968 7.7985 29.3286 ;
			RECT 7.8675 29.2968 7.8825 29.3286 ;
			RECT 8.1261 29.2968 8.141 29.3286 ;
		END

		PORT
			 LAYER M4 ;
			RECT 0.2105 28.4889 8.463 28.5365 ;
			 LAYER V3 ;
			RECT 2.3968 28.4968 2.4117 28.5286 ;
			RECT 4.6256 28.4968 4.6405 28.5286 ;
			RECT 4.921 28.4968 4.9359 28.5286 ;
			RECT 5.1795 28.4968 5.1945 28.5286 ;
			RECT 5.2635 28.4968 5.2785 28.5286 ;
			RECT 5.3475 28.4968 5.3625 28.5286 ;
			RECT 5.4315 28.4968 5.4465 28.5286 ;
			RECT 5.5155 28.4968 5.5305 28.5286 ;
			RECT 5.5995 28.4968 5.6145 28.5286 ;
			RECT 5.6835 28.4968 5.6985 28.5286 ;
			RECT 5.7675 28.4968 5.7825 28.5286 ;
			RECT 5.8515 28.4968 5.8665 28.5286 ;
			RECT 5.9355 28.4968 5.9505 28.5286 ;
			RECT 6.0195 28.4968 6.0345 28.5286 ;
			RECT 6.1035 28.4968 6.1185 28.5286 ;
			RECT 6.1875 28.4968 6.2025 28.5286 ;
			RECT 6.2715 28.4968 6.2865 28.5286 ;
			RECT 6.3555 28.4968 6.3705 28.5286 ;
			RECT 6.4395 28.4968 6.4545 28.5286 ;
			RECT 6.5235 28.4968 6.5385 28.5286 ;
			RECT 6.6075 28.4968 6.6225 28.5286 ;
			RECT 6.6915 28.4968 6.7065 28.5286 ;
			RECT 6.7755 28.4968 6.7905 28.5286 ;
			RECT 6.8595 28.4968 6.8745 28.5286 ;
			RECT 6.9435 28.4968 6.9585 28.5286 ;
			RECT 7.0275 28.4968 7.0425 28.5286 ;
			RECT 7.1115 28.4968 7.1265 28.5286 ;
			RECT 7.1955 28.4968 7.2105 28.5286 ;
			RECT 7.2795 28.4968 7.2945 28.5286 ;
			RECT 7.3635 28.4968 7.3785 28.5286 ;
			RECT 7.4475 28.4968 7.4625 28.5286 ;
			RECT 7.5315 28.4968 7.5465 28.5286 ;
			RECT 7.6155 28.4968 7.6305 28.5286 ;
			RECT 7.6995 28.4968 7.7145 28.5286 ;
			RECT 7.7835 28.4968 7.7985 28.5286 ;
			RECT 7.8675 28.4968 7.8825 28.5286 ;
			RECT 8.1261 28.4968 8.141 28.5286 ;
		END

	END VSSE

	PIN WENY[0]
		USE SIGNAL ;
		DIRECTION OUTPUT ;
		SHAPE ABUTMENT ;
		PORT
			 LAYER M2 ;
			RECT 0.0098 0.7746 0.0481 0.8762 ;
			 LAYER M3 ;
			RECT 0.0098 0.7746 0.0481 0.8762 ;
			 LAYER V2 ;
			RECT 0.021 0.7877 0.0359 0.8004 ;
		END

		ANTENNADIFFAREA 0.00197037 ;
		ANTENNAPARTIALMETALAREA 0.00198 ;
	END WENY[0]

	PIN WENY[10]
		USE SIGNAL ;
		DIRECTION OUTPUT ;
		SHAPE ABUTMENT ;
		PORT
			 LAYER M2 ;
			RECT 0.0098 8.7746 0.0481 8.8762 ;
			 LAYER M3 ;
			RECT 0.0098 8.7746 0.0481 8.8762 ;
			 LAYER V2 ;
			RECT 0.021 8.7877 0.0359 8.8004 ;
		END

		ANTENNADIFFAREA 0.00197037 ;
		ANTENNAPARTIALMETALAREA 0.00198 ;
	END WENY[10]

	PIN WENY[11]
		USE SIGNAL ;
		DIRECTION OUTPUT ;
		SHAPE ABUTMENT ;
		PORT
			 LAYER M2 ;
			RECT 0.0098 9.5746 0.0481 9.6762 ;
			 LAYER M3 ;
			RECT 0.0098 9.5746 0.0481 9.6762 ;
			 LAYER V2 ;
			RECT 0.021 9.5877 0.0359 9.6004 ;
		END

		ANTENNADIFFAREA 0.00197037 ;
		ANTENNAPARTIALMETALAREA 0.00198 ;
	END WENY[11]

	PIN WENY[12]
		USE SIGNAL ;
		DIRECTION OUTPUT ;
		SHAPE ABUTMENT ;
		PORT
			 LAYER M2 ;
			RECT 0.0098 10.3746 0.0481 10.4762 ;
			 LAYER M3 ;
			RECT 0.0098 10.3746 0.0481 10.4762 ;
			 LAYER V2 ;
			RECT 0.021 10.3877 0.0359 10.4004 ;
		END

		ANTENNADIFFAREA 0.00197037 ;
		ANTENNAPARTIALMETALAREA 0.00198 ;
	END WENY[12]

	PIN WENY[13]
		USE SIGNAL ;
		DIRECTION OUTPUT ;
		SHAPE ABUTMENT ;
		PORT
			 LAYER M2 ;
			RECT 0.0098 11.1746 0.0481 11.2762 ;
			 LAYER M3 ;
			RECT 0.0098 11.1746 0.0481 11.2762 ;
			 LAYER V2 ;
			RECT 0.021 11.1877 0.0359 11.2004 ;
		END

		ANTENNADIFFAREA 0.00197037 ;
		ANTENNAPARTIALMETALAREA 0.00198 ;
	END WENY[13]

	PIN WENY[14]
		USE SIGNAL ;
		DIRECTION OUTPUT ;
		SHAPE ABUTMENT ;
		PORT
			 LAYER M2 ;
			RECT 0.0098 11.9746 0.0481 12.0762 ;
			 LAYER M3 ;
			RECT 0.0098 11.9746 0.0481 12.0762 ;
			 LAYER V2 ;
			RECT 0.021 11.9877 0.0359 12.0004 ;
		END

		ANTENNADIFFAREA 0.00197037 ;
		ANTENNAPARTIALMETALAREA 0.00198 ;
	END WENY[14]

	PIN WENY[15]
		USE SIGNAL ;
		DIRECTION OUTPUT ;
		SHAPE ABUTMENT ;
		PORT
			 LAYER M2 ;
			RECT 0.0098 12.7746 0.0481 12.8762 ;
			 LAYER M3 ;
			RECT 0.0098 12.7746 0.0481 12.8762 ;
			 LAYER V2 ;
			RECT 0.021 12.7877 0.0359 12.8004 ;
		END

		ANTENNADIFFAREA 0.00197037 ;
		ANTENNAPARTIALMETALAREA 0.00198 ;
	END WENY[15]

	PIN WENY[16]
		USE SIGNAL ;
		DIRECTION OUTPUT ;
		SHAPE ABUTMENT ;
		PORT
			 LAYER M2 ;
			RECT 0.0098 13.5746 0.0481 13.6762 ;
			 LAYER M3 ;
			RECT 0.0098 13.5746 0.0481 13.6762 ;
			 LAYER V2 ;
			RECT 0.021 13.5877 0.0359 13.6004 ;
		END

		ANTENNADIFFAREA 0.00197037 ;
		ANTENNAPARTIALMETALAREA 0.00198 ;
	END WENY[16]

	PIN WENY[17]
		USE SIGNAL ;
		DIRECTION OUTPUT ;
		SHAPE ABUTMENT ;
		PORT
			 LAYER M2 ;
			RECT 0.0098 14.3746 0.0481 14.4762 ;
			 LAYER M3 ;
			RECT 0.0098 14.3746 0.0481 14.4762 ;
			 LAYER V2 ;
			RECT 0.021 14.3877 0.0359 14.4004 ;
		END

		ANTENNADIFFAREA 0.00197037 ;
		ANTENNAPARTIALMETALAREA 0.00198 ;
	END WENY[17]

	PIN WENY[18]
		USE SIGNAL ;
		DIRECTION OUTPUT ;
		SHAPE ABUTMENT ;
		PORT
			 LAYER M2 ;
			RECT 0.0098 15.1746 0.0481 15.2762 ;
			 LAYER M3 ;
			RECT 0.0098 15.1746 0.0481 15.2762 ;
			 LAYER V2 ;
			RECT 0.021 15.1877 0.0359 15.2004 ;
		END

		ANTENNADIFFAREA 0.00197037 ;
		ANTENNAPARTIALMETALAREA 0.00198 ;
	END WENY[18]

	PIN WENY[19]
		USE SIGNAL ;
		DIRECTION OUTPUT ;
		SHAPE ABUTMENT ;
		PORT
			 LAYER M2 ;
			RECT 0.0098 15.9746 0.0481 16.0762 ;
			 LAYER M3 ;
			RECT 0.0098 15.9746 0.0481 16.0762 ;
			 LAYER V2 ;
			RECT 0.021 15.9877 0.0359 16.0004 ;
		END

		ANTENNADIFFAREA 0.00197037 ;
		ANTENNAPARTIALMETALAREA 0.00198 ;
	END WENY[19]

	PIN WENY[1]
		USE SIGNAL ;
		DIRECTION OUTPUT ;
		SHAPE ABUTMENT ;
		PORT
			 LAYER M2 ;
			RECT 0.0098 1.5746 0.0481 1.6762 ;
			 LAYER M3 ;
			RECT 0.0098 1.5746 0.0481 1.6762 ;
			 LAYER V2 ;
			RECT 0.021 1.5877 0.0359 1.6004 ;
		END

		ANTENNADIFFAREA 0.00197037 ;
		ANTENNAPARTIALMETALAREA 0.00198 ;
	END WENY[1]

	PIN WENY[20]
		USE SIGNAL ;
		DIRECTION OUTPUT ;
		SHAPE ABUTMENT ;
		PORT
			 LAYER M2 ;
			RECT 0.0098 16.7746 0.0481 16.8762 ;
			 LAYER M3 ;
			RECT 0.0098 16.7746 0.0481 16.8762 ;
			 LAYER V2 ;
			RECT 0.021 16.7877 0.0359 16.8004 ;
		END

		ANTENNADIFFAREA 0.00197037 ;
		ANTENNAPARTIALMETALAREA 0.00198 ;
	END WENY[20]

	PIN WENY[21]
		USE SIGNAL ;
		DIRECTION OUTPUT ;
		SHAPE ABUTMENT ;
		PORT
			 LAYER M2 ;
			RECT 0.0098 17.5746 0.0481 17.6762 ;
			 LAYER M3 ;
			RECT 0.0098 17.5746 0.0481 17.6762 ;
			 LAYER V2 ;
			RECT 0.021 17.5877 0.0359 17.6004 ;
		END

		ANTENNADIFFAREA 0.00197037 ;
		ANTENNAPARTIALMETALAREA 0.00198 ;
	END WENY[21]

	PIN WENY[22]
		USE SIGNAL ;
		DIRECTION OUTPUT ;
		SHAPE ABUTMENT ;
		PORT
			 LAYER M2 ;
			RECT 0.0098 25.5048 0.0481 25.6063 ;
			 LAYER M3 ;
			RECT 0.0098 25.5048 0.0481 25.6063 ;
			 LAYER V2 ;
			RECT 0.021 25.5806 0.0359 25.5933 ;
		END

		ANTENNADIFFAREA 0.00197037 ;
		ANTENNAPARTIALMETALAREA 0.00198 ;
	END WENY[22]

	PIN WENY[23]
		USE SIGNAL ;
		DIRECTION OUTPUT ;
		SHAPE ABUTMENT ;
		PORT
			 LAYER M2 ;
			RECT 0.0098 26.3048 0.0481 26.4063 ;
			 LAYER M3 ;
			RECT 0.0098 26.3048 0.0481 26.4063 ;
			 LAYER V2 ;
			RECT 0.021 26.3806 0.0359 26.3933 ;
		END

		ANTENNADIFFAREA 0.00197037 ;
		ANTENNAPARTIALMETALAREA 0.00198 ;
	END WENY[23]

	PIN WENY[24]
		USE SIGNAL ;
		DIRECTION OUTPUT ;
		SHAPE ABUTMENT ;
		PORT
			 LAYER M2 ;
			RECT 0.0098 27.1048 0.0481 27.2063 ;
			 LAYER M3 ;
			RECT 0.0098 27.1048 0.0481 27.2063 ;
			 LAYER V2 ;
			RECT 0.021 27.1806 0.0359 27.1933 ;
		END

		ANTENNADIFFAREA 0.00197037 ;
		ANTENNAPARTIALMETALAREA 0.00198 ;
	END WENY[24]

	PIN WENY[25]
		USE SIGNAL ;
		DIRECTION OUTPUT ;
		SHAPE ABUTMENT ;
		PORT
			 LAYER M2 ;
			RECT 0.0098 27.9048 0.0481 28.0063 ;
			 LAYER M3 ;
			RECT 0.0098 27.9048 0.0481 28.0063 ;
			 LAYER V2 ;
			RECT 0.021 27.9806 0.0359 27.9933 ;
		END

		ANTENNADIFFAREA 0.00197037 ;
		ANTENNAPARTIALMETALAREA 0.00198 ;
	END WENY[25]

	PIN WENY[26]
		USE SIGNAL ;
		DIRECTION OUTPUT ;
		SHAPE ABUTMENT ;
		PORT
			 LAYER M2 ;
			RECT 0.0098 28.7048 0.0481 28.8063 ;
			 LAYER M3 ;
			RECT 0.0098 28.7048 0.0481 28.8063 ;
			 LAYER V2 ;
			RECT 0.021 28.7806 0.0359 28.7933 ;
		END

		ANTENNADIFFAREA 0.00197037 ;
		ANTENNAPARTIALMETALAREA 0.00198 ;
	END WENY[26]

	PIN WENY[27]
		USE SIGNAL ;
		DIRECTION OUTPUT ;
		SHAPE ABUTMENT ;
		PORT
			 LAYER M2 ;
			RECT 0.0098 29.5048 0.0481 29.6063 ;
			 LAYER M3 ;
			RECT 0.0098 29.5048 0.0481 29.6063 ;
			 LAYER V2 ;
			RECT 0.021 29.5806 0.0359 29.5933 ;
		END

		ANTENNADIFFAREA 0.00197037 ;
		ANTENNAPARTIALMETALAREA 0.00198 ;
	END WENY[27]

	PIN WENY[28]
		USE SIGNAL ;
		DIRECTION OUTPUT ;
		SHAPE ABUTMENT ;
		PORT
			 LAYER M2 ;
			RECT 0.0098 30.3048 0.0481 30.4063 ;
			 LAYER M3 ;
			RECT 0.0098 30.3048 0.0481 30.4063 ;
			 LAYER V2 ;
			RECT 0.021 30.3806 0.0359 30.3933 ;
		END

		ANTENNADIFFAREA 0.00197037 ;
		ANTENNAPARTIALMETALAREA 0.00198 ;
	END WENY[28]

	PIN WENY[29]
		USE SIGNAL ;
		DIRECTION OUTPUT ;
		SHAPE ABUTMENT ;
		PORT
			 LAYER M2 ;
			RECT 0.0098 31.1048 0.0481 31.2063 ;
			 LAYER M3 ;
			RECT 0.0098 31.1048 0.0481 31.2063 ;
			 LAYER V2 ;
			RECT 0.021 31.1806 0.0359 31.1933 ;
		END

		ANTENNADIFFAREA 0.00197037 ;
		ANTENNAPARTIALMETALAREA 0.00198 ;
	END WENY[29]

	PIN WENY[2]
		USE SIGNAL ;
		DIRECTION OUTPUT ;
		SHAPE ABUTMENT ;
		PORT
			 LAYER M2 ;
			RECT 0.0098 2.3746 0.0481 2.4762 ;
			 LAYER M3 ;
			RECT 0.0098 2.3746 0.0481 2.4762 ;
			 LAYER V2 ;
			RECT 0.021 2.3877 0.0359 2.4004 ;
		END

		ANTENNADIFFAREA 0.00197037 ;
		ANTENNAPARTIALMETALAREA 0.00198 ;
	END WENY[2]

	PIN WENY[30]
		USE SIGNAL ;
		DIRECTION OUTPUT ;
		SHAPE ABUTMENT ;
		PORT
			 LAYER M2 ;
			RECT 0.0098 31.9048 0.0481 32.0063 ;
			 LAYER M3 ;
			RECT 0.0098 31.9048 0.0481 32.0063 ;
			 LAYER V2 ;
			RECT 0.021 31.9806 0.0359 31.9933 ;
		END

		ANTENNADIFFAREA 0.00197037 ;
		ANTENNAPARTIALMETALAREA 0.00198 ;
	END WENY[30]

	PIN WENY[31]
		USE SIGNAL ;
		DIRECTION OUTPUT ;
		SHAPE ABUTMENT ;
		PORT
			 LAYER M2 ;
			RECT 0.0098 32.7048 0.0481 32.8063 ;
			 LAYER M3 ;
			RECT 0.0098 32.7048 0.0481 32.8063 ;
			 LAYER V2 ;
			RECT 0.021 32.7806 0.0359 32.7933 ;
		END

		ANTENNADIFFAREA 0.00197037 ;
		ANTENNAPARTIALMETALAREA 0.00198 ;
	END WENY[31]

	PIN WENY[32]
		USE SIGNAL ;
		DIRECTION OUTPUT ;
		SHAPE ABUTMENT ;
		PORT
			 LAYER M2 ;
			RECT 0.0098 33.5048 0.0481 33.6063 ;
			 LAYER M3 ;
			RECT 0.0098 33.5048 0.0481 33.6063 ;
			 LAYER V2 ;
			RECT 0.021 33.5806 0.0359 33.5933 ;
		END

		ANTENNADIFFAREA 0.00197037 ;
		ANTENNAPARTIALMETALAREA 0.00198 ;
	END WENY[32]

	PIN WENY[33]
		USE SIGNAL ;
		DIRECTION OUTPUT ;
		SHAPE ABUTMENT ;
		PORT
			 LAYER M2 ;
			RECT 0.0098 34.3048 0.0481 34.4063 ;
			 LAYER M3 ;
			RECT 0.0098 34.3048 0.0481 34.4063 ;
			 LAYER V2 ;
			RECT 0.021 34.3806 0.0359 34.3933 ;
		END

		ANTENNADIFFAREA 0.00197037 ;
		ANTENNAPARTIALMETALAREA 0.00198 ;
	END WENY[33]

	PIN WENY[34]
		USE SIGNAL ;
		DIRECTION OUTPUT ;
		SHAPE ABUTMENT ;
		PORT
			 LAYER M2 ;
			RECT 0.0098 35.1048 0.0481 35.2063 ;
			 LAYER M3 ;
			RECT 0.0098 35.1048 0.0481 35.2063 ;
			 LAYER V2 ;
			RECT 0.021 35.1806 0.0359 35.1933 ;
		END

		ANTENNADIFFAREA 0.00197037 ;
		ANTENNAPARTIALMETALAREA 0.00198 ;
	END WENY[34]

	PIN WENY[35]
		USE SIGNAL ;
		DIRECTION OUTPUT ;
		SHAPE ABUTMENT ;
		PORT
			 LAYER M2 ;
			RECT 0.0098 35.9048 0.0481 36.0063 ;
			 LAYER M3 ;
			RECT 0.0098 35.9048 0.0481 36.0063 ;
			 LAYER V2 ;
			RECT 0.021 35.9806 0.0359 35.9933 ;
		END

		ANTENNADIFFAREA 0.00197037 ;
		ANTENNAPARTIALMETALAREA 0.00198 ;
	END WENY[35]

	PIN WENY[36]
		USE SIGNAL ;
		DIRECTION OUTPUT ;
		SHAPE ABUTMENT ;
		PORT
			 LAYER M2 ;
			RECT 0.0098 36.7048 0.0481 36.8063 ;
			 LAYER M3 ;
			RECT 0.0098 36.7048 0.0481 36.8063 ;
			 LAYER V2 ;
			RECT 0.021 36.7806 0.0359 36.7933 ;
		END

		ANTENNADIFFAREA 0.00197037 ;
		ANTENNAPARTIALMETALAREA 0.00198 ;
	END WENY[36]

	PIN WENY[37]
		USE SIGNAL ;
		DIRECTION OUTPUT ;
		SHAPE ABUTMENT ;
		PORT
			 LAYER M2 ;
			RECT 0.0098 37.5048 0.0481 37.6063 ;
			 LAYER M3 ;
			RECT 0.0098 37.5048 0.0481 37.6063 ;
			 LAYER V2 ;
			RECT 0.021 37.5806 0.0359 37.5933 ;
		END

		ANTENNADIFFAREA 0.00197037 ;
		ANTENNAPARTIALMETALAREA 0.00198 ;
	END WENY[37]

	PIN WENY[38]
		USE SIGNAL ;
		DIRECTION OUTPUT ;
		SHAPE ABUTMENT ;
		PORT
			 LAYER M2 ;
			RECT 0.0098 38.3048 0.0481 38.4063 ;
			 LAYER M3 ;
			RECT 0.0098 38.3048 0.0481 38.4063 ;
			 LAYER V2 ;
			RECT 0.021 38.3806 0.0359 38.3933 ;
		END

		ANTENNADIFFAREA 0.00197037 ;
		ANTENNAPARTIALMETALAREA 0.00198 ;
	END WENY[38]

	PIN WENY[39]
		USE SIGNAL ;
		DIRECTION OUTPUT ;
		SHAPE ABUTMENT ;
		PORT
			 LAYER M2 ;
			RECT 0.0098 39.1048 0.0481 39.2063 ;
			 LAYER M3 ;
			RECT 0.0098 39.1048 0.0481 39.2063 ;
			 LAYER V2 ;
			RECT 0.021 39.1806 0.0359 39.1933 ;
		END

		ANTENNADIFFAREA 0.00197037 ;
		ANTENNAPARTIALMETALAREA 0.00198 ;
	END WENY[39]

	PIN WENY[3]
		USE SIGNAL ;
		DIRECTION OUTPUT ;
		SHAPE ABUTMENT ;
		PORT
			 LAYER M2 ;
			RECT 0.0098 3.1746 0.0481 3.2762 ;
			 LAYER M3 ;
			RECT 0.0098 3.1746 0.0481 3.2762 ;
			 LAYER V2 ;
			RECT 0.021 3.1877 0.0359 3.2004 ;
		END

		ANTENNADIFFAREA 0.00197037 ;
		ANTENNAPARTIALMETALAREA 0.00198 ;
	END WENY[3]

	PIN WENY[40]
		USE SIGNAL ;
		DIRECTION OUTPUT ;
		SHAPE ABUTMENT ;
		PORT
			 LAYER M2 ;
			RECT 0.0098 39.9048 0.0481 40.0063 ;
			 LAYER M3 ;
			RECT 0.0098 39.9048 0.0481 40.0063 ;
			 LAYER V2 ;
			RECT 0.021 39.9806 0.0359 39.9933 ;
		END

		ANTENNADIFFAREA 0.00197037 ;
		ANTENNAPARTIALMETALAREA 0.00198 ;
	END WENY[40]

	PIN WENY[41]
		USE SIGNAL ;
		DIRECTION OUTPUT ;
		SHAPE ABUTMENT ;
		PORT
			 LAYER M2 ;
			RECT 0.0098 40.7048 0.0481 40.8063 ;
			 LAYER M3 ;
			RECT 0.0098 40.7048 0.0481 40.8063 ;
			 LAYER V2 ;
			RECT 0.021 40.7806 0.0359 40.7933 ;
		END

		ANTENNADIFFAREA 0.00197037 ;
		ANTENNAPARTIALMETALAREA 0.00198 ;
	END WENY[41]

	PIN WENY[42]
		USE SIGNAL ;
		DIRECTION OUTPUT ;
		SHAPE ABUTMENT ;
		PORT
			 LAYER M2 ;
			RECT 0.0098 41.5048 0.0481 41.6063 ;
			 LAYER M3 ;
			RECT 0.0098 41.5048 0.0481 41.6063 ;
			 LAYER V2 ;
			RECT 0.021 41.5806 0.0359 41.5933 ;
		END

		ANTENNADIFFAREA 0.00197037 ;
		ANTENNAPARTIALMETALAREA 0.00198 ;
	END WENY[42]

	PIN WENY[43]
		USE SIGNAL ;
		DIRECTION OUTPUT ;
		SHAPE ABUTMENT ;
		PORT
			 LAYER M2 ;
			RECT 0.0098 42.3048 0.0481 42.4063 ;
			 LAYER M3 ;
			RECT 0.0098 42.3048 0.0481 42.4063 ;
			 LAYER V2 ;
			RECT 0.021 42.3806 0.0359 42.3933 ;
		END

		ANTENNADIFFAREA 0.00197037 ;
		ANTENNAPARTIALMETALAREA 0.00198 ;
	END WENY[43]

	PIN WENY[44]
		USE SIGNAL ;
		DIRECTION OUTPUT ;
		SHAPE ABUTMENT ;
		PORT
			 LAYER M2 ;
			RECT 0.0098 43.1048 0.0481 43.2063 ;
			 LAYER M3 ;
			RECT 0.0098 43.1048 0.0481 43.2063 ;
			 LAYER V2 ;
			RECT 0.021 43.1806 0.0359 43.1933 ;
		END

		ANTENNADIFFAREA 0.00197037 ;
		ANTENNAPARTIALMETALAREA 0.00198 ;
	END WENY[44]

	PIN WENY[4]
		USE SIGNAL ;
		DIRECTION OUTPUT ;
		SHAPE ABUTMENT ;
		PORT
			 LAYER M2 ;
			RECT 0.0098 3.9746 0.0481 4.0762 ;
			 LAYER M3 ;
			RECT 0.0098 3.9746 0.0481 4.0762 ;
			 LAYER V2 ;
			RECT 0.021 3.9877 0.0359 4.0004 ;
		END

		ANTENNADIFFAREA 0.00197037 ;
		ANTENNAPARTIALMETALAREA 0.00198 ;
	END WENY[4]

	PIN WENY[5]
		USE SIGNAL ;
		DIRECTION OUTPUT ;
		SHAPE ABUTMENT ;
		PORT
			 LAYER M2 ;
			RECT 0.0098 4.7746 0.0481 4.8762 ;
			 LAYER M3 ;
			RECT 0.0098 4.7746 0.0481 4.8762 ;
			 LAYER V2 ;
			RECT 0.021 4.7877 0.0359 4.8004 ;
		END

		ANTENNADIFFAREA 0.00197037 ;
		ANTENNAPARTIALMETALAREA 0.00198 ;
	END WENY[5]

	PIN WENY[6]
		USE SIGNAL ;
		DIRECTION OUTPUT ;
		SHAPE ABUTMENT ;
		PORT
			 LAYER M2 ;
			RECT 0.0098 5.5746 0.0481 5.6762 ;
			 LAYER M3 ;
			RECT 0.0098 5.5746 0.0481 5.6762 ;
			 LAYER V2 ;
			RECT 0.021 5.5877 0.0359 5.6004 ;
		END

		ANTENNADIFFAREA 0.00197037 ;
		ANTENNAPARTIALMETALAREA 0.00198 ;
	END WENY[6]

	PIN WENY[7]
		USE SIGNAL ;
		DIRECTION OUTPUT ;
		SHAPE ABUTMENT ;
		PORT
			 LAYER M2 ;
			RECT 0.0098 6.3746 0.0481 6.4762 ;
			 LAYER M3 ;
			RECT 0.0098 6.3746 0.0481 6.4762 ;
			 LAYER V2 ;
			RECT 0.021 6.3877 0.0359 6.4004 ;
		END

		ANTENNADIFFAREA 0.00197037 ;
		ANTENNAPARTIALMETALAREA 0.00198 ;
	END WENY[7]

	PIN WENY[8]
		USE SIGNAL ;
		DIRECTION OUTPUT ;
		SHAPE ABUTMENT ;
		PORT
			 LAYER M2 ;
			RECT 0.0098 7.1746 0.0481 7.2762 ;
			 LAYER M3 ;
			RECT 0.0098 7.1746 0.0481 7.2762 ;
			 LAYER V2 ;
			RECT 0.021 7.1877 0.0359 7.2004 ;
		END

		ANTENNADIFFAREA 0.00197037 ;
		ANTENNAPARTIALMETALAREA 0.00198 ;
	END WENY[8]

	PIN WENY[9]
		USE SIGNAL ;
		DIRECTION OUTPUT ;
		SHAPE ABUTMENT ;
		PORT
			 LAYER M2 ;
			RECT 0.0098 7.9746 0.0481 8.0762 ;
			 LAYER M3 ;
			RECT 0.0098 7.9746 0.0481 8.0762 ;
			 LAYER V2 ;
			RECT 0.021 7.9877 0.0359 8.0004 ;
		END

		ANTENNADIFFAREA 0.00197037 ;
		ANTENNAPARTIALMETALAREA 0.00198 ;
	END WENY[9]

	PIN WEN[0]
		USE SIGNAL ;
		DIRECTION INPUT ;
		SHAPE ABUTMENT ;
		PORT
			 LAYER M2 ;
			RECT 0.0098 0.9016 0.0481 1.0032 ;
			 LAYER M3 ;
			RECT 0.0098 0.9016 0.0481 1.0032 ;
			 LAYER V2 ;
			RECT 0.021 0.9774 0.0359 0.9901 ;
		END

		ANTENNAGATEAREA 0.00028148 ;
		ANTENNADIFFAREA 0.00197037 ;
		ANTENNAPARTIALMETALAREA 0.00198 ;
	END WEN[0]

	PIN WEN[10]
		USE SIGNAL ;
		DIRECTION INPUT ;
		SHAPE ABUTMENT ;
		PORT
			 LAYER M2 ;
			RECT 0.0098 8.9016 0.0481 9.0032 ;
			 LAYER M3 ;
			RECT 0.0098 8.9016 0.0481 9.0032 ;
			 LAYER V2 ;
			RECT 0.021 8.9774 0.0359 8.9901 ;
		END

		ANTENNAGATEAREA 0.00028148 ;
		ANTENNADIFFAREA 0.00197037 ;
		ANTENNAPARTIALMETALAREA 0.00198 ;
	END WEN[10]

	PIN WEN[11]
		USE SIGNAL ;
		DIRECTION INPUT ;
		SHAPE ABUTMENT ;
		PORT
			 LAYER M2 ;
			RECT 0.0098 9.7016 0.0481 9.8032 ;
			 LAYER M3 ;
			RECT 0.0098 9.7016 0.0481 9.8032 ;
			 LAYER V2 ;
			RECT 0.021 9.7774 0.0359 9.7901 ;
		END

		ANTENNAGATEAREA 0.00028148 ;
		ANTENNADIFFAREA 0.00197037 ;
		ANTENNAPARTIALMETALAREA 0.00198 ;
	END WEN[11]

	PIN WEN[12]
		USE SIGNAL ;
		DIRECTION INPUT ;
		SHAPE ABUTMENT ;
		PORT
			 LAYER M2 ;
			RECT 0.0098 10.5016 0.0481 10.6032 ;
			 LAYER M3 ;
			RECT 0.0098 10.5016 0.0481 10.6032 ;
			 LAYER V2 ;
			RECT 0.021 10.5774 0.0359 10.5901 ;
		END

		ANTENNAGATEAREA 0.00028148 ;
		ANTENNADIFFAREA 0.00197037 ;
		ANTENNAPARTIALMETALAREA 0.00198 ;
	END WEN[12]

	PIN WEN[13]
		USE SIGNAL ;
		DIRECTION INPUT ;
		SHAPE ABUTMENT ;
		PORT
			 LAYER M2 ;
			RECT 0.0098 11.3016 0.0481 11.4032 ;
			 LAYER M3 ;
			RECT 0.0098 11.3016 0.0481 11.4032 ;
			 LAYER V2 ;
			RECT 0.021 11.3774 0.0359 11.3901 ;
		END

		ANTENNAGATEAREA 0.00028148 ;
		ANTENNADIFFAREA 0.00197037 ;
		ANTENNAPARTIALMETALAREA 0.00198 ;
	END WEN[13]

	PIN WEN[14]
		USE SIGNAL ;
		DIRECTION INPUT ;
		SHAPE ABUTMENT ;
		PORT
			 LAYER M2 ;
			RECT 0.0098 12.1016 0.0481 12.2032 ;
			 LAYER M3 ;
			RECT 0.0098 12.1016 0.0481 12.2032 ;
			 LAYER V2 ;
			RECT 0.021 12.1774 0.0359 12.1901 ;
		END

		ANTENNAGATEAREA 0.00028148 ;
		ANTENNADIFFAREA 0.00197037 ;
		ANTENNAPARTIALMETALAREA 0.00198 ;
	END WEN[14]

	PIN WEN[15]
		USE SIGNAL ;
		DIRECTION INPUT ;
		SHAPE ABUTMENT ;
		PORT
			 LAYER M2 ;
			RECT 0.0098 12.9016 0.0481 13.0032 ;
			 LAYER M3 ;
			RECT 0.0098 12.9016 0.0481 13.0032 ;
			 LAYER V2 ;
			RECT 0.021 12.9774 0.0359 12.9901 ;
		END

		ANTENNAGATEAREA 0.00028148 ;
		ANTENNADIFFAREA 0.00197037 ;
		ANTENNAPARTIALMETALAREA 0.00198 ;
	END WEN[15]

	PIN WEN[16]
		USE SIGNAL ;
		DIRECTION INPUT ;
		SHAPE ABUTMENT ;
		PORT
			 LAYER M2 ;
			RECT 0.0098 13.7016 0.0481 13.8032 ;
			 LAYER M3 ;
			RECT 0.0098 13.7016 0.0481 13.8032 ;
			 LAYER V2 ;
			RECT 0.021 13.7774 0.0359 13.7901 ;
		END

		ANTENNAGATEAREA 0.00028148 ;
		ANTENNADIFFAREA 0.00197037 ;
		ANTENNAPARTIALMETALAREA 0.00198 ;
	END WEN[16]

	PIN WEN[17]
		USE SIGNAL ;
		DIRECTION INPUT ;
		SHAPE ABUTMENT ;
		PORT
			 LAYER M2 ;
			RECT 0.0098 14.5016 0.0481 14.6032 ;
			 LAYER M3 ;
			RECT 0.0098 14.5016 0.0481 14.6032 ;
			 LAYER V2 ;
			RECT 0.021 14.5774 0.0359 14.5901 ;
		END

		ANTENNAGATEAREA 0.00028148 ;
		ANTENNADIFFAREA 0.00197037 ;
		ANTENNAPARTIALMETALAREA 0.00198 ;
	END WEN[17]

	PIN WEN[18]
		USE SIGNAL ;
		DIRECTION INPUT ;
		SHAPE ABUTMENT ;
		PORT
			 LAYER M2 ;
			RECT 0.0098 15.3016 0.0481 15.4032 ;
			 LAYER M3 ;
			RECT 0.0098 15.3016 0.0481 15.4032 ;
			 LAYER V2 ;
			RECT 0.021 15.3774 0.0359 15.3901 ;
		END

		ANTENNAGATEAREA 0.00028148 ;
		ANTENNADIFFAREA 0.00197037 ;
		ANTENNAPARTIALMETALAREA 0.00198 ;
	END WEN[18]

	PIN WEN[19]
		USE SIGNAL ;
		DIRECTION INPUT ;
		SHAPE ABUTMENT ;
		PORT
			 LAYER M2 ;
			RECT 0.0098 16.1016 0.0481 16.2032 ;
			 LAYER M3 ;
			RECT 0.0098 16.1016 0.0481 16.2032 ;
			 LAYER V2 ;
			RECT 0.021 16.1774 0.0359 16.1901 ;
		END

		ANTENNAGATEAREA 0.00028148 ;
		ANTENNADIFFAREA 0.00197037 ;
		ANTENNAPARTIALMETALAREA 0.00198 ;
	END WEN[19]

	PIN WEN[1]
		USE SIGNAL ;
		DIRECTION INPUT ;
		SHAPE ABUTMENT ;
		PORT
			 LAYER M2 ;
			RECT 0.0098 1.7016 0.0481 1.8032 ;
			 LAYER M3 ;
			RECT 0.0098 1.7016 0.0481 1.8032 ;
			 LAYER V2 ;
			RECT 0.021 1.7774 0.0359 1.7901 ;
		END

		ANTENNAGATEAREA 0.00028148 ;
		ANTENNADIFFAREA 0.00197037 ;
		ANTENNAPARTIALMETALAREA 0.00198 ;
	END WEN[1]

	PIN WEN[20]
		USE SIGNAL ;
		DIRECTION INPUT ;
		SHAPE ABUTMENT ;
		PORT
			 LAYER M2 ;
			RECT 0.0098 16.9016 0.0481 17.0032 ;
			 LAYER M3 ;
			RECT 0.0098 16.9016 0.0481 17.0032 ;
			 LAYER V2 ;
			RECT 0.021 16.9774 0.0359 16.9901 ;
		END

		ANTENNAGATEAREA 0.00028148 ;
		ANTENNADIFFAREA 0.00197037 ;
		ANTENNAPARTIALMETALAREA 0.00198 ;
	END WEN[20]

	PIN WEN[21]
		USE SIGNAL ;
		DIRECTION INPUT ;
		SHAPE ABUTMENT ;
		PORT
			 LAYER M2 ;
			RECT 0.0098 17.7016 0.0481 17.8032 ;
			 LAYER M3 ;
			RECT 0.0098 17.7016 0.0481 17.8032 ;
			 LAYER V2 ;
			RECT 0.021 17.7774 0.0359 17.7901 ;
		END

		ANTENNAGATEAREA 0.00028148 ;
		ANTENNADIFFAREA 0.00197037 ;
		ANTENNAPARTIALMETALAREA 0.00198 ;
	END WEN[21]

	PIN WEN[22]
		USE SIGNAL ;
		DIRECTION INPUT ;
		SHAPE ABUTMENT ;
		PORT
			 LAYER M2 ;
			RECT 0.0098 25.3778 0.0481 25.4794 ;
			 LAYER M3 ;
			RECT 0.0098 25.3778 0.0481 25.4794 ;
			 LAYER V2 ;
			RECT 0.021 25.3909 0.0359 25.4036 ;
		END

		ANTENNAGATEAREA 0.00028148 ;
		ANTENNADIFFAREA 0.00197037 ;
		ANTENNAPARTIALMETALAREA 0.00198 ;
	END WEN[22]

	PIN WEN[23]
		USE SIGNAL ;
		DIRECTION INPUT ;
		SHAPE ABUTMENT ;
		PORT
			 LAYER M2 ;
			RECT 0.0098 26.1778 0.0481 26.2794 ;
			 LAYER M3 ;
			RECT 0.0098 26.1778 0.0481 26.2794 ;
			 LAYER V2 ;
			RECT 0.021 26.1909 0.0359 26.2036 ;
		END

		ANTENNAGATEAREA 0.00028148 ;
		ANTENNADIFFAREA 0.00197037 ;
		ANTENNAPARTIALMETALAREA 0.00198 ;
	END WEN[23]

	PIN WEN[24]
		USE SIGNAL ;
		DIRECTION INPUT ;
		SHAPE ABUTMENT ;
		PORT
			 LAYER M2 ;
			RECT 0.0098 26.9778 0.0481 27.0794 ;
			 LAYER M3 ;
			RECT 0.0098 26.9778 0.0481 27.0794 ;
			 LAYER V2 ;
			RECT 0.021 26.9909 0.0359 27.0036 ;
		END

		ANTENNAGATEAREA 0.00028148 ;
		ANTENNADIFFAREA 0.00197037 ;
		ANTENNAPARTIALMETALAREA 0.00198 ;
	END WEN[24]

	PIN WEN[25]
		USE SIGNAL ;
		DIRECTION INPUT ;
		SHAPE ABUTMENT ;
		PORT
			 LAYER M2 ;
			RECT 0.0098 27.7778 0.0481 27.8794 ;
			 LAYER M3 ;
			RECT 0.0098 27.7778 0.0481 27.8794 ;
			 LAYER V2 ;
			RECT 0.021 27.7909 0.0359 27.8036 ;
		END

		ANTENNAGATEAREA 0.00028148 ;
		ANTENNADIFFAREA 0.00197037 ;
		ANTENNAPARTIALMETALAREA 0.00198 ;
	END WEN[25]

	PIN WEN[26]
		USE SIGNAL ;
		DIRECTION INPUT ;
		SHAPE ABUTMENT ;
		PORT
			 LAYER M2 ;
			RECT 0.0098 28.5778 0.0481 28.6794 ;
			 LAYER M3 ;
			RECT 0.0098 28.5778 0.0481 28.6794 ;
			 LAYER V2 ;
			RECT 0.021 28.5909 0.0359 28.6036 ;
		END

		ANTENNAGATEAREA 0.00028148 ;
		ANTENNADIFFAREA 0.00197037 ;
		ANTENNAPARTIALMETALAREA 0.00198 ;
	END WEN[26]

	PIN WEN[27]
		USE SIGNAL ;
		DIRECTION INPUT ;
		SHAPE ABUTMENT ;
		PORT
			 LAYER M2 ;
			RECT 0.0098 29.3778 0.0481 29.4794 ;
			 LAYER M3 ;
			RECT 0.0098 29.3778 0.0481 29.4794 ;
			 LAYER V2 ;
			RECT 0.021 29.3909 0.0359 29.4036 ;
		END

		ANTENNAGATEAREA 0.00028148 ;
		ANTENNADIFFAREA 0.00197037 ;
		ANTENNAPARTIALMETALAREA 0.00198 ;
	END WEN[27]

	PIN WEN[28]
		USE SIGNAL ;
		DIRECTION INPUT ;
		SHAPE ABUTMENT ;
		PORT
			 LAYER M2 ;
			RECT 0.0098 30.1778 0.0481 30.2794 ;
			 LAYER M3 ;
			RECT 0.0098 30.1778 0.0481 30.2794 ;
			 LAYER V2 ;
			RECT 0.021 30.1909 0.0359 30.2036 ;
		END

		ANTENNAGATEAREA 0.00028148 ;
		ANTENNADIFFAREA 0.00197037 ;
		ANTENNAPARTIALMETALAREA 0.00198 ;
	END WEN[28]

	PIN WEN[29]
		USE SIGNAL ;
		DIRECTION INPUT ;
		SHAPE ABUTMENT ;
		PORT
			 LAYER M2 ;
			RECT 0.0098 30.9778 0.0481 31.0794 ;
			 LAYER M3 ;
			RECT 0.0098 30.9778 0.0481 31.0794 ;
			 LAYER V2 ;
			RECT 0.021 30.9909 0.0359 31.0036 ;
		END

		ANTENNAGATEAREA 0.00028148 ;
		ANTENNADIFFAREA 0.00197037 ;
		ANTENNAPARTIALMETALAREA 0.00198 ;
	END WEN[29]

	PIN WEN[2]
		USE SIGNAL ;
		DIRECTION INPUT ;
		SHAPE ABUTMENT ;
		PORT
			 LAYER M2 ;
			RECT 0.0098 2.5016 0.0481 2.6032 ;
			 LAYER M3 ;
			RECT 0.0098 2.5016 0.0481 2.6032 ;
			 LAYER V2 ;
			RECT 0.021 2.5774 0.0359 2.5901 ;
		END

		ANTENNAGATEAREA 0.00028148 ;
		ANTENNADIFFAREA 0.00197037 ;
		ANTENNAPARTIALMETALAREA 0.00198 ;
	END WEN[2]

	PIN WEN[30]
		USE SIGNAL ;
		DIRECTION INPUT ;
		SHAPE ABUTMENT ;
		PORT
			 LAYER M2 ;
			RECT 0.0098 31.7778 0.0481 31.8794 ;
			 LAYER M3 ;
			RECT 0.0098 31.7778 0.0481 31.8794 ;
			 LAYER V2 ;
			RECT 0.021 31.7909 0.0359 31.8036 ;
		END

		ANTENNAGATEAREA 0.00028148 ;
		ANTENNADIFFAREA 0.00197037 ;
		ANTENNAPARTIALMETALAREA 0.00198 ;
	END WEN[30]

	PIN WEN[31]
		USE SIGNAL ;
		DIRECTION INPUT ;
		SHAPE ABUTMENT ;
		PORT
			 LAYER M2 ;
			RECT 0.0098 32.5778 0.0481 32.6794 ;
			 LAYER M3 ;
			RECT 0.0098 32.5778 0.0481 32.6794 ;
			 LAYER V2 ;
			RECT 0.021 32.5909 0.0359 32.6036 ;
		END

		ANTENNAGATEAREA 0.00028148 ;
		ANTENNADIFFAREA 0.00197037 ;
		ANTENNAPARTIALMETALAREA 0.00198 ;
	END WEN[31]

	PIN WEN[32]
		USE SIGNAL ;
		DIRECTION INPUT ;
		SHAPE ABUTMENT ;
		PORT
			 LAYER M2 ;
			RECT 0.0098 33.3778 0.0481 33.4794 ;
			 LAYER M3 ;
			RECT 0.0098 33.3778 0.0481 33.4794 ;
			 LAYER V2 ;
			RECT 0.021 33.3909 0.0359 33.4036 ;
		END

		ANTENNAGATEAREA 0.00028148 ;
		ANTENNADIFFAREA 0.00197037 ;
		ANTENNAPARTIALMETALAREA 0.00198 ;
	END WEN[32]

	PIN WEN[33]
		USE SIGNAL ;
		DIRECTION INPUT ;
		SHAPE ABUTMENT ;
		PORT
			 LAYER M2 ;
			RECT 0.0098 34.1778 0.0481 34.2794 ;
			 LAYER M3 ;
			RECT 0.0098 34.1778 0.0481 34.2794 ;
			 LAYER V2 ;
			RECT 0.021 34.1909 0.0359 34.2036 ;
		END

		ANTENNAGATEAREA 0.00028148 ;
		ANTENNADIFFAREA 0.00197037 ;
		ANTENNAPARTIALMETALAREA 0.00198 ;
	END WEN[33]

	PIN WEN[34]
		USE SIGNAL ;
		DIRECTION INPUT ;
		SHAPE ABUTMENT ;
		PORT
			 LAYER M2 ;
			RECT 0.0098 34.9778 0.0481 35.0794 ;
			 LAYER M3 ;
			RECT 0.0098 34.9778 0.0481 35.0794 ;
			 LAYER V2 ;
			RECT 0.021 34.9909 0.0359 35.0036 ;
		END

		ANTENNAGATEAREA 0.00028148 ;
		ANTENNADIFFAREA 0.00197037 ;
		ANTENNAPARTIALMETALAREA 0.00198 ;
	END WEN[34]

	PIN WEN[35]
		USE SIGNAL ;
		DIRECTION INPUT ;
		SHAPE ABUTMENT ;
		PORT
			 LAYER M2 ;
			RECT 0.0098 35.7778 0.0481 35.8794 ;
			 LAYER M3 ;
			RECT 0.0098 35.7778 0.0481 35.8794 ;
			 LAYER V2 ;
			RECT 0.021 35.7909 0.0359 35.8036 ;
		END

		ANTENNAGATEAREA 0.00028148 ;
		ANTENNADIFFAREA 0.00197037 ;
		ANTENNAPARTIALMETALAREA 0.00198 ;
	END WEN[35]

	PIN WEN[36]
		USE SIGNAL ;
		DIRECTION INPUT ;
		SHAPE ABUTMENT ;
		PORT
			 LAYER M2 ;
			RECT 0.0098 36.5778 0.0481 36.6794 ;
			 LAYER M3 ;
			RECT 0.0098 36.5778 0.0481 36.6794 ;
			 LAYER V2 ;
			RECT 0.021 36.5909 0.0359 36.6036 ;
		END

		ANTENNAGATEAREA 0.00028148 ;
		ANTENNADIFFAREA 0.00197037 ;
		ANTENNAPARTIALMETALAREA 0.00198 ;
	END WEN[36]

	PIN WEN[37]
		USE SIGNAL ;
		DIRECTION INPUT ;
		SHAPE ABUTMENT ;
		PORT
			 LAYER M2 ;
			RECT 0.0098 37.3778 0.0481 37.4794 ;
			 LAYER M3 ;
			RECT 0.0098 37.3778 0.0481 37.4794 ;
			 LAYER V2 ;
			RECT 0.021 37.3909 0.0359 37.4036 ;
		END

		ANTENNAGATEAREA 0.00028148 ;
		ANTENNADIFFAREA 0.00197037 ;
		ANTENNAPARTIALMETALAREA 0.00198 ;
	END WEN[37]

	PIN WEN[38]
		USE SIGNAL ;
		DIRECTION INPUT ;
		SHAPE ABUTMENT ;
		PORT
			 LAYER M2 ;
			RECT 0.0098 38.1778 0.0481 38.2794 ;
			 LAYER M3 ;
			RECT 0.0098 38.1778 0.0481 38.2794 ;
			 LAYER V2 ;
			RECT 0.021 38.1909 0.0359 38.2036 ;
		END

		ANTENNAGATEAREA 0.00028148 ;
		ANTENNADIFFAREA 0.00197037 ;
		ANTENNAPARTIALMETALAREA 0.00198 ;
	END WEN[38]

	PIN WEN[39]
		USE SIGNAL ;
		DIRECTION INPUT ;
		SHAPE ABUTMENT ;
		PORT
			 LAYER M2 ;
			RECT 0.0098 38.9778 0.0481 39.0794 ;
			 LAYER M3 ;
			RECT 0.0098 38.9778 0.0481 39.0794 ;
			 LAYER V2 ;
			RECT 0.021 38.9909 0.0359 39.0036 ;
		END

		ANTENNAGATEAREA 0.00028148 ;
		ANTENNADIFFAREA 0.00197037 ;
		ANTENNAPARTIALMETALAREA 0.00198 ;
	END WEN[39]

	PIN WEN[3]
		USE SIGNAL ;
		DIRECTION INPUT ;
		SHAPE ABUTMENT ;
		PORT
			 LAYER M2 ;
			RECT 0.0098 3.3016 0.0481 3.4032 ;
			 LAYER M3 ;
			RECT 0.0098 3.3016 0.0481 3.4032 ;
			 LAYER V2 ;
			RECT 0.021 3.3774 0.0359 3.3901 ;
		END

		ANTENNAGATEAREA 0.00028148 ;
		ANTENNADIFFAREA 0.00197037 ;
		ANTENNAPARTIALMETALAREA 0.00198 ;
	END WEN[3]

	PIN WEN[40]
		USE SIGNAL ;
		DIRECTION INPUT ;
		SHAPE ABUTMENT ;
		PORT
			 LAYER M2 ;
			RECT 0.0098 39.7778 0.0481 39.8794 ;
			 LAYER M3 ;
			RECT 0.0098 39.7778 0.0481 39.8794 ;
			 LAYER V2 ;
			RECT 0.021 39.7909 0.0359 39.8036 ;
		END

		ANTENNAGATEAREA 0.00028148 ;
		ANTENNADIFFAREA 0.00197037 ;
		ANTENNAPARTIALMETALAREA 0.00198 ;
	END WEN[40]

	PIN WEN[41]
		USE SIGNAL ;
		DIRECTION INPUT ;
		SHAPE ABUTMENT ;
		PORT
			 LAYER M2 ;
			RECT 0.0098 40.5778 0.0481 40.6794 ;
			 LAYER M3 ;
			RECT 0.0098 40.5778 0.0481 40.6794 ;
			 LAYER V2 ;
			RECT 0.021 40.5909 0.0359 40.6036 ;
		END

		ANTENNAGATEAREA 0.00028148 ;
		ANTENNADIFFAREA 0.00197037 ;
		ANTENNAPARTIALMETALAREA 0.00198 ;
	END WEN[41]

	PIN WEN[42]
		USE SIGNAL ;
		DIRECTION INPUT ;
		SHAPE ABUTMENT ;
		PORT
			 LAYER M2 ;
			RECT 0.0098 41.3778 0.0481 41.4794 ;
			 LAYER M3 ;
			RECT 0.0098 41.3778 0.0481 41.4794 ;
			 LAYER V2 ;
			RECT 0.021 41.3909 0.0359 41.4036 ;
		END

		ANTENNAGATEAREA 0.00028148 ;
		ANTENNADIFFAREA 0.00197037 ;
		ANTENNAPARTIALMETALAREA 0.00198 ;
	END WEN[42]

	PIN WEN[43]
		USE SIGNAL ;
		DIRECTION INPUT ;
		SHAPE ABUTMENT ;
		PORT
			 LAYER M2 ;
			RECT 0.0098 42.1778 0.0481 42.2794 ;
			 LAYER M3 ;
			RECT 0.0098 42.1778 0.0481 42.2794 ;
			 LAYER V2 ;
			RECT 0.021 42.1909 0.0359 42.2036 ;
		END

		ANTENNAGATEAREA 0.00028148 ;
		ANTENNADIFFAREA 0.00197037 ;
		ANTENNAPARTIALMETALAREA 0.00198 ;
	END WEN[43]

	PIN WEN[44]
		USE SIGNAL ;
		DIRECTION INPUT ;
		SHAPE ABUTMENT ;
		PORT
			 LAYER M2 ;
			RECT 0.0098 42.9778 0.0481 43.0794 ;
			 LAYER M3 ;
			RECT 0.0098 42.9778 0.0481 43.0794 ;
			 LAYER V2 ;
			RECT 0.021 42.9909 0.0359 43.0036 ;
		END

		ANTENNAGATEAREA 0.00028148 ;
		ANTENNADIFFAREA 0.00197037 ;
		ANTENNAPARTIALMETALAREA 0.00198 ;
	END WEN[44]

	PIN WEN[4]
		USE SIGNAL ;
		DIRECTION INPUT ;
		SHAPE ABUTMENT ;
		PORT
			 LAYER M2 ;
			RECT 0.0098 4.1016 0.0481 4.2032 ;
			 LAYER M3 ;
			RECT 0.0098 4.1016 0.0481 4.2032 ;
			 LAYER V2 ;
			RECT 0.021 4.1774 0.0359 4.1901 ;
		END

		ANTENNAGATEAREA 0.00028148 ;
		ANTENNADIFFAREA 0.00197037 ;
		ANTENNAPARTIALMETALAREA 0.00198 ;
	END WEN[4]

	PIN WEN[5]
		USE SIGNAL ;
		DIRECTION INPUT ;
		SHAPE ABUTMENT ;
		PORT
			 LAYER M2 ;
			RECT 0.0098 4.9016 0.0481 5.0032 ;
			 LAYER M3 ;
			RECT 0.0098 4.9016 0.0481 5.0032 ;
			 LAYER V2 ;
			RECT 0.021 4.9774 0.0359 4.9901 ;
		END

		ANTENNAGATEAREA 0.00028148 ;
		ANTENNADIFFAREA 0.00197037 ;
		ANTENNAPARTIALMETALAREA 0.00198 ;
	END WEN[5]

	PIN WEN[6]
		USE SIGNAL ;
		DIRECTION INPUT ;
		SHAPE ABUTMENT ;
		PORT
			 LAYER M2 ;
			RECT 0.0098 5.7016 0.0481 5.8032 ;
			 LAYER M3 ;
			RECT 0.0098 5.7016 0.0481 5.8032 ;
			 LAYER V2 ;
			RECT 0.021 5.7774 0.0359 5.7901 ;
		END

		ANTENNAGATEAREA 0.00028148 ;
		ANTENNADIFFAREA 0.00197037 ;
		ANTENNAPARTIALMETALAREA 0.00198 ;
	END WEN[6]

	PIN WEN[7]
		USE SIGNAL ;
		DIRECTION INPUT ;
		SHAPE ABUTMENT ;
		PORT
			 LAYER M2 ;
			RECT 0.0098 6.5016 0.0481 6.6032 ;
			 LAYER M3 ;
			RECT 0.0098 6.5016 0.0481 6.6032 ;
			 LAYER V2 ;
			RECT 0.021 6.5774 0.0359 6.5901 ;
		END

		ANTENNAGATEAREA 0.00028148 ;
		ANTENNADIFFAREA 0.00197037 ;
		ANTENNAPARTIALMETALAREA 0.00198 ;
	END WEN[7]

	PIN WEN[8]
		USE SIGNAL ;
		DIRECTION INPUT ;
		SHAPE ABUTMENT ;
		PORT
			 LAYER M2 ;
			RECT 0.0098 7.3016 0.0481 7.4032 ;
			 LAYER M3 ;
			RECT 0.0098 7.3016 0.0481 7.4032 ;
			 LAYER V2 ;
			RECT 0.021 7.3774 0.0359 7.3901 ;
		END

		ANTENNAGATEAREA 0.00028148 ;
		ANTENNADIFFAREA 0.00197037 ;
		ANTENNAPARTIALMETALAREA 0.00198 ;
	END WEN[8]

	PIN WEN[9]
		USE SIGNAL ;
		DIRECTION INPUT ;
		SHAPE ABUTMENT ;
		PORT
			 LAYER M2 ;
			RECT 0.0098 8.1016 0.0481 8.2032 ;
			 LAYER M3 ;
			RECT 0.0098 8.1016 0.0481 8.2032 ;
			 LAYER V2 ;
			RECT 0.021 8.1774 0.0359 8.1901 ;
		END

		ANTENNAGATEAREA 0.00028148 ;
		ANTENNADIFFAREA 0.00197037 ;
		ANTENNAPARTIALMETALAREA 0.00198 ;
	END WEN[9]

	OBS
		 LAYER M1 SPACING 0.012 ;
		RECT 0 0 8.463 43.981 ;
		 LAYER M2 SPACING 0.012 ;
		RECT 0.133 0 8.463 43.981 ;
		RECT 0 0 0.133 0.0952 ;
		RECT 0.0714 0.2413 0.133 0.3492 ;
		RECT 0.0714 0.3492 0.133 0.4762 ;
		RECT 0.0714 0.4762 0.133 0.6032 ;
		RECT 0.0714 0.6032 0.133 0.7556 ;
		RECT 0 0.7429 0.133 0.7556 ;
		RECT 0.0714 0.7556 0.133 0.8825 ;
		RECT 0.0714 0.8825 0.133 1.0222 ;
		RECT 0.0714 1.0222 0.133 1.1492 ;
		RECT 0.0714 1.1492 0.133 1.2762 ;
		RECT 0.0714 1.2762 0.133 1.4032 ;
		RECT 0.0714 1.4032 0.133 1.5556 ;
		RECT 0 1.5429 0.133 1.5556 ;
		RECT 0.0714 1.5556 0.133 1.6825 ;
		RECT 0.0714 1.6825 0.133 1.8222 ;
		RECT 0.0714 1.8222 0.133 1.9492 ;
		RECT 0.0714 1.9492 0.133 2.0762 ;
		RECT 0.0714 2.0762 0.133 2.2032 ;
		RECT 0.0714 2.2032 0.133 2.3556 ;
		RECT 0 2.3429 0.133 2.3556 ;
		RECT 0.0714 2.3556 0.133 2.4825 ;
		RECT 0.0714 2.4825 0.133 2.6222 ;
		RECT 0.0714 2.6222 0.133 2.7492 ;
		RECT 0.0714 2.7492 0.133 2.8762 ;
		RECT 0.0714 2.8762 0.133 3.0032 ;
		RECT 0.0714 3.0032 0.133 3.1556 ;
		RECT 0 3.1429 0.133 3.1556 ;
		RECT 0.0714 3.1556 0.133 3.2825 ;
		RECT 0.0714 3.2825 0.133 3.4222 ;
		RECT 0.0714 3.4222 0.133 3.5492 ;
		RECT 0.0714 3.5492 0.133 3.6762 ;
		RECT 0.0714 3.6762 0.133 3.8032 ;
		RECT 0.0714 3.8032 0.133 3.9556 ;
		RECT 0 3.9429 0.133 3.9556 ;
		RECT 0.0714 3.9556 0.133 4.0825 ;
		RECT 0.0714 4.0825 0.133 4.2222 ;
		RECT 0.0714 4.2222 0.133 4.3492 ;
		RECT 0.0714 4.3492 0.133 4.4762 ;
		RECT 0.0714 4.4762 0.133 4.6032 ;
		RECT 0.0714 4.6032 0.133 4.7556 ;
		RECT 0 4.7429 0.133 4.7556 ;
		RECT 0.0714 4.7556 0.133 4.8825 ;
		RECT 0.0714 4.8825 0.133 5.0222 ;
		RECT 0.0714 5.0222 0.133 5.1492 ;
		RECT 0.0714 5.1492 0.133 5.2762 ;
		RECT 0.0714 5.2762 0.133 5.4032 ;
		RECT 0.0714 5.4032 0.133 5.5556 ;
		RECT 0 5.5429 0.133 5.5556 ;
		RECT 0.0714 5.5556 0.133 5.6825 ;
		RECT 0.0714 5.6825 0.133 5.8222 ;
		RECT 0.0714 5.8222 0.133 5.9492 ;
		RECT 0.0714 5.9492 0.133 6.0762 ;
		RECT 0.0714 6.0762 0.133 6.2032 ;
		RECT 0.0714 6.2032 0.133 6.3556 ;
		RECT 0 6.3429 0.133 6.3556 ;
		RECT 0.0714 6.3556 0.133 6.4825 ;
		RECT 0.0714 6.4825 0.133 6.6222 ;
		RECT 0.0714 6.6222 0.133 6.7492 ;
		RECT 0.0714 6.7492 0.133 6.8762 ;
		RECT 0.0714 6.8762 0.133 7.0032 ;
		RECT 0.0714 7.0032 0.133 7.1556 ;
		RECT 0 7.1429 0.133 7.1556 ;
		RECT 0.0714 7.1556 0.133 7.2825 ;
		RECT 0.0714 7.2825 0.133 7.4222 ;
		RECT 0.0714 7.4222 0.133 7.5492 ;
		RECT 0.0714 7.5492 0.133 7.6762 ;
		RECT 0.0714 7.6762 0.133 7.8032 ;
		RECT 0.0714 7.8032 0.133 7.9556 ;
		RECT 0 7.9429 0.133 7.9556 ;
		RECT 0.0714 7.9556 0.133 8.0825 ;
		RECT 0.0714 8.0825 0.133 8.2222 ;
		RECT 0.0714 8.2222 0.133 8.3492 ;
		RECT 0.0714 8.3492 0.133 8.4762 ;
		RECT 0.0714 8.4762 0.133 8.6032 ;
		RECT 0.0714 8.6032 0.133 8.7556 ;
		RECT 0 8.7429 0.133 8.7556 ;
		RECT 0.0714 8.7556 0.133 8.8825 ;
		RECT 0.0714 8.8825 0.133 9.0222 ;
		RECT 0.0714 9.0222 0.133 9.1492 ;
		RECT 0.0714 9.1492 0.133 9.2762 ;
		RECT 0.0714 9.2762 0.133 9.4032 ;
		RECT 0.0714 9.4032 0.133 9.5556 ;
		RECT 0 9.5429 0.133 9.5556 ;
		RECT 0.0714 9.5556 0.133 9.6825 ;
		RECT 0.0714 9.6825 0.133 9.8222 ;
		RECT 0.0714 9.8222 0.133 9.9492 ;
		RECT 0.0714 9.9492 0.133 10.0762 ;
		RECT 0.0714 10.0762 0.133 10.2032 ;
		RECT 0.0714 10.2032 0.133 10.3556 ;
		RECT 0 10.3429 0.133 10.3556 ;
		RECT 0.0714 10.3556 0.133 10.4825 ;
		RECT 0.0714 10.4825 0.133 10.6222 ;
		RECT 0.0714 10.6222 0.133 10.7492 ;
		RECT 0.0714 10.7492 0.133 10.8762 ;
		RECT 0.0714 10.8762 0.133 11.0032 ;
		RECT 0.0714 11.0032 0.133 11.1556 ;
		RECT 0 11.1429 0.133 11.1556 ;
		RECT 0.0714 11.1556 0.133 11.2825 ;
		RECT 0.0714 11.2825 0.133 11.4222 ;
		RECT 0.0714 11.4222 0.133 11.5492 ;
		RECT 0.0714 11.5492 0.133 11.6762 ;
		RECT 0.0714 11.6762 0.133 11.8032 ;
		RECT 0.0714 11.8032 0.133 11.9556 ;
		RECT 0 11.9429 0.133 11.9556 ;
		RECT 0.0714 11.9556 0.133 12.0825 ;
		RECT 0.0714 12.0825 0.133 12.2222 ;
		RECT 0.0714 12.2222 0.133 12.3492 ;
		RECT 0.0714 12.3492 0.133 12.4762 ;
		RECT 0.0714 12.4762 0.133 12.6032 ;
		RECT 0.0714 12.6032 0.133 12.7556 ;
		RECT 0 12.7429 0.133 12.7556 ;
		RECT 0.0714 12.7556 0.133 12.8825 ;
		RECT 0.0714 12.8825 0.133 13.0222 ;
		RECT 0.0714 13.0222 0.133 13.1492 ;
		RECT 0.0714 13.1492 0.133 13.2762 ;
		RECT 0.0714 13.2762 0.133 13.4032 ;
		RECT 0.0714 13.4032 0.133 13.5556 ;
		RECT 0 13.5429 0.133 13.5556 ;
		RECT 0.0714 13.5556 0.133 13.6825 ;
		RECT 0.0714 13.6825 0.133 13.8222 ;
		RECT 0.0714 13.8222 0.133 13.9492 ;
		RECT 0.0714 13.9492 0.133 14.0762 ;
		RECT 0.0714 14.0762 0.133 14.2032 ;
		RECT 0.0714 14.2032 0.133 14.3556 ;
		RECT 0 14.3429 0.133 14.3556 ;
		RECT 0.0714 14.3556 0.133 14.4825 ;
		RECT 0.0714 14.4825 0.133 14.6222 ;
		RECT 0.0714 14.6222 0.133 14.7492 ;
		RECT 0.0714 14.7492 0.133 14.8762 ;
		RECT 0.0714 14.8762 0.133 15.0032 ;
		RECT 0.0714 15.0032 0.133 15.1556 ;
		RECT 0 15.1429 0.133 15.1556 ;
		RECT 0.0714 15.1556 0.133 15.2825 ;
		RECT 0.0714 15.2825 0.133 15.4222 ;
		RECT 0.0714 15.4222 0.133 15.5492 ;
		RECT 0.0714 15.5492 0.133 15.6762 ;
		RECT 0.0714 15.6762 0.133 15.8032 ;
		RECT 0.0714 15.8032 0.133 15.9556 ;
		RECT 0 15.9429 0.133 15.9556 ;
		RECT 0.0714 15.9556 0.133 16.0825 ;
		RECT 0.0714 16.0825 0.133 16.2222 ;
		RECT 0.0714 16.2222 0.133 16.3492 ;
		RECT 0.0714 16.3492 0.133 16.4762 ;
		RECT 0.0714 16.4762 0.133 16.6032 ;
		RECT 0.0714 16.6032 0.133 16.7556 ;
		RECT 0 16.7429 0.133 16.7556 ;
		RECT 0.0714 16.7556 0.133 16.8825 ;
		RECT 0.0714 16.8825 0.133 17.0222 ;
		RECT 0.0714 17.0222 0.133 17.1492 ;
		RECT 0.0714 17.1492 0.133 17.2762 ;
		RECT 0.0714 17.2762 0.133 17.4032 ;
		RECT 0.0714 17.4032 0.133 17.5556 ;
		RECT 0 17.5429 0.133 17.5556 ;
		RECT 0.0714 17.5556 0.133 17.6825 ;
		RECT 0.0714 17.6825 0.133 18.6667 ;
		RECT 0 17.8222 0.133 18.6667 ;
		RECT 0.0714 18.6667 0.133 18.7937 ;
		RECT 0.0714 18.7937 0.133 19.0603 ;
		RECT 0 18.9333 0.133 19.0603 ;
		RECT 0.0714 19.0603 0.133 19.2 ;
		RECT 0 19.4667 0.133 19.5937 ;
		RECT 0.0714 19.5937 0.133 19.7333 ;
		RECT 0 20.5333 0.133 20.673 ;
		RECT 0 21.4603 0.133 21.7397 ;
		RECT 0 22.0063 0.133 22.2603 ;
		RECT 0 22.4 0.133 22.527 ;
		RECT 0 23.073 0.133 23.2 ;
		RECT 0.0714 23.2 0.133 23.327 ;
		RECT 0 23.7333 0.133 23.746 ;
		RECT 0 23.8857 0.133 24.2794 ;
		RECT 0 24.419 0.133 25.3587 ;
		RECT 0.0714 25.3587 0.133 25.4857 ;
		RECT 0.0714 25.4857 0.133 25.6381 ;
		RECT 0 25.6254 0.133 25.6381 ;
		RECT 0.0714 25.6381 0.133 25.7651 ;
		RECT 0.0714 25.7651 0.133 25.8921 ;
		RECT 0.0714 25.8921 0.133 26.019 ;
		RECT 0.0714 26.019 0.133 26.1587 ;
		RECT 0.0714 26.1587 0.133 26.2857 ;
		RECT 0.0714 26.2857 0.133 26.4381 ;
		RECT 0 26.4254 0.133 26.4381 ;
		RECT 0.0714 26.4381 0.133 26.5651 ;
		RECT 0.0714 26.5651 0.133 26.6921 ;
		RECT 0.0714 26.6921 0.133 26.819 ;
		RECT 0.0714 26.819 0.133 26.9587 ;
		RECT 0.0714 26.9587 0.133 27.0857 ;
		RECT 0.0714 27.0857 0.133 27.2381 ;
		RECT 0 27.2254 0.133 27.2381 ;
		RECT 0.0714 27.2381 0.133 27.3651 ;
		RECT 0.0714 27.3651 0.133 27.4921 ;
		RECT 0.0714 27.4921 0.133 27.619 ;
		RECT 0.0714 27.619 0.133 27.7587 ;
		RECT 0.0714 27.7587 0.133 27.8857 ;
		RECT 0.0714 27.8857 0.133 28.0381 ;
		RECT 0 28.0254 0.133 28.0381 ;
		RECT 0.0714 28.0381 0.133 28.1651 ;
		RECT 0.0714 28.1651 0.133 28.2921 ;
		RECT 0.0714 28.2921 0.133 28.419 ;
		RECT 0.0714 28.419 0.133 28.5587 ;
		RECT 0.0714 28.5587 0.133 28.6857 ;
		RECT 0.0714 28.6857 0.133 28.8381 ;
		RECT 0 28.8254 0.133 28.8381 ;
		RECT 0.0714 28.8381 0.133 28.9651 ;
		RECT 0.0714 28.9651 0.133 29.0921 ;
		RECT 0.0714 29.0921 0.133 29.219 ;
		RECT 0.0714 29.219 0.133 29.3587 ;
		RECT 0.0714 29.3587 0.133 29.4857 ;
		RECT 0.0714 29.4857 0.133 29.6381 ;
		RECT 0 29.6254 0.133 29.6381 ;
		RECT 0.0714 29.6381 0.133 29.7651 ;
		RECT 0.0714 29.7651 0.133 29.8921 ;
		RECT 0.0714 29.8921 0.133 30.019 ;
		RECT 0.0714 30.019 0.133 30.1587 ;
		RECT 0.0714 30.1587 0.133 30.2857 ;
		RECT 0.0714 30.2857 0.133 30.4381 ;
		RECT 0 30.4254 0.133 30.4381 ;
		RECT 0.0714 30.4381 0.133 30.5651 ;
		RECT 0.0714 30.5651 0.133 30.6921 ;
		RECT 0.0714 30.6921 0.133 30.819 ;
		RECT 0.0714 30.819 0.133 30.9587 ;
		RECT 0.0714 30.9587 0.133 31.0857 ;
		RECT 0.0714 31.0857 0.133 31.2381 ;
		RECT 0 31.2254 0.133 31.2381 ;
		RECT 0.0714 31.2381 0.133 31.3651 ;
		RECT 0.0714 31.3651 0.133 31.4921 ;
		RECT 0.0714 31.4921 0.133 31.619 ;
		RECT 0.0714 31.619 0.133 31.7587 ;
		RECT 0.0714 31.7587 0.133 31.8857 ;
		RECT 0.0714 31.8857 0.133 32.0381 ;
		RECT 0 32.0254 0.133 32.0381 ;
		RECT 0.0714 32.0381 0.133 32.1651 ;
		RECT 0.0714 32.1651 0.133 32.2921 ;
		RECT 0.0714 32.2921 0.133 32.419 ;
		RECT 0.0714 32.419 0.133 32.5587 ;
		RECT 0.0714 32.5587 0.133 32.6857 ;
		RECT 0.0714 32.6857 0.133 32.8381 ;
		RECT 0 32.8254 0.133 32.8381 ;
		RECT 0.0714 32.8381 0.133 32.9651 ;
		RECT 0.0714 32.9651 0.133 33.0921 ;
		RECT 0.0714 33.0921 0.133 33.219 ;
		RECT 0.0714 33.219 0.133 33.3587 ;
		RECT 0.0714 33.3587 0.133 33.4857 ;
		RECT 0.0714 33.4857 0.133 33.6381 ;
		RECT 0 33.6254 0.133 33.6381 ;
		RECT 0.0714 33.6381 0.133 33.7651 ;
		RECT 0.0714 33.7651 0.133 33.8921 ;
		RECT 0.0714 33.8921 0.133 34.019 ;
		RECT 0.0714 34.019 0.133 34.1587 ;
		RECT 0.0714 34.1587 0.133 34.2857 ;
		RECT 0.0714 34.2857 0.133 34.4381 ;
		RECT 0 34.4254 0.133 34.4381 ;
		RECT 0.0714 34.4381 0.133 34.5651 ;
		RECT 0.0714 34.5651 0.133 34.6921 ;
		RECT 0.0714 34.6921 0.133 34.819 ;
		RECT 0.0714 34.819 0.133 34.9587 ;
		RECT 0.0714 34.9587 0.133 35.0857 ;
		RECT 0.0714 35.0857 0.133 35.2381 ;
		RECT 0 35.2254 0.133 35.2381 ;
		RECT 0.0714 35.2381 0.133 35.3651 ;
		RECT 0.0714 35.3651 0.133 35.4921 ;
		RECT 0.0714 35.4921 0.133 35.619 ;
		RECT 0.0714 35.619 0.133 35.7587 ;
		RECT 0.0714 35.7587 0.133 35.8857 ;
		RECT 0.0714 35.8857 0.133 36.0381 ;
		RECT 0 36.0254 0.133 36.0381 ;
		RECT 0.0714 36.0381 0.133 36.1651 ;
		RECT 0.0714 36.1651 0.133 36.2921 ;
		RECT 0.0714 36.2921 0.133 36.419 ;
		RECT 0.0714 36.419 0.133 36.5587 ;
		RECT 0.0714 36.5587 0.133 36.6857 ;
		RECT 0.0714 36.6857 0.133 36.8381 ;
		RECT 0 36.8254 0.133 36.8381 ;
		RECT 0.0714 36.8381 0.133 36.9651 ;
		RECT 0.0714 36.9651 0.133 37.0921 ;
		RECT 0.0714 37.0921 0.133 37.219 ;
		RECT 0.0714 37.219 0.133 37.3587 ;
		RECT 0.0714 37.3587 0.133 37.4857 ;
		RECT 0.0714 37.4857 0.133 37.6381 ;
		RECT 0 37.6254 0.133 37.6381 ;
		RECT 0.0714 37.6381 0.133 37.7651 ;
		RECT 0.0714 37.7651 0.133 37.8921 ;
		RECT 0.0714 37.8921 0.133 38.019 ;
		RECT 0.0714 38.019 0.133 38.1587 ;
		RECT 0.0714 38.1587 0.133 38.2857 ;
		RECT 0.0714 38.2857 0.133 38.4381 ;
		RECT 0 38.4254 0.133 38.4381 ;
		RECT 0.0714 38.4381 0.133 38.5651 ;
		RECT 0.0714 38.5651 0.133 38.6921 ;
		RECT 0.0714 38.6921 0.133 38.819 ;
		RECT 0.0714 38.819 0.133 38.9587 ;
		RECT 0.0714 38.9587 0.133 39.0857 ;
		RECT 0.0714 39.0857 0.133 39.2381 ;
		RECT 0 39.2254 0.133 39.2381 ;
		RECT 0.0714 39.2381 0.133 39.3651 ;
		RECT 0.0714 39.3651 0.133 39.4921 ;
		RECT 0.0714 39.4921 0.133 39.619 ;
		RECT 0.0714 39.619 0.133 39.7587 ;
		RECT 0.0714 39.7587 0.133 39.8857 ;
		RECT 0.0714 39.8857 0.133 40.0381 ;
		RECT 0 40.0254 0.133 40.0381 ;
		RECT 0.0714 40.0381 0.133 40.1651 ;
		RECT 0.0714 40.1651 0.133 40.2921 ;
		RECT 0.0714 40.2921 0.133 40.419 ;
		RECT 0.0714 40.419 0.133 40.5587 ;
		RECT 0.0714 40.5587 0.133 40.6857 ;
		RECT 0.0714 40.6857 0.133 40.8381 ;
		RECT 0 40.8254 0.133 40.8381 ;
		RECT 0.0714 40.8381 0.133 40.9651 ;
		RECT 0.0714 40.9651 0.133 41.0921 ;
		RECT 0.0714 41.0921 0.133 41.219 ;
		RECT 0.0714 41.219 0.133 41.3587 ;
		RECT 0.0714 41.3587 0.133 41.4857 ;
		RECT 0.0714 41.4857 0.133 41.6381 ;
		RECT 0 41.6254 0.133 41.6381 ;
		RECT 0.0714 41.6381 0.133 41.7651 ;
		RECT 0.0714 41.7651 0.133 41.8921 ;
		RECT 0.0714 41.8921 0.133 42.019 ;
		RECT 0.0714 42.019 0.133 42.1587 ;
		RECT 0.0714 42.1587 0.133 42.2857 ;
		RECT 0.0714 42.2857 0.133 42.4381 ;
		RECT 0 42.4254 0.133 42.4381 ;
		RECT 0.0714 42.4381 0.133 42.5651 ;
		RECT 0.0714 42.5651 0.133 42.6921 ;
		RECT 0.0714 42.6921 0.133 42.819 ;
		RECT 0.0714 42.819 0.133 42.9587 ;
		RECT 0.0714 42.9587 0.133 43.0857 ;
		RECT 0.0714 43.0857 0.133 43.2381 ;
		RECT 0 43.2254 0.133 43.2381 ;
		RECT 0.0714 43.2381 0.133 43.3651 ;
		RECT 0.0714 43.3651 0.133 43.4921 ;
		RECT 0.0714 43.4921 0.133 43.619 ;
		RECT 0.0714 43.619 0.133 43.746 ;
		RECT 0 43.8857 0.133 43.981 ;
		 LAYER M2 ;
		RECT 0.0714 17.8857 0.1097 17.9238 ;
		RECT 0.0098 17.9492 0.0481 17.9873 ;
		RECT 0.0098 18.6095 0.0481 18.6476 ;
		RECT 0.0098 18.9524 0.0481 19.054 ;
		RECT 0.0098 19.2825 0.0481 19.3206 ;
		RECT 0.0714 19.346 0.1097 19.3841 ;
		RECT 0.0714 19.4857 0.1097 19.5238 ;
		RECT 0.0098 19.5492 0.0481 19.5873 ;
		RECT 0.0098 19.9429 0.0481 19.981 ;
		RECT 0.0714 20.019 0.1097 20.0571 ;
		RECT 0.0098 20.2095 0.0481 20.2476 ;
		RECT 0.0714 20.4127 0.1097 20.4508 ;
		RECT 0.0714 18.0127 0.1097 18.0508 ;
		RECT 0.0714 20.5524 0.1097 20.5905 ;
		RECT 0.0098 20.6159 0.0481 20.654 ;
		RECT 0.0098 20.7556 0.0481 20.7937 ;
		RECT 0.0098 20.8825 0.0481 20.9206 ;
		RECT 0.0098 21.0095 0.0481 21.0476 ;
		RECT 0.0714 21.3397 0.1097 21.3778 ;
		RECT 0.0714 21.4794 0.1097 21.5175 ;
		RECT 0.0098 21.5429 0.0481 21.581 ;
		RECT 0.0714 21.619 0.1097 21.6571 ;
		RECT 0.0098 21.6825 0.0481 21.7206 ;
		RECT 0.0098 18.0762 0.0481 18.1143 ;
		RECT 0.0714 21.7587 0.1097 21.7968 ;
		RECT 0.0714 22.0127 0.1097 22.0508 ;
		RECT 0.0098 22.0762 0.0481 22.1143 ;
		RECT 0.0714 22.1524 0.1097 22.1905 ;
		RECT 0.0098 22.2159 0.0481 22.254 ;
		RECT 0.0714 22.4063 0.1097 22.4444 ;
		RECT 0.0098 22.4698 0.0481 22.5079 ;
		RECT 0.0714 22.546 0.1097 22.5841 ;
		RECT 0.0714 22.6857 0.1097 22.7238 ;
		RECT 0.0714 22.8254 0.1097 22.8635 ;
		RECT 0.0714 18.1524 0.1097 18.1905 ;
		RECT 0.0714 23.0794 0.1097 23.1175 ;
		RECT 0.0098 23.1429 0.0481 23.181 ;
		RECT 0.0714 23.7651 0.1097 23.8032 ;
		RECT 0.0714 23.8921 0.1097 23.9302 ;
		RECT 0.0098 23.9556 0.0481 23.9937 ;
		RECT 0.0714 24.0444 0.1097 24.0825 ;
		RECT 0.0098 24.1079 0.0481 24.146 ;
		RECT 0.0714 24.1714 0.1097 24.2095 ;
		RECT 0.0098 24.2349 0.0481 24.273 ;
		RECT 0.0714 24.2984 0.1097 24.3365 ;
		RECT 0.0098 18.2159 0.0481 18.254 ;
		RECT 0.0714 24.4254 0.1097 24.4635 ;
		RECT 0.0098 24.4889 0.0481 24.527 ;
		RECT 0.0714 24.5524 0.1097 24.5905 ;
		RECT 0.0098 24.6159 0.0481 24.654 ;
		RECT 0.0714 24.6794 0.1097 24.7175 ;
		RECT 0.0098 24.7429 0.0481 24.781 ;
		RECT 0.0714 24.819 0.1097 24.8571 ;
		RECT 0.0098 24.8825 0.0481 24.9206 ;
		RECT 0.0714 24.946 0.1097 24.9841 ;
		RECT 0.0098 25.0095 0.0481 25.0476 ;
		RECT 0.0714 18.2794 0.1097 18.3175 ;
		RECT 0.0714 25.0857 0.1097 25.1238 ;
		RECT 0.0098 25.1492 0.0481 25.1873 ;
		RECT 0.0714 0.1143 0.1097 0.1524 ;
		RECT 0.0714 43.8286 0.1097 43.8667 ;
		RECT 0.0098 18.3429 0.0481 18.381 ;
		RECT 0.0098 18.419 0.0481 18.5206 ;
		RECT 0.0714 18.546 0.1097 18.5841 ;
		 LAYER M2 SPACING 0.012 ;
		RECT 0.0714 17.8857 0.1097 17.9238 ;
		RECT 0.0098 17.9492 0.0481 17.9873 ;
		RECT 0.0098 18.6095 0.0481 18.6476 ;
		RECT 0.0098 18.9524 0.0481 19.054 ;
		RECT 0.0098 19.2825 0.0481 19.3206 ;
		RECT 0.0714 19.346 0.1097 19.3841 ;
		RECT 0.0714 19.4857 0.1097 19.5238 ;
		RECT 0.0098 19.5492 0.0481 19.5873 ;
		RECT 0.0098 19.9429 0.0481 19.981 ;
		RECT 0.0714 20.019 0.1097 20.0571 ;
		RECT 0.0098 20.2095 0.0481 20.2476 ;
		RECT 0.0714 20.4127 0.1097 20.4508 ;
		RECT 0.0714 18.0127 0.1097 18.0508 ;
		RECT 0.0714 20.5524 0.1097 20.5905 ;
		RECT 0.0098 20.6159 0.0481 20.654 ;
		RECT 0.0098 20.7556 0.0481 20.7937 ;
		RECT 0.0098 20.8825 0.0481 20.9206 ;
		RECT 0.0098 21.0095 0.0481 21.0476 ;
		RECT 0.0714 21.3397 0.1097 21.3778 ;
		RECT 0.0714 21.4794 0.1097 21.5175 ;
		RECT 0.0098 21.5429 0.0481 21.581 ;
		RECT 0.0714 21.619 0.1097 21.6571 ;
		RECT 0.0098 21.6825 0.0481 21.7206 ;
		RECT 0.0098 18.0762 0.0481 18.1143 ;
		RECT 0.0714 21.7587 0.1097 21.7968 ;
		RECT 0.0714 22.0127 0.1097 22.0508 ;
		RECT 0.0098 22.0762 0.0481 22.1143 ;
		RECT 0.0714 22.1524 0.1097 22.1905 ;
		RECT 0.0098 22.2159 0.0481 22.254 ;
		RECT 0.0714 22.4063 0.1097 22.4444 ;
		RECT 0.0098 22.4698 0.0481 22.5079 ;
		RECT 0.0714 22.546 0.1097 22.5841 ;
		RECT 0.0714 22.6857 0.1097 22.7238 ;
		RECT 0.0714 22.8254 0.1097 22.8635 ;
		RECT 0.0714 18.1524 0.1097 18.1905 ;
		RECT 0.0714 23.0794 0.1097 23.1175 ;
		RECT 0.0098 23.1429 0.0481 23.181 ;
		RECT 0.0714 23.7651 0.1097 23.8032 ;
		RECT 0.0714 23.8921 0.1097 23.9302 ;
		RECT 0.0098 23.9556 0.0481 23.9937 ;
		RECT 0.0714 24.0444 0.1097 24.0825 ;
		RECT 0.0098 24.1079 0.0481 24.146 ;
		RECT 0.0714 24.1714 0.1097 24.2095 ;
		RECT 0.0098 24.2349 0.0481 24.273 ;
		RECT 0.0714 24.2984 0.1097 24.3365 ;
		RECT 0.0098 18.2159 0.0481 18.254 ;
		RECT 0.0714 24.4254 0.1097 24.4635 ;
		RECT 0.0098 24.4889 0.0481 24.527 ;
		RECT 0.0714 24.5524 0.1097 24.5905 ;
		RECT 0.0098 24.6159 0.0481 24.654 ;
		RECT 0.0714 24.6794 0.1097 24.7175 ;
		RECT 0.0098 24.7429 0.0481 24.781 ;
		RECT 0.0714 24.819 0.1097 24.8571 ;
		RECT 0.0098 24.8825 0.0481 24.9206 ;
		RECT 0.0714 24.946 0.1097 24.9841 ;
		RECT 0.0098 25.0095 0.0481 25.0476 ;
		RECT 0.0714 18.2794 0.1097 18.3175 ;
		RECT 0.0714 25.0857 0.1097 25.1238 ;
		RECT 0.0098 25.1492 0.0481 25.1873 ;
		RECT 0.0714 0.1143 0.1097 0.1524 ;
		RECT 0.0714 43.8286 0.1097 43.8667 ;
		RECT 0.0098 18.3429 0.0481 18.381 ;
		RECT 0.0098 18.419 0.0481 18.5206 ;
		RECT 0.0714 18.546 0.1097 18.5841 ;
		 LAYER M3 SPACING 0.012 ;
		RECT 0.133 0 8.463 43.981 ;
		RECT 0 0 0.133 0.0952 ;
		RECT 0.0714 0.2413 0.133 0.3492 ;
		RECT 0.0714 0.3492 0.133 0.4762 ;
		RECT 0.0714 0.4762 0.133 0.6032 ;
		RECT 0.0714 0.6032 0.133 0.7556 ;
		RECT 0 0.7429 0.133 0.7556 ;
		RECT 0.0714 0.7556 0.133 0.8825 ;
		RECT 0.0714 0.8825 0.133 1.0222 ;
		RECT 0.0714 1.0222 0.133 1.1492 ;
		RECT 0.0714 1.1492 0.133 1.2762 ;
		RECT 0.0714 1.2762 0.133 1.4032 ;
		RECT 0.0714 1.4032 0.133 1.5556 ;
		RECT 0 1.5429 0.133 1.5556 ;
		RECT 0.0714 1.5556 0.133 1.6825 ;
		RECT 0.0714 1.6825 0.133 1.8222 ;
		RECT 0.0714 1.8222 0.133 1.9492 ;
		RECT 0.0714 1.9492 0.133 2.0762 ;
		RECT 0.0714 2.0762 0.133 2.2032 ;
		RECT 0.0714 2.2032 0.133 2.3556 ;
		RECT 0 2.3429 0.133 2.3556 ;
		RECT 0.0714 2.3556 0.133 2.4825 ;
		RECT 0.0714 2.4825 0.133 2.6222 ;
		RECT 0.0714 2.6222 0.133 2.7492 ;
		RECT 0.0714 2.7492 0.133 2.8762 ;
		RECT 0.0714 2.8762 0.133 3.0032 ;
		RECT 0.0714 3.0032 0.133 3.1556 ;
		RECT 0 3.1429 0.133 3.1556 ;
		RECT 0.0714 3.1556 0.133 3.2825 ;
		RECT 0.0714 3.2825 0.133 3.4222 ;
		RECT 0.0714 3.4222 0.133 3.5492 ;
		RECT 0.0714 3.5492 0.133 3.6762 ;
		RECT 0.0714 3.6762 0.133 3.8032 ;
		RECT 0.0714 3.8032 0.133 3.9556 ;
		RECT 0 3.9429 0.133 3.9556 ;
		RECT 0.0714 3.9556 0.133 4.0825 ;
		RECT 0.0714 4.0825 0.133 4.2222 ;
		RECT 0.0714 4.2222 0.133 4.3492 ;
		RECT 0.0714 4.3492 0.133 4.4762 ;
		RECT 0.0714 4.4762 0.133 4.6032 ;
		RECT 0.0714 4.6032 0.133 4.7556 ;
		RECT 0 4.7429 0.133 4.7556 ;
		RECT 0.0714 4.7556 0.133 4.8825 ;
		RECT 0.0714 4.8825 0.133 5.0222 ;
		RECT 0.0714 5.0222 0.133 5.1492 ;
		RECT 0.0714 5.1492 0.133 5.2762 ;
		RECT 0.0714 5.2762 0.133 5.4032 ;
		RECT 0.0714 5.4032 0.133 5.5556 ;
		RECT 0 5.5429 0.133 5.5556 ;
		RECT 0.0714 5.5556 0.133 5.6825 ;
		RECT 0.0714 5.6825 0.133 5.8222 ;
		RECT 0.0714 5.8222 0.133 5.9492 ;
		RECT 0.0714 5.9492 0.133 6.0762 ;
		RECT 0.0714 6.0762 0.133 6.2032 ;
		RECT 0.0714 6.2032 0.133 6.3556 ;
		RECT 0 6.3429 0.133 6.3556 ;
		RECT 0.0714 6.3556 0.133 6.4825 ;
		RECT 0.0714 6.4825 0.133 6.6222 ;
		RECT 0.0714 6.6222 0.133 6.7492 ;
		RECT 0.0714 6.7492 0.133 6.8762 ;
		RECT 0.0714 6.8762 0.133 7.0032 ;
		RECT 0.0714 7.0032 0.133 7.1556 ;
		RECT 0 7.1429 0.133 7.1556 ;
		RECT 0.0714 7.1556 0.133 7.2825 ;
		RECT 0.0714 7.2825 0.133 7.4222 ;
		RECT 0.0714 7.4222 0.133 7.5492 ;
		RECT 0.0714 7.5492 0.133 7.6762 ;
		RECT 0.0714 7.6762 0.133 7.8032 ;
		RECT 0.0714 7.8032 0.133 7.9556 ;
		RECT 0 7.9429 0.133 7.9556 ;
		RECT 0.0714 7.9556 0.133 8.0825 ;
		RECT 0.0714 8.0825 0.133 8.2222 ;
		RECT 0.0714 8.2222 0.133 8.3492 ;
		RECT 0.0714 8.3492 0.133 8.4762 ;
		RECT 0.0714 8.4762 0.133 8.6032 ;
		RECT 0.0714 8.6032 0.133 8.7556 ;
		RECT 0 8.7429 0.133 8.7556 ;
		RECT 0.0714 8.7556 0.133 8.8825 ;
		RECT 0.0714 8.8825 0.133 9.0222 ;
		RECT 0.0714 9.0222 0.133 9.1492 ;
		RECT 0.0714 9.1492 0.133 9.2762 ;
		RECT 0.0714 9.2762 0.133 9.4032 ;
		RECT 0.0714 9.4032 0.133 9.5556 ;
		RECT 0 9.5429 0.133 9.5556 ;
		RECT 0.0714 9.5556 0.133 9.6825 ;
		RECT 0.0714 9.6825 0.133 9.8222 ;
		RECT 0.0714 9.8222 0.133 9.9492 ;
		RECT 0.0714 9.9492 0.133 10.0762 ;
		RECT 0.0714 10.0762 0.133 10.2032 ;
		RECT 0.0714 10.2032 0.133 10.3556 ;
		RECT 0 10.3429 0.133 10.3556 ;
		RECT 0.0714 10.3556 0.133 10.4825 ;
		RECT 0.0714 10.4825 0.133 10.6222 ;
		RECT 0.0714 10.6222 0.133 10.7492 ;
		RECT 0.0714 10.7492 0.133 10.8762 ;
		RECT 0.0714 10.8762 0.133 11.0032 ;
		RECT 0.0714 11.0032 0.133 11.1556 ;
		RECT 0 11.1429 0.133 11.1556 ;
		RECT 0.0714 11.1556 0.133 11.2825 ;
		RECT 0.0714 11.2825 0.133 11.4222 ;
		RECT 0.0714 11.4222 0.133 11.5492 ;
		RECT 0.0714 11.5492 0.133 11.6762 ;
		RECT 0.0714 11.6762 0.133 11.8032 ;
		RECT 0.0714 11.8032 0.133 11.9556 ;
		RECT 0 11.9429 0.133 11.9556 ;
		RECT 0.0714 11.9556 0.133 12.0825 ;
		RECT 0.0714 12.0825 0.133 12.2222 ;
		RECT 0.0714 12.2222 0.133 12.3492 ;
		RECT 0.0714 12.3492 0.133 12.4762 ;
		RECT 0.0714 12.4762 0.133 12.6032 ;
		RECT 0.0714 12.6032 0.133 12.7556 ;
		RECT 0 12.7429 0.133 12.7556 ;
		RECT 0.0714 12.7556 0.133 12.8825 ;
		RECT 0.0714 12.8825 0.133 13.0222 ;
		RECT 0.0714 13.0222 0.133 13.1492 ;
		RECT 0.0714 13.1492 0.133 13.2762 ;
		RECT 0.0714 13.2762 0.133 13.4032 ;
		RECT 0.0714 13.4032 0.133 13.5556 ;
		RECT 0 13.5429 0.133 13.5556 ;
		RECT 0.0714 13.5556 0.133 13.6825 ;
		RECT 0.0714 13.6825 0.133 13.8222 ;
		RECT 0.0714 13.8222 0.133 13.9492 ;
		RECT 0.0714 13.9492 0.133 14.0762 ;
		RECT 0.0714 14.0762 0.133 14.2032 ;
		RECT 0.0714 14.2032 0.133 14.3556 ;
		RECT 0 14.3429 0.133 14.3556 ;
		RECT 0.0714 14.3556 0.133 14.4825 ;
		RECT 0.0714 14.4825 0.133 14.6222 ;
		RECT 0.0714 14.6222 0.133 14.7492 ;
		RECT 0.0714 14.7492 0.133 14.8762 ;
		RECT 0.0714 14.8762 0.133 15.0032 ;
		RECT 0.0714 15.0032 0.133 15.1556 ;
		RECT 0 15.1429 0.133 15.1556 ;
		RECT 0.0714 15.1556 0.133 15.2825 ;
		RECT 0.0714 15.2825 0.133 15.4222 ;
		RECT 0.0714 15.4222 0.133 15.5492 ;
		RECT 0.0714 15.5492 0.133 15.6762 ;
		RECT 0.0714 15.6762 0.133 15.8032 ;
		RECT 0.0714 15.8032 0.133 15.9556 ;
		RECT 0 15.9429 0.133 15.9556 ;
		RECT 0.0714 15.9556 0.133 16.0825 ;
		RECT 0.0714 16.0825 0.133 16.2222 ;
		RECT 0.0714 16.2222 0.133 16.3492 ;
		RECT 0.0714 16.3492 0.133 16.4762 ;
		RECT 0.0714 16.4762 0.133 16.6032 ;
		RECT 0.0714 16.6032 0.133 16.7556 ;
		RECT 0 16.7429 0.133 16.7556 ;
		RECT 0.0714 16.7556 0.133 16.8825 ;
		RECT 0.0714 16.8825 0.133 17.0222 ;
		RECT 0.0714 17.0222 0.133 17.1492 ;
		RECT 0.0714 17.1492 0.133 17.2762 ;
		RECT 0.0714 17.2762 0.133 17.4032 ;
		RECT 0.0714 17.4032 0.133 17.5556 ;
		RECT 0 17.5429 0.133 17.5556 ;
		RECT 0.0714 17.5556 0.133 17.6825 ;
		RECT 0.0714 17.6825 0.133 18.6667 ;
		RECT 0 17.8222 0.133 18.6667 ;
		RECT 0.0714 18.6667 0.133 18.7937 ;
		RECT 0.0714 18.7937 0.133 19.0603 ;
		RECT 0 18.9333 0.133 19.0603 ;
		RECT 0.0714 19.0603 0.133 19.2 ;
		RECT 0 19.4667 0.133 19.5937 ;
		RECT 0.0714 19.5937 0.133 19.7333 ;
		RECT 0 20.5333 0.133 20.673 ;
		RECT 0 21.4603 0.133 21.7397 ;
		RECT 0 22.0063 0.133 22.2603 ;
		RECT 0 22.4 0.133 22.527 ;
		RECT 0 23.073 0.133 23.2 ;
		RECT 0.0714 23.2 0.133 23.327 ;
		RECT 0 23.7333 0.133 23.746 ;
		RECT 0 23.8857 0.133 24.2794 ;
		RECT 0 24.419 0.133 25.3587 ;
		RECT 0.0714 25.3587 0.133 25.4857 ;
		RECT 0.0714 25.4857 0.133 25.6381 ;
		RECT 0 25.6254 0.133 25.6381 ;
		RECT 0.0714 25.6381 0.133 25.7651 ;
		RECT 0.0714 25.7651 0.133 25.8921 ;
		RECT 0.0714 25.8921 0.133 26.019 ;
		RECT 0.0714 26.019 0.133 26.1587 ;
		RECT 0.0714 26.1587 0.133 26.2857 ;
		RECT 0.0714 26.2857 0.133 26.4381 ;
		RECT 0 26.4254 0.133 26.4381 ;
		RECT 0.0714 26.4381 0.133 26.5651 ;
		RECT 0.0714 26.5651 0.133 26.6921 ;
		RECT 0.0714 26.6921 0.133 26.819 ;
		RECT 0.0714 26.819 0.133 26.9587 ;
		RECT 0.0714 26.9587 0.133 27.0857 ;
		RECT 0.0714 27.0857 0.133 27.2381 ;
		RECT 0 27.2254 0.133 27.2381 ;
		RECT 0.0714 27.2381 0.133 27.3651 ;
		RECT 0.0714 27.3651 0.133 27.4921 ;
		RECT 0.0714 27.4921 0.133 27.619 ;
		RECT 0.0714 27.619 0.133 27.7587 ;
		RECT 0.0714 27.7587 0.133 27.8857 ;
		RECT 0.0714 27.8857 0.133 28.0381 ;
		RECT 0 28.0254 0.133 28.0381 ;
		RECT 0.0714 28.0381 0.133 28.1651 ;
		RECT 0.0714 28.1651 0.133 28.2921 ;
		RECT 0.0714 28.2921 0.133 28.419 ;
		RECT 0.0714 28.419 0.133 28.5587 ;
		RECT 0.0714 28.5587 0.133 28.6857 ;
		RECT 0.0714 28.6857 0.133 28.8381 ;
		RECT 0 28.8254 0.133 28.8381 ;
		RECT 0.0714 28.8381 0.133 28.9651 ;
		RECT 0.0714 28.9651 0.133 29.0921 ;
		RECT 0.0714 29.0921 0.133 29.219 ;
		RECT 0.0714 29.219 0.133 29.3587 ;
		RECT 0.0714 29.3587 0.133 29.4857 ;
		RECT 0.0714 29.4857 0.133 29.6381 ;
		RECT 0 29.6254 0.133 29.6381 ;
		RECT 0.0714 29.6381 0.133 29.7651 ;
		RECT 0.0714 29.7651 0.133 29.8921 ;
		RECT 0.0714 29.8921 0.133 30.019 ;
		RECT 0.0714 30.019 0.133 30.1587 ;
		RECT 0.0714 30.1587 0.133 30.2857 ;
		RECT 0.0714 30.2857 0.133 30.4381 ;
		RECT 0 30.4254 0.133 30.4381 ;
		RECT 0.0714 30.4381 0.133 30.5651 ;
		RECT 0.0714 30.5651 0.133 30.6921 ;
		RECT 0.0714 30.6921 0.133 30.819 ;
		RECT 0.0714 30.819 0.133 30.9587 ;
		RECT 0.0714 30.9587 0.133 31.0857 ;
		RECT 0.0714 31.0857 0.133 31.2381 ;
		RECT 0 31.2254 0.133 31.2381 ;
		RECT 0.0714 31.2381 0.133 31.3651 ;
		RECT 0.0714 31.3651 0.133 31.4921 ;
		RECT 0.0714 31.4921 0.133 31.619 ;
		RECT 0.0714 31.619 0.133 31.7587 ;
		RECT 0.0714 31.7587 0.133 31.8857 ;
		RECT 0.0714 31.8857 0.133 32.0381 ;
		RECT 0 32.0254 0.133 32.0381 ;
		RECT 0.0714 32.0381 0.133 32.1651 ;
		RECT 0.0714 32.1651 0.133 32.2921 ;
		RECT 0.0714 32.2921 0.133 32.419 ;
		RECT 0.0714 32.419 0.133 32.5587 ;
		RECT 0.0714 32.5587 0.133 32.6857 ;
		RECT 0.0714 32.6857 0.133 32.8381 ;
		RECT 0 32.8254 0.133 32.8381 ;
		RECT 0.0714 32.8381 0.133 32.9651 ;
		RECT 0.0714 32.9651 0.133 33.0921 ;
		RECT 0.0714 33.0921 0.133 33.219 ;
		RECT 0.0714 33.219 0.133 33.3587 ;
		RECT 0.0714 33.3587 0.133 33.4857 ;
		RECT 0.0714 33.4857 0.133 33.6381 ;
		RECT 0 33.6254 0.133 33.6381 ;
		RECT 0.0714 33.6381 0.133 33.7651 ;
		RECT 0.0714 33.7651 0.133 33.8921 ;
		RECT 0.0714 33.8921 0.133 34.019 ;
		RECT 0.0714 34.019 0.133 34.1587 ;
		RECT 0.0714 34.1587 0.133 34.2857 ;
		RECT 0.0714 34.2857 0.133 34.4381 ;
		RECT 0 34.4254 0.133 34.4381 ;
		RECT 0.0714 34.4381 0.133 34.5651 ;
		RECT 0.0714 34.5651 0.133 34.6921 ;
		RECT 0.0714 34.6921 0.133 34.819 ;
		RECT 0.0714 34.819 0.133 34.9587 ;
		RECT 0.0714 34.9587 0.133 35.0857 ;
		RECT 0.0714 35.0857 0.133 35.2381 ;
		RECT 0 35.2254 0.133 35.2381 ;
		RECT 0.0714 35.2381 0.133 35.3651 ;
		RECT 0.0714 35.3651 0.133 35.4921 ;
		RECT 0.0714 35.4921 0.133 35.619 ;
		RECT 0.0714 35.619 0.133 35.7587 ;
		RECT 0.0714 35.7587 0.133 35.8857 ;
		RECT 0.0714 35.8857 0.133 36.0381 ;
		RECT 0 36.0254 0.133 36.0381 ;
		RECT 0.0714 36.0381 0.133 36.1651 ;
		RECT 0.0714 36.1651 0.133 36.2921 ;
		RECT 0.0714 36.2921 0.133 36.419 ;
		RECT 0.0714 36.419 0.133 36.5587 ;
		RECT 0.0714 36.5587 0.133 36.6857 ;
		RECT 0.0714 36.6857 0.133 36.8381 ;
		RECT 0 36.8254 0.133 36.8381 ;
		RECT 0.0714 36.8381 0.133 36.9651 ;
		RECT 0.0714 36.9651 0.133 37.0921 ;
		RECT 0.0714 37.0921 0.133 37.219 ;
		RECT 0.0714 37.219 0.133 37.3587 ;
		RECT 0.0714 37.3587 0.133 37.4857 ;
		RECT 0.0714 37.4857 0.133 37.6381 ;
		RECT 0 37.6254 0.133 37.6381 ;
		RECT 0.0714 37.6381 0.133 37.7651 ;
		RECT 0.0714 37.7651 0.133 37.8921 ;
		RECT 0.0714 37.8921 0.133 38.019 ;
		RECT 0.0714 38.019 0.133 38.1587 ;
		RECT 0.0714 38.1587 0.133 38.2857 ;
		RECT 0.0714 38.2857 0.133 38.4381 ;
		RECT 0 38.4254 0.133 38.4381 ;
		RECT 0.0714 38.4381 0.133 38.5651 ;
		RECT 0.0714 38.5651 0.133 38.6921 ;
		RECT 0.0714 38.6921 0.133 38.819 ;
		RECT 0.0714 38.819 0.133 38.9587 ;
		RECT 0.0714 38.9587 0.133 39.0857 ;
		RECT 0.0714 39.0857 0.133 39.2381 ;
		RECT 0 39.2254 0.133 39.2381 ;
		RECT 0.0714 39.2381 0.133 39.3651 ;
		RECT 0.0714 39.3651 0.133 39.4921 ;
		RECT 0.0714 39.4921 0.133 39.619 ;
		RECT 0.0714 39.619 0.133 39.7587 ;
		RECT 0.0714 39.7587 0.133 39.8857 ;
		RECT 0.0714 39.8857 0.133 40.0381 ;
		RECT 0 40.0254 0.133 40.0381 ;
		RECT 0.0714 40.0381 0.133 40.1651 ;
		RECT 0.0714 40.1651 0.133 40.2921 ;
		RECT 0.0714 40.2921 0.133 40.419 ;
		RECT 0.0714 40.419 0.133 40.5587 ;
		RECT 0.0714 40.5587 0.133 40.6857 ;
		RECT 0.0714 40.6857 0.133 40.8381 ;
		RECT 0 40.8254 0.133 40.8381 ;
		RECT 0.0714 40.8381 0.133 40.9651 ;
		RECT 0.0714 40.9651 0.133 41.0921 ;
		RECT 0.0714 41.0921 0.133 41.219 ;
		RECT 0.0714 41.219 0.133 41.3587 ;
		RECT 0.0714 41.3587 0.133 41.4857 ;
		RECT 0.0714 41.4857 0.133 41.6381 ;
		RECT 0 41.6254 0.133 41.6381 ;
		RECT 0.0714 41.6381 0.133 41.7651 ;
		RECT 0.0714 41.7651 0.133 41.8921 ;
		RECT 0.0714 41.8921 0.133 42.019 ;
		RECT 0.0714 42.019 0.133 42.1587 ;
		RECT 0.0714 42.1587 0.133 42.2857 ;
		RECT 0.0714 42.2857 0.133 42.4381 ;
		RECT 0 42.4254 0.133 42.4381 ;
		RECT 0.0714 42.4381 0.133 42.5651 ;
		RECT 0.0714 42.5651 0.133 42.6921 ;
		RECT 0.0714 42.6921 0.133 42.819 ;
		RECT 0.0714 42.819 0.133 42.9587 ;
		RECT 0.0714 42.9587 0.133 43.0857 ;
		RECT 0.0714 43.0857 0.133 43.2381 ;
		RECT 0 43.2254 0.133 43.2381 ;
		RECT 0.0714 43.2381 0.133 43.3651 ;
		RECT 0.0714 43.3651 0.133 43.4921 ;
		RECT 0.0714 43.4921 0.133 43.619 ;
		RECT 0.0714 43.619 0.133 43.746 ;
		RECT 0 43.8857 0.133 43.981 ;
		 LAYER M3 ;
		RECT 0.0714 22.4063 0.1097 22.5079 ;
		RECT 0.0714 22.546 0.1097 22.6476 ;
		RECT 0.0714 22.6857 0.1097 22.7873 ;
		RECT 0.0714 22.8254 0.1097 22.927 ;
		RECT 0.0098 23.0794 0.0481 23.181 ;
		RECT 0.0714 23.0794 0.1097 23.181 ;
		RECT 0.0714 23.7651 0.1097 23.8667 ;
		RECT 0.0098 23.8921 0.0481 23.9937 ;
		RECT 0.0714 23.8921 0.1097 23.9937 ;
		RECT 0.0098 24.0444 0.0481 24.146 ;
		RECT 0.0714 24.0444 0.1097 24.146 ;
		RECT 0.0098 24.1714 0.0481 24.273 ;
		RECT 0.0714 24.1714 0.1097 24.273 ;
		RECT 0.0714 24.2984 0.1097 24.4 ;
		RECT 0.0098 24.4254 0.0481 24.527 ;
		RECT 0.0714 24.4254 0.1097 24.527 ;
		RECT 0.0098 24.5524 0.0481 24.654 ;
		RECT 0.0714 24.5524 0.1097 24.654 ;
		RECT 0.0098 24.6794 0.0481 24.781 ;
		RECT 0.0714 24.6794 0.1097 24.781 ;
		RECT 0.0098 24.819 0.0481 24.9206 ;
		RECT 0.0714 24.819 0.1097 24.9206 ;
		RECT 0.0098 24.946 0.0481 25.0476 ;
		RECT 0.0714 24.946 0.1097 25.0476 ;
		RECT 0.0098 25.0857 0.0481 25.1873 ;
		RECT 0.0714 25.0857 0.1097 25.1873 ;
		RECT 0.0714 0.1143 0.1097 0.2159 ;
		RECT 0.0714 43.7651 0.1097 43.8667 ;
		RECT 0.0098 17.8857 0.0481 17.9873 ;
		RECT 0.0714 17.8857 0.1097 17.9873 ;
		RECT 0.0098 18.0127 0.0481 18.1143 ;
		RECT 0.0714 18.0127 0.1097 18.1143 ;
		RECT 0.0098 18.1524 0.0481 18.254 ;
		RECT 0.0714 18.1524 0.1097 18.254 ;
		RECT 0.0098 18.2794 0.0481 18.381 ;
		RECT 0.0714 18.2794 0.1097 18.381 ;
		RECT 0.0098 18.419 0.0481 18.5206 ;
		RECT 0.0098 18.546 0.0481 18.6476 ;
		RECT 0.0714 18.546 0.1097 18.6476 ;
		RECT 0.0098 18.9524 0.0481 19.054 ;
		RECT 0.0098 19.219 0.0481 19.3206 ;
		RECT 0.0714 19.346 0.1097 19.4476 ;
		RECT 0.0098 19.4857 0.0481 19.5873 ;
		RECT 0.0714 19.4857 0.1097 19.5873 ;
		RECT 0.0098 19.8794 0.0481 19.981 ;
		RECT 0.0714 20.019 0.1097 20.1206 ;
		RECT 0.0098 20.146 0.0481 20.2476 ;
		RECT 0.0714 20.4127 0.1097 20.5143 ;
		RECT 0.0098 20.5524 0.0481 20.654 ;
		RECT 0.0714 20.5524 0.1097 20.654 ;
		RECT 0.0098 20.6921 0.0481 20.7937 ;
		RECT 0.0098 20.819 0.0481 20.9206 ;
		RECT 0.0098 20.946 0.0481 21.0476 ;
		RECT 0.0714 21.3397 0.1097 21.4413 ;
		RECT 0.0098 21.4794 0.0481 21.581 ;
		RECT 0.0714 21.4794 0.1097 21.581 ;
		RECT 0.0098 21.619 0.0481 21.7206 ;
		RECT 0.0714 21.619 0.1097 21.7206 ;
		RECT 0.0714 21.7587 0.1097 21.8603 ;
		RECT 0.0098 22.0127 0.0481 22.1143 ;
		RECT 0.0714 22.0127 0.1097 22.1143 ;
		RECT 0.0098 22.1524 0.0481 22.254 ;
		RECT 0.0714 22.1524 0.1097 22.254 ;
		RECT 0.0098 22.4063 0.0481 22.5079 ;
		 LAYER M3 SPACING 0.012 ;
		RECT 0.0714 22.4063 0.1097 22.5079 ;
		RECT 0.0714 22.546 0.1097 22.6476 ;
		RECT 0.0714 22.6857 0.1097 22.7873 ;
		RECT 0.0714 22.8254 0.1097 22.927 ;
		RECT 0.0098 23.0794 0.0481 23.181 ;
		RECT 0.0714 23.0794 0.1097 23.181 ;
		RECT 0.0714 23.7651 0.1097 23.8667 ;
		RECT 0.0098 23.8921 0.0481 23.9937 ;
		RECT 0.0714 23.8921 0.1097 23.9937 ;
		RECT 0.0098 24.0444 0.0481 24.146 ;
		RECT 0.0714 24.0444 0.1097 24.146 ;
		RECT 0.0098 24.1714 0.0481 24.273 ;
		RECT 0.0714 24.1714 0.1097 24.273 ;
		RECT 0.0714 24.2984 0.1097 24.4 ;
		RECT 0.0098 24.4254 0.0481 24.527 ;
		RECT 0.0714 24.4254 0.1097 24.527 ;
		RECT 0.0098 24.5524 0.0481 24.654 ;
		RECT 0.0714 24.5524 0.1097 24.654 ;
		RECT 0.0098 24.6794 0.0481 24.781 ;
		RECT 0.0714 24.6794 0.1097 24.781 ;
		RECT 0.0098 24.819 0.0481 24.9206 ;
		RECT 0.0714 24.819 0.1097 24.9206 ;
		RECT 0.0098 24.946 0.0481 25.0476 ;
		RECT 0.0714 24.946 0.1097 25.0476 ;
		RECT 0.0098 25.0857 0.0481 25.1873 ;
		RECT 0.0714 25.0857 0.1097 25.1873 ;
		RECT 0.0714 0.1143 0.1097 0.2159 ;
		RECT 0.0714 43.7651 0.1097 43.8667 ;
		RECT 0.0098 17.8857 0.0481 17.9873 ;
		RECT 0.0714 17.8857 0.1097 17.9873 ;
		RECT 0.0098 18.0127 0.0481 18.1143 ;
		RECT 0.0714 18.0127 0.1097 18.1143 ;
		RECT 0.0098 18.1524 0.0481 18.254 ;
		RECT 0.0714 18.1524 0.1097 18.254 ;
		RECT 0.0098 18.2794 0.0481 18.381 ;
		RECT 0.0714 18.2794 0.1097 18.381 ;
		RECT 0.0098 18.419 0.0481 18.5206 ;
		RECT 0.0098 18.546 0.0481 18.6476 ;
		RECT 0.0714 18.546 0.1097 18.6476 ;
		RECT 0.0098 18.9524 0.0481 19.054 ;
		RECT 0.0098 19.219 0.0481 19.3206 ;
		RECT 0.0714 19.346 0.1097 19.4476 ;
		RECT 0.0098 19.4857 0.0481 19.5873 ;
		RECT 0.0714 19.4857 0.1097 19.5873 ;
		RECT 0.0098 19.8794 0.0481 19.981 ;
		RECT 0.0714 20.019 0.1097 20.1206 ;
		RECT 0.0098 20.146 0.0481 20.2476 ;
		RECT 0.0714 20.4127 0.1097 20.5143 ;
		RECT 0.0098 20.5524 0.0481 20.654 ;
		RECT 0.0714 20.5524 0.1097 20.654 ;
		RECT 0.0098 20.6921 0.0481 20.7937 ;
		RECT 0.0098 20.819 0.0481 20.9206 ;
		RECT 0.0098 20.946 0.0481 21.0476 ;
		RECT 0.0714 21.3397 0.1097 21.4413 ;
		RECT 0.0098 21.4794 0.0481 21.581 ;
		RECT 0.0714 21.4794 0.1097 21.581 ;
		RECT 0.0098 21.619 0.0481 21.7206 ;
		RECT 0.0714 21.619 0.1097 21.7206 ;
		RECT 0.0714 21.7587 0.1097 21.8603 ;
		RECT 0.0098 22.0127 0.0481 22.1143 ;
		RECT 0.0714 22.0127 0.1097 22.1143 ;
		RECT 0.0098 22.1524 0.0481 22.254 ;
		RECT 0.0714 22.1524 0.1097 22.254 ;
		RECT 0.0098 22.4063 0.0481 22.5079 ;
		 LAYER M4 SPACING 0.018 ;
		RECT 0.2105 0.4032 8.316 0.6841 ;
		RECT 8.316 0.4032 8.463 0.6841 ;
		RECT 0.2105 1.2032 8.316 1.4841 ;
		RECT 8.316 1.2032 8.463 1.4841 ;
		RECT 0.2105 2.0032 8.316 2.2841 ;
		RECT 8.316 2.0032 8.463 2.2841 ;
		RECT 0.2105 2.8032 8.316 3.0841 ;
		RECT 8.316 2.8032 8.463 3.0841 ;
		RECT 0.2105 3.6032 8.316 3.8841 ;
		RECT 8.316 3.6032 8.463 3.8841 ;
		RECT 0.2105 4.4032 8.316 4.6841 ;
		RECT 8.316 4.4032 8.463 4.6841 ;
		RECT 0.2105 5.2032 8.316 5.4841 ;
		RECT 8.316 5.2032 8.463 5.4841 ;
		RECT 0.2105 6.0032 8.316 6.2841 ;
		RECT 8.316 6.0032 8.463 6.2841 ;
		RECT 0.2105 6.8032 8.316 7.0841 ;
		RECT 8.316 6.8032 8.463 7.0841 ;
		RECT 0.2105 7.6032 8.316 7.8841 ;
		RECT 8.316 7.6032 8.463 7.8841 ;
		RECT 0.2105 8.4032 8.316 8.6841 ;
		RECT 8.316 8.4032 8.463 8.6841 ;
		RECT 0.2105 9.2032 8.316 9.4841 ;
		RECT 8.316 9.2032 8.463 9.4841 ;
		RECT 0.2105 10.0032 8.316 10.2841 ;
		RECT 8.316 10.0032 8.463 10.2841 ;
		RECT 0.2105 10.8032 8.316 11.0841 ;
		RECT 8.316 10.8032 8.463 11.0841 ;
		RECT 0.2105 11.6032 8.316 11.8841 ;
		RECT 8.316 11.6032 8.463 11.8841 ;
		RECT 0.2105 12.4032 8.316 12.6841 ;
		RECT 8.316 12.4032 8.463 12.6841 ;
		RECT 0.2105 13.2032 8.316 13.4841 ;
		RECT 8.316 13.2032 8.463 13.4841 ;
		RECT 0.2105 14.0032 8.316 14.2841 ;
		RECT 8.316 14.0032 8.463 14.2841 ;
		RECT 0.2105 14.8032 8.316 15.0841 ;
		RECT 8.316 14.8032 8.463 15.0841 ;
		RECT 0.2105 15.6032 8.316 15.8841 ;
		RECT 8.316 15.6032 8.463 15.8841 ;
		RECT 0.2105 16.4032 8.316 16.6841 ;
		RECT 8.316 16.4032 8.463 16.6841 ;
		RECT 0.2105 17.2032 8.316 17.4841 ;
		RECT 8.316 17.2032 8.463 17.4841 ;
		RECT 0.2105 18.1937 8.316 18.3317 ;
		RECT 8.316 18.1937 8.463 18.3317 ;
		RECT 0.2105 18.5222 8.316 18.627 ;
		RECT 8.316 18.5222 8.463 18.627 ;
		RECT 0.2105 18.8175 8.316 19.1603 ;
		RECT 8.316 18.8175 8.463 19.1603 ;
		RECT 0.2105 19.3508 8.316 19.6937 ;
		RECT 8.316 19.3508 8.463 19.6937 ;
		RECT 0.2105 19.8841 8.316 20.227 ;
		RECT 8.316 19.8841 8.463 20.227 ;
		RECT 0.2105 20.4175 8.316 20.7603 ;
		RECT 8.316 20.4175 8.463 20.7603 ;
		RECT 0.2105 20.9508 8.316 21.827 ;
		RECT 8.316 20.9508 8.463 21.827 ;
		RECT 0.2105 22.0175 8.316 22.8937 ;
		RECT 8.316 22.0175 8.463 22.8937 ;
		RECT 0.2105 23.0841 8.316 23.427 ;
		RECT 8.316 23.0841 8.463 23.427 ;
		RECT 0.2105 23.6175 8.316 23.9603 ;
		RECT 8.316 23.6175 8.463 23.9603 ;
		RECT 0.2105 24.1508 8.316 24.4937 ;
		RECT 8.316 24.1508 8.463 24.4937 ;
		RECT 0.2105 25.0587 8.316 25.146 ;
		RECT 8.316 25.0587 8.463 25.146 ;
		RECT 0.2105 25.6968 8.316 25.9778 ;
		RECT 8.316 25.6968 8.463 25.9778 ;
		RECT 0.2105 26.4968 8.316 26.7778 ;
		RECT 8.316 26.4968 8.463 26.7778 ;
		RECT 0.2105 27.2968 8.316 27.5778 ;
		RECT 8.316 27.2968 8.463 27.5778 ;
		RECT 0.2105 28.0968 8.316 28.3778 ;
		RECT 8.316 28.0968 8.463 28.3778 ;
		RECT 0.2105 28.8968 8.316 29.1778 ;
		RECT 8.316 28.8968 8.463 29.1778 ;
		RECT 0.2105 29.6968 8.316 29.9778 ;
		RECT 8.316 29.6968 8.463 29.9778 ;
		RECT 0.2105 30.4968 8.316 30.7778 ;
		RECT 8.316 30.4968 8.463 30.7778 ;
		RECT 0.2105 31.2968 8.316 31.5778 ;
		RECT 8.316 31.2968 8.463 31.5778 ;
		RECT 0.2105 32.0968 8.316 32.3778 ;
		RECT 8.316 32.0968 8.463 32.3778 ;
		RECT 0.2105 32.8968 8.316 33.1778 ;
		RECT 8.316 32.8968 8.463 33.1778 ;
		RECT 0.2105 33.6968 8.316 33.9778 ;
		RECT 8.316 33.6968 8.463 33.9778 ;
		RECT 0.2105 34.4968 8.316 34.7778 ;
		RECT 8.316 34.4968 8.463 34.7778 ;
		RECT 0.2105 35.2968 8.316 35.5778 ;
		RECT 8.316 35.2968 8.463 35.5778 ;
		RECT 0.2105 36.0968 8.316 36.3778 ;
		RECT 8.316 36.0968 8.463 36.3778 ;
		RECT 0.2105 36.8968 8.316 37.1778 ;
		RECT 8.316 36.8968 8.463 37.1778 ;
		RECT 0.2105 37.6968 8.316 37.9778 ;
		RECT 8.316 37.6968 8.463 37.9778 ;
		RECT 0.2105 38.4968 8.316 38.7778 ;
		RECT 8.316 38.4968 8.463 38.7778 ;
		RECT 0.2105 39.2968 8.316 39.5778 ;
		RECT 8.316 39.2968 8.463 39.5778 ;
		RECT 0.2105 40.0968 8.316 40.3778 ;
		RECT 8.316 40.0968 8.463 40.3778 ;
		RECT 0.2105 40.8968 8.316 41.1778 ;
		RECT 8.316 40.8968 8.463 41.1778 ;
		RECT 0.2105 41.6968 8.316 41.9778 ;
		RECT 8.316 41.6968 8.463 41.9778 ;
		RECT 0.2105 42.4968 8.316 42.7778 ;
		RECT 8.316 42.4968 8.463 42.7778 ;
		RECT 0.2105 43.2968 8.316 43.5778 ;
		RECT 8.316 43.2968 8.463 43.5778 ;
		 LAYER M4 ;
		RECT 0.2105 0 8.316 0.0222 ;
		RECT 8.316 0 8.463 0.0222 ;
		RECT 0.2105 24.8429 8.316 24.8683 ;
		RECT 8.316 24.8429 8.463 24.8683 ;
		RECT 0.2105 43.9587 8.316 43.981 ;
		RECT 8.316 43.9587 8.463 43.981 ;
		 LAYER M4 SPACING 0.018 ;
		RECT 0.2105 0 8.316 0.0222 ;
		RECT 8.316 0 8.463 0.0222 ;
		RECT 0.2105 24.8429 8.316 24.8683 ;
		RECT 8.316 24.8429 8.463 24.8683 ;
		RECT 0.2105 43.9587 8.316 43.981 ;
		RECT 8.316 43.9587 8.463 43.981 ;
		 LAYER V1 SPACING 0 ;
		RECT 0 0 8.463 43.981 ;
		 LAYER V2 SPACING 0 ;
		RECT 0.1097 0 8.463 43.981 ;
		RECT 0 0 0.1097 0.1143 ;
		RECT 0 0.2159 0.1097 0.2413 ;
		RECT 0 0.3429 0.1097 0.3683 ;
		RECT 0 0.4698 0.1097 0.4952 ;
		RECT 0 0.5968 0.1097 0.6222 ;
		RECT 0 0.7238 0.1097 0.7746 ;
		RECT 0 0.8762 0.1097 0.9016 ;
		RECT 0 1.0032 0.1097 1.0413 ;
		RECT 0 1.1429 0.1097 1.1683 ;
		RECT 0 1.2698 0.1097 1.2952 ;
		RECT 0 1.3968 0.1097 1.4222 ;
		RECT 0 1.5238 0.1097 1.5746 ;
		RECT 0 1.6762 0.1097 1.7016 ;
		RECT 0 1.8032 0.1097 1.8413 ;
		RECT 0 1.9429 0.1097 1.9683 ;
		RECT 0 2.0698 0.1097 2.0952 ;
		RECT 0 2.1968 0.1097 2.2222 ;
		RECT 0 2.3238 0.1097 2.3746 ;
		RECT 0 2.4762 0.1097 2.5016 ;
		RECT 0 2.6032 0.1097 2.6413 ;
		RECT 0 2.7429 0.1097 2.7683 ;
		RECT 0 2.8698 0.1097 2.8952 ;
		RECT 0 2.9968 0.1097 3.0222 ;
		RECT 0 3.1238 0.1097 3.1746 ;
		RECT 0 3.2762 0.1097 3.3016 ;
		RECT 0 3.4032 0.1097 3.4413 ;
		RECT 0 3.5429 0.1097 3.5683 ;
		RECT 0 3.6698 0.1097 3.6952 ;
		RECT 0 3.7968 0.1097 3.8222 ;
		RECT 0 3.9238 0.1097 3.9746 ;
		RECT 0 4.0762 0.1097 4.1016 ;
		RECT 0 4.2032 0.1097 4.2413 ;
		RECT 0 4.3429 0.1097 4.3683 ;
		RECT 0 4.4698 0.1097 4.4952 ;
		RECT 0 4.5968 0.1097 4.6222 ;
		RECT 0 4.7238 0.1097 4.7746 ;
		RECT 0 4.8762 0.1097 4.9016 ;
		RECT 0 5.0032 0.1097 5.0413 ;
		RECT 0 5.1429 0.1097 5.1683 ;
		RECT 0 5.2698 0.1097 5.2952 ;
		RECT 0 5.3968 0.1097 5.4222 ;
		RECT 0 5.5238 0.1097 5.5746 ;
		RECT 0 5.6762 0.1097 5.7016 ;
		RECT 0 5.8032 0.1097 5.8413 ;
		RECT 0 5.9429 0.1097 5.9683 ;
		RECT 0 6.0698 0.1097 6.0952 ;
		RECT 0 6.1968 0.1097 6.2222 ;
		RECT 0 6.3238 0.1097 6.3746 ;
		RECT 0 6.4762 0.1097 6.5016 ;
		RECT 0 6.6032 0.1097 6.6413 ;
		RECT 0 6.7429 0.1097 6.7683 ;
		RECT 0 6.8698 0.1097 6.8952 ;
		RECT 0 6.9968 0.1097 7.0222 ;
		RECT 0 7.1238 0.1097 7.1746 ;
		RECT 0 7.2762 0.1097 7.3016 ;
		RECT 0 7.4032 0.1097 7.4413 ;
		RECT 0 7.5429 0.1097 7.5683 ;
		RECT 0 7.6698 0.1097 7.6952 ;
		RECT 0 7.7968 0.1097 7.8222 ;
		RECT 0 7.9238 0.1097 7.9746 ;
		RECT 0 8.0762 0.1097 8.1016 ;
		RECT 0 8.2032 0.1097 8.2413 ;
		RECT 0 8.3429 0.1097 8.3683 ;
		RECT 0 8.4698 0.1097 8.4952 ;
		RECT 0 8.5968 0.1097 8.6222 ;
		RECT 0 8.7238 0.1097 8.7746 ;
		RECT 0 8.8762 0.1097 8.9016 ;
		RECT 0 9.0032 0.1097 9.0413 ;
		RECT 0 9.1429 0.1097 9.1683 ;
		RECT 0 9.2698 0.1097 9.2952 ;
		RECT 0 9.3968 0.1097 9.4222 ;
		RECT 0 9.5238 0.1097 9.5746 ;
		RECT 0 9.6762 0.1097 9.7016 ;
		RECT 0 9.8032 0.1097 9.8413 ;
		RECT 0 9.9429 0.1097 9.9683 ;
		RECT 0 10.0698 0.1097 10.0952 ;
		RECT 0 10.1968 0.1097 10.2222 ;
		RECT 0 10.3238 0.1097 10.3746 ;
		RECT 0 10.4762 0.1097 10.5016 ;
		RECT 0 10.6032 0.1097 10.6413 ;
		RECT 0 10.7429 0.1097 10.7683 ;
		RECT 0 10.8698 0.1097 10.8952 ;
		RECT 0 10.9968 0.1097 11.0222 ;
		RECT 0 11.1238 0.1097 11.1746 ;
		RECT 0 11.2762 0.1097 11.3016 ;
		RECT 0 11.4032 0.1097 11.4413 ;
		RECT 0 11.5429 0.1097 11.5683 ;
		RECT 0 11.6698 0.1097 11.6952 ;
		RECT 0 11.7968 0.1097 11.8222 ;
		RECT 0 11.9238 0.1097 11.9746 ;
		RECT 0 12.0762 0.1097 12.1016 ;
		RECT 0 12.2032 0.1097 12.2413 ;
		RECT 0 12.3429 0.1097 12.3683 ;
		RECT 0 12.4698 0.1097 12.4952 ;
		RECT 0 12.5968 0.1097 12.6222 ;
		RECT 0 12.7238 0.1097 12.7746 ;
		RECT 0 12.8762 0.1097 12.9016 ;
		RECT 0 13.0032 0.1097 13.0413 ;
		RECT 0 13.1429 0.1097 13.1683 ;
		RECT 0 13.2698 0.1097 13.2952 ;
		RECT 0 13.3968 0.1097 13.4222 ;
		RECT 0 13.5238 0.1097 13.5746 ;
		RECT 0 13.6762 0.1097 13.7016 ;
		RECT 0 13.8032 0.1097 13.8413 ;
		RECT 0 13.9429 0.1097 13.9683 ;
		RECT 0 14.0698 0.1097 14.0952 ;
		RECT 0 14.1968 0.1097 14.2222 ;
		RECT 0 14.3238 0.1097 14.3746 ;
		RECT 0 14.4762 0.1097 14.5016 ;
		RECT 0 14.6032 0.1097 14.6413 ;
		RECT 0 14.7429 0.1097 14.7683 ;
		RECT 0 14.8698 0.1097 14.8952 ;
		RECT 0 14.9968 0.1097 15.0222 ;
		RECT 0 15.1238 0.1097 15.1746 ;
		RECT 0 15.2762 0.1097 15.3016 ;
		RECT 0 15.4032 0.1097 15.4413 ;
		RECT 0 15.5429 0.1097 15.5683 ;
		RECT 0 15.6698 0.1097 15.6952 ;
		RECT 0 15.7968 0.1097 15.8222 ;
		RECT 0 15.9238 0.1097 15.9746 ;
		RECT 0 16.0762 0.1097 16.1016 ;
		RECT 0 16.2032 0.1097 16.2413 ;
		RECT 0 16.3429 0.1097 16.3683 ;
		RECT 0 16.4698 0.1097 16.4952 ;
		RECT 0 16.5968 0.1097 16.6222 ;
		RECT 0 16.7238 0.1097 16.7746 ;
		RECT 0 16.8762 0.1097 16.9016 ;
		RECT 0 17.0032 0.1097 17.0413 ;
		RECT 0 17.1429 0.1097 17.1683 ;
		RECT 0 17.2698 0.1097 17.2952 ;
		RECT 0 17.3968 0.1097 17.4222 ;
		RECT 0 17.5238 0.1097 17.5746 ;
		RECT 0 17.6762 0.1097 17.7016 ;
		RECT 0 17.8032 0.1097 18.6857 ;
		RECT 0 18.7873 0.1097 18.8127 ;
		RECT 0 18.9143 0.1097 19.0794 ;
		RECT 0 19.181 0.1097 19.219 ;
		RECT 0 19.3206 0.1097 19.346 ;
		RECT 0 19.4476 0.1097 19.6127 ;
		RECT 0 19.7143 0.1097 19.7524 ;
		RECT 0 19.854 0.1097 19.8794 ;
		RECT 0 19.981 0.1097 20.019 ;
		RECT 0 20.1206 0.1097 20.146 ;
		RECT 0 20.2476 0.1097 20.2857 ;
		RECT 0 20.3873 0.1097 20.4127 ;
		RECT 0 20.5143 0.1097 20.6921 ;
		RECT 0 20.7937 0.1097 20.819 ;
		RECT 0 20.9206 0.1097 20.946 ;
		RECT 0 21.0476 0.1097 21.0857 ;
		RECT 0 21.1873 0.1097 21.2127 ;
		RECT 0 21.3143 0.1097 21.3397 ;
		RECT 0 21.4413 0.1097 21.7587 ;
		RECT 0 21.8603 0.1097 21.8857 ;
		RECT 0 21.9873 0.1097 22.2794 ;
		RECT 0 22.381 0.1097 22.546 ;
		RECT 0 22.6476 0.1097 22.6857 ;
		RECT 0 22.7873 0.1097 22.8254 ;
		RECT 0 22.927 0.1097 22.9524 ;
		RECT 0 23.054 0.1097 23.219 ;
		RECT 0 23.3206 0.1097 23.346 ;
		RECT 0 23.4476 0.1097 23.473 ;
		RECT 0 23.5746 0.1097 23.6127 ;
		RECT 0 23.7143 0.1097 23.7651 ;
		RECT 0 23.8667 0.1097 24.2984 ;
		RECT 0 24.4 0.1097 25.3778 ;
		RECT 0 25.4794 0.1097 25.5048 ;
		RECT 0 25.6063 0.1097 25.6571 ;
		RECT 0 25.7587 0.1097 25.7841 ;
		RECT 0 25.8857 0.1097 25.9111 ;
		RECT 0 26.0127 0.1097 26.0381 ;
		RECT 0 26.1397 0.1097 26.1778 ;
		RECT 0 26.2794 0.1097 26.3048 ;
		RECT 0 26.4063 0.1097 26.4571 ;
		RECT 0 26.5587 0.1097 26.5841 ;
		RECT 0 26.6857 0.1097 26.7111 ;
		RECT 0 26.8127 0.1097 26.8381 ;
		RECT 0 26.9397 0.1097 26.9778 ;
		RECT 0 27.0794 0.1097 27.1048 ;
		RECT 0 27.2063 0.1097 27.2571 ;
		RECT 0 27.3587 0.1097 27.3841 ;
		RECT 0 27.4857 0.1097 27.5111 ;
		RECT 0 27.6127 0.1097 27.6381 ;
		RECT 0 27.7397 0.1097 27.7778 ;
		RECT 0 27.8794 0.1097 27.9048 ;
		RECT 0 28.0063 0.1097 28.0571 ;
		RECT 0 28.1587 0.1097 28.1841 ;
		RECT 0 28.2857 0.1097 28.3111 ;
		RECT 0 28.4127 0.1097 28.4381 ;
		RECT 0 28.5397 0.1097 28.5778 ;
		RECT 0 28.6794 0.1097 28.7048 ;
		RECT 0 28.8063 0.1097 28.8571 ;
		RECT 0 28.9587 0.1097 28.9841 ;
		RECT 0 29.0857 0.1097 29.1111 ;
		RECT 0 29.2127 0.1097 29.2381 ;
		RECT 0 29.3397 0.1097 29.3778 ;
		RECT 0 29.4794 0.1097 29.5048 ;
		RECT 0 29.6063 0.1097 29.6571 ;
		RECT 0 29.7587 0.1097 29.7841 ;
		RECT 0 29.8857 0.1097 29.9111 ;
		RECT 0 30.0127 0.1097 30.0381 ;
		RECT 0 30.1397 0.1097 30.1778 ;
		RECT 0 30.2794 0.1097 30.3048 ;
		RECT 0 30.4063 0.1097 30.4571 ;
		RECT 0 30.5587 0.1097 30.5841 ;
		RECT 0 30.6857 0.1097 30.7111 ;
		RECT 0 30.8127 0.1097 30.8381 ;
		RECT 0 30.9397 0.1097 30.9778 ;
		RECT 0 31.0794 0.1097 31.1048 ;
		RECT 0 31.2063 0.1097 31.2571 ;
		RECT 0 31.3587 0.1097 31.3841 ;
		RECT 0 31.4857 0.1097 31.5111 ;
		RECT 0 31.6127 0.1097 31.6381 ;
		RECT 0 31.7397 0.1097 31.7778 ;
		RECT 0 31.8794 0.1097 31.9048 ;
		RECT 0 32.0063 0.1097 32.0571 ;
		RECT 0 32.1587 0.1097 32.1841 ;
		RECT 0 32.2857 0.1097 32.3111 ;
		RECT 0 32.4127 0.1097 32.4381 ;
		RECT 0 32.5397 0.1097 32.5778 ;
		RECT 0 32.6794 0.1097 32.7048 ;
		RECT 0 32.8063 0.1097 32.8571 ;
		RECT 0 32.9587 0.1097 32.9841 ;
		RECT 0 33.0857 0.1097 33.1111 ;
		RECT 0 33.2127 0.1097 33.2381 ;
		RECT 0 33.3397 0.1097 33.3778 ;
		RECT 0 33.4794 0.1097 33.5048 ;
		RECT 0 33.6063 0.1097 33.6571 ;
		RECT 0 33.7587 0.1097 33.7841 ;
		RECT 0 33.8857 0.1097 33.9111 ;
		RECT 0 34.0127 0.1097 34.0381 ;
		RECT 0 34.1397 0.1097 34.1778 ;
		RECT 0 34.2794 0.1097 34.3048 ;
		RECT 0 34.4063 0.1097 34.4571 ;
		RECT 0 34.5587 0.1097 34.5841 ;
		RECT 0 34.6857 0.1097 34.7111 ;
		RECT 0 34.8127 0.1097 34.8381 ;
		RECT 0 34.9397 0.1097 34.9778 ;
		RECT 0 35.0794 0.1097 35.1048 ;
		RECT 0 35.2063 0.1097 35.2571 ;
		RECT 0 35.3587 0.1097 35.3841 ;
		RECT 0 35.4857 0.1097 35.5111 ;
		RECT 0 35.6127 0.1097 35.6381 ;
		RECT 0 35.7397 0.1097 35.7778 ;
		RECT 0 35.8794 0.1097 35.9048 ;
		RECT 0 36.0063 0.1097 36.0571 ;
		RECT 0 36.1587 0.1097 36.1841 ;
		RECT 0 36.2857 0.1097 36.3111 ;
		RECT 0 36.4127 0.1097 36.4381 ;
		RECT 0 36.5397 0.1097 36.5778 ;
		RECT 0 36.6794 0.1097 36.7048 ;
		RECT 0 36.8063 0.1097 36.8571 ;
		RECT 0 36.9587 0.1097 36.9841 ;
		RECT 0 37.0857 0.1097 37.1111 ;
		RECT 0 37.2127 0.1097 37.2381 ;
		RECT 0 37.3397 0.1097 37.3778 ;
		RECT 0 37.4794 0.1097 37.5048 ;
		RECT 0 37.6063 0.1097 37.6571 ;
		RECT 0 37.7587 0.1097 37.7841 ;
		RECT 0 37.8857 0.1097 37.9111 ;
		RECT 0 38.0127 0.1097 38.0381 ;
		RECT 0 38.1397 0.1097 38.1778 ;
		RECT 0 38.2794 0.1097 38.3048 ;
		RECT 0 38.4063 0.1097 38.4571 ;
		RECT 0 38.5587 0.1097 38.5841 ;
		RECT 0 38.6857 0.1097 38.7111 ;
		RECT 0 38.8127 0.1097 38.8381 ;
		RECT 0 38.9397 0.1097 38.9778 ;
		RECT 0 39.0794 0.1097 39.1048 ;
		RECT 0 39.2063 0.1097 39.2571 ;
		RECT 0 39.3587 0.1097 39.3841 ;
		RECT 0 39.4857 0.1097 39.5111 ;
		RECT 0 39.6127 0.1097 39.6381 ;
		RECT 0 39.7397 0.1097 39.7778 ;
		RECT 0 39.8794 0.1097 39.9048 ;
		RECT 0 40.0063 0.1097 40.0571 ;
		RECT 0 40.1587 0.1097 40.1841 ;
		RECT 0 40.2857 0.1097 40.3111 ;
		RECT 0 40.4127 0.1097 40.4381 ;
		RECT 0 40.5397 0.1097 40.5778 ;
		RECT 0 40.6794 0.1097 40.7048 ;
		RECT 0 40.8063 0.1097 40.8571 ;
		RECT 0 40.9587 0.1097 40.9841 ;
		RECT 0 41.0857 0.1097 41.1111 ;
		RECT 0 41.2127 0.1097 41.2381 ;
		RECT 0 41.3397 0.1097 41.3778 ;
		RECT 0 41.4794 0.1097 41.5048 ;
		RECT 0 41.6063 0.1097 41.6571 ;
		RECT 0 41.7587 0.1097 41.7841 ;
		RECT 0 41.8857 0.1097 41.9111 ;
		RECT 0 42.0127 0.1097 42.0381 ;
		RECT 0 42.1397 0.1097 42.1778 ;
		RECT 0 42.2794 0.1097 42.3048 ;
		RECT 0 42.4063 0.1097 42.4571 ;
		RECT 0 42.5587 0.1097 42.5841 ;
		RECT 0 42.6857 0.1097 42.7111 ;
		RECT 0 42.8127 0.1097 42.8381 ;
		RECT 0 42.9397 0.1097 42.9778 ;
		RECT 0 43.0794 0.1097 43.1048 ;
		RECT 0 43.2063 0.1097 43.2571 ;
		RECT 0 43.3587 0.1097 43.3841 ;
		RECT 0 43.4857 0.1097 43.5111 ;
		RECT 0 43.6127 0.1097 43.6381 ;
		RECT 0 43.7397 0.1097 43.7651 ;
		RECT 0 43.8667 0.1097 43.981 ;
		 LAYER V2 ;
		RECT 0.0481 0.2413 0.1097 0.3683 ;
		RECT 0.0481 0.3683 0.1097 0.4952 ;
		RECT 0.0481 0.4952 0.1097 0.6222 ;
		RECT 0.0481 0.6222 0.1097 0.7746 ;
		RECT 0.0481 0.7746 0.1097 0.9016 ;
		RECT 0.0481 0.9016 0.1097 1.0413 ;
		RECT 0.0481 1.0413 0.1097 1.1683 ;
		RECT 0.0481 1.1683 0.1097 1.2952 ;
		RECT 0.0481 1.2952 0.1097 1.4222 ;
		RECT 0.0481 1.4222 0.1097 1.5746 ;
		RECT 0.0481 1.5746 0.1097 1.7016 ;
		RECT 0.0481 1.7016 0.1097 1.8413 ;
		RECT 0.0481 1.8413 0.1097 1.9683 ;
		RECT 0.0481 1.9683 0.1097 2.0952 ;
		RECT 0.0481 2.0952 0.1097 2.2222 ;
		RECT 0.0481 2.2222 0.1097 2.3746 ;
		RECT 0.0481 2.3746 0.1097 2.5016 ;
		RECT 0.0481 2.5016 0.1097 2.6413 ;
		RECT 0.0481 2.6413 0.1097 2.7683 ;
		RECT 0.0481 2.7683 0.1097 2.8952 ;
		RECT 0.0481 2.8952 0.1097 3.0222 ;
		RECT 0.0481 3.0222 0.1097 3.1746 ;
		RECT 0.0481 3.1746 0.1097 3.3016 ;
		RECT 0.0481 3.3016 0.1097 3.4413 ;
		RECT 0.0481 3.4413 0.1097 3.5683 ;
		RECT 0.0481 3.5683 0.1097 3.6952 ;
		RECT 0.0481 3.6952 0.1097 3.8222 ;
		RECT 0.0481 3.8222 0.1097 3.9746 ;
		RECT 0.0481 3.9746 0.1097 4.1016 ;
		RECT 0.0481 4.1016 0.1097 4.2413 ;
		RECT 0.0481 4.2413 0.1097 4.3683 ;
		RECT 0.0481 4.3683 0.1097 4.4952 ;
		RECT 0.0481 4.4952 0.1097 4.6222 ;
		RECT 0.0481 4.6222 0.1097 4.7746 ;
		RECT 0.0481 4.7746 0.1097 4.9016 ;
		RECT 0.0481 4.9016 0.1097 5.0413 ;
		RECT 0.0481 5.0413 0.1097 5.1683 ;
		RECT 0.0481 5.1683 0.1097 5.2952 ;
		RECT 0.0481 5.2952 0.1097 5.4222 ;
		RECT 0.0481 5.4222 0.1097 5.5746 ;
		RECT 0.0481 5.5746 0.1097 5.7016 ;
		RECT 0.0481 5.7016 0.1097 5.8413 ;
		RECT 0.0481 5.8413 0.1097 5.9683 ;
		RECT 0.0481 5.9683 0.1097 6.0952 ;
		RECT 0.0481 6.0952 0.1097 6.2222 ;
		RECT 0.0481 6.2222 0.1097 6.3746 ;
		RECT 0.0481 6.3746 0.1097 6.5016 ;
		RECT 0.0481 6.5016 0.1097 6.6413 ;
		RECT 0.0481 6.6413 0.1097 6.7683 ;
		RECT 0.0481 6.7683 0.1097 6.8952 ;
		RECT 0.0481 6.8952 0.1097 7.0222 ;
		RECT 0.0481 7.0222 0.1097 7.1746 ;
		RECT 0.0481 7.1746 0.1097 7.3016 ;
		RECT 0.0481 7.3016 0.1097 7.4413 ;
		RECT 0.0481 7.4413 0.1097 7.5683 ;
		RECT 0.0481 7.5683 0.1097 7.6952 ;
		RECT 0.0481 7.6952 0.1097 7.8222 ;
		RECT 0.0481 7.8222 0.1097 7.9746 ;
		RECT 0.0481 7.9746 0.1097 8.1016 ;
		RECT 0.0481 8.1016 0.1097 8.2413 ;
		RECT 0.0481 8.2413 0.1097 8.3683 ;
		RECT 0.0481 8.3683 0.1097 8.4952 ;
		RECT 0.0481 8.4952 0.1097 8.6222 ;
		RECT 0.0481 8.6222 0.1097 8.7746 ;
		RECT 0.0481 8.7746 0.1097 8.9016 ;
		RECT 0.0481 8.9016 0.1097 9.0413 ;
		RECT 0.0481 9.0413 0.1097 9.1683 ;
		RECT 0.0481 9.1683 0.1097 9.2952 ;
		RECT 0.0481 9.2952 0.1097 9.4222 ;
		RECT 0.0481 9.4222 0.1097 9.5746 ;
		RECT 0.0481 9.5746 0.1097 9.7016 ;
		RECT 0.0481 9.7016 0.1097 9.8413 ;
		RECT 0.0481 9.8413 0.1097 9.9683 ;
		RECT 0.0481 9.9683 0.1097 10.0952 ;
		RECT 0.0481 10.0952 0.1097 10.2222 ;
		RECT 0.0481 10.2222 0.1097 10.3746 ;
		RECT 0.0481 10.3746 0.1097 10.5016 ;
		RECT 0.0481 10.5016 0.1097 10.6413 ;
		RECT 0.0481 10.6413 0.1097 10.7683 ;
		RECT 0.0481 10.7683 0.1097 10.8952 ;
		RECT 0.0481 10.8952 0.1097 11.0222 ;
		RECT 0.0481 11.0222 0.1097 11.1746 ;
		RECT 0.0481 11.1746 0.1097 11.3016 ;
		RECT 0.0481 11.3016 0.1097 11.4413 ;
		RECT 0.0481 11.4413 0.1097 11.5683 ;
		RECT 0.0481 11.5683 0.1097 11.6952 ;
		RECT 0.0481 11.6952 0.1097 11.8222 ;
		RECT 0.0481 11.8222 0.1097 11.9746 ;
		RECT 0.0481 11.9746 0.1097 12.1016 ;
		RECT 0.0481 12.1016 0.1097 12.2413 ;
		RECT 0.0481 12.2413 0.1097 12.3683 ;
		RECT 0.0481 12.3683 0.1097 12.4952 ;
		RECT 0.0481 12.4952 0.1097 12.6222 ;
		RECT 0.0481 12.6222 0.1097 12.7746 ;
		RECT 0.0481 12.7746 0.1097 12.9016 ;
		RECT 0.0481 12.9016 0.1097 13.0413 ;
		RECT 0.0481 13.0413 0.1097 13.1683 ;
		RECT 0.0481 13.1683 0.1097 13.2952 ;
		RECT 0.0481 13.2952 0.1097 13.4222 ;
		RECT 0.0481 13.4222 0.1097 13.5746 ;
		RECT 0.0481 13.5746 0.1097 13.7016 ;
		RECT 0.0481 13.7016 0.1097 13.8413 ;
		RECT 0.0481 13.8413 0.1097 13.9683 ;
		RECT 0.0481 13.9683 0.1097 14.0952 ;
		RECT 0.0481 14.0952 0.1097 14.2222 ;
		RECT 0.0481 14.2222 0.1097 14.3746 ;
		RECT 0.0481 14.3746 0.1097 14.5016 ;
		RECT 0.0481 14.5016 0.1097 14.6413 ;
		RECT 0.0481 14.6413 0.1097 14.7683 ;
		RECT 0.0481 14.7683 0.1097 14.8952 ;
		RECT 0.0481 14.8952 0.1097 15.0222 ;
		RECT 0.0481 15.0222 0.1097 15.1746 ;
		RECT 0.0481 15.1746 0.1097 15.3016 ;
		RECT 0.0481 15.3016 0.1097 15.4413 ;
		RECT 0.0481 15.4413 0.1097 15.5683 ;
		RECT 0.0481 15.5683 0.1097 15.6952 ;
		RECT 0.0481 15.6952 0.1097 15.8222 ;
		RECT 0.0481 15.8222 0.1097 15.9746 ;
		RECT 0.0481 15.9746 0.1097 16.1016 ;
		RECT 0.0481 16.1016 0.1097 16.2413 ;
		RECT 0.0481 16.2413 0.1097 16.3683 ;
		RECT 0.0481 16.3683 0.1097 16.4952 ;
		RECT 0.0481 16.4952 0.1097 16.6222 ;
		RECT 0.0481 16.6222 0.1097 16.7746 ;
		RECT 0.0481 16.7746 0.1097 16.9016 ;
		RECT 0.0481 16.9016 0.1097 17.0413 ;
		RECT 0.0481 17.0413 0.1097 17.1683 ;
		RECT 0.0481 17.1683 0.1097 17.2952 ;
		RECT 0.0481 17.2952 0.1097 17.4222 ;
		RECT 0.0481 17.4222 0.1097 17.5746 ;
		RECT 0.0481 17.5746 0.1097 17.7016 ;
		RECT 0.0481 17.7016 0.1097 18.6857 ;
		RECT 0.0481 18.6857 0.1097 18.8127 ;
		RECT 0.0481 18.8127 0.1097 19.0794 ;
		RECT 0.0481 19.0794 0.1097 19.219 ;
		RECT 0.0481 19.6127 0.1097 19.7524 ;
		RECT 0.0481 23.219 0.1097 23.346 ;
		RECT 0.0481 25.3778 0.1097 25.5048 ;
		RECT 0.0481 25.5048 0.1097 25.6571 ;
		RECT 0.0481 25.6571 0.1097 25.7841 ;
		RECT 0.0481 25.7841 0.1097 25.9111 ;
		RECT 0.0481 25.9111 0.1097 26.0381 ;
		RECT 0.0481 26.0381 0.1097 26.1778 ;
		RECT 0.0481 26.1778 0.1097 26.3048 ;
		RECT 0.0481 26.3048 0.1097 26.4571 ;
		RECT 0.0481 26.4571 0.1097 26.5841 ;
		RECT 0.0481 26.5841 0.1097 26.7111 ;
		RECT 0.0481 26.7111 0.1097 26.8381 ;
		RECT 0.0481 26.8381 0.1097 26.9778 ;
		RECT 0.0481 26.9778 0.1097 27.1048 ;
		RECT 0.0481 27.1048 0.1097 27.2571 ;
		RECT 0.0481 27.2571 0.1097 27.3841 ;
		RECT 0.0481 27.3841 0.1097 27.5111 ;
		RECT 0.0481 27.5111 0.1097 27.6381 ;
		RECT 0.0481 27.6381 0.1097 27.7778 ;
		RECT 0.0481 27.7778 0.1097 27.9048 ;
		RECT 0.0481 27.9048 0.1097 28.0571 ;
		RECT 0.0481 28.0571 0.1097 28.1841 ;
		RECT 0.0481 28.1841 0.1097 28.3111 ;
		RECT 0.0481 28.3111 0.1097 28.4381 ;
		RECT 0.0481 28.4381 0.1097 28.5778 ;
		RECT 0.0481 28.5778 0.1097 28.7048 ;
		RECT 0.0481 28.7048 0.1097 28.8571 ;
		RECT 0.0481 28.8571 0.1097 28.9841 ;
		RECT 0.0481 28.9841 0.1097 29.1111 ;
		RECT 0.0481 29.1111 0.1097 29.2381 ;
		RECT 0.0481 29.2381 0.1097 29.3778 ;
		RECT 0.0481 29.3778 0.1097 29.5048 ;
		RECT 0.0481 29.5048 0.1097 29.6571 ;
		RECT 0.0481 29.6571 0.1097 29.7841 ;
		RECT 0.0481 29.7841 0.1097 29.9111 ;
		RECT 0.0481 29.9111 0.1097 30.0381 ;
		RECT 0.0481 30.0381 0.1097 30.1778 ;
		RECT 0.0481 30.1778 0.1097 30.3048 ;
		RECT 0.0481 30.3048 0.1097 30.4571 ;
		RECT 0.0481 30.4571 0.1097 30.5841 ;
		RECT 0.0481 30.5841 0.1097 30.7111 ;
		RECT 0.0481 30.7111 0.1097 30.8381 ;
		RECT 0.0481 30.8381 0.1097 30.9778 ;
		RECT 0.0481 30.9778 0.1097 31.1048 ;
		RECT 0.0481 31.1048 0.1097 31.2571 ;
		RECT 0.0481 31.2571 0.1097 31.3841 ;
		RECT 0.0481 31.3841 0.1097 31.5111 ;
		RECT 0.0481 31.5111 0.1097 31.6381 ;
		RECT 0.0481 31.6381 0.1097 31.7778 ;
		RECT 0.0481 31.7778 0.1097 31.9048 ;
		RECT 0.0481 31.9048 0.1097 32.0571 ;
		RECT 0.0481 32.0571 0.1097 32.1841 ;
		RECT 0.0481 32.1841 0.1097 32.3111 ;
		RECT 0.0481 32.3111 0.1097 32.4381 ;
		RECT 0.0481 32.4381 0.1097 32.5778 ;
		RECT 0.0481 32.5778 0.1097 32.7048 ;
		RECT 0.0481 32.7048 0.1097 32.8571 ;
		RECT 0.0481 32.8571 0.1097 32.9841 ;
		RECT 0.0481 32.9841 0.1097 33.1111 ;
		RECT 0.0481 33.1111 0.1097 33.2381 ;
		RECT 0.0481 33.2381 0.1097 33.3778 ;
		RECT 0.0481 33.3778 0.1097 33.5048 ;
		RECT 0.0481 33.5048 0.1097 33.6571 ;
		RECT 0.0481 33.6571 0.1097 33.7841 ;
		RECT 0.0481 33.7841 0.1097 33.9111 ;
		RECT 0.0481 33.9111 0.1097 34.0381 ;
		RECT 0.0481 34.0381 0.1097 34.1778 ;
		RECT 0.0481 34.1778 0.1097 34.3048 ;
		RECT 0.0481 34.3048 0.1097 34.4571 ;
		RECT 0.0481 34.4571 0.1097 34.5841 ;
		RECT 0.0481 34.5841 0.1097 34.7111 ;
		RECT 0.0481 34.7111 0.1097 34.8381 ;
		RECT 0.0481 34.8381 0.1097 34.9778 ;
		RECT 0.0481 34.9778 0.1097 35.1048 ;
		RECT 0.0481 35.1048 0.1097 35.2571 ;
		RECT 0.0481 35.2571 0.1097 35.3841 ;
		RECT 0.0481 35.3841 0.1097 35.5111 ;
		RECT 0.0481 35.5111 0.1097 35.6381 ;
		RECT 0.0481 35.6381 0.1097 35.7778 ;
		RECT 0.0481 35.7778 0.1097 35.9048 ;
		RECT 0.0481 35.9048 0.1097 36.0571 ;
		RECT 0.0481 36.0571 0.1097 36.1841 ;
		RECT 0.0481 36.1841 0.1097 36.3111 ;
		RECT 0.0481 36.3111 0.1097 36.4381 ;
		RECT 0.0481 36.4381 0.1097 36.5778 ;
		RECT 0.0481 36.5778 0.1097 36.7048 ;
		RECT 0.0481 36.7048 0.1097 36.8571 ;
		RECT 0.0481 36.8571 0.1097 36.9841 ;
		RECT 0.0481 36.9841 0.1097 37.1111 ;
		RECT 0.0481 37.1111 0.1097 37.2381 ;
		RECT 0.0481 37.2381 0.1097 37.3778 ;
		RECT 0.0481 37.3778 0.1097 37.5048 ;
		RECT 0.0481 37.5048 0.1097 37.6571 ;
		RECT 0.0481 37.6571 0.1097 37.7841 ;
		RECT 0.0481 37.7841 0.1097 37.9111 ;
		RECT 0.0481 37.9111 0.1097 38.0381 ;
		RECT 0.0481 38.0381 0.1097 38.1778 ;
		RECT 0.0481 38.1778 0.1097 38.3048 ;
		RECT 0.0481 38.3048 0.1097 38.4571 ;
		RECT 0.0481 38.4571 0.1097 38.5841 ;
		RECT 0.0481 38.5841 0.1097 38.7111 ;
		RECT 0.0481 38.7111 0.1097 38.8381 ;
		RECT 0.0481 38.8381 0.1097 38.9778 ;
		RECT 0.0481 38.9778 0.1097 39.1048 ;
		RECT 0.0481 39.1048 0.1097 39.2571 ;
		RECT 0.0481 39.2571 0.1097 39.3841 ;
		RECT 0.0481 39.3841 0.1097 39.5111 ;
		RECT 0.0481 39.5111 0.1097 39.6381 ;
		RECT 0.0481 39.6381 0.1097 39.7778 ;
		RECT 0.0481 39.7778 0.1097 39.9048 ;
		RECT 0.0481 39.9048 0.1097 40.0571 ;
		RECT 0.0481 40.0571 0.1097 40.1841 ;
		RECT 0.0481 40.1841 0.1097 40.3111 ;
		RECT 0.0481 40.3111 0.1097 40.4381 ;
		RECT 0.0481 40.4381 0.1097 40.5778 ;
		RECT 0.0481 40.5778 0.1097 40.7048 ;
		RECT 0.0481 40.7048 0.1097 40.8571 ;
		RECT 0.0481 40.8571 0.1097 40.9841 ;
		RECT 0.0481 40.9841 0.1097 41.1111 ;
		RECT 0.0481 41.1111 0.1097 41.2381 ;
		RECT 0.0481 41.2381 0.1097 41.3778 ;
		RECT 0.0481 41.3778 0.1097 41.5048 ;
		RECT 0.0481 41.5048 0.1097 41.6571 ;
		RECT 0.0481 41.6571 0.1097 41.7841 ;
		RECT 0.0481 41.7841 0.1097 41.9111 ;
		RECT 0.0481 41.9111 0.1097 42.0381 ;
		RECT 0.0481 42.0381 0.1097 42.1778 ;
		RECT 0.0481 42.1778 0.1097 42.3048 ;
		RECT 0.0481 42.3048 0.1097 42.4571 ;
		RECT 0.0481 42.4571 0.1097 42.5841 ;
		RECT 0.0481 42.5841 0.1097 42.7111 ;
		RECT 0.0481 42.7111 0.1097 42.8381 ;
		RECT 0.0481 42.8381 0.1097 42.9778 ;
		RECT 0.0481 42.9778 0.1097 43.1048 ;
		RECT 0.0481 43.1048 0.1097 43.2571 ;
		RECT 0.0481 43.2571 0.1097 43.3841 ;
		RECT 0.0481 43.3841 0.1097 43.5111 ;
		RECT 0.0481 43.5111 0.1097 43.6381 ;
		RECT 0.0481 43.6381 0.1097 43.7651 ;
		RECT 0.0831 17.898 0.098 17.9107 ;
		RECT 0.0215 17.9615 0.0364 17.9742 ;
		RECT 0.0831 18.025 0.098 18.0377 ;
		RECT 0.0215 18.0885 0.0364 18.1012 ;
		RECT 0.0831 18.1647 0.098 18.1774 ;
		RECT 0.0215 18.2282 0.0364 18.2409 ;
		RECT 0.0831 18.2917 0.098 18.3044 ;
		RECT 0.0215 18.3552 0.0364 18.3679 ;
		RECT 0.021 18.4948 0.0359 18.5075 ;
		RECT 0.0831 18.5583 0.098 18.571 ;
		RECT 0.0215 18.6218 0.0364 18.6345 ;
		RECT 0.021 19.0282 0.0359 19.0409 ;
		RECT 0.0215 19.2948 0.0364 19.3075 ;
		RECT 0.0831 19.3583 0.098 19.371 ;
		RECT 0.0831 19.498 0.098 19.5107 ;
		RECT 0.0215 19.5615 0.0364 19.5742 ;
		RECT 0.0215 19.9552 0.0364 19.9679 ;
		RECT 0.0831 20.0313 0.098 20.044 ;
		RECT 0.0215 20.2218 0.0364 20.2345 ;
		RECT 0.0831 20.425 0.098 20.4377 ;
		RECT 0.0831 20.5647 0.098 20.5774 ;
		RECT 0.0215 20.6282 0.0364 20.6409 ;
		RECT 0.0215 20.7679 0.0364 20.7806 ;
		RECT 0.0215 20.8948 0.0364 20.9075 ;
		RECT 0.0215 21.0218 0.0364 21.0345 ;
		RECT 0.0831 21.352 0.098 21.3647 ;
		RECT 0.0831 21.4917 0.098 21.5044 ;
		RECT 0.0215 21.5552 0.0364 21.5679 ;
		RECT 0.0831 21.6313 0.098 21.644 ;
		RECT 0.0215 21.6948 0.0364 21.7075 ;
		RECT 0.0831 21.771 0.098 21.7837 ;
		RECT 0.0831 22.025 0.098 22.0377 ;
		RECT 0.0215 22.0885 0.0364 22.1012 ;
		RECT 0.0831 22.1647 0.098 22.1774 ;
		RECT 0.0215 22.2282 0.0364 22.2409 ;
		RECT 0.0831 22.4187 0.098 22.4313 ;
		RECT 0.0215 22.4821 0.0364 22.4948 ;
		RECT 0.0831 22.5583 0.098 22.571 ;
		RECT 0.0831 22.698 0.098 22.7107 ;
		RECT 0.0831 22.8377 0.098 22.8504 ;
		RECT 0.0831 23.0917 0.098 23.1044 ;
		RECT 0.0215 23.1552 0.0364 23.1679 ;
		RECT 0.0831 23.7774 0.098 23.7901 ;
		RECT 0.0831 23.9044 0.098 23.9171 ;
		RECT 0.0215 23.9679 0.0364 23.9806 ;
		RECT 0.0831 24.0567 0.098 24.0694 ;
		RECT 0.0215 24.1202 0.0364 24.1329 ;
		RECT 0.0831 24.1837 0.098 24.1964 ;
		RECT 0.0215 24.2472 0.0364 24.2599 ;
		RECT 0.0831 24.3107 0.098 24.3234 ;
		RECT 0.0831 24.4377 0.098 24.4504 ;
		RECT 0.0215 24.5012 0.0364 24.5139 ;
		RECT 0.0831 24.5647 0.098 24.5774 ;
		RECT 0.0215 24.6282 0.0364 24.6409 ;
		RECT 0.0831 24.6917 0.098 24.7044 ;
		RECT 0.0215 24.7552 0.0364 24.7679 ;
		RECT 0.0831 24.8313 0.098 24.844 ;
		RECT 0.0215 24.8948 0.0364 24.9075 ;
		RECT 0.0831 24.9583 0.098 24.971 ;
		RECT 0.0215 25.0218 0.0364 25.0345 ;
		RECT 0.0831 25.098 0.098 25.1107 ;
		RECT 0.0215 25.1615 0.0364 25.1742 ;
		RECT 0.0831 0.1266 0.098 0.1393 ;
		RECT 0.0831 43.8417 0.098 43.8544 ;
		 LAYER V2 SPACING 0 ;
		RECT 0.0481 0.2413 0.1097 0.3683 ;
		RECT 0.0481 0.3683 0.1097 0.4952 ;
		RECT 0.0481 0.4952 0.1097 0.6222 ;
		RECT 0.0481 0.6222 0.1097 0.7746 ;
		RECT 0.0481 0.7746 0.1097 0.9016 ;
		RECT 0.0481 0.9016 0.1097 1.0413 ;
		RECT 0.0481 1.0413 0.1097 1.1683 ;
		RECT 0.0481 1.1683 0.1097 1.2952 ;
		RECT 0.0481 1.2952 0.1097 1.4222 ;
		RECT 0.0481 1.4222 0.1097 1.5746 ;
		RECT 0.0481 1.5746 0.1097 1.7016 ;
		RECT 0.0481 1.7016 0.1097 1.8413 ;
		RECT 0.0481 1.8413 0.1097 1.9683 ;
		RECT 0.0481 1.9683 0.1097 2.0952 ;
		RECT 0.0481 2.0952 0.1097 2.2222 ;
		RECT 0.0481 2.2222 0.1097 2.3746 ;
		RECT 0.0481 2.3746 0.1097 2.5016 ;
		RECT 0.0481 2.5016 0.1097 2.6413 ;
		RECT 0.0481 2.6413 0.1097 2.7683 ;
		RECT 0.0481 2.7683 0.1097 2.8952 ;
		RECT 0.0481 2.8952 0.1097 3.0222 ;
		RECT 0.0481 3.0222 0.1097 3.1746 ;
		RECT 0.0481 3.1746 0.1097 3.3016 ;
		RECT 0.0481 3.3016 0.1097 3.4413 ;
		RECT 0.0481 3.4413 0.1097 3.5683 ;
		RECT 0.0481 3.5683 0.1097 3.6952 ;
		RECT 0.0481 3.6952 0.1097 3.8222 ;
		RECT 0.0481 3.8222 0.1097 3.9746 ;
		RECT 0.0481 3.9746 0.1097 4.1016 ;
		RECT 0.0481 4.1016 0.1097 4.2413 ;
		RECT 0.0481 4.2413 0.1097 4.3683 ;
		RECT 0.0481 4.3683 0.1097 4.4952 ;
		RECT 0.0481 4.4952 0.1097 4.6222 ;
		RECT 0.0481 4.6222 0.1097 4.7746 ;
		RECT 0.0481 4.7746 0.1097 4.9016 ;
		RECT 0.0481 4.9016 0.1097 5.0413 ;
		RECT 0.0481 5.0413 0.1097 5.1683 ;
		RECT 0.0481 5.1683 0.1097 5.2952 ;
		RECT 0.0481 5.2952 0.1097 5.4222 ;
		RECT 0.0481 5.4222 0.1097 5.5746 ;
		RECT 0.0481 5.5746 0.1097 5.7016 ;
		RECT 0.0481 5.7016 0.1097 5.8413 ;
		RECT 0.0481 5.8413 0.1097 5.9683 ;
		RECT 0.0481 5.9683 0.1097 6.0952 ;
		RECT 0.0481 6.0952 0.1097 6.2222 ;
		RECT 0.0481 6.2222 0.1097 6.3746 ;
		RECT 0.0481 6.3746 0.1097 6.5016 ;
		RECT 0.0481 6.5016 0.1097 6.6413 ;
		RECT 0.0481 6.6413 0.1097 6.7683 ;
		RECT 0.0481 6.7683 0.1097 6.8952 ;
		RECT 0.0481 6.8952 0.1097 7.0222 ;
		RECT 0.0481 7.0222 0.1097 7.1746 ;
		RECT 0.0481 7.1746 0.1097 7.3016 ;
		RECT 0.0481 7.3016 0.1097 7.4413 ;
		RECT 0.0481 7.4413 0.1097 7.5683 ;
		RECT 0.0481 7.5683 0.1097 7.6952 ;
		RECT 0.0481 7.6952 0.1097 7.8222 ;
		RECT 0.0481 7.8222 0.1097 7.9746 ;
		RECT 0.0481 7.9746 0.1097 8.1016 ;
		RECT 0.0481 8.1016 0.1097 8.2413 ;
		RECT 0.0481 8.2413 0.1097 8.3683 ;
		RECT 0.0481 8.3683 0.1097 8.4952 ;
		RECT 0.0481 8.4952 0.1097 8.6222 ;
		RECT 0.0481 8.6222 0.1097 8.7746 ;
		RECT 0.0481 8.7746 0.1097 8.9016 ;
		RECT 0.0481 8.9016 0.1097 9.0413 ;
		RECT 0.0481 9.0413 0.1097 9.1683 ;
		RECT 0.0481 9.1683 0.1097 9.2952 ;
		RECT 0.0481 9.2952 0.1097 9.4222 ;
		RECT 0.0481 9.4222 0.1097 9.5746 ;
		RECT 0.0481 9.5746 0.1097 9.7016 ;
		RECT 0.0481 9.7016 0.1097 9.8413 ;
		RECT 0.0481 9.8413 0.1097 9.9683 ;
		RECT 0.0481 9.9683 0.1097 10.0952 ;
		RECT 0.0481 10.0952 0.1097 10.2222 ;
		RECT 0.0481 10.2222 0.1097 10.3746 ;
		RECT 0.0481 10.3746 0.1097 10.5016 ;
		RECT 0.0481 10.5016 0.1097 10.6413 ;
		RECT 0.0481 10.6413 0.1097 10.7683 ;
		RECT 0.0481 10.7683 0.1097 10.8952 ;
		RECT 0.0481 10.8952 0.1097 11.0222 ;
		RECT 0.0481 11.0222 0.1097 11.1746 ;
		RECT 0.0481 11.1746 0.1097 11.3016 ;
		RECT 0.0481 11.3016 0.1097 11.4413 ;
		RECT 0.0481 11.4413 0.1097 11.5683 ;
		RECT 0.0481 11.5683 0.1097 11.6952 ;
		RECT 0.0481 11.6952 0.1097 11.8222 ;
		RECT 0.0481 11.8222 0.1097 11.9746 ;
		RECT 0.0481 11.9746 0.1097 12.1016 ;
		RECT 0.0481 12.1016 0.1097 12.2413 ;
		RECT 0.0481 12.2413 0.1097 12.3683 ;
		RECT 0.0481 12.3683 0.1097 12.4952 ;
		RECT 0.0481 12.4952 0.1097 12.6222 ;
		RECT 0.0481 12.6222 0.1097 12.7746 ;
		RECT 0.0481 12.7746 0.1097 12.9016 ;
		RECT 0.0481 12.9016 0.1097 13.0413 ;
		RECT 0.0481 13.0413 0.1097 13.1683 ;
		RECT 0.0481 13.1683 0.1097 13.2952 ;
		RECT 0.0481 13.2952 0.1097 13.4222 ;
		RECT 0.0481 13.4222 0.1097 13.5746 ;
		RECT 0.0481 13.5746 0.1097 13.7016 ;
		RECT 0.0481 13.7016 0.1097 13.8413 ;
		RECT 0.0481 13.8413 0.1097 13.9683 ;
		RECT 0.0481 13.9683 0.1097 14.0952 ;
		RECT 0.0481 14.0952 0.1097 14.2222 ;
		RECT 0.0481 14.2222 0.1097 14.3746 ;
		RECT 0.0481 14.3746 0.1097 14.5016 ;
		RECT 0.0481 14.5016 0.1097 14.6413 ;
		RECT 0.0481 14.6413 0.1097 14.7683 ;
		RECT 0.0481 14.7683 0.1097 14.8952 ;
		RECT 0.0481 14.8952 0.1097 15.0222 ;
		RECT 0.0481 15.0222 0.1097 15.1746 ;
		RECT 0.0481 15.1746 0.1097 15.3016 ;
		RECT 0.0481 15.3016 0.1097 15.4413 ;
		RECT 0.0481 15.4413 0.1097 15.5683 ;
		RECT 0.0481 15.5683 0.1097 15.6952 ;
		RECT 0.0481 15.6952 0.1097 15.8222 ;
		RECT 0.0481 15.8222 0.1097 15.9746 ;
		RECT 0.0481 15.9746 0.1097 16.1016 ;
		RECT 0.0481 16.1016 0.1097 16.2413 ;
		RECT 0.0481 16.2413 0.1097 16.3683 ;
		RECT 0.0481 16.3683 0.1097 16.4952 ;
		RECT 0.0481 16.4952 0.1097 16.6222 ;
		RECT 0.0481 16.6222 0.1097 16.7746 ;
		RECT 0.0481 16.7746 0.1097 16.9016 ;
		RECT 0.0481 16.9016 0.1097 17.0413 ;
		RECT 0.0481 17.0413 0.1097 17.1683 ;
		RECT 0.0481 17.1683 0.1097 17.2952 ;
		RECT 0.0481 17.2952 0.1097 17.4222 ;
		RECT 0.0481 17.4222 0.1097 17.5746 ;
		RECT 0.0481 17.5746 0.1097 17.7016 ;
		RECT 0.0481 17.7016 0.1097 18.6857 ;
		RECT 0.0481 18.6857 0.1097 18.8127 ;
		RECT 0.0481 18.8127 0.1097 19.0794 ;
		RECT 0.0481 19.0794 0.1097 19.219 ;
		RECT 0.0481 19.6127 0.1097 19.7524 ;
		RECT 0.0481 23.219 0.1097 23.346 ;
		RECT 0.0481 25.3778 0.1097 25.5048 ;
		RECT 0.0481 25.5048 0.1097 25.6571 ;
		RECT 0.0481 25.6571 0.1097 25.7841 ;
		RECT 0.0481 25.7841 0.1097 25.9111 ;
		RECT 0.0481 25.9111 0.1097 26.0381 ;
		RECT 0.0481 26.0381 0.1097 26.1778 ;
		RECT 0.0481 26.1778 0.1097 26.3048 ;
		RECT 0.0481 26.3048 0.1097 26.4571 ;
		RECT 0.0481 26.4571 0.1097 26.5841 ;
		RECT 0.0481 26.5841 0.1097 26.7111 ;
		RECT 0.0481 26.7111 0.1097 26.8381 ;
		RECT 0.0481 26.8381 0.1097 26.9778 ;
		RECT 0.0481 26.9778 0.1097 27.1048 ;
		RECT 0.0481 27.1048 0.1097 27.2571 ;
		RECT 0.0481 27.2571 0.1097 27.3841 ;
		RECT 0.0481 27.3841 0.1097 27.5111 ;
		RECT 0.0481 27.5111 0.1097 27.6381 ;
		RECT 0.0481 27.6381 0.1097 27.7778 ;
		RECT 0.0481 27.7778 0.1097 27.9048 ;
		RECT 0.0481 27.9048 0.1097 28.0571 ;
		RECT 0.0481 28.0571 0.1097 28.1841 ;
		RECT 0.0481 28.1841 0.1097 28.3111 ;
		RECT 0.0481 28.3111 0.1097 28.4381 ;
		RECT 0.0481 28.4381 0.1097 28.5778 ;
		RECT 0.0481 28.5778 0.1097 28.7048 ;
		RECT 0.0481 28.7048 0.1097 28.8571 ;
		RECT 0.0481 28.8571 0.1097 28.9841 ;
		RECT 0.0481 28.9841 0.1097 29.1111 ;
		RECT 0.0481 29.1111 0.1097 29.2381 ;
		RECT 0.0481 29.2381 0.1097 29.3778 ;
		RECT 0.0481 29.3778 0.1097 29.5048 ;
		RECT 0.0481 29.5048 0.1097 29.6571 ;
		RECT 0.0481 29.6571 0.1097 29.7841 ;
		RECT 0.0481 29.7841 0.1097 29.9111 ;
		RECT 0.0481 29.9111 0.1097 30.0381 ;
		RECT 0.0481 30.0381 0.1097 30.1778 ;
		RECT 0.0481 30.1778 0.1097 30.3048 ;
		RECT 0.0481 30.3048 0.1097 30.4571 ;
		RECT 0.0481 30.4571 0.1097 30.5841 ;
		RECT 0.0481 30.5841 0.1097 30.7111 ;
		RECT 0.0481 30.7111 0.1097 30.8381 ;
		RECT 0.0481 30.8381 0.1097 30.9778 ;
		RECT 0.0481 30.9778 0.1097 31.1048 ;
		RECT 0.0481 31.1048 0.1097 31.2571 ;
		RECT 0.0481 31.2571 0.1097 31.3841 ;
		RECT 0.0481 31.3841 0.1097 31.5111 ;
		RECT 0.0481 31.5111 0.1097 31.6381 ;
		RECT 0.0481 31.6381 0.1097 31.7778 ;
		RECT 0.0481 31.7778 0.1097 31.9048 ;
		RECT 0.0481 31.9048 0.1097 32.0571 ;
		RECT 0.0481 32.0571 0.1097 32.1841 ;
		RECT 0.0481 32.1841 0.1097 32.3111 ;
		RECT 0.0481 32.3111 0.1097 32.4381 ;
		RECT 0.0481 32.4381 0.1097 32.5778 ;
		RECT 0.0481 32.5778 0.1097 32.7048 ;
		RECT 0.0481 32.7048 0.1097 32.8571 ;
		RECT 0.0481 32.8571 0.1097 32.9841 ;
		RECT 0.0481 32.9841 0.1097 33.1111 ;
		RECT 0.0481 33.1111 0.1097 33.2381 ;
		RECT 0.0481 33.2381 0.1097 33.3778 ;
		RECT 0.0481 33.3778 0.1097 33.5048 ;
		RECT 0.0481 33.5048 0.1097 33.6571 ;
		RECT 0.0481 33.6571 0.1097 33.7841 ;
		RECT 0.0481 33.7841 0.1097 33.9111 ;
		RECT 0.0481 33.9111 0.1097 34.0381 ;
		RECT 0.0481 34.0381 0.1097 34.1778 ;
		RECT 0.0481 34.1778 0.1097 34.3048 ;
		RECT 0.0481 34.3048 0.1097 34.4571 ;
		RECT 0.0481 34.4571 0.1097 34.5841 ;
		RECT 0.0481 34.5841 0.1097 34.7111 ;
		RECT 0.0481 34.7111 0.1097 34.8381 ;
		RECT 0.0481 34.8381 0.1097 34.9778 ;
		RECT 0.0481 34.9778 0.1097 35.1048 ;
		RECT 0.0481 35.1048 0.1097 35.2571 ;
		RECT 0.0481 35.2571 0.1097 35.3841 ;
		RECT 0.0481 35.3841 0.1097 35.5111 ;
		RECT 0.0481 35.5111 0.1097 35.6381 ;
		RECT 0.0481 35.6381 0.1097 35.7778 ;
		RECT 0.0481 35.7778 0.1097 35.9048 ;
		RECT 0.0481 35.9048 0.1097 36.0571 ;
		RECT 0.0481 36.0571 0.1097 36.1841 ;
		RECT 0.0481 36.1841 0.1097 36.3111 ;
		RECT 0.0481 36.3111 0.1097 36.4381 ;
		RECT 0.0481 36.4381 0.1097 36.5778 ;
		RECT 0.0481 36.5778 0.1097 36.7048 ;
		RECT 0.0481 36.7048 0.1097 36.8571 ;
		RECT 0.0481 36.8571 0.1097 36.9841 ;
		RECT 0.0481 36.9841 0.1097 37.1111 ;
		RECT 0.0481 37.1111 0.1097 37.2381 ;
		RECT 0.0481 37.2381 0.1097 37.3778 ;
		RECT 0.0481 37.3778 0.1097 37.5048 ;
		RECT 0.0481 37.5048 0.1097 37.6571 ;
		RECT 0.0481 37.6571 0.1097 37.7841 ;
		RECT 0.0481 37.7841 0.1097 37.9111 ;
		RECT 0.0481 37.9111 0.1097 38.0381 ;
		RECT 0.0481 38.0381 0.1097 38.1778 ;
		RECT 0.0481 38.1778 0.1097 38.3048 ;
		RECT 0.0481 38.3048 0.1097 38.4571 ;
		RECT 0.0481 38.4571 0.1097 38.5841 ;
		RECT 0.0481 38.5841 0.1097 38.7111 ;
		RECT 0.0481 38.7111 0.1097 38.8381 ;
		RECT 0.0481 38.8381 0.1097 38.9778 ;
		RECT 0.0481 38.9778 0.1097 39.1048 ;
		RECT 0.0481 39.1048 0.1097 39.2571 ;
		RECT 0.0481 39.2571 0.1097 39.3841 ;
		RECT 0.0481 39.3841 0.1097 39.5111 ;
		RECT 0.0481 39.5111 0.1097 39.6381 ;
		RECT 0.0481 39.6381 0.1097 39.7778 ;
		RECT 0.0481 39.7778 0.1097 39.9048 ;
		RECT 0.0481 39.9048 0.1097 40.0571 ;
		RECT 0.0481 40.0571 0.1097 40.1841 ;
		RECT 0.0481 40.1841 0.1097 40.3111 ;
		RECT 0.0481 40.3111 0.1097 40.4381 ;
		RECT 0.0481 40.4381 0.1097 40.5778 ;
		RECT 0.0481 40.5778 0.1097 40.7048 ;
		RECT 0.0481 40.7048 0.1097 40.8571 ;
		RECT 0.0481 40.8571 0.1097 40.9841 ;
		RECT 0.0481 40.9841 0.1097 41.1111 ;
		RECT 0.0481 41.1111 0.1097 41.2381 ;
		RECT 0.0481 41.2381 0.1097 41.3778 ;
		RECT 0.0481 41.3778 0.1097 41.5048 ;
		RECT 0.0481 41.5048 0.1097 41.6571 ;
		RECT 0.0481 41.6571 0.1097 41.7841 ;
		RECT 0.0481 41.7841 0.1097 41.9111 ;
		RECT 0.0481 41.9111 0.1097 42.0381 ;
		RECT 0.0481 42.0381 0.1097 42.1778 ;
		RECT 0.0481 42.1778 0.1097 42.3048 ;
		RECT 0.0481 42.3048 0.1097 42.4571 ;
		RECT 0.0481 42.4571 0.1097 42.5841 ;
		RECT 0.0481 42.5841 0.1097 42.7111 ;
		RECT 0.0481 42.7111 0.1097 42.8381 ;
		RECT 0.0481 42.8381 0.1097 42.9778 ;
		RECT 0.0481 42.9778 0.1097 43.1048 ;
		RECT 0.0481 43.1048 0.1097 43.2571 ;
		RECT 0.0481 43.2571 0.1097 43.3841 ;
		RECT 0.0481 43.3841 0.1097 43.5111 ;
		RECT 0.0481 43.5111 0.1097 43.6381 ;
		RECT 0.0481 43.6381 0.1097 43.7651 ;
		RECT 0.0831 17.898 0.098 17.9107 ;
		RECT 0.0215 17.9615 0.0364 17.9742 ;
		RECT 0.0831 18.025 0.098 18.0377 ;
		RECT 0.0215 18.0885 0.0364 18.1012 ;
		RECT 0.0831 18.1647 0.098 18.1774 ;
		RECT 0.0215 18.2282 0.0364 18.2409 ;
		RECT 0.0831 18.2917 0.098 18.3044 ;
		RECT 0.0215 18.3552 0.0364 18.3679 ;
		RECT 0.021 18.4948 0.0359 18.5075 ;
		RECT 0.0831 18.5583 0.098 18.571 ;
		RECT 0.0215 18.6218 0.0364 18.6345 ;
		RECT 0.021 19.0282 0.0359 19.0409 ;
		RECT 0.0215 19.2948 0.0364 19.3075 ;
		RECT 0.0831 19.3583 0.098 19.371 ;
		RECT 0.0831 19.498 0.098 19.5107 ;
		RECT 0.0215 19.5615 0.0364 19.5742 ;
		RECT 0.0215 19.9552 0.0364 19.9679 ;
		RECT 0.0831 20.0313 0.098 20.044 ;
		RECT 0.0215 20.2218 0.0364 20.2345 ;
		RECT 0.0831 20.425 0.098 20.4377 ;
		RECT 0.0831 20.5647 0.098 20.5774 ;
		RECT 0.0215 20.6282 0.0364 20.6409 ;
		RECT 0.0215 20.7679 0.0364 20.7806 ;
		RECT 0.0215 20.8948 0.0364 20.9075 ;
		RECT 0.0215 21.0218 0.0364 21.0345 ;
		RECT 0.0831 21.352 0.098 21.3647 ;
		RECT 0.0831 21.4917 0.098 21.5044 ;
		RECT 0.0215 21.5552 0.0364 21.5679 ;
		RECT 0.0831 21.6313 0.098 21.644 ;
		RECT 0.0215 21.6948 0.0364 21.7075 ;
		RECT 0.0831 21.771 0.098 21.7837 ;
		RECT 0.0831 22.025 0.098 22.0377 ;
		RECT 0.0215 22.0885 0.0364 22.1012 ;
		RECT 0.0831 22.1647 0.098 22.1774 ;
		RECT 0.0215 22.2282 0.0364 22.2409 ;
		RECT 0.0831 22.4187 0.098 22.4313 ;
		RECT 0.0215 22.4821 0.0364 22.4948 ;
		RECT 0.0831 22.5583 0.098 22.571 ;
		RECT 0.0831 22.698 0.098 22.7107 ;
		RECT 0.0831 22.8377 0.098 22.8504 ;
		RECT 0.0831 23.0917 0.098 23.1044 ;
		RECT 0.0215 23.1552 0.0364 23.1679 ;
		RECT 0.0831 23.7774 0.098 23.7901 ;
		RECT 0.0831 23.9044 0.098 23.9171 ;
		RECT 0.0215 23.9679 0.0364 23.9806 ;
		RECT 0.0831 24.0567 0.098 24.0694 ;
		RECT 0.0215 24.1202 0.0364 24.1329 ;
		RECT 0.0831 24.1837 0.098 24.1964 ;
		RECT 0.0215 24.2472 0.0364 24.2599 ;
		RECT 0.0831 24.3107 0.098 24.3234 ;
		RECT 0.0831 24.4377 0.098 24.4504 ;
		RECT 0.0215 24.5012 0.0364 24.5139 ;
		RECT 0.0831 24.5647 0.098 24.5774 ;
		RECT 0.0215 24.6282 0.0364 24.6409 ;
		RECT 0.0831 24.6917 0.098 24.7044 ;
		RECT 0.0215 24.7552 0.0364 24.7679 ;
		RECT 0.0831 24.8313 0.098 24.844 ;
		RECT 0.0215 24.8948 0.0364 24.9075 ;
		RECT 0.0831 24.9583 0.098 24.971 ;
		RECT 0.0215 25.0218 0.0364 25.0345 ;
		RECT 0.0831 25.098 0.098 25.1107 ;
		RECT 0.0215 25.1615 0.0364 25.1742 ;
		RECT 0.0831 0.1266 0.098 0.1393 ;
		RECT 0.0831 43.8417 0.098 43.8544 ;
		 LAYER V3 SPACING 0 ;
		RECT 0.3271 18.6087 0.3421 18.6214 ;
		RECT 0.2917 18.9032 0.3066 18.9159 ;
		RECT 0.3271 18.9508 0.3421 18.9635 ;
		RECT 0.2917 18.9984 0.3066 19.0111 ;
		RECT 0.3271 19.046 0.3421 19.0587 ;
		RECT 0.2562 19.0937 0.2711 19.1063 ;
		RECT 0.2917 19.1413 0.3066 19.154 ;
		RECT 0.3271 19.4841 0.3421 19.4968 ;
		RECT 0.2917 19.5794 0.3066 19.5921 ;
		RECT 0.3271 19.627 0.3421 19.6397 ;
		RECT 0.2917 19.6746 0.3066 19.6873 ;
		RECT 0.2562 19.9698 0.2711 19.9825 ;
		RECT 0.3271 20.0175 0.3421 20.0302 ;
		RECT 0.2917 20.0651 0.3066 20.0778 ;
		RECT 0.3271 20.1603 0.3421 20.173 ;
		RECT 0.2917 20.5032 0.3066 20.5159 ;
		RECT 0.3271 20.5508 0.3421 20.5635 ;
		RECT 0.2917 20.5984 0.3066 20.6111 ;
		RECT 0.3271 20.646 0.3421 20.6587 ;
		RECT 0.2917 20.6937 0.3066 20.7063 ;
		RECT 0.2917 21.0365 0.3066 21.0492 ;
		RECT 0.2917 21.1317 0.3066 21.1444 ;
		RECT 0.3271 21.2413 0.3421 21.273 ;
		RECT 0.2917 21.6651 0.3066 21.6778 ;
		RECT 0.3953 21.7127 0.4102 21.7254 ;
		RECT 0.3271 21.7603 0.3421 21.773 ;
		RECT 0.2917 21.8079 0.3066 21.8206 ;
		RECT 0.3271 22.1508 0.3421 22.1635 ;
		RECT 0.2562 22.2937 0.2711 22.3063 ;
		RECT 0.2917 22.3413 0.3066 22.354 ;
		RECT 0.3271 22.3976 0.3421 22.4103 ;
		RECT 0.2618 22.4452 0.2767 22.4579 ;
		RECT 0.2945 22.4929 0.3094 22.5056 ;
		RECT 0.2618 22.7317 0.2767 22.7444 ;
		RECT 0.2618 22.8746 0.2767 22.8873 ;
		RECT 0.3271 23.1698 0.3421 23.1825 ;
		RECT 0.2618 23.2175 0.2767 23.2302 ;
		RECT 0.3271 23.2651 0.3421 23.2778 ;
		RECT 0.2618 23.3127 0.2767 23.3254 ;
		RECT 0.3271 23.3127 0.3421 23.3254 ;
		RECT 0.2291 23.3603 0.2441 23.373 ;
		RECT 0.3271 23.4079 0.3421 23.4206 ;
		RECT 0.2562 23.7032 0.2711 23.7159 ;
		RECT 0.3271 23.846 0.3421 23.8587 ;
		RECT 0.2562 23.8937 0.2711 23.9063 ;
		RECT 0.3271 23.9413 0.3421 23.954 ;
		RECT 0.3271 24.2365 0.3421 24.2492 ;
		RECT 0.2562 24.2841 0.2711 24.2968 ;
		RECT 0.2917 24.3317 0.3066 24.3444 ;
		RECT 0.2562 24.3794 0.2711 24.3921 ;
		RECT 0.2917 24.4746 0.3066 24.4873 ;
		RECT 0.2562 24.8492 0.2711 24.8619 ;
		RECT 0.4387 1.4127 0.4536 1.4444 ;
		RECT 0.4387 8.6127 0.4536 8.6444 ;
		RECT 0.4387 9.4127 0.4536 9.4444 ;
		RECT 0.4387 10.2127 0.4536 10.2444 ;
		RECT 0.4387 11.0127 0.4536 11.0444 ;
		RECT 0.4387 11.8127 0.4536 11.8444 ;
		RECT 0.4387 12.6127 0.4536 12.6444 ;
		RECT 0.4387 13.4127 0.4536 13.4444 ;
		RECT 0.4387 14.2127 0.4536 14.2444 ;
		RECT 0.4387 15.0127 0.4536 15.0444 ;
		RECT 0.4387 15.8127 0.4536 15.8444 ;
		RECT 0.4387 2.2127 0.4536 2.2444 ;
		RECT 0.4387 16.6127 0.4536 16.6444 ;
		RECT 0.4387 3.0127 0.4536 3.0444 ;
		RECT 0.4387 3.8127 0.4536 3.8444 ;
		RECT 0.4387 4.6127 0.4536 4.6444 ;
		RECT 0.4387 5.4127 0.4536 5.4444 ;
		RECT 0.4387 6.2127 0.4536 6.2444 ;
		RECT 0.4387 7.0127 0.4536 7.0444 ;
		RECT 0.4387 7.8127 0.4536 7.8444 ;
		RECT 0.4387 0.6127 0.4536 0.6444 ;
		RECT 0.4387 17.4127 0.4536 17.4444 ;
		RECT 0.4387 26.5365 0.4536 26.5683 ;
		RECT 0.4387 33.7365 0.4536 33.7683 ;
		RECT 0.4387 34.5365 0.4536 34.5683 ;
		RECT 0.4387 35.3365 0.4536 35.3683 ;
		RECT 0.4387 36.1365 0.4536 36.1683 ;
		RECT 0.4387 36.9365 0.4536 36.9683 ;
		RECT 0.4387 37.7365 0.4536 37.7683 ;
		RECT 0.4387 38.5365 0.4536 38.5683 ;
		RECT 0.4387 39.3365 0.4536 39.3683 ;
		RECT 0.4387 40.1365 0.4536 40.1683 ;
		RECT 0.4387 40.9365 0.4536 40.9683 ;
		RECT 0.4387 27.3365 0.4536 27.3683 ;
		RECT 0.4387 41.7365 0.4536 41.7683 ;
		RECT 0.4387 42.5365 0.4536 42.5683 ;
		RECT 0.4387 28.1365 0.4536 28.1683 ;
		RECT 0.4387 28.9365 0.4536 28.9683 ;
		RECT 0.4387 29.7365 0.4536 29.7683 ;
		RECT 0.4387 30.5365 0.4536 30.5683 ;
		RECT 0.4387 31.3365 0.4536 31.3683 ;
		RECT 0.4387 32.1365 0.4536 32.1683 ;
		RECT 0.4387 32.9365 0.4536 32.9683 ;
		RECT 0.4387 25.7365 0.4536 25.7683 ;
		RECT 0.4387 43.3365 0.4536 43.3683 ;
		RECT 1.5223 18.2032 1.5372 18.2159 ;
		RECT 2.6213 18.2921 2.6362 18.3238 ;
		RECT 1.4593 18.3016 1.4966 18.3143 ;
		RECT 1.9334 18.3016 1.9707 18.3143 ;
		RECT 3.367 18.3016 3.4043 18.3143 ;
		RECT 1.8466 18.5286 1.8615 18.5413 ;
		RECT 3.2373 18.5286 3.2522 18.5413 ;
		RECT 4.5127 18.5286 4.5276 18.5413 ;
		RECT 2.2078 18.6087 2.2227 18.6214 ;
		RECT 2.6213 18.8254 2.6362 18.8571 ;
		RECT 1.9334 18.8349 1.9707 18.8476 ;
		RECT 3.367 18.8349 3.4043 18.8476 ;
		RECT 4.5547 18.9984 4.592 19.0111 ;
		RECT 2.6805 19.1413 2.6955 19.154 ;
		RECT 3.5 19.1413 3.5149 19.154 ;
		RECT 2.6213 19.3587 2.6362 19.3905 ;
		RECT 3.3768 19.3587 3.3917 19.3905 ;
		RECT 1.9334 19.3683 1.9707 19.381 ;
		RECT 3.1425 19.5317 3.1575 19.5444 ;
		RECT 3.5 19.5317 3.5149 19.5444 ;
		RECT 1.7486 19.5794 1.7635 19.5921 ;
		RECT 3.9466 19.5794 3.9615 19.5921 ;
		RECT 2.5093 19.627 2.5242 19.6397 ;
		RECT 1.8825 19.6746 1.8975 19.6873 ;
		RECT 2.6213 19.8921 2.6362 19.9238 ;
		RECT 1.9334 19.9016 1.9707 19.9143 ;
		RECT 3.367 19.9016 3.4043 19.9143 ;
		RECT 1.5283 19.9698 1.5433 19.9825 ;
		RECT 3.6918 19.9698 3.7067 19.9825 ;
		RECT 3.9937 20.1127 4.0087 20.1254 ;
		RECT 1.9577 20.4254 1.9726 20.4571 ;
		RECT 2.6213 20.4254 2.6362 20.4571 ;
		RECT 3.367 20.4349 3.4043 20.4476 ;
		RECT 1.7486 20.5984 1.7635 20.6111 ;
		RECT 2.5419 20.5984 2.5569 20.6111 ;
		RECT 3.5 20.5984 3.5149 20.6111 ;
		RECT 4.5547 20.5984 4.592 20.6111 ;
		RECT 3.4613 20.6937 3.4762 20.7063 ;
		RECT 4.27 20.7413 4.2849 20.754 ;
		RECT 2.6213 20.9587 2.6362 20.9905 ;
		RECT 1.9577 20.9683 1.9726 20.981 ;
		RECT 3.367 20.9683 3.4043 20.981 ;
		RECT 2.2419 21.0841 2.2568 21.0968 ;
		RECT 2.4766 21.0841 2.4915 21.0968 ;
		RECT 3.0072 21.3222 3.0221 21.3349 ;
		RECT 2.6213 21.4921 2.6362 21.5238 ;
		RECT 1.9577 21.5016 1.9726 21.5143 ;
		RECT 3.367 21.5016 3.4043 21.5143 ;
		RECT 2.4439 21.6175 2.4589 21.6302 ;
		RECT 4.1062 21.6175 4.1211 21.6302 ;
		RECT 4.2812 21.6175 4.2961 21.6302 ;
		RECT 4.5547 21.6651 4.592 21.6778 ;
		RECT 2.0025 21.8079 2.0174 21.8206 ;
		RECT 3.5481 21.8079 3.563 21.8206 ;
		RECT 4.2812 21.8079 4.2961 21.8206 ;
		RECT 2.6213 22.0254 2.6362 22.0571 ;
		RECT 1.9577 22.0349 1.9726 22.0476 ;
		RECT 3.367 22.0349 3.4043 22.0476 ;
		RECT 2.5093 22.1032 2.5242 22.1159 ;
		RECT 2.7244 22.1032 2.7393 22.1159 ;
		RECT 3.6563 22.1032 3.6713 22.1159 ;
		RECT 4.2159 22.1032 4.2308 22.1159 ;
		RECT 4.5127 22.1032 4.5276 22.1159 ;
		RECT 2.7244 22.1508 2.7393 22.1635 ;
		RECT 3.6563 22.1508 3.6713 22.1635 ;
		RECT 4.5547 22.1508 4.592 22.1635 ;
		RECT 3.2704 22.2937 3.2853 22.3063 ;
		RECT 4.5785 22.2937 4.5934 22.3063 ;
		RECT 2.6213 22.5587 2.6362 22.5905 ;
		RECT 1.9334 22.5683 1.9707 22.581 ;
		RECT 3.367 22.5683 3.4043 22.581 ;
		RECT 2.0025 22.6365 2.0174 22.6492 ;
		RECT 2.4766 22.6365 2.4915 22.6492 ;
		RECT 2.1089 22.827 2.1238 22.8397 ;
		RECT 2.7244 22.827 2.7393 22.8397 ;
		RECT 3.6563 22.827 3.6713 22.8397 ;
		RECT 4.5547 22.827 4.592 22.8397 ;
		RECT 2.6213 23.0921 2.6362 23.1238 ;
		RECT 1.9334 23.1016 1.9707 23.1143 ;
		RECT 3.367 23.1016 3.4043 23.1143 ;
		RECT 4.5547 23.2175 4.592 23.2302 ;
		RECT 3.3185 23.3127 3.3334 23.3254 ;
		RECT 1.7593 23.6254 1.7743 23.6571 ;
		RECT 2.6213 23.6254 2.6362 23.6571 ;
		RECT 1.9334 23.6349 1.9707 23.6476 ;
		RECT 3.367 23.6349 3.4043 23.6476 ;
		RECT 4.5547 23.9413 4.592 23.954 ;
		RECT 4.5547 24.2841 4.592 24.2968 ;
		RECT 1.8494 24.3794 1.8643 24.3921 ;
		RECT 2.3581 24.427 2.373 24.4397 ;
		RECT 4.1575 24.427 4.1725 24.4397 ;
		RECT 1.8466 24.8492 1.8615 24.8619 ;
		RECT 3.2373 24.8492 3.2522 24.8619 ;
		RECT 4.5127 24.8492 4.5276 24.8619 ;
		RECT 1.652 25.0683 1.6893 25.081 ;
		RECT 1.9334 25.0683 1.9707 25.081 ;
		RECT 2.5415 25.0683 2.5564 25.081 ;
		RECT 3.367 25.0683 3.4043 25.081 ;
		RECT 0.7971 18.2921 0.812 18.3238 ;
		RECT 0.5521 18.6087 0.567 18.6214 ;
		RECT 0.8461 18.6087 0.861 18.6214 ;
		RECT 0.9114 18.8254 0.9263 18.8571 ;
		RECT 0.5847 18.9032 0.5997 18.9159 ;
		RECT 1.2054 18.9508 1.2203 18.9635 ;
		RECT 1.3361 19.046 1.351 19.0587 ;
		RECT 1.0747 19.0937 1.0897 19.1063 ;
		RECT 0.6501 19.4841 0.665 19.4968 ;
		RECT 0.9767 19.5317 0.9917 19.5444 ;
		RECT 0.8787 19.6746 0.8937 19.6873 ;
		RECT 1.3034 19.6746 1.3183 19.6873 ;
		RECT 0.8134 19.8921 0.8283 19.9238 ;
		RECT 0.5847 19.9698 0.5997 19.9825 ;
		RECT 0.8787 20.0651 0.8937 20.0778 ;
		RECT 1.3034 20.1603 1.3183 20.173 ;
		RECT 0.8134 20.4254 0.8283 20.4571 ;
		RECT 1.0094 20.5032 1.0243 20.5159 ;
		RECT 0.5847 20.5508 0.5997 20.5635 ;
		RECT 0.8787 20.646 0.8937 20.6587 ;
		RECT 0.8134 20.9587 0.8283 20.9905 ;
		RECT 0.7154 21.0365 0.7303 21.0492 ;
		RECT 0.9767 21.2413 0.9917 21.273 ;
		RECT 0.8787 21.3222 0.8937 21.3349 ;
		RECT 0.8134 21.4921 0.8283 21.5238 ;
		RECT 0.5847 21.7603 0.5997 21.773 ;
		RECT 0.8787 21.8079 0.8937 21.8206 ;
		RECT 1.3034 21.8079 1.3183 21.8206 ;
		RECT 0.8134 22.0254 0.8283 22.0571 ;
		RECT 0.5847 22.3413 0.5997 22.354 ;
		RECT 0.7154 22.4929 0.7303 22.5056 ;
		RECT 0.8134 22.5587 0.8283 22.5905 ;
		RECT 0.9767 22.7317 0.9917 22.7444 ;
		RECT 0.9767 22.8746 0.9917 22.8873 ;
		RECT 0.8134 23.0921 0.8283 23.1238 ;
		RECT 1.0094 23.1698 1.0243 23.1825 ;
		RECT 0.6174 23.2175 0.6323 23.2302 ;
		RECT 0.9767 23.2651 0.9917 23.2778 ;
		RECT 0.6174 23.4079 0.6323 23.4206 ;
		RECT 0.8134 23.6254 0.8283 23.6571 ;
		RECT 0.7154 23.7032 0.7303 23.7159 ;
		RECT 1.0421 23.846 1.057 23.8587 ;
		RECT 0.7154 23.8937 0.7303 23.9063 ;
		RECT 0.8134 24.1587 0.8283 24.1905 ;
		RECT 0.7154 24.2365 0.7303 24.2492 ;
		RECT 0.8461 24.3317 0.861 24.3444 ;
		RECT 1.3361 24.3317 1.351 24.3444 ;
		RECT 0.6501 24.4746 0.665 24.4873 ;
		RECT 0.7971 1.4127 0.812 1.4444 ;
		RECT 0.7971 8.6127 0.812 8.6444 ;
		RECT 0.7971 9.4127 0.812 9.4444 ;
		RECT 0.7971 10.2127 0.812 10.2444 ;
		RECT 0.7971 11.0127 0.812 11.0444 ;
		RECT 0.7971 11.8127 0.812 11.8444 ;
		RECT 0.7971 12.6127 0.812 12.6444 ;
		RECT 0.7971 13.4127 0.812 13.4444 ;
		RECT 0.7971 14.2127 0.812 14.2444 ;
		RECT 0.7971 15.0127 0.812 15.0444 ;
		RECT 0.7971 15.8127 0.812 15.8444 ;
		RECT 0.7971 2.2127 0.812 2.2444 ;
		RECT 0.7971 16.6127 0.812 16.6444 ;
		RECT 0.7971 3.0127 0.812 3.0444 ;
		RECT 0.7971 3.8127 0.812 3.8444 ;
		RECT 0.7971 4.6127 0.812 4.6444 ;
		RECT 0.7971 5.4127 0.812 5.4444 ;
		RECT 0.7971 6.2127 0.812 6.2444 ;
		RECT 0.7971 7.0127 0.812 7.0444 ;
		RECT 0.7971 7.8127 0.812 7.8444 ;
		RECT 0.7971 0.6127 0.812 0.6444 ;
		RECT 0.7971 17.4127 0.812 17.4444 ;
		RECT 1.5535 1.4127 1.5685 1.4444 ;
		RECT 2.5415 1.4127 2.5564 1.4444 ;
		RECT 2.8373 1.4127 2.8523 1.4444 ;
		RECT 3.3782 1.4127 3.3931 1.4444 ;
		RECT 1.5535 8.6127 1.5685 8.6444 ;
		RECT 2.5415 8.6127 2.5564 8.6444 ;
		RECT 2.8373 8.6127 2.8523 8.6444 ;
		RECT 3.3782 8.6127 3.3931 8.6444 ;
		RECT 1.5535 9.4127 1.5685 9.4444 ;
		RECT 2.5415 9.4127 2.5564 9.4444 ;
		RECT 2.8373 9.4127 2.8523 9.4444 ;
		RECT 3.3782 9.4127 3.3931 9.4444 ;
		RECT 1.5535 10.2127 1.5685 10.2444 ;
		RECT 2.5415 10.2127 2.5564 10.2444 ;
		RECT 2.8373 10.2127 2.8523 10.2444 ;
		RECT 3.3782 10.2127 3.3931 10.2444 ;
		RECT 1.5535 11.0127 1.5685 11.0444 ;
		RECT 2.5415 11.0127 2.5564 11.0444 ;
		RECT 2.8373 11.0127 2.8523 11.0444 ;
		RECT 3.3782 11.0127 3.3931 11.0444 ;
		RECT 1.5535 11.8127 1.5685 11.8444 ;
		RECT 2.5415 11.8127 2.5564 11.8444 ;
		RECT 2.8373 11.8127 2.8523 11.8444 ;
		RECT 3.3782 11.8127 3.3931 11.8444 ;
		RECT 1.5535 12.6127 1.5685 12.6444 ;
		RECT 2.5415 12.6127 2.5564 12.6444 ;
		RECT 2.8373 12.6127 2.8523 12.6444 ;
		RECT 3.3782 12.6127 3.3931 12.6444 ;
		RECT 1.5535 13.4127 1.5685 13.4444 ;
		RECT 2.5415 13.4127 2.5564 13.4444 ;
		RECT 2.8373 13.4127 2.8523 13.4444 ;
		RECT 3.3782 13.4127 3.3931 13.4444 ;
		RECT 1.5535 14.2127 1.5685 14.2444 ;
		RECT 2.5415 14.2127 2.5564 14.2444 ;
		RECT 2.8373 14.2127 2.8523 14.2444 ;
		RECT 3.3782 14.2127 3.3931 14.2444 ;
		RECT 1.5535 15.0127 1.5685 15.0444 ;
		RECT 2.5415 15.0127 2.5564 15.0444 ;
		RECT 2.8373 15.0127 2.8523 15.0444 ;
		RECT 3.3782 15.0127 3.3931 15.0444 ;
		RECT 1.5535 15.8127 1.5685 15.8444 ;
		RECT 2.5415 15.8127 2.5564 15.8444 ;
		RECT 2.8373 15.8127 2.8523 15.8444 ;
		RECT 3.3782 15.8127 3.3931 15.8444 ;
		RECT 1.5535 2.2127 1.5685 2.2444 ;
		RECT 2.5415 2.2127 2.5564 2.2444 ;
		RECT 2.8373 2.2127 2.8523 2.2444 ;
		RECT 3.3782 2.2127 3.3931 2.2444 ;
		RECT 1.5535 16.6127 1.5685 16.6444 ;
		RECT 2.5415 16.6127 2.5564 16.6444 ;
		RECT 2.8373 16.6127 2.8523 16.6444 ;
		RECT 3.3782 16.6127 3.3931 16.6444 ;
		RECT 1.5535 3.0127 1.5685 3.0444 ;
		RECT 2.5415 3.0127 2.5564 3.0444 ;
		RECT 2.8373 3.0127 2.8523 3.0444 ;
		RECT 3.3782 3.0127 3.3931 3.0444 ;
		RECT 1.5535 3.8127 1.5685 3.8444 ;
		RECT 2.5415 3.8127 2.5564 3.8444 ;
		RECT 2.8373 3.8127 2.8523 3.8444 ;
		RECT 3.3782 3.8127 3.3931 3.8444 ;
		RECT 1.5535 4.6127 1.5685 4.6444 ;
		RECT 2.5415 4.6127 2.5564 4.6444 ;
		RECT 2.8373 4.6127 2.8523 4.6444 ;
		RECT 3.3782 4.6127 3.3931 4.6444 ;
		RECT 1.5535 5.4127 1.5685 5.4444 ;
		RECT 2.5415 5.4127 2.5564 5.4444 ;
		RECT 2.8373 5.4127 2.8523 5.4444 ;
		RECT 3.3782 5.4127 3.3931 5.4444 ;
		RECT 1.5535 6.2127 1.5685 6.2444 ;
		RECT 2.5415 6.2127 2.5564 6.2444 ;
		RECT 2.8373 6.2127 2.8523 6.2444 ;
		RECT 3.3782 6.2127 3.3931 6.2444 ;
		RECT 1.5535 7.0127 1.5685 7.0444 ;
		RECT 2.5415 7.0127 2.5564 7.0444 ;
		RECT 2.8373 7.0127 2.8523 7.0444 ;
		RECT 3.3782 7.0127 3.3931 7.0444 ;
		RECT 1.5535 7.8127 1.5685 7.8444 ;
		RECT 2.5415 7.8127 2.5564 7.8444 ;
		RECT 2.8373 7.8127 2.8523 7.8444 ;
		RECT 3.3782 7.8127 3.3931 7.8444 ;
		RECT 1.5535 0.6127 1.5685 0.6444 ;
		RECT 2.5415 0.6127 2.5564 0.6444 ;
		RECT 2.8373 0.6127 2.8523 0.6444 ;
		RECT 3.3782 0.6127 3.3931 0.6444 ;
		RECT 1.5535 17.4127 1.5685 17.4444 ;
		RECT 2.5415 17.4127 2.5564 17.4444 ;
		RECT 2.8373 17.4127 2.8523 17.4444 ;
		RECT 3.3782 17.4127 3.3931 17.4444 ;
		RECT 0.7971 26.5365 0.812 26.5683 ;
		RECT 0.7971 33.7365 0.812 33.7683 ;
		RECT 0.7971 34.5365 0.812 34.5683 ;
		RECT 0.7971 35.3365 0.812 35.3683 ;
		RECT 0.7971 36.1365 0.812 36.1683 ;
		RECT 0.7971 36.9365 0.812 36.9683 ;
		RECT 0.7971 37.7365 0.812 37.7683 ;
		RECT 0.7971 38.5365 0.812 38.5683 ;
		RECT 0.7971 39.3365 0.812 39.3683 ;
		RECT 0.7971 40.1365 0.812 40.1683 ;
		RECT 0.7971 40.9365 0.812 40.9683 ;
		RECT 0.7971 27.3365 0.812 27.3683 ;
		RECT 0.7971 41.7365 0.812 41.7683 ;
		RECT 0.7971 42.5365 0.812 42.5683 ;
		RECT 0.7971 28.1365 0.812 28.1683 ;
		RECT 0.7971 28.9365 0.812 28.9683 ;
		RECT 0.7971 29.7365 0.812 29.7683 ;
		RECT 0.7971 30.5365 0.812 30.5683 ;
		RECT 0.7971 31.3365 0.812 31.3683 ;
		RECT 0.7971 32.1365 0.812 32.1683 ;
		RECT 0.7971 32.9365 0.812 32.9683 ;
		RECT 0.7971 25.7365 0.812 25.7683 ;
		RECT 0.7971 43.3365 0.812 43.3683 ;
		RECT 1.5535 26.5365 1.5685 26.5683 ;
		RECT 2.5415 26.5365 2.5564 26.5683 ;
		RECT 2.8373 26.5365 2.8523 26.5683 ;
		RECT 3.3782 26.5365 3.3931 26.5683 ;
		RECT 1.5535 33.7365 1.5685 33.7683 ;
		RECT 2.5415 33.7365 2.5564 33.7683 ;
		RECT 2.8373 33.7365 2.8523 33.7683 ;
		RECT 3.3782 33.7365 3.3931 33.7683 ;
		RECT 1.5535 34.5365 1.5685 34.5683 ;
		RECT 2.5415 34.5365 2.5564 34.5683 ;
		RECT 2.8373 34.5365 2.8523 34.5683 ;
		RECT 3.3782 34.5365 3.3931 34.5683 ;
		RECT 1.5535 35.3365 1.5685 35.3683 ;
		RECT 2.5415 35.3365 2.5564 35.3683 ;
		RECT 2.8373 35.3365 2.8523 35.3683 ;
		RECT 3.3782 35.3365 3.3931 35.3683 ;
		RECT 1.5535 36.1365 1.5685 36.1683 ;
		RECT 2.5415 36.1365 2.5564 36.1683 ;
		RECT 2.8373 36.1365 2.8523 36.1683 ;
		RECT 3.3782 36.1365 3.3931 36.1683 ;
		RECT 1.5535 36.9365 1.5685 36.9683 ;
		RECT 2.5415 36.9365 2.5564 36.9683 ;
		RECT 2.8373 36.9365 2.8523 36.9683 ;
		RECT 3.3782 36.9365 3.3931 36.9683 ;
		RECT 1.5535 37.7365 1.5685 37.7683 ;
		RECT 2.5415 37.7365 2.5564 37.7683 ;
		RECT 2.8373 37.7365 2.8523 37.7683 ;
		RECT 3.3782 37.7365 3.3931 37.7683 ;
		RECT 1.5535 38.5365 1.5685 38.5683 ;
		RECT 2.5415 38.5365 2.5564 38.5683 ;
		RECT 2.8373 38.5365 2.8523 38.5683 ;
		RECT 3.3782 38.5365 3.3931 38.5683 ;
		RECT 1.5535 39.3365 1.5685 39.3683 ;
		RECT 2.5415 39.3365 2.5564 39.3683 ;
		RECT 2.8373 39.3365 2.8523 39.3683 ;
		RECT 3.3782 39.3365 3.3931 39.3683 ;
		RECT 1.5535 40.1365 1.5685 40.1683 ;
		RECT 2.5415 40.1365 2.5564 40.1683 ;
		RECT 2.8373 40.1365 2.8523 40.1683 ;
		RECT 3.3782 40.1365 3.3931 40.1683 ;
		RECT 1.5535 40.9365 1.5685 40.9683 ;
		RECT 2.5415 40.9365 2.5564 40.9683 ;
		RECT 2.8373 40.9365 2.8523 40.9683 ;
		RECT 3.3782 40.9365 3.3931 40.9683 ;
		RECT 1.5535 27.3365 1.5685 27.3683 ;
		RECT 2.5415 27.3365 2.5564 27.3683 ;
		RECT 2.8373 27.3365 2.8523 27.3683 ;
		RECT 3.3782 27.3365 3.3931 27.3683 ;
		RECT 1.5535 41.7365 1.5685 41.7683 ;
		RECT 2.5415 41.7365 2.5564 41.7683 ;
		RECT 2.8373 41.7365 2.8523 41.7683 ;
		RECT 3.3782 41.7365 3.3931 41.7683 ;
		RECT 1.5535 42.5365 1.5685 42.5683 ;
		RECT 2.5415 42.5365 2.5564 42.5683 ;
		RECT 2.8373 42.5365 2.8523 42.5683 ;
		RECT 3.3782 42.5365 3.3931 42.5683 ;
		RECT 1.5535 28.1365 1.5685 28.1683 ;
		RECT 2.5415 28.1365 2.5564 28.1683 ;
		RECT 2.8373 28.1365 2.8523 28.1683 ;
		RECT 3.3782 28.1365 3.3931 28.1683 ;
		RECT 1.5535 28.9365 1.5685 28.9683 ;
		RECT 2.5415 28.9365 2.5564 28.9683 ;
		RECT 2.8373 28.9365 2.8523 28.9683 ;
		RECT 3.3782 28.9365 3.3931 28.9683 ;
		RECT 1.5535 29.7365 1.5685 29.7683 ;
		RECT 2.5415 29.7365 2.5564 29.7683 ;
		RECT 2.8373 29.7365 2.8523 29.7683 ;
		RECT 3.3782 29.7365 3.3931 29.7683 ;
		RECT 1.5535 30.5365 1.5685 30.5683 ;
		RECT 2.5415 30.5365 2.5564 30.5683 ;
		RECT 2.8373 30.5365 2.8523 30.5683 ;
		RECT 3.3782 30.5365 3.3931 30.5683 ;
		RECT 1.5535 31.3365 1.5685 31.3683 ;
		RECT 2.5415 31.3365 2.5564 31.3683 ;
		RECT 2.8373 31.3365 2.8523 31.3683 ;
		RECT 3.3782 31.3365 3.3931 31.3683 ;
		RECT 1.5535 32.1365 1.5685 32.1683 ;
		RECT 2.5415 32.1365 2.5564 32.1683 ;
		RECT 2.8373 32.1365 2.8523 32.1683 ;
		RECT 3.3782 32.1365 3.3931 32.1683 ;
		RECT 1.5535 32.9365 1.5685 32.9683 ;
		RECT 2.5415 32.9365 2.5564 32.9683 ;
		RECT 2.8373 32.9365 2.8523 32.9683 ;
		RECT 3.3782 32.9365 3.3931 32.9683 ;
		RECT 1.5535 25.7365 1.5685 25.7683 ;
		RECT 2.5415 25.7365 2.5564 25.7683 ;
		RECT 2.8373 25.7365 2.8523 25.7683 ;
		RECT 3.3782 25.7365 3.3931 25.7683 ;
		RECT 1.5535 43.3365 1.5685 43.3683 ;
		RECT 2.5415 43.3365 2.5564 43.3683 ;
		RECT 2.8373 43.3365 2.8523 43.3683 ;
		RECT 3.3782 43.3365 3.3931 43.3683 ;
		RECT 4.7861 18.9984 4.8235 19.0111 ;
		RECT 4.893 18.9984 4.9303 19.0111 ;
		RECT 4.9112 19.1413 4.9261 19.154 ;
		RECT 4.9765 19.3587 4.9915 19.3905 ;
		RECT 5.0745 19.3587 5.0895 19.3905 ;
		RECT 4.7143 19.4841 4.7292 19.4968 ;
		RECT 5.1072 19.5317 5.1221 19.5444 ;
		RECT 5.0419 19.5794 5.0568 19.5921 ;
		RECT 4.9112 19.8921 4.9261 19.9238 ;
		RECT 5.1072 19.9698 5.1221 19.9825 ;
		RECT 4.7861 20.5984 4.8235 20.6111 ;
		RECT 4.9765 20.646 4.9915 20.6587 ;
		RECT 5.1725 20.6937 5.1875 20.7063 ;
		RECT 5.0419 20.7413 5.0568 20.754 ;
		RECT 4.7143 20.9587 4.7292 20.9905 ;
		RECT 4.9765 21.3222 4.9915 21.3349 ;
		RECT 4.7143 21.4921 4.7292 21.5238 ;
		RECT 4.7861 21.6651 4.8235 21.6778 ;
		RECT 5.0092 22.0254 5.0241 22.0571 ;
		RECT 4.7861 22.1508 4.8235 22.1635 ;
		RECT 4.7861 22.2937 4.8235 22.3063 ;
		RECT 5.0092 22.5587 5.0241 22.5905 ;
		RECT 4.8477 22.6365 4.8627 22.6492 ;
		RECT 5.1072 22.6365 5.1221 22.6492 ;
		RECT 4.7861 22.827 4.8235 22.8397 ;
		RECT 4.7861 23.2175 4.8235 23.2302 ;
		RECT 4.9112 23.6254 4.9261 23.6571 ;
		RECT 5.0092 23.6254 5.0241 23.6571 ;
		RECT 4.7861 23.9413 4.8235 23.954 ;
		RECT 4.7861 24.2841 4.8235 24.2968 ;
		RECT 4.893 24.2841 4.9079 24.2968 ;
		RECT 5.1072 24.2841 5.1221 24.2968 ;
		RECT 5.1399 24.3794 5.1548 24.3921 ;
		RECT 4.7973 24.454 4.8123 24.4857 ;
		RECT 4.893 24.454 4.9079 24.4857 ;
		RECT 5.1072 24.454 5.1221 24.4857 ;
		RECT 4.7031 24.4746 4.718 24.4873 ;
		RECT 4.8496 25.1246 4.8645 25.1373 ;
		RECT 6.6915 18.9984 6.7065 19.0111 ;
		RECT 6.6915 19.4841 6.7065 19.4968 ;
		RECT 6.8101 19.9698 6.825 19.9825 ;
		RECT 6.5665 20.6937 6.5814 20.7063 ;
		RECT 6.6915 24.2841 6.7065 24.2968 ;
		RECT 6.6915 24.454 6.7065 24.4857 ;
		RECT 7.0275 18.9984 7.0425 19.0111 ;
		RECT 7.0275 19.4841 7.0425 19.4968 ;
		RECT 7.1461 19.9698 7.161 19.9825 ;
		RECT 6.9025 20.6937 6.9174 20.7063 ;
		RECT 7.0275 24.2841 7.0425 24.2968 ;
		RECT 7.0275 24.454 7.0425 24.4857 ;
		RECT 7.3635 18.9984 7.3785 19.0111 ;
		RECT 7.3635 19.4841 7.3785 19.4968 ;
		RECT 7.4821 19.9698 7.497 19.9825 ;
		RECT 7.2385 20.6937 7.2534 20.7063 ;
		RECT 7.3635 24.2841 7.3785 24.2968 ;
		RECT 7.3635 24.454 7.3785 24.4857 ;
		RECT 5.8515 19.1413 5.8665 19.154 ;
		RECT 6.188 19.5317 6.2029 19.5444 ;
		RECT 5.474 19.9698 5.4889 19.9825 ;
		RECT 5.222 20.1127 5.2369 20.1254 ;
		RECT 6.2207 20.4254 6.2356 20.4571 ;
		RECT 6.5077 20.4254 6.5226 20.4571 ;
		RECT 6.188 20.5984 6.2029 20.6111 ;
		RECT 6.3999 20.5984 6.4148 20.6111 ;
		RECT 6.0195 20.6937 6.0345 20.7063 ;
		RECT 5.2267 20.9587 5.2416 20.9905 ;
		RECT 6.1045 20.9587 6.1194 20.9905 ;
		RECT 5.7675 22.5587 5.7825 22.5905 ;
		RECT 8.0789 18.9984 8.1163 19.0111 ;
		RECT 8.2549 18.9984 8.2922 19.0111 ;
		RECT 8.0789 19.4841 8.1163 19.4968 ;
		RECT 8.2549 19.4841 8.2922 19.4968 ;
		RECT 8.3179 19.9698 8.3328 19.9825 ;
		RECT 8.0155 20.1127 8.0304 20.1254 ;
		RECT 8.1405 20.6937 8.1555 20.7063 ;
		RECT 8.0509 21.7127 8.0659 21.7254 ;
		RECT 8.1405 23.3127 8.1555 23.3254 ;
		RECT 8.0789 24.2841 8.1163 24.2968 ;
		RECT 8.2549 24.2841 8.2922 24.2968 ;
		RECT 8.0901 24.454 8.1051 24.4857 ;
		RECT 8.2661 24.454 8.281 24.4857 ;
		RECT 7.6995 18.9984 7.7145 19.0111 ;
		RECT 7.6995 19.4841 7.7145 19.4968 ;
		RECT 7.8181 19.9698 7.833 19.9825 ;
		RECT 7.5745 20.6937 7.5894 20.7063 ;
		RECT 7.6995 24.2841 7.7145 24.2968 ;
		RECT 7.6995 24.454 7.7145 24.4857 ;
	END

END RF_128X45M4B1

END LIBRARY

